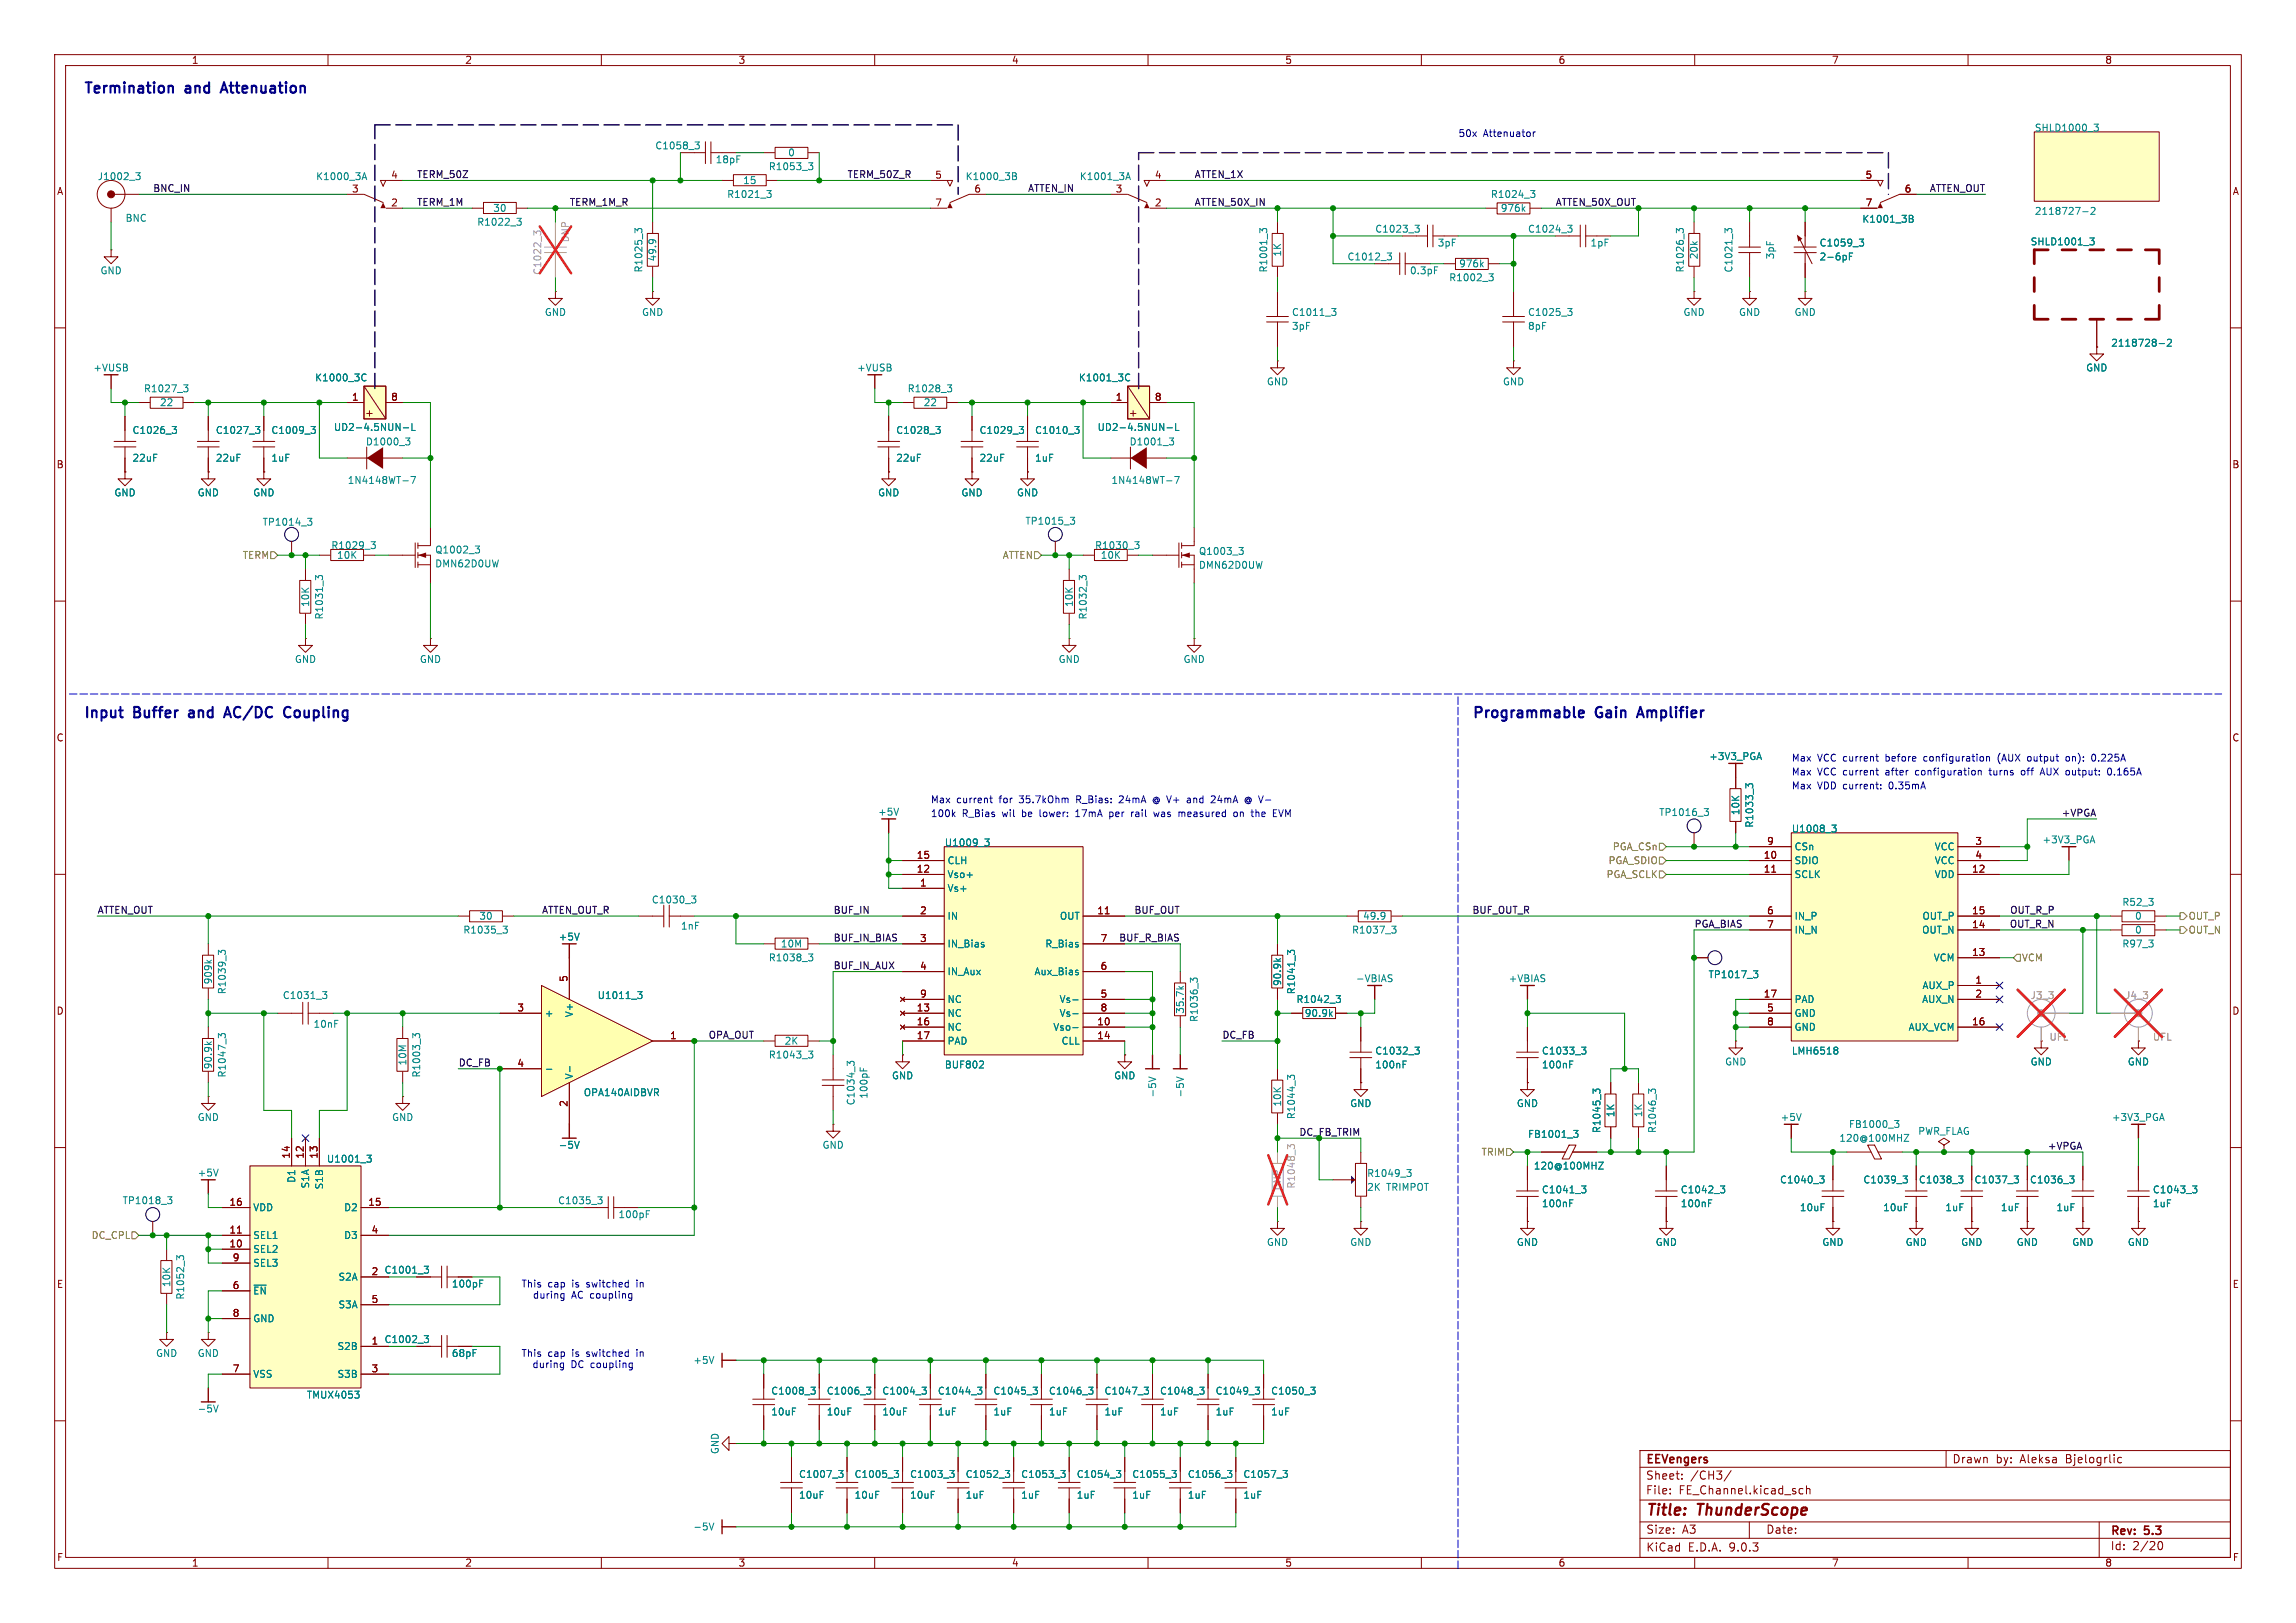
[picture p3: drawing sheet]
<svg xmlns="http://www.w3.org/2000/svg" width="420mm" height="297mm" viewBox="0 0 420 297" stroke-linecap="round" stroke-linejoin="round" font-family="sans-serif">
<defs><g id="words">
<g font-size="2.8" fill="#840000">
<text x="301" y="277.9">Title:</text>
<text x="310.6" y="277.9">ThunderScope</text>
</g>
<g font-size="2.7" fill="#0000c2">
<text x="15.2" y="18">Termination</text>
<text x="34.1" y="18">and</text>
<text x="41.4" y="18">Attenuation</text>
<text x="15.2" y="132.3">Input</text>
<text x="24.6" y="132.3">Buffer</text>
<text x="35.5" y="132.3">and</text>
<text x="42.8" y="132.3">AC/DC</text>
<text x="54.4" y="132.3">Coupling</text>
<text x="269.2" y="132.3">Programmable</text>
<text x="292" y="132.3">Gain</text>
<text x="300.5" y="132.3">Amplifier</text>
</g>
<g font-size="2.1" fill="#840000">
<text x="301" y="268.2">EEVengers</text>
<text x="357.1" y="268">Drawn</text>
<text x="365.1" y="268">by:</text>
<text x="369.6" y="268">Aleksa</text>
<text x="378" y="268">Bjelogrlic</text>
<text x="301" y="273.7">File:</text>
<text x="301" y="271">Sheet:</text>
<text x="307.1" y="273.7">FE_Channel.kicad_sch</text>
<text x="309.2" y="271">/CH3/</text>
<text x="301" y="280.9">Size:</text>
<text x="307.7" y="280.9">A3</text>
<text x="323" y="280.9">Date:</text>
<text x="386" y="281.3">Rev:</text>
<text x="392.4" y="281.3">5.3</text>
<text x="301" y="284.1">KiCad</text>
<text x="308.8" y="284.1">E.D.A.</text>
<text x="316.4" y="284.1">9.0.3</text>
<text x="386" y="283.9">Id:</text>
<text x="390.1" y="283.9">2/20</text>
</g>
<g font-size="1.8" fill="#840000">
<text x="35" y="11.9">1</text>
<text x="85" y="11.9">2</text>
<text x="135" y="11.9">3</text>
<text x="185" y="11.9">4</text>
<text x="235" y="11.9">5</text>
<text x="285" y="11.9">6</text>
<text x="335" y="11.9">7</text>
<text x="385" y="11.9">8</text>
<text x="10.3" y="35.9">A</text>
<text x="64.3" y="35.3">3</text>
<text x="71.5" y="32.8">4</text>
<text x="171" y="32.8">5</text>
<text x="178.1" y="35.3">6</text>
<text x="204" y="35.3">3</text>
<text x="211.2" y="32.8">4</text>
<text x="341.2" y="32.8">5</text>
<text x="348.3" y="35.3">6</text>
<text x="408.3" y="35.9">A</text>
<text x="71.5" y="37.8">2</text>
<text x="171" y="37.8">7</text>
<text x="211.2" y="37.8">2</text>
<text x="341.2" y="37.8">7</text>
<text x="64.3" y="73.4">1</text>
<text x="71.5" y="73.4">8</text>
<text x="204" y="73.4">1</text>
<text x="211.2" y="73.4">8</text>
<text x="10.3" y="85.9">B</text>
<text x="408.2" y="85.9">B</text>
<text x="10.3" y="135.9">C</text>
<text x="408.2" y="135.9">C</text>
<text x="323.1" y="154.7">9</text>
<text x="361.2" y="154.7">3</text>
<text x="167.6" y="157.2">15</text>
<text x="167.6" y="159.8">12</text>
<text x="322.5" y="157.2">10</text>
<text x="322.5" y="159.8">11</text>
<text x="360.6" y="159.8">12</text>
<text x="361.2" y="157.2">4</text>
<text x="168.2" y="162.3">1</text>
<text x="168.2" y="167.4">2</text>
<text x="200.6" y="167.4">11</text>
<text x="323.1" y="167.4">6</text>
<text x="360.6" y="167.4">15</text>
<text x="168.2" y="172.5">3</text>
<text x="201.2" y="172.5">7</text>
<text x="323.1" y="169.9">7</text>
<text x="360.6" y="169.9">14</text>
<text x="103.9" y="179.8" transform="rotate(-90 103.9 179.8)">5</text>
<text x="168.2" y="177.5">4</text>
<text x="201.2" y="177.5">6</text>
<text x="360.6" y="175">13</text>
<text x="10.3" y="185.9">D</text>
<text x="94.5" y="185.2">3</text>
<text x="167.6" y="185.2">13</text>
<text x="168.2" y="182.6">9</text>
<text x="201.2" y="182.6">5</text>
<text x="201.2" y="185.2">8</text>
<text x="322.5" y="182.6">17</text>
<text x="323.1" y="185.2">5</text>
<text x="361.2" y="180.1">1</text>
<text x="361.2" y="182.6">2</text>
<text x="408.2" y="185.9">D</text>
<text x="122.5" y="190.2">1</text>
<text x="167.6" y="187.7">16</text>
<text x="167.6" y="190.2">17</text>
<text x="200.6" y="187.7">10</text>
<text x="200.6" y="190.2">14</text>
<text x="323.1" y="187.7">8</text>
<text x="360.6" y="187.7">16</text>
<text x="94.5" y="195.3">4</text>
<text x="103.9" y="202.6" transform="rotate(-90 103.9 202.6)">2</text>
<text x="53.1" y="212.1" transform="rotate(-90 53.1 212.1)">14</text>
<text x="55.6" y="212.1" transform="rotate(-90 55.6 212.1)">12</text>
<text x="58.2" y="212.1" transform="rotate(-90 58.2 212.1)">13</text>
<text x="41.9" y="220.7">16</text>
<text x="67.3" y="220.7">15</text>
<text x="41.9" y="225.8">11</text>
<text x="67.9" y="225.8">4</text>
<text x="41.9" y="228.3">10</text>
<text x="42.5" y="230.9">9</text>
<text x="67.9" y="233.4">2</text>
<text x="10.3" y="235.9">E</text>
<text x="42.5" y="236">6</text>
<text x="67.9" y="238.5">5</text>
<text x="408.3" y="235.9">E</text>
<text x="42.5" y="241">8</text>
<text x="42.5" y="251.2">7</text>
<text x="67.9" y="246.1">1</text>
<text x="67.9" y="251.2">3</text>
<text x="10.3" y="285.9">F</text>
<text x="35" y="286.9">1</text>
<text x="85" y="286.9">2</text>
<text x="135" y="286.9">3</text>
<text x="185" y="286.9">4</text>
<text x="235" y="286.9">5</text>
<text x="285" y="286.9">6</text>
<text x="335" y="286.9">7</text>
<text x="385" y="286.9">8</text>
<text x="408.3" y="285.9">F</text>
</g>
<g font-size="1.8" fill="#008484">
<text x="119.8" y="27.5">C1058_3</text>
<text x="144.1" y="28.8">0</text>
<text x="372.1" y="24.3">SHLD1000_3</text>
<text x="17.8" y="33.2">J1002_3</text>
<text x="57.7" y="33.2">K1000_3A</text>
<text x="130.8" y="30.1">18pF</text>
<text x="135.8" y="33.9">15</text>
<text x="140.5" y="31.3">R1053_3</text>
<text x="176.5" y="33.2">K1000_3B</text>
<text x="197.4" y="33.2">K1001_3A</text>
<text x="22.9" y="40.8">BNC</text>
<text x="87.2" y="41.5">R1022_3</text>
<text x="90.1" y="39">30</text>
<text x="132.9" y="36.4">R1021_3</text>
<text x="272.6" y="36.4">R1024_3</text>
<text x="274.4" y="39">976k</text>
<text x="340.6" y="41">K1001_3B</text>
<text x="372.1" y="39.5">2118727-2</text>
<text x="120.2" y="47.9" transform="rotate(-90 120.2 47.9)">49.9</text>
<text x="234.5" y="47.1" transform="rotate(-90 234.5 47.1)">1K</text>
<text x="246.4" y="47.9">C1012_3</text>
<text x="251.5" y="42.8">C1023_3</text>
<text x="262.9" y="45.3">3pF</text>
<text x="279.4" y="42.8">C1024_3</text>
<text x="290.8" y="45.3">1pF</text>
<text x="310.7" y="47.5" transform="rotate(-90 310.7 47.5)">20k</text>
<text x="324.7" y="47.5" transform="rotate(-90 324.7 47.5)">3pF</text>
<text x="332.7" y="45.3">C1059_3</text>
<text x="332.7" y="47.9">2-6pF</text>
<text x="371.4" y="45.1">SHLD1001_3</text>
<text x="18.3" y="50.4">GND</text>
<text x="117.7" y="50" transform="rotate(-90 117.7 50)">R1025_3</text>
<text x="232" y="50" transform="rotate(-90 232 50)">R1001_3</text>
<text x="257.8" y="50.4">0.3pF</text>
<text x="265" y="51.7">R1002_3</text>
<text x="266.8" y="49.1">976k</text>
<text x="308.2" y="50" transform="rotate(-90 308.2 50)">R1026_3</text>
<text x="317.1" y="50" transform="rotate(-90 317.1 50)">C1021_3</text>
<text x="99.6" y="58">GND</text>
<text x="117.3" y="58">GND</text>
<text x="236.2" y="58">C1011_3</text>
<text x="279.4" y="58">C1025_3</text>
<text x="307.8" y="58">GND</text>
<text x="318" y="58">GND</text>
<text x="328.2" y="58">GND</text>
<text x="236.2" y="60.6">3pF</text>
<text x="279.4" y="60.6">8pF</text>
<text x="386.1" y="63.6">2118728-2</text>
<text x="17" y="68.2">+VUSB</text>
<text x="26.2" y="72">R1027_3</text>
<text x="57.5" y="70">K1000_3C</text>
<text x="156.7" y="68.2">+VUSB</text>
<text x="165.9" y="72">R1028_3</text>
<text x="197.2" y="70">K1001_3C</text>
<text x="231.6" y="70.7">GND</text>
<text x="274.8" y="70.7">GND</text>
<text x="381.5" y="68.2">GND</text>
<text x="29.2" y="74.5">22</text>
<text x="168.9" y="74.5">22</text>
<text x="24.1" y="79.6">C1026_3</text>
<text x="39.4" y="79.6">C1027_3</text>
<text x="49.5" y="79.6">C1009_3</text>
<text x="61" y="79.1">UD2-4.5NUN-L</text>
<text x="66.8" y="81.7">D1000_3</text>
<text x="163.8" y="79.6">C1028_3</text>
<text x="179.1" y="79.6">C1029_3</text>
<text x="189.2" y="79.6">C1010_3</text>
<text x="200.7" y="79.1">UD2-4.5NUN-L</text>
<text x="206.5" y="81.7">D1001_3</text>
<text x="24.1" y="84.7">22uF</text>
<text x="39.4" y="84.7">22uF</text>
<text x="49.5" y="84.7">1uF</text>
<text x="63.5" y="88.8">1N4148WT-7</text>
<text x="163.8" y="84.7">22uF</text>
<text x="179.1" y="84.7">22uF</text>
<text x="189.2" y="84.7">1uF</text>
<text x="203.2" y="88.8">1N4148WT-7</text>
<text x="20.8" y="91">GND</text>
<text x="36.1" y="91">GND</text>
<text x="46.2" y="91">GND</text>
<text x="160.5" y="91">GND</text>
<text x="175.8" y="91">GND</text>
<text x="185.9" y="91">GND</text>
<text x="47.9" y="96.4">TP1014_3</text>
<text x="60.5" y="100.7">R1029_3</text>
<text x="79.5" y="101.5">Q1002_3</text>
<text x="187.5" y="96.2">TP1015_3</text>
<text x="200.2" y="100.7">R1030_3</text>
<text x="219.2" y="101.7">Q1003_3</text>
<text x="61.6" y="102.5">10K</text>
<text x="79.5" y="104">DMN62D0UW</text>
<text x="201.3" y="102.5">10K</text>
<text x="219.2" y="104.3">DMN62D0UW</text>
<text x="56.7" y="111.2" transform="rotate(-90 56.7 111.2)">10K</text>
<text x="59.3" y="113.5" transform="rotate(-90 59.3 113.5)">R1031_3</text>
<text x="196.4" y="111.2" transform="rotate(-90 196.4 111.2)">10K</text>
<text x="199" y="113.5" transform="rotate(-90 199 113.5)">R1032_3</text>
<text x="53.8" y="121.5">GND</text>
<text x="76.7" y="121.5">GND</text>
<text x="193.5" y="121.5">GND</text>
<text x="216.4" y="121.5">GND</text>
<text x="312.6" y="139.3">+3V3_PGA</text>
<text x="160.5" y="149.5">+5V</text>
<text x="303.4" y="149.5">TP1016_3</text>
<text x="318.4" y="149.3" transform="rotate(-90 318.4 149.3)">10K</text>
<text x="172.7" y="155.1">U1009_3</text>
<text x="320.9" y="151.6" transform="rotate(-90 320.9 151.6)">R1033_3</text>
<text x="327.7" y="152.5">U1008_3</text>
<text x="328.2" y="155.8">CSn</text>
<text x="353.8" y="155.8">VCC</text>
<text x="373.5" y="154.5">+3V3_PGA</text>
<text x="173.2" y="158.3">CLH</text>
<text x="173.2" y="160.9">Vso+</text>
<text x="328.2" y="158.3">SDIO</text>
<text x="328.2" y="160.9">SCLK</text>
<text x="353.8" y="158.3">VCC</text>
<text x="353.8" y="160.9">VDD</text>
<text x="119.1" y="165.5">C1030_3</text>
<text x="173.2" y="163.4">Vs+</text>
<text x="388.1" y="166">R52_3</text>
<text x="84.7" y="171">R1035_3</text>
<text x="87.6" y="168.5">30</text>
<text x="102.1" y="172.3">+5V</text>
<text x="124.5" y="170.3">1nF</text>
<text x="142.7" y="173.6">10M</text>
<text x="173.2" y="168.5">IN</text>
<text x="173.2" y="173.6">IN_Bias</text>
<text x="191.1" y="173.6">R_Bias</text>
<text x="193.8" y="168.5">OUT</text>
<text x="247.2" y="171">R1037_3</text>
<text x="249.2" y="168.5">49.9</text>
<text x="328.2" y="168.5">IN_P</text>
<text x="328.2" y="171">IN_N</text>
<text x="351.5" y="171">OUT_N</text>
<text x="351.6" y="168.5">OUT_P</text>
<text x="388.1" y="173.6">R97_3</text>
<text x="390.5" y="168.5">0</text>
<text x="390.5" y="171">0</text>
<text x="140.5" y="176.1">R1038_3</text>
<text x="173.2" y="178.7">IN_Aux</text>
<text x="189.1" y="178.7">Aux_Bias</text>
<text x="247.9" y="179.9">-VBIAS</text>
<text x="275.9" y="179.9">+VBIAS</text>
<text x="312.4" y="179.2">TP1017_3</text>
<text x="353.6" y="176.1">VCM</text>
<text x="39" y="180.2" transform="rotate(-90 39 180.2)">909k</text>
<text x="41.5" y="182" transform="rotate(-90 41.5 182)">R1039_3</text>
<text x="51.6" y="183">C1031_3</text>
<text x="109.2" y="183">U1011_3</text>
<text x="173.2" y="183.7">NC</text>
<text x="193.7" y="183.7">Vs-</text>
<text x="216.8" y="185.6" transform="rotate(-90 216.8 185.6)">35.7k</text>
<text x="234.5" y="180.5" transform="rotate(-90 234.5 180.5)">90.9k</text>
<text x="237.1" y="183.7">R1042_3</text>
<text x="237.1" y="182" transform="rotate(-90 237.1 182)">R1041_3</text>
<text x="328.2" y="183.7">PAD</text>
<text x="351.5" y="183.7">AUX_N</text>
<text x="351.6" y="181.2">AUX_P</text>
<text x="57.3" y="188.3">10nF</text>
<text x="99.6" y="186.3">+</text>
<text x="105" y="186.3" transform="rotate(-90 105 186.3)">V+</text>
<text x="143.4" y="191.4">2K</text>
<text x="173.2" y="186.3">NC</text>
<text x="173.2" y="188.8">NC</text>
<text x="173.2" y="191.4">PAD</text>
<text x="192.6" y="188.8">Vso-</text>
<text x="193.7" y="186.3">Vs-</text>
<text x="194.1" y="191.4">CLL</text>
<text x="219.3" y="187.1" transform="rotate(-90 219.3 187.1)">R1036_3</text>
<text x="238.6" y="186.3">90.9k</text>
<text x="328.2" y="186.3">GND</text>
<text x="328.2" y="188.8">GND</text>
<text x="349" y="188.8">AUX_VCM</text>
<text x="39" y="195.8" transform="rotate(-90 39 195.8)">90.9k</text>
<text x="41.5" y="197.3" transform="rotate(-90 41.5 197.3)">R1047_3</text>
<text x="74.5" y="195.1" transform="rotate(-90 74.5 195.1)">10M</text>
<text x="77.1" y="197.3" transform="rotate(-90 77.1 197.3)">R1003_3</text>
<text x="105" y="197.6" transform="rotate(-90 105 197.6)">V-</text>
<text x="140.5" y="193.9">R1043_3</text>
<text x="163.1" y="197.7">GND</text>
<text x="172.7" y="195.7">BUF802</text>
<text x="203.7" y="197.7">GND</text>
<text x="251.5" y="193.2">C1032_3</text>
<text x="251.5" y="195.7">100nF</text>
<text x="281.9" y="193.2">C1033_3</text>
<text x="281.9" y="195.7">100nF</text>
<text x="315.5" y="195.2">GND</text>
<text x="327.7" y="193.2">LMH6518</text>
<text x="371.3" y="195.2">GND</text>
<text x="389.1" y="195.2">GND</text>
<text x="106.7" y="200.8">OPA140AIDBVR</text>
<text x="156.5" y="202.4" transform="rotate(-90 156.5 202.4)">C1034_3</text>
<text x="158.9" y="201.2" transform="rotate(-90 158.9 201.2)">100pF</text>
<text x="211.7" y="200.9" transform="rotate(-90 211.7 200.9)">-5V</text>
<text x="216.8" y="200.9" transform="rotate(-90 216.8 200.9)">-5V</text>
<text x="234.5" y="202.6" transform="rotate(-90 234.5 202.6)">10K</text>
<text x="246.9" y="202.8">GND</text>
<text x="277.4" y="202.8">GND</text>
<text x="36.1" y="205.3">GND</text>
<text x="71.6" y="205.3">GND</text>
<text x="237.1" y="204.9" transform="rotate(-90 237.1 204.9)">R1044_3</text>
<text x="279.4" y="208.4">FB1001_3</text>
<text x="293" y="207.4" transform="rotate(-90 293 207.4)">R1045_3</text>
<text x="295.5" y="204.5" transform="rotate(-90 295.5 204.5)">1K</text>
<text x="300.6" y="204.5" transform="rotate(-90 300.6 204.5)">1K</text>
<text x="303.1" y="207.4" transform="rotate(-90 303.1 207.4)">R1046_3</text>
<text x="325.6" y="205.3">+5V</text>
<text x="336.4" y="209.1">120@100MHZ</text>
<text x="338.1" y="206.6">FB1000_3</text>
<text x="350.8" y="207.9">PWR_FLAG</text>
<text x="386.2" y="205.3">+3V3_PGA</text>
<text x="36.1" y="215.5">+5V</text>
<text x="59.7" y="213">U1001_3</text>
<text x="102.1" y="210.4">-5V</text>
<text x="150.4" y="210.4">GND</text>
<text x="250" y="215.6">R1049_3</text>
<text x="280.5" y="214.2">120@100MHZ</text>
<text x="22.3" y="220.6">TP1018_3</text>
<text x="46.2" y="221.8">VDD</text>
<text x="54.2" y="216.6" transform="rotate(-90 54.2 216.6)">D1</text>
<text x="56.7" y="217.6" transform="rotate(-90 56.7 217.6)">S1A</text>
<text x="59.3" y="217.8" transform="rotate(-90 59.3 217.8)">S1B</text>
<text x="62.8" y="221.8">D2</text>
<text x="102" y="220.6">C1035_3</text>
<text x="250" y="218.1">2K</text>
<text x="253.6" y="218.1">TRIMPOT</text>
<text x="281.9" y="218.6">C1041_3</text>
<text x="281.9" y="221.1">100nF</text>
<text x="307.3" y="218.6">C1042_3</text>
<text x="307.3" y="221.1">100nF</text>
<text x="325.5" y="216.8">C1040_3</text>
<text x="329.1" y="221.8">10uF</text>
<text x="340.8" y="216.8">C1039_3</text>
<text x="344.4" y="221.8">10uF</text>
<text x="350.9" y="216.8">C1038_3</text>
<text x="355.8" y="221.8">1uF</text>
<text x="361.1" y="216.8">C1037_3</text>
<text x="365.9" y="221.8">1uF</text>
<text x="371.2" y="216.8">C1036_3</text>
<text x="376.1" y="221.8">1uF</text>
<text x="393.7" y="218.6">C1043_3</text>
<text x="393.7" y="221.1">1uF</text>
<text x="46.2" y="226.9">SEL1</text>
<text x="62.8" y="226.9">D3</text>
<text x="113" y="223.1">100pF</text>
<text x="46.2" y="229.5">SEL2</text>
<text x="46.2" y="232">SEL3</text>
<text x="70.2" y="233.3">C1001_3</text>
<text x="231.6" y="228.2">GND</text>
<text x="246.9" y="228.2">GND</text>
<text x="277.4" y="228.2">GND</text>
<text x="302.8" y="228.2">GND</text>
<text x="333.2" y="228.2">GND</text>
<text x="348.5" y="228.2">GND</text>
<text x="358.6" y="228.2">GND</text>
<text x="368.8" y="228.2">GND</text>
<text x="379" y="228.2">GND</text>
<text x="389.1" y="228.2">GND</text>
<text x="31.3" y="235.6" transform="rotate(-90 31.3 235.6)">10K</text>
<text x="33.9" y="237.9" transform="rotate(-90 33.9 237.9)">R1052_3</text>
<text x="46.2" y="237.1">~{EN}</text>
<text x="61.8" y="234.5">S2A</text>
<text x="61.8" y="239.6">S3A</text>
<text x="82.6" y="235.8">100pF</text>
<text x="46.2" y="242.2">GND</text>
<text x="70.2" y="246">C1002_3</text>
<text x="28.4" y="248.5">GND</text>
<text x="36.1" y="248.5">GND</text>
<text x="61.6" y="247.2">S2B</text>
<text x="82.6" y="248.5">68pF</text>
<text x="126.7" y="249.8">+5V</text>
<text x="46.2" y="252.3">VSS</text>
<text x="56" y="256.1">TMUX4053</text>
<text x="61.6" y="252.3">S3B</text>
<text x="141" y="255.4">C1008_3</text>
<text x="151.1" y="255.4">C1006_3</text>
<text x="161.3" y="255.4">C1004_3</text>
<text x="171.5" y="255.4">C1044_3</text>
<text x="181.6" y="255.4">C1045_3</text>
<text x="191.8" y="255.4">C1046_3</text>
<text x="201.9" y="255.4">C1047_3</text>
<text x="212.1" y="255.4">C1048_3</text>
<text x="222.3" y="255.4">C1049_3</text>
<text x="232.4" y="255.4">C1050_3</text>
<text x="36.1" y="258.7">-5V</text>
<text x="141" y="259.2">10uF</text>
<text x="151.1" y="259.2">10uF</text>
<text x="161.3" y="259.2">10uF</text>
<text x="171.5" y="259.2">1uF</text>
<text x="181.6" y="259.2">1uF</text>
<text x="191.8" y="259.2">1uF</text>
<text x="201.9" y="259.2">1uF</text>
<text x="212.1" y="259.2">1uF</text>
<text x="222.3" y="259.2">1uF</text>
<text x="232.4" y="259.2">1uF</text>
<text x="131.7" y="266.2" transform="rotate(-90 131.7 266.2)">GND</text>
<text x="146.1" y="270.6">C1007_3</text>
<text x="146.1" y="274.5">10uF</text>
<text x="156.2" y="270.6">C1005_3</text>
<text x="156.2" y="274.5">10uF</text>
<text x="166.4" y="270.6">C1003_3</text>
<text x="166.4" y="274.5">10uF</text>
<text x="176.5" y="270.6">C1052_3</text>
<text x="176.5" y="274.5">1uF</text>
<text x="186.7" y="270.6">C1053_3</text>
<text x="186.7" y="274.5">1uF</text>
<text x="196.9" y="270.6">C1054_3</text>
<text x="196.9" y="274.5">1uF</text>
<text x="207" y="270.6">C1055_3</text>
<text x="207" y="274.5">1uF</text>
<text x="217.2" y="270.6">C1056_3</text>
<text x="217.2" y="274.5">1uF</text>
<text x="227.3" y="270.6">C1057_3</text>
<text x="227.3" y="274.5">1uF</text>
<text x="126.7" y="280.3">-5V</text>
</g>
<g font-size="1.8" fill="#0000c2">
<text x="266.7" y="25.2">50x</text>
<text x="271.3" y="25.2">Attenuator</text>
<text x="327.7" y="142">Max</text>
<text x="327.7" y="139.5">Max</text>
<text x="332.5" y="142">VCC current</text>
<text x="332.5" y="139.5">VCC current</text>
<text x="345.3" y="142">after</text>
<text x="345.3" y="139.5">before</text>
<text x="350.9" y="142">configuration</text>
<text x="352.4" y="139.5">configuration</text>
<text x="364.7" y="142">turns</text>
<text x="366.2" y="139.5">(AUX</text>
<text x="370.7" y="142">off</text>
<text x="371.9" y="139.5">output</text>
<text x="374.5" y="142">AUX output:</text>
<text x="379.1" y="139.5">on):</text>
<text x="384" y="139.5">0.225A</text>
<text x="387.2" y="142">0.165A</text>
<text x="170.2" y="149.6">100k</text>
<text x="170.2" y="147.1">Max</text>
<text x="175" y="147.1">current</text>
<text x="176" y="149.6">R_Bias</text>
<text x="183" y="147.1">for</text>
<text x="183.5" y="149.6">wil</text>
<text x="186.8" y="147.1">35.7kOhm</text>
<text x="187.3" y="149.6">be</text>
<text x="190.7" y="149.6">lower:</text>
<text x="197.4" y="147.1">R_Bias:</text>
<text x="197.5" y="149.6">17mA</text>
<text x="203.9" y="149.6">per</text>
<text x="205.5" y="147.1">24mA</text>
<text x="208.1" y="149.6">rail</text>
<text x="211.9" y="147.1">@ V+</text>
<text x="212.5" y="149.6">was</text>
<text x="217.2" y="149.6">measured</text>
<text x="218.6" y="147.1">and</text>
<text x="223.2" y="147.1">24mA</text>
<text x="227.6" y="149.6">on</text>
<text x="229.6" y="147.1">@ V-</text>
<text x="231" y="149.6">the</text>
<text x="235.2" y="149.6">EVM</text>
<text x="327.7" y="144.5">Max</text>
<text x="332.5" y="144.5">VDD current:</text>
<text x="345.9" y="144.5">0.35mA</text>
<text x="95.3" y="235.8">This</text>
<text x="97.4" y="237.9">during</text>
<text x="100.2" y="235.8">cap</text>
<text x="104.5" y="237.9">AC coupling</text>
<text x="104.8" y="235.8">is</text>
<text x="107.6" y="235.8">switched</text>
<text x="116.9" y="235.8">in</text>
<text x="95.3" y="248.5">This</text>
<text x="97.3" y="250.6">during</text>
<text x="100.2" y="248.5">cap</text>
<text x="104.5" y="250.6">DC coupling</text>
<text x="104.8" y="248.5">is</text>
<text x="107.6" y="248.5">switched</text>
<text x="116.9" y="248.5">in</text>
</g>
<g font-size="1.8">
<text x="27.9" y="35.2">BNC_IN</text>
<text x="76.2" y="32.7">TERM_50Z</text>
<text x="154.9" y="32.7">TERM_50Z_R</text>
<text x="188" y="35.2">ATTEN_IN</text>
<text x="218.4" y="32.7">ATTEN_1X</text>
<text x="352.9" y="35.2">ATTEN_OUT</text>
<text x="76.2" y="37.8">TERM_1M</text>
<text x="104.1" y="37.8">TERM_1M_R</text>
<text x="218.4" y="37.8">ATTEN_50X_IN</text>
<text x="284.5" y="37.8">ATTEN_50X_OUT</text>
<text x="377" y="149.5">+VPGA</text>
<text x="17.8" y="167.3">ATTEN_OUT</text>
<text x="99.1" y="167.3">ATTEN_OUT_R</text>
<text x="152.4" y="167.3">BUF_IN</text>
<text x="207.4" y="167.3">BUF_OUT</text>
<text x="269.2" y="167.3">BUF_OUT_R</text>
<text x="367.6" y="167.3">OUT_R_P</text>
<text x="152.4" y="172.4">BUF_IN_BIAS</text>
<text x="204.6" y="172.4">BUF_R_BIAS</text>
<text x="309.9" y="169.8">PGA_BIAS</text>
<text x="367.6" y="169.8">OUT_R_N</text>
<text x="152.4" y="177.5">BUF_IN_AUX</text>
<text x="129.5" y="190.2">OPA_OUT</text>
<text x="223.5" y="190.2">DC_FB</text>
<text x="83.8" y="195.2">DC_FB</text>
<text x="374.5" y="210.5">+VPGA</text>
</g>
<g font-size="1.8" fill="#a1a1a1">
<text x="104.3" y="44.4" transform="rotate(-90 104.3 44.4)">DNP</text>
<text x="99.2" y="50.4" transform="rotate(-90 99.2 50.4)">C1022_3</text>
<text x="371.4" y="183">J3_3</text>
<text x="388.6" y="183">J4_3</text>
<text x="374.8" y="190.6">UFL</text>
<text x="393.7" y="190.6">UFL</text>
<text x="234.5" y="217.9" transform="rotate(-90 234.5 217.9)">DNP</text>
<text x="237.1" y="217.6" transform="rotate(-90 237.1 217.6)">R1048_3</text>
</g>
<g font-size="1.8" fill="#848400">
<text x="44.3" y="102.5">TERM</text>
<text x="183.3" y="102.5">ATTEN</text>
<text x="294.9" y="155.8">PGA_CSn</text>
<text x="293.8" y="160.9">PGA_SCLK</text>
<text x="294.1" y="158.3">PGA_SDIO</text>
<text x="400.2" y="171">OUT_N</text>
<text x="400.2" y="168.5">OUT_P</text>
<text x="369.8" y="176.1">VCM</text>
<text x="270.9" y="211.7">TRIM</text>
<text x="16.7" y="226.9">DC_CPL</text>
</g>
<text font-size="1.8" fill="#008400" x="237.6" y="207.9">DC_FB_TRIM</text>
</g></defs>
<path d="M0 0h420v297h-420z" fill="#fff" stroke="#fff" stroke-width=".18"/>
<g fill="none" stroke="#840000" stroke-width=".18">
<path d="M10 10h400v277h-400zM12 12h396v273h-396zM60 10v2M110 10v2M160 10v2M210 10v2M260 10v2M310 10v2M360 10v2M66.6 35.6l3.5 1.5M10 60h2M22.9 76.2v4.6"/>
<path d="M165.1 73.7h2M167.2 72.7h6v2h-6zM173.3 73.7h2M408 60h2M20.9 80.8h4M20.9 81.8h4M22.9 81.8v4.6M10 110h2M408 110h2M10 160h2M408 160h2M10 210h2"/>
<path d="M73.7 200.7v1.2h1.2l-1.2 1.3-1.3-1.3h1.3M73.7 200.7h.1M408 210h2M10 260h2M300 265.4h108v19.6h-108zM300 278.5h108M300 274.5h108M300 268.5h108M305.5 273.2v.2M305.5 272.5v.1M307.7 270.5v.2M307.7 269.8v.1"/>
<path d="M316.7 269.1l-1.3 1.9M320 278.5v3M329.1 273.1l.3 .3 .4-.1M329.8 272.5l-.4-.1-.3 .3M330.4 272.5l.3-.1 .3 .1 .1 .9M330.4 271.9v1.5M356 265.4v3.1M384 278.5v6.5M388.1 266.8l-.4-.1-.3 .3v.4l.1 .2h.6M408 260h2M60 285v2M110 285v2"/>
<path d="M160 285v2M210 285v2M260 285v2M300 281.5h108M310 285v2M360 285v2M394.7 282.7l.2-.5 .2-.1a.8 .8 0 0 1 .5 .7 .8 .8 0 0 1-.5 .8l-.2-.2-.2-.4"/>
</g>
<path d="M31.5 78h.8l-.4 .5 .3 .2 .1 .4-.3 .2h-.3M173.3 70.4h.8l-.4 .5 .3 .1 .1 .5-.3 .2h-.3" fill="none" stroke="#008484" stroke-width=".18"/>
<path d="M20.3 68.6v2.5" fill="none" stroke="#840000" stroke-width=".25"/>
<path d="M70.1 37.1l.5 1h-1z" fill="#840000"/>
<g fill="none" stroke="#840000" stroke-width=".18">
<path d="M20.3 35.6h5.1M20.3 38.1v2.5M63.5 35.6h3M69.6 33h1l-.5 1.1zM70.7 33h3M70.7 38.1h3M20.3 45.7v1.3h1.3l-1.3 1.3-1.3-1.3h1.3M20.3 45.7h.1M162.6 76.2v4.6M177.8 76.2v4.6M160.6 80.8h4M160.6 81.8h4"/>
<path d="M162.6 81.8v4.6M175.8 80.8h4M175.8 81.8h4M177.8 81.8v4.6"/>
<circle cx="20.3" cy="35.6" r="2.54"/>
</g>
<path d="M24.8 31.6h.8l-.4 .5 .4 .1v.4l-.2 .3h-.4M66.2 32.9l.5-1.3 .4 1.3M66.4 32.5h.6M171.2 78h.8l-.4 .5 .3 .2 .1 .4-.3 .2h-.3M186.4 78h.8l-.4 .5 .4 .2v.4l-.2 .2h-.4" fill="none" stroke="#008484" stroke-width=".18"/>
<circle cx="20.3" cy="35.6" r=".63" fill="#840000" stroke="#840000" stroke-width=".18"/>
<path d="M206.3 70.7h4v6h-4z" fill="#ffffc2"/>
<g fill="none" stroke="#840000" stroke-width=".18">
<path d="M206.3 35.6l3.5 1.5M188 76.2v4.6M203.2 73.7h3M206.3 70.7h4v6h-4zM206.3 70.7l4 6M206.8 75.7h1M207.3 75.2v1M210.4 73.7h3M186 80.8h4M186 81.8h4M188 81.8v4.6M139.7 190.5h2"/>
<path d="M141.8 189.4h6v2.1h-6zM147.9 190.5h2"/>
</g>
<path d="M206.3 70.7h4v6h-4z" fill="none" stroke="#800000" stroke-width=".18"/>
<path d="M196.6 78h.8l-.4 .5 .3 .2 .1 .4-.3 .2h-.3M206.1 68.5l.3-.1 .3 .2M206.7 69.6l-.3 .1-.3-.1M213.5 78.3h.9M215.1 77.5v1.3h.6M147.9 192.3h.8l-.4 .5 .3 .2 .1 .4-.3 .2h-.3" fill="none" stroke="#008484" stroke-width=".18"/>
<path d="M209.8 37.1l.5 1h-1z" fill="#840000"/>
<path d="M203.2 35.6h3M209.3 33h1l-.5 1.1zM210.4 33h3M210.4 38.1h3M206.8 81.8v4" fill="none" stroke="#840000" stroke-width=".18"/>
<path d="M205.9 32.9l.5-1.3 .4 1.3M206.1 32.5h.6" fill="none" stroke="#008484" stroke-width=".18"/>
<path d="M206.8 83.8l3-2v4z" fill="#840000"/>
<g fill="none" stroke="#840000" stroke-width=".18">
<path d="M86.4 38.1h2M88.4 37h6v2.1h-6zM94.5 38.1h2M101.6 53.3v1.3h1.3l-1.3 1.3-1.3-1.3h1.3M101.6 53.3h.1M231.7 57.9h4M231.7 58.9h4M232.7 42.7h2v6h-2zM233.7 40.6v2M233.7 48.8v2M233.7 53.3v4.6M233.7 58.9v4.6"/>
<path d="M254 48.3h2M256 46.3v4M257 48.3h4.6M257 46.3v4M233.7 66v1.3h1.2l-1.2 1.3-1.3-1.3h1.3M233.7 66h.1M38.1 86.4v1.2h1.3l-1.3 1.3-1.3-1.3h1.3M38.1 86.4h.1M203.2 83.8h3.8M209.5 83.8h3.9M37 174.8h2.1v6h-2.1zM38.1 172.7v2"/>
<path d="M83.8 167.6h2M85.9 166.7h6v2h-6zM92 167.6h2M38.1 180.9v2M246.9 192.5h4M246.9 193.5h4M248.9 188v4.5M248.9 193.5v4.6M111.3 219v4M112.3 219v4M243.8 215.9h4.1M247.9 212.9h2.1v6h-2.1z"/>
<path d="M248.9 210.8v2M248.9 219v2M109.2 221h2.1M112.3 221h4.5"/>
</g>
<g fill="none" stroke="#008484" stroke-width=".18">
<path d="M94.6 39.9h.7l-.4 .5 .4 .2v.4l-.2 .2h-.4M231.7 42.4v-.3l-.2-.3-.4 .1-.2 .3-.5-.4v.8M243.6 56.5h.8l-.4 .4 .3 .2 .1 .4-.3 .2h-.3M253.7 46.3h.8l-.4 .5 .4 .1v.4l-.2 .3h-.4M262.4 48.8h.6M213.4 88h1M213.9 80.2h.8l-.4 .4 .3 .2 .1 .4-.3 .2h-.3M214.9 87.2h.8l-.5 1.3M37.8 175.7l.5 .5M38.7 175.7l-.5 .4M41.2 174.5v-.4l-.2-.2-.4 .1-.2 .3-.5-.4v.8M92 169.5h.8l-.4 .5 .3 .1 .1 .4-.2 .3h-.4"/>
<path d="M254.2 179l.3 .1 .1 .3-.2 .2h-.3M254.2 178.4h.4M256.7 194.8h.4M256.7 194.2h.6M258.8 191.6h.8l-.4 .5 .4 .1v.5l-.2 .2h-.4M105.1 208.9l.4 1.2 .5-1.2M109.4 219h.7l-.4 .5 .4 .1v.4l-.2 .3h-.4M257.3 214h.8l-.4 .5 .4 .1v.5l-.2 .2h-.4M118.2 222.2h.4M118.2 221.6h.6"/>
</g>
<path d="M98.9 42.9v-.4l-.2-.2h-.5l-.1 .4-.5-.4v.7M99.6 45.2h4M99.6 46.2h4M101.6 40.6v4.6M101.6 46.2v4.6" fill="none" stroke="#a1a1a1" stroke-width=".18"/>
<path d="M98.7 41.4l5.8 8.6M104.5 41.4l-5.8 8.6" fill="none" stroke="#ff2626" stroke-width=".46"/>
<path d="M251.5 180.3v2.6M102.9 208.3h2.5M104.1 205.7v2.6" fill="none" stroke="#840000" stroke-width=".25"/>
<path d="M247.1 215.1l.8 .8-.8 .8z" fill="#000"/>
<path d="M372.1 24.1h22.9v12.7h-22.9z" fill="#ffffc2"/>
<path d="M372.1 24.1h22.9v12.7h-22.9z" fill="none" stroke="#800000" stroke-width=".18"/>
<path d="M381 38.7h1M382.5 38.1l.5-.1 .2 .3-.8 .9h.8M383 22.7h.8l-.4 .5 .4 .1v.4l-.2 .3h-.4M195.8 94.7h.8l-.4 .4 .3 .2 .1 .4-.3 .2h-.3M77.6 244.4h.8l-.4 .5 .3 .1 .1 .4-.3 .3h-.3" fill="none" stroke="#008484" stroke-width=".18"/>
<g fill="none" stroke="#840000" stroke-width=".18">
<path d="M320 53.3v1.3h1.3l-1.3 1.3-1.2-1.3h1.2M320 53.3h.1M330.2 53.3v1.3h1.3l-1.3 1.3-1.3-1.3h1.3M330.2 53.3h.1M162.6 86.4v1.2h1.2l-1.2 1.3-1.3-1.3h1.3M162.6 86.4h.1M177.8 86.4v1.2h1.3l-1.3 1.3-1.3-1.3h1.3M177.8 86.4h.1M188 86.4v1.2h1.2l-1.2 1.3-1.3-1.3h1.3M188 86.4h.1M193 99.1v2.5M215.6 99.3v4.6"/>
<path d="M216.1 99.3v1.1M213.4 101.6h2.2M76.2 246.4h4.6M80.8 244.4v4M81.8 244.4v4M81.8 246.4h4.6"/>
</g>
<circle cx="193" cy="97.8" r="1.27" fill="none" stroke="#000" stroke-width=".18"/>
<path d="M216.1 101.6l1.5-.5v1z" fill="#840000"/>
<g fill="none" stroke="#840000" stroke-width=".18">
<path d="M318 45.2h4M318 46.2h4M320 40.6v4.6M320 46.2v4.6M218.4 96.5v3.3l-2.3 .1M194.5 106.2h2.1v6h-2.1zM195.6 116.8v1.3h1.2l-1.2 1.3-1.3-1.3h1.3M195.6 116.8h.1M195.6 104.1v2M195.6 112.3v2M198.1 101.6h2M200.2 100.5h6v2.1h-6z"/>
<path d="M206.3 101.6h2M210.8 101.6h2.6M216.1 101.1v1M216.1 102.8v1.1M216.1 101.6h2.3v5.1M216.1 103.4h2.3M218.4 116.8v1.3h1.3l-1.3 1.3-1.2-1.3h1.2M218.4 116.8h.1M246.4 167.6h2M248.5 166.7h6v2h-6zM254.5 167.6h2M248.9 198.1v1.3h1.3l-1.3 1.3-1.3-1.3h1.3"/>
<path d="M248.9 198.1h.1M76.2 233.7h4.6M80.8 231.7v4M81.8 231.7v4M81.8 233.7h4.6"/>
</g>
<path d="M316.8 42.4v-.3l-.2-.3-.5 .1-.1 .3-.5-.4v.8M207.6 99.1h.8l-.5 .5 .4 .1 .1 .5-.3 .2h-.4M198.7 105.9v-.3l-.2-.3-.5 .1-.1 .3-.5-.4v.8M226.6 100.2h.8l-.4 .5 .4 .1v.4l-.2 .3h-.4M253.2 167l.1 .7-.1 .4M253.3 167.5l-.1 .2M254.6 169.5h.8l-.5 .5 .4 .1 .1 .4-.3 .3h-.3M77.6 231.7h.8l-.4 .5 .3 .1 .1 .4-.3 .3h-.3M87.7 234.9h.5M87.7 234.3h.6" fill="none" stroke="#008484" stroke-width=".18"/>
<path d="M160 68.6v2.5" fill="none" stroke="#840000" stroke-width=".25"/>
<path d="M173.8 37.1l.5 1h-1z" fill="#840000"/>
<path d="M170.2 33h3M170.2 38.1h3M173.3 33h1l-.5 1.1zM177.3 35.6l-3.5 1.5M177.3 35.6h3" fill="none" stroke="#840000" stroke-width=".18"/>
<path d="M185.2 31.6l.6 .1 .1 .3-.2 .2M185.2 32.2h.5M185.7 32.2l.3 .3-.1 .3-.7 .1" fill="none" stroke="#008484" stroke-width=".18"/>
<path d="M45.7 213.4h20.3v40.6h-20.3z" fill="#ffffc2"/>
<g fill="none" stroke="#840000" stroke-width=".18">
<path d="M127 27.9h2M129 25.9v4M130 25.9v4M130 27.9h4.6M132.1 33h2M134.2 32h6v2h-6zM139.7 27.9h2M140.2 33h2M141.8 27h6v2h-6zM147.9 27.9h2M38.1 76.2v4.6M48.3 76.2v4.6"/>
<path d="M36.1 80.8h4M36.1 81.8h4M38.1 81.8v4.6M46.3 80.8h4M46.3 81.8h4M48.3 86.4v1.2h1.2l-1.2 1.3-1.3-1.3h1.3M48.3 86.4h.1M48.3 81.8v4.6M67.1 81.8v4M54.8 106.2h2.1v6h-2.1zM55.9 116.8v1.3h1.2l-1.2 1.3-1.3-1.3h1.3M55.9 116.8h.1"/>
<path d="M55.9 104.1v2M55.9 112.3v2M232.6 174.8h2.1v6h-2.1zM233.7 172.7v2M233.7 180.9v2M45.7 213.4h20.3v40.6h-20.3zM53.3 208.3v5.1M55.9 208.3v5.1M58.4 208.3v5.1M27.9 223.5v2.6M40.6 221h5.1M40.6 226.1h5.1"/>
<path d="M40.6 228.6h5.1M40.6 231.1h5.1M40.6 236.2h5.1M43.4 225.6h.7M66 221h5.1M66 226.1h5.1M66 233.7h5.1M66 238.8h5.1M248.9 223.5v1.3h1.3l-1.3 1.3-1.3-1.3h1.3M248.9 223.5h.1M30.5 243.8v1.3h1.2l-1.2 1.3-1.3-1.3h1.3M30.5 243.8h.1"/>
<path d="M40.6 241.3h5.1M40.6 251.5h5.1M66 251.5h5.1M66 246.4h5.1M203.7 271.3h4M203.7 272.3h4M205.7 266.7v4.6M205.7 272.3v4.6"/>
</g>
<g fill="none" stroke="#008484" stroke-width=".18">
<path d="M127.1 26h.8l-.4 .5 .4 .1v.4l-.2 .2h-.4M140.3 34.9h.8l-.5 .5 .4 .1 .1 .4-.3 .2h-.3M147.9 29.8h.8l-.4 .5 .3 .1 .1 .4-.3 .3h-.3M46.7 78h.8l-.4 .5 .4 .2v.4l-.2 .2h-.4M56.9 78h.8l-.4 .5 .3 .2 .1 .4-.3 .2h-.3M59 105.9v-.3l-.2-.3-.5 .1-.1 .3-.5-.4v.8M233.4 175.4l.5 .5M234.3 175.4l-.5 .4M236.8 174.5v-.4l-.2-.2-.5 .1-.1 .3-.5-.4v.8M30.7 219h.7l-.4 .5 .4 .1v.4l-.2 .3h-.4M67.1 211.4h.8l-.4 .5 .3 .1 .1 .4-.2 .3h-.4M46.5 235.2h2.2"/>
<path d="M64.9 254.6h.8l-.4 .5M65.4 255.1l.3 .2v.3l-.3 .2M214.4 269.1h.8l-.5 .5 .4 .1 .1 .4-.3 .3h-.3"/>
</g>
<circle cx="27.9" cy="222.2" r="1.27" fill="none" stroke="#000" stroke-width=".18"/>
<path d="M67.1 83.8l3-2v4z" fill="#840000"/>
<path d="M63.5 83.8h3.8M69.8 83.8h3.9" fill="none" stroke="#840000" stroke-width=".18"/>
<path d="M73.7 88h1M74.2 80.2h.8l-.4 .4 .3 .2 .1 .4-.3 .2h-.3M75.2 87.2h.8l-.5 1.3" fill="none" stroke="#008484" stroke-width=".18"/>
<path d="M66.6 70.7h4v6h-4z" fill="#ffffc2"/>
<g fill="none" stroke="#840000" stroke-width=".18">
<path d="M259.1 43.2h2M261.1 41.2v4M262.1 43.2h4.6M262.1 41.2v4M25.4 73.7h2M27.5 72.7h6v2h-6zM33.6 73.7h2M63.5 73.7h3M66.6 70.7h4v6h-4zM66.6 70.7l4 6M67.1 75.7h1M67.6 75.2v1"/>
<path d="M70.7 73.7h3M22.9 86.4v1.2h1.2l-1.2 1.3-1.3-1.3h1.3M22.9 86.4h.1M139.7 172.7h2M141.8 171.7h6v2h-6zM147.9 172.7h2M232.6 197.7h2.1v6h-2.1zM233.7 195.6v2M236.2 185.4h2M238.3 184.4h6v2h-6zM244.4 185.4h2M233.7 203.7v2"/>
<path d="M29.4 230.7h2.1v6h-2.1zM30.5 228.6v2M30.5 236.8v2M38.1 243.8v1.3h1.3l-1.3 1.3-1.3-1.3h1.3M38.1 243.8h.1M178.3 256h4M178.3 257h4M180.3 251.5v4.5M180.3 257v4.6"/>
</g>
<path d="M66.6 70.7h4v6h-4z" fill="none" stroke="#800000" stroke-width=".18"/>
<g fill="none" stroke="#008484" stroke-width=".18">
<path d="M258.8 41.2h.8l-.4 .5 .4 .1v.4l-.2 .3h-.4M33.6 70.4h.8l-.4 .5 .3 .1 .1 .5-.3 .2h-.3M66.4 68.5l.3-.1 .3 .2M67 69.6l-.3 .1-.3-.1M73.8 78.3h.9M75.4 77.5v1.3h.6M147.9 174.6h.8l-.4 .5 .3 .1 .1 .4-.3 .2h-.3M236.8 197.4v-.4l-.2-.2h-.5l-.1 .4-.5-.4v.7M243.3 185.5l.4 .5M243.7 185.2l-.5 .4M244.4 182.2h.8l-.4 .5 .3 .1 .1 .4-.2 .3h-.4M39.9 213.9l-.4 1.3"/>
<path d="M33.6 230.4v-.4l-.2-.2h-.5l-.1 .4-.5-.4v.8M39.1 257.1l.4 1.3 .4-1.3M189 253.9h.8l-.5 .4 .4 .2 .1 .4-.3 .2h-.3"/>
</g>
<path d="M38.1 215.9v2.5M36.8 256.5h2.6M38.1 254v2.5" fill="none" stroke="#840000" stroke-width=".25"/>
<path d="M232.7 212.9h2v6h-2zM233.7 210.8v2M233.7 219v2M236.8 210.1v-.4l-.2-.2h-.5l-.1 .4-.5-.4v.7" fill="none" stroke="#a1a1a1" stroke-width=".18"/>
<path d="M232 211.4l3.5 9M235.5 211.4l-3.5 9" fill="none" stroke="#ff2626" stroke-width=".46"/>
<path d="M99.1 180.3l20.3 10.2-20.3 10.2z" fill="#ffffb0"/>
<path d="M99.1 180.3l20.3 10.2-20.3 10.2z" fill="none" stroke="#800000" stroke-width=".18"/>
<g fill="none" stroke="#840000" stroke-width=".18">
<path d="M271.8 38.1h2M273.9 37.1h6v2.1h-6zM279.9 38.1h2M118.4 42.7h2v6h-2zM119.4 53.3v1.3h1.2l-1.2 1.3-1.3-1.3h1.3M119.4 53.3h.1M119.4 40.6v2M119.4 48.8v2M264.2 48.3h2M266.2 47.3h6v2h-6zM272.3 48.3h2M308.9 42.7h2v6h-2z"/>
<path d="M309.9 40.6v2M309.9 48.8v2M53.3 99.1v2.5M58.4 101.6h2M60.5 100.5h6v2.1h-6zM66.6 101.6h2M104.1 175.3v7.6M116.8 167.6h4.6M121.4 165.6v4M122.4 167.6h4.6M122.4 165.6v4M214.8 179.9h2.1v6h-2.1z"/>
<path d="M215.9 177.8v2M91.4 185.4h7.7M91.4 195.6h7.7M104.1 198.1v7.6M119.4 190.5h7.6M215.9 186v2M168.2 256h4M168.2 257h4M170.2 251.5v4.5M170.2 257v4.6M188.5 256h4M188.5 257h4"/>
<path d="M190.5 251.5v4.5M190.5 257v4.6M198.7 256h4M198.7 257h4M200.7 251.5v4.5M200.7 257v4.6M173.3 271.3h4M173.3 272.3h4M175.3 266.7v4.6M175.3 272.3v4.6M183.4 271.3h4M183.4 272.3h4"/>
<path d="M185.4 266.7v4.6M185.4 272.3v4.6M193.6 271.3h4M193.6 272.3h4M195.6 266.7v4.6M195.6 272.3v4.6"/>
</g>
<g fill="none" stroke="#008484" stroke-width=".18">
<path d="M278.6 38.2l.3 .5M278.9 37.8l-.4 .5M280 34.9h.8l-.5 .5 .4 .1 .1 .4-.3 .2h-.3M117.4 42.4v-.3l-.2-.3-.4 .1-.2 .3-.5-.4v.8M118.7 44l.7-.2 .4 .2M119.2 43.8l.2 .2M271 48.4l.3 .4M271.3 48l-.5 .5M272.4 50.1h.7l-.4 .5 .4 .1v.4l-.2 .3h-.4M307.9 42.4v-.3l-.2-.3-.4 .1-.2 .3-.5-.4v.8M56.3 94.8h.7l-.4 .5 .4 .2v.4l-.2 .2h-.4M67.9 99.1h.8l-.5 .5 .4 .1 .1 .5-.3 .2h-.4"/>
<path d="M126.5 164h.8l-.4 .5 .3 .1 .1 .4-.3 .2h-.3M219 179.6v-.4l-.2-.2h-.4l-.2 .4-.5-.4v.8M100 195.7h.9M104.2 195.2v.9M116.6 181.5h.8l-.4 .4 .4 .2v.4l-.2 .2h-.4M210.1 197.1l1.3 .4-1.3 .4M215.2 197.1l1.3 .4-1.3 .4M215.6 180.5l.5 .5M216.5 180.5l-.5 .4M178.8 253.9h.8l-.4 .4 .3 .2 .1 .4-.2 .2h-.4M199.1 253.9h.8l-.4 .4 .4 .2v.4l-.2 .2h-.4M209.3 253.9h.8l-.4 .4 .3 .2 .1 .4-.3 .2h-.3"/>
<path d="M183.9 269.1h.8l-.4 .5 .3 .1 .1 .4-.3 .3h-.3M194.1 269.1h.7l-.4 .5 .4 .1v.4l-.2 .3h-.4M204.2 269.1h.8l-.4 .5 .3 .1 .1 .4-.2 .3h-.4"/>
</g>
<circle cx="53.3" cy="97.8" r="1.27" fill="none" stroke="#000" stroke-width=".18"/>
<path d="M209.5 195.6h2.6M210.8 193v2.6M214.6 195.6h2.6M215.9 193v2.6" fill="none" stroke="#840000" stroke-width=".25"/>
<path d="M172.7 154.9h25.4v38.1h-25.4z" fill="#ffffc2"/>
<path d="M172.7 154.9h25.4v38.1h-25.4z" fill="none" stroke="#800000" stroke-width=".18"/>
<g fill="none" stroke="#840000" stroke-width=".18">
<path d="M309.9 53.3v1.3h1.2l-1.2 1.3-1.3-1.3h1.3M309.9 53.3h.1M75.9 99.3v4.6M76.4 99.3v1.1M73.7 101.6h2.2M78.7 116.8v1.3h1.3l-1.3 1.3-1.2-1.3h1.2M78.7 116.8h.1M165.1 157.5h7.6M165.1 160h7.6M165.1 162.6h7.6M165.1 167.6h7.6M165.1 172.7h7.6"/>
<path d="M165.1 177.8h7.6M198.1 167.6h7.6M198.1 172.7h7.6M198.1 177.8h7.6M202.2 167.2h.7M150.4 197.6h4M150.4 198.6h4M152.4 193v4.6M152.4 198.6v4.6M164.7 182.5l.8 .8M164.7 185l.8 .8M164.7 187.6l.8 .7"/>
<path d="M165.1 193v1.3h1.3l-1.3 1.3-1.3-1.3h1.3M165.1 193h.1M165.1 182.9h7.6M165.1 185.4h7.6M165.1 188h7.6M165.1 190.5h7.6M165.5 182.5l-.8 .8M165.5 185l-.8 .8M165.5 187.6l-.8 .7M198.1 182.9h7.6M198.1 185.4h7.6M198.1 188h7.6"/>
<path d="M198.1 190.5h7.6M205.7 193v1.3h1.3l-1.3 1.3-1.2-1.3h1.2M205.7 193h.1M233.7 223.5v1.3h1.2l-1.2 1.3-1.3-1.3h1.3M233.7 223.5h.1M158 256h4M158 257h4M160 251.5v4.5M160 257v4.6M208.8 256h4M208.8 257h4M210.8 251.5v4.5"/>
<path d="M210.8 257v4.6M219 256h4M219 257h4M221 251.5v4.5M221 257v4.6M229.1 256h4M229.1 257h4M231.1 251.5v4.5M231.1 257v4.6M163.1 271.3h4M163.1 272.3h4M165.1 266.7v4.6"/>
<path d="M165.1 272.3v4.6M213.9 271.3h4M213.9 272.3h4M215.9 266.7v4.6M215.9 272.3v4.6M224.1 271.3h4M224.1 272.3h4M226.1 266.7v4.6M226.1 272.3v4.6"/>
</g>
<g fill="none" stroke="#008484" stroke-width=".18">
<path d="M164.4 147.9l-.4 1.3M180.1 153.5h.8l-.4 .5 .4 .1v.5l-.2 .2h-.4M106 170.8l-.5 1.2M176.9 160.1h1M179.9 172.9l.1 .2-.1 .2M179.9 172.5h.1M197.1 178l.2 .1-.2 .3M197.1 177.5l.1 .1M156.2 194.8v-.3l-.2-.3-.4 .1-.1 .3-.5-.4v.8M157.9 195.5v.5M179.7 194.2l.2 .2-.1 .3-.7 .7h.8M196.2 183h1"/>
<path d="M196.2 185.5h1M196.2 188.1h1M168.7 253.9h.7l-.4 .4 .4 .2v.4l-.2 .2h-.4M219.5 253.9h.7l-.4 .4 .4 .2v.4l-.2 .2h-.4M229.6 253.9h.8l-.4 .4 .3 .2 .1 .4-.2 .2h-.4M239.8 253.9h.8l-.5 .4 .4 .2 .1 .4-.3 .2h-.3M173.7 269.1h.8l-.4 .5 .4 .1v.4l-.2 .3h-.4M224.5 269.1h.8l-.4 .5 .4 .1v.4l-.2 .3h-.4M234.7 269.1h.8l-.4 .5 .3 .1 .1 .4-.3 .3h-.3"/>
</g>
<path d="M162.6 149.9v2.5M104.1 172.7v2.6" fill="none" stroke="#840000" stroke-width=".25"/>
<path d="M76.4 101.6l1.5-.5v1z" fill="#840000"/>
<path d="M287 43.2h2.1M289.1 41.2v4M290.1 43.2h4.5M290.1 41.2v4M328.2 45.2h4M78.7 96.5v3.3l-2.3 .1M71.1 101.6h2.6M76.4 101.1v1M76.4 102.8v1.1M76.4 101.6h2.3v5.1M76.4 103.4h2.3" fill="none" stroke="#840000" stroke-width=".18"/>
<path d="M286.8 41.2h.8l-.5 .5 .4 .1 .1 .4-.3 .3h-.4M86.9 99.9h.8l-.4 .5 .4 .1v.5l-.2 .2h-.4" fill="none" stroke="#008484" stroke-width=".18"/>
<path d="M328.7 42.9l1 .8-.8 .5z" fill="#840000"/>
<g fill="none" stroke="#840000" stroke-width=".18">
<path d="M328.2 46.2h4M329.2 43.7l2.3 4.6M330.2 40.6v4.6M330.2 46.2v4.6M309.9 175.3h2.5M386.1 167.6h2M386.1 170.2h2M388.2 166.7h6v2h-6zM388.2 169.2h6v2h-6zM394.2 167.6h2M394.2 170.2h2M277.4 192.5h4"/>
<path d="M277.4 193.5h4M279.4 198.1v1.3h1.3l-1.3 1.3-1.3-1.3h1.3M279.4 198.1h.1M279.4 188v4.5M279.4 193.5v4.6M294.6 198.1v2M299.7 198.1v2M317.5 190.5v1.3h1.3l-1.3 1.2-1.3-1.2h1.3M317.5 190.5h.1M373.4 190.5v1.3h-1.3l1.3 1.2 1.2-1.2h-1.2M373.4 190.5h.1M391.2 190.5v1.3h1.2l-1.2 1.2-1.3-1.2h1.3"/>
<path d="M391.2 190.5h.1M277.4 217.9h4M277.4 218.9h4M279.4 213.4v4.5M279.4 218.9v4.6M281.9 210.8h4.5M287 209.6h1.3l-1.3 2.5h-1.3zM287.7 210.8h4.4M293.6 200.2h2v6h-2zM294.6 206.3v2M298.7 200.2h2v6h-2zM299.7 206.3v2"/>
<path d="M302.8 217.9h4M302.8 218.9h4M304.8 213.4v4.5M304.8 218.9v4.6M333.3 217.9h4M333.3 218.9h4M335.3 213.4v4.5M335.3 218.9v4.6M337.8 210.8h4.5M341.6 209.6h1.3l1.3 2.5h-1.3zM343.5 210.8h4.5M348.5 217.9h4"/>
<path d="M348.5 218.9h4M350.5 213.4v4.5M350.5 218.9v4.6M355.6 209.6l-1-.7 1-.6 1 .6-1 .7v1.2M355.6 210.8h.1M358.7 217.9h4M358.7 218.9h4M360.7 213.4v4.5M360.7 218.9v4.6M368.8 217.9h4M368.8 218.9h4M370.8 213.4v4.5"/>
<path d="M370.8 218.9v4.6M379 217.9h4M379 218.9h4M381 213.4v4.5M381 218.9v4.6M389.2 217.9h4M389.2 218.9h4M391.2 213.4v4.5M391.2 218.9v4.6M279.4 223.5v1.3h1.3l-1.3 1.3-1.3-1.3h1.3M279.4 223.5h.1M304.8 223.5v1.3h1.3l-1.3 1.3-1.3-1.3h1.3"/>
<path d="M304.8 223.5h.1M335.3 223.5v1.3h-1.3l1.3 1.3 1.2-1.3h-1.2M335.3 223.5h.1M350.5 223.5v1.3h-1.3l1.3 1.3 1.3-1.3h-1.3M350.5 223.5h.1M360.7 223.5v1.3h-1.3l1.3 1.3 1.2-1.3h-1.2M360.7 223.5h.1M370.8 223.5v1.3h-1.2l1.2 1.3 1.3-1.3h-1.3M370.8 223.5h.1M381 223.5v1.3h-1.3l1.3 1.3 1.3-1.3h-1.3M381 223.5h.1M391.2 223.5v1.3h1.2l-1.2 1.3-1.3-1.3h1.3"/>
<path d="M391.2 223.5h.1"/>
</g>
<g fill="none" stroke="#008484" stroke-width=".18">
<path d="M338.3 46.9h.4M338.9 46.3h-.6v1.3M340.1 43.8h.8l-.4 .4 .3 .2 .1 .4-.2 .2h-.4M320.8 177.7h.7l-.4 .4 .4 .2v.4l-.2 .2h-.4M287.1 194.8h.5M287.1 194.2h.6M289.3 191.6h.8l-.4 .5 .3 .1 .1 .5-.2 .2h-.4M292.7 199.9v-.4l-.3-.2-.4 .1-.1 .3-.5-.4v.8M302.8 199.9v-.4l-.2-.2-.4 .1-.1 .3-.5-.4v.8M287.1 219.6h.6M287.9 206.9h.7l-.4 .4 .4 .2v.4l-.2 .2h-.4M289.3 217h.8l-.4 .5 .3 .1 .1 .5-.2 .2h-.4"/>
<path d="M292.4 212.7h.9l-.9 1.2h.9M312.5 219.6h.6M314.7 217h.8l-.4 .5 .3 .1 .1 .5-.2 .2h-.4M329.5 203.8l-.4 1.2M332.9 215.2h.8l-.5 .5 .4 .1 .1 .4-.3 .3h-.3M346.6 205h.7l-.4 .5 .4 .2v.4l-.2 .2h-.4M348.1 215.2h.8l-.4 .5 .3 .1 .1 .4-.2 .3h-.4M348.3 207.6h.9l-.9 1.3h.9M358.3 215.2h.8l-.5 .5 .4 .1 .1 .4-.3 .3h-.3M368.4 215.2h.8l-.4 .5 .4 .1v.4l-.2 .3h-.4M378.6 215.2h.8l-.4 .5 .3 .1 .1 .4-.3 .3h-.3M395.2 204.7h.6"/>
<path d="M395.5 203.8l.4 1.2M401.1 217h.8l-.5 .5 .4 .1 .1 .5-.3 .2h-.4M287.1 220.2h.5M312.5 220.2h.5"/>
</g>
<path d="M279.4 180.3v2.6M327.7 205.7v2.6M391.2 205.7v2.6" fill="none" stroke="#840000" stroke-width=".25"/>
<g fill="#a1a1a1" stroke="#a1a1a1" stroke-width=".18">
<circle cx="391.2" cy="185.4" r=".63"/>
<circle cx="373.4" cy="185.4" r=".63"/>
</g>
<g fill="none" stroke="#a1a1a1" stroke-width=".18">
<path d="M373.4 185.4h5.1M373.4 188v2.5M386.1 185.4h5.1M391.2 188v2.5"/>
<circle cx="373.4" cy="185.4" r="2.54"/>
<circle cx="391.2" cy="185.4" r="2.54"/>
</g>
<path d="M369.1 181.1l8.6 8.6M377.7 181.1l-8.6 8.6M386.9 181.1l8.6 8.6M395.5 181.1l-8.6 8.6" fill="none" stroke="#ff2626" stroke-width=".46"/>
<circle cx="313.7" cy="175.3" r="1.27" fill="none" stroke="#000" stroke-width=".18"/>
<path d="M327.7 152.4h30.4v38.1h-30.4z" fill="#ffffc2"/>
<path d="M327.7 152.4h30.4v38.1h-30.4z" fill="none" stroke="#800000" stroke-width=".18"/>
<g fill="none" stroke="#840000" stroke-width=".18">
<path d="M274.9 57.9h4M274.9 58.9h4M276.9 53.3v4.6M276.9 58.9v4.6M383.5 58.4v5.1M276.9 66v1.3h1.2l-1.2 1.3-1.3-1.3h1.3M276.9 66h.1M383.5 63.5v1.3h1.3l-1.3 1.2-1.2-1.2h1.2M383.5 63.5h.1M320 154.9h7.7M320 157.5h7.7M324.1 159.6h.7"/>
<path d="M358.1 154.9h7.7M358.1 157.5h7.7M320 160h7.7M320 167.6h7.7M320 170.2h7.7M358.1 160h7.7M358.1 167.6h7.7M358.1 170.2h7.7M358.1 175.3h7.7M50.8 185.4h4.6M55.4 183.4v4M56.4 185.4h4.6"/>
<path d="M56.4 183.4v4M320 182.9h7.7M320 185.4h7.7M320 188h7.7M358.1 182.9h7.7M358.1 188h7.7M358.1 180.3h7.7M152.4 205.7v1.3h1.3l-1.3 1.3-1.3-1.3h1.3M152.4 205.7h.1"/>
</g>
<path d="M286.8 56.5h.8l-.5 .4 .4 .2 .1 .4-.3 .2h-.4M382.3 43.5h.8l-.5 .5 .4 .1 .1 .5-.3 .2h-.3M395 62.9h.9M396.5 62.2l.5-.1 .2 .3-.8 1h.8M335.1 151h.8l-.4 .5 .3 .1 .1 .4-.3 .3h-.3M59 181.5h.8l-.4 .4 .3 .2 .1 .4-.3 .2h-.3M335.7 191.6h.2l.3 .3-.3 .3M335.7 192.2h.2M335.9 192.2l.3 .2v.3l-.1 .1-.4 .1" fill="none" stroke="#008484" stroke-width=".18"/>
<path d="M372.1 55.9v2.5h2.5M372.1 45.7v2.6M372.1 50.8v2.5M377.2 58.4h2.5M382.3 58.4h2.5M382.3 45.7h2.5M387.3 58.4h2.6M387.3 45.7h2.6M392.4 45.7h2.6v2.6M395 55.9v2.5h-2.6M395 50.8v2.5" fill="none" stroke="#840000" stroke-width=".51"/>
<path d="M343.9 37.1l.5 1h-1z" fill="#840000"/>
<g fill="none" stroke="#840000" stroke-width=".18">
<path d="M340.4 33h3M340.4 38.1h3M343.4 33h1l-.5 1.1zM347.5 35.6l-3.5 1.5M347.5 35.6h3M330.2 40.6v2.6M330.2 48.3v2.5M383.5 58.4v5.1M22.9 76.2v2.5M38.1 76.2v2.5M48.3 76.2v2.5M63.5 73.7h3"/>
<path d="M70.7 73.7h3M162.6 76.2v2.5M177.8 76.2v2.5M188 76.2v2.5M203.2 73.7h3M210.4 73.7h3M383.5 63.5h.1M22.9 86.4h.1M22.9 83.8v2.6M38.1 86.4h.1M38.1 83.8v2.6M48.3 86.4h.1"/>
<path d="M48.3 83.8v2.6M162.6 86.4h.1M162.6 83.8v2.6M177.8 86.4h.1M177.8 83.8v2.6M188 86.4h.1M188 83.8v2.6M165.1 157.5h7.6M309.9 152.4v2.5M316.4 144.3h2.1v6h-2.1zM317.5 142.2v2M317.5 150.4v2"/>
<path d="M320 157.5h7.7M320 154.9h7.7M324.1 159.6h.7M358.1 157.5h7.7M358.1 154.9h7.7M104.1 175.3v7.6M165.1 160h7.6M165.1 162.6h7.6M165.1 167.6h7.6M165.1 172.7h7.6M165.1 177.8h7.6M198.1 167.6h7.6"/>
<path d="M198.1 172.7h7.6M198.1 177.8h7.6M202.2 167.2h.7M233.7 172.7v2M309.9 175.3h2.5M320 160h7.7M320 167.6h7.7M320 170.2h7.7M358.1 160h7.7M358.1 167.6h7.7M358.1 175.3h7.7M358.1 170.2h7.7"/>
<path d="M37 190h2.1v6h-2.1zM38.1 188v2M38.1 196.1v2M72.6 190h2v6h-2zM73.7 188v2M73.7 196.1v2M91.4 185.4h7.7M91.4 195.6h7.7M104.1 198.1v7.6M119.4 190.5h7.6M164.7 182.5l.8 .8M164.7 185l.8 .8"/>
<path d="M164.7 187.6l.8 .7M165.1 193h.1M165.1 185.4h7.6M165.1 182.9h7.6M165.1 188h7.6M165.1 190.5h7.6M165.5 182.5l-.8 .8M165.5 185l-.8 .8M165.5 187.6l-.8 .7M198.1 185.4h7.6M198.1 182.9h7.6M198.1 188h7.6"/>
<path d="M198.1 190.5h7.6M205.7 193h.1M233.7 180.9v2M236.2 185.4h2M244.4 185.4h2M248.9 198.1h.1M248.9 188v2.5M248.9 195.6v2.5M279.4 198.1h.1M279.4 188v2.5M279.4 195.6v2.5M294.6 198.1v2"/>
<path d="M320 185.4h7.7M320 182.9h7.7M320 188h7.7M358.1 182.9h7.7M358.1 188h7.7M358.1 180.3h7.7M373.4 190.5h.1M391.2 190.5h.1M38.1 200.7v1.2h1.3l-1.3 1.3-1.3-1.3h1.3M38.1 200.7h.1M53.3 208.3v5.1M55.9 208.3v5.1"/>
<path d="M58.4 208.3v5.1M279.4 213.4v2.5M281.9 210.8h4.5M287.7 210.8h4.4M294.6 206.3v2M304.8 213.4v2.5M335.3 213.4v2.5M350.5 213.4v2.5M360.7 213.4v2.5M370.8 213.4v2.5M381 213.4v2.5M391.2 213.4v2.5"/>
<path d="M40.6 221h5.1M40.6 226.1h5.1M40.6 228.6h5.1M40.6 231.1h5.1M40.6 236.2h5.1M43.4 225.6h.7M66 233.7h5.1M66 221h5.1M66 226.1h5.1M66 238.8h5.1M76.2 233.7h2.5M83.8 233.7h2.6"/>
<path d="M279.4 223.5h.1M279.4 221v2.5M304.8 223.5h.1M304.8 221v2.5M335.3 223.5h.1M335.3 221v2.5M350.5 223.5h.1M350.5 221v2.5M360.7 223.5h.1M360.7 221v2.5M370.8 223.5h.1M370.8 221v2.5"/>
<path d="M381 223.5h.1M381 221v2.5M391.2 223.5h.1M391.2 221v2.5M40.6 241.3h5.1M40.6 251.5h5.1M66 246.4h5.1M66 251.5h5.1M76.2 246.4h2.5M83.8 246.4h2.6M137.7 256h4M137.7 257h4"/>
<path d="M139.7 251.5v4.5M139.7 257v4.6M147.9 256h4M147.9 257h4M149.9 251.5v4.5M149.9 257v4.6M160 251.5v2.5M160 259.1v2.5M170.2 251.5v2.5M170.2 259.1v2.5M180.3 251.5v2.5M180.3 259.1v2.5"/>
<path d="M190.5 251.5v2.5M190.5 259.1v2.5M200.7 251.5v2.5M200.7 259.1v2.5M210.8 251.5v2.5M210.8 259.1v2.5M221 251.5v2.5M221 259.1v2.5M231.1 251.5v2.5M231.1 259.1v2.5M133.3 264.2v-1.3l-1.2 1.3 1.2 1.2v-1.2h1.3M134.6 264.2h.1"/>
<path d="M142.8 271.3h4M142.8 272.3h4M144.8 266.7v4.6M144.8 272.3v4.6M152.9 271.3h4M152.9 272.3h4M154.9 266.7v4.6M154.9 272.3v4.6M165.1 266.7v2.5M165.1 274.3v2.6M175.3 266.7v2.5M175.3 274.3v2.6"/>
<path d="M185.4 266.7v2.5M185.4 274.3v2.6M195.6 266.7v2.5M195.6 274.3v2.6M205.7 266.7v2.5M205.7 274.3v2.6M215.9 266.7v2.5M215.9 274.3v2.6M226.1 266.7v2.5M226.1 274.3v2.6"/>
</g>
<g fill="none" stroke="#008484" stroke-width=".18">
<path d="M349.2 39.4l.7 .1v.3l-.2 .2M338.3 46.9h.4M338.9 46.3h-.6v1.3M340.1 43.8h.8l-.4 .4 .3 .2 .1 .4-.2 .2h-.4M349.2 40h.5M349.7 40l.3 .3-.1 .3-.7 .1M382.3 43.5h.8l-.5 .5 .4 .1 .1 .5-.3 .2h-.3M31.5 78h.8l-.4 .5 .3 .2 .1 .4-.3 .2h-.3M46.7 78h.8l-.4 .5 .4 .2v.4l-.2 .2h-.4M56.9 78h.8l-.4 .5 .3 .2 .1 .4-.3 .2h-.3M66.4 68.5l.3-.1 .3 .2M67 69.6l-.3 .1-.3-.1"/>
<path d="M73.8 78.3h.9M75.4 77.5v1.3h.6M171.2 78h.8l-.4 .5 .3 .2 .1 .4-.3 .2h-.3M186.4 78h.8l-.4 .5 .4 .2v.4l-.2 .2h-.4M196.6 78h.8l-.4 .5 .3 .2 .1 .4-.3 .2h-.3M206.1 68.5l.3-.1 .3 .2M206.7 69.6l-.3 .1-.3-.1M213.5 78.3h.9M215.1 77.5v1.3h.6M395 62.9h.9M396.5 62.2l.5-.1 .2 .3-.8 1h.8M321.5 138.6h.6"/>
<path d="M321.8 137.7l.4 1.3M180.1 153.5h.8l-.4 .5 .4 .1v.5l-.2 .2h-.4M311.7 148h.8l-.4 .5 .4 .1v.4l-.2 .2h-.4M320.6 144v-.3l-.2-.3-.4 .1-.2 .3-.5-.4v.8M335.1 151h.8l-.4 .5 .3 .1 .1 .4-.3 .3h-.3M382.5 153.9h.6M382.8 153l.4 1.2M106 170.8l-.5 1.2M176.9 160.1h1M179.9 172.9l.1 .2-.1 .2M179.9 172.5h.1M197.1 178l.2 .1-.2 .3"/>
<path d="M197.1 177.5l.1 .1M233.4 175.4l.5 .5M234.3 175.4l-.5 .4M236.8 174.5v-.4l-.2-.2-.5 .1-.1 .3-.5-.4v.8M320.8 177.7h.7l-.4 .4 .4 .2v.4l-.2 .2h-.4M37.8 190.7l.5 .4M38.7 190.7l-.5 .3M41.2 189.7v-.3l-.2-.3-.4 .1-.2 .4-.5-.5v.8M76.8 189.7v-.3l-.3-.3-.4 .1-.1 .4-.5-.5v.8M100 195.7h.9M104.2 195.2v.9M116.6 181.5h.8l-.4 .4 .4 .2v.4l-.2 .2h-.4"/>
<path d="M179.7 194.2l.2 .2-.1 .3-.7 .7h.8M196.2 183h1M196.2 185.5h1M196.2 188.1h1M243.3 185.5l.4 .5M243.7 185.2l-.5 .4M244.4 182.2h.8l-.4 .5 .3 .1 .1 .4-.2 .3h-.4M256.7 194.8h.4M256.7 194.2h.6M258.8 191.6h.8l-.4 .5 .4 .1v.5l-.2 .2h-.4M287.1 194.8h.5M287.1 194.2h.6"/>
<path d="M289.3 191.6h.8l-.4 .5 .3 .1 .1 .5-.2 .2h-.4M292.7 199.9v-.4l-.3-.2-.4 .1-.1 .3-.5-.4v.8M335.7 191.6h.2l.3 .3-.3 .3M335.7 192.2h.2M335.9 192.2l.3 .2v.3l-.1 .1-.4 .1M67.1 211.4h.8l-.4 .5 .3 .1 .1 .4-.2 .3h-.4M105.1 208.9l.4 1.2 .5-1.2M287.1 219.6h.6M287.9 206.9h.7l-.4 .4 .4 .2v.4l-.2 .2h-.4M289.3 217h.8l-.4 .5 .3 .1 .1 .5-.2 .2h-.4M292.4 212.7h.9l-.9 1.2h.9M312.5 219.6h.6"/>
<path d="M314.7 217h.8l-.4 .5 .3 .1 .1 .5-.2 .2h-.4M332.9 215.2h.8l-.5 .5 .4 .1 .1 .4-.3 .3h-.3M348.1 215.2h.8l-.4 .5 .3 .1 .1 .4-.2 .3h-.4M358.3 215.2h.8l-.5 .5 .4 .1 .1 .4-.3 .3h-.3M368.4 215.2h.8l-.4 .5 .4 .1v.4l-.2 .3h-.4M378.6 215.2h.8l-.4 .5 .3 .1 .1 .4-.3 .3h-.3M401.1 217h.8l-.5 .5 .4 .1 .1 .5-.3 .2h-.4M46.5 235.2h2.2M77.6 231.7h.8l-.4 .5 .3 .1 .1 .4-.3 .3h-.3M87.7 234.9h.5M87.7 234.3h.6M287.1 220.2h.5"/>
<path d="M312.5 220.2h.5M64.9 254.6h.8l-.4 .5M65.4 255.1l.3 .2v.3l-.3 .2M77.6 244.4h.8l-.4 .5 .3 .1 .1 .4-.3 .3h-.3M130.6 248.2l-.4 1.3M148.3 253.9h.8l-.4 .4 .4 .2v.4l-.2 .2h-.4M158.5 253.9h.8l-.4 .4 .3 .2 .1 .4-.3 .2h-.3M168.7 253.9h.7l-.4 .4 .4 .2v.4l-.2 .2h-.4M178.8 253.9h.8l-.4 .4 .3 .2 .1 .4-.2 .2h-.4M189 253.9h.8l-.5 .4 .4 .2 .1 .4-.3 .2h-.3M199.1 253.9h.8l-.4 .4 .4 .2v.4l-.2 .2h-.4M209.3 253.9h.8l-.4 .4 .3 .2 .1 .4-.3 .2h-.3"/>
<path d="M219.5 253.9h.7l-.4 .4 .4 .2v.4l-.2 .2h-.4M229.6 253.9h.8l-.4 .4 .3 .2 .1 .4-.2 .2h-.4M239.8 253.9h.8l-.5 .4 .4 .2 .1 .4-.3 .2h-.3M129.7 278.7l.5 1.3 .4-1.3M153.4 269.1h.8l-.4 .5 .3 .1 .1 .4-.2 .3h-.4M163.6 269.1h.8l-.5 .5 .4 .1 .1 .4-.3 .3h-.3M173.7 269.1h.8l-.4 .5 .4 .1v.4l-.2 .3h-.4M183.9 269.1h.8l-.4 .5 .3 .1 .1 .4-.3 .3h-.3M194.1 269.1h.7l-.4 .5 .4 .1v.4l-.2 .3h-.4M204.2 269.1h.8l-.4 .5 .3 .1 .1 .4-.2 .3h-.4M214.4 269.1h.8l-.5 .5 .4 .1 .1 .4-.3 .3h-.3M224.5 269.1h.8l-.4 .5 .4 .1v.4l-.2 .3h-.4"/>
<path d="M234.7 269.1h.8l-.4 .5 .3 .1 .1 .4-.3 .3h-.3"/>
</g>
<path d="M317.5 139.7v2.5M378.5 154.9v2.6M132.1 247.6v2.6M132.1 248.9h2.5M132.1 278.1v2.6M132.1 279.4h2.5" fill="none" stroke="#840000" stroke-width=".25"/>
<circle cx="309.9" cy="151.1" r="1.27" fill="none" stroke="#000" stroke-width=".18"/>
<path d="M49.5 101h.7l.6 .6-.6 .6h-.7zM189.2 101h.7l.6 .6-.6 .6h-.7zM303.5 156.8h.7l.6 .7-.6 .6h-.7zM303.5 154.3h.7l.6 .6-.6 .7h-.7zM303.5 159.4h.7l.6 .6-.6 .7h-.7zM368.9 174.6h.7v1.3h-.7l-.6-.6zM398.8 169.5h.6l.6 .7-.6 .6h-.6zM398.8 167h.6l.6 .6-.6 .7h-.6zM275.6 210.2h.6l.7 .6-.7 .7h-.6zM24.1 225.4h.7l.6 .7-.6 .6h-.7z" fill="none" stroke="#848400" stroke-width=".18"/>
<path d="M68.6 22.9h106.7M175.3 22.9v12.7M208.3 27.9h137.1M345.4 27.9v7.7M68.6 71.1v-48.2M208.3 71.1v-43.2" fill="none" stroke="#000" stroke-width=".25" stroke-dasharray="2.8 1"/>
<path d="M12.7 127h393.7M266.7 287v-160" fill="none" stroke="#0000c2" stroke-width=".18" stroke-dasharray="1.4 .5"/>
<g fill="none" stroke="#008400" stroke-width=".18">
<path d="M25.4 35.6h38.1M73.7 38.1h12.7M73.7 33h58.4M96.5 38.1h73.7M101.6 38.1v2.5M119.4 33v7.6M124.5 27.9v5.1M134.6 27.9h5.1M142.2 33h28M149.9 27.9v5.1M180.3 35.6h22.9M213.4 38.1h58.4"/>
<path d="M213.4 33h127M233.7 38.1v2.5M243.8 38.1v10.2h7.7M281.9 38.1h58.5M299.7 38.1v5.1h-5.1M309.9 38.1v2.5M320 38.1v2.5M330.2 38.1v2.5M350.5 35.6h12.7M20.3 40.6v5.1M101.6 50.8v2.5M119.4 50.8v2.5"/>
<path d="M233.7 50.8v2.5M243.8 43.2h12.7M261.6 48.3h2.6M266.7 43.2h17.8M274.3 48.3h2.6M276.9 43.2v10.1M309.9 50.8v2.5M320 50.8v2.5M330.2 50.8v2.5M20.3 71.1v2.6h5.1M22.9 73.7v2.5M35.6 73.7h27.9"/>
<path d="M38.1 73.7v2.5M48.3 73.7v2.5M58.4 73.7v10.1h5.1M73.7 73.7h5v22.8M160 71.1v2.6h5.1M162.6 73.7v2.5M175.3 73.7h27.9M177.8 73.7v2.5M188 73.7v2.5M198.1 73.7v10.1h5.1M213.4 73.7h5v22.8M233.7 63.5v2.5"/>
<path d="M276.9 63.5v2.5M73.7 83.8h5M213.4 83.8h5M50.8 101.6h7.6M55.9 101.6v2.5M55.9 114.3v2.5M68.6 101.6h2.5M78.7 106.7v10.1M190.5 101.6h7.6M195.6 101.6v2.5M195.6 114.3v2.5M208.3 101.6h2.5"/>
<path d="M218.4 106.7v10.1M162.6 152.4v10.2h2.5M162.6 157.5h2.5M304.8 157.5h15.2M304.8 154.9h15.2M317.5 152.4v2.5M365.8 154.9h5M378.5 157.5v2.5h-12.7M383.5 149.9h-12.7v7.6h-5M17.8 167.6h66M38.1 167.6v5.1M94 167.6h22.8"/>
<path d="M127 167.6h38.1M134.6 167.6v5.1h5.1M149.9 172.7h15.2M162.6 160h2.5M165.1 177.8h-12.7v15.2M205.7 177.8h5.1v15.2M205.7 172.7h10.2v5.1M205.7 167.6h40.7M233.7 167.6v5.1M256.5 167.6h63.5M304.8 160h15.2M320 170.2h-10.1v40.6h-17.8"/>
<path d="M365.8 167.6h20.3M365.8 175.3h2.5M365.8 170.2h20.3M381 170.2v15.2h-2.5M383.5 167.6v17.8h2.6M396.2 167.6h2.6M396.2 170.2h2.6M38.1 185.4h12.7M38.1 182.9v5.1M38.1 198.1v2.6M48.3 185.4v17.8h5v5.1M61 185.4h30.4"/>
<path d="M63.5 185.4v17.8h-5.1v5.1M73.7 185.4v2.6M73.7 198.1v2.6M83.8 195.6h7.6v25.4M139.7 190.5h-12.7v35.6h-55.9M149.9 190.5h2.5M165.1 190.5v2.5M205.7 188h5.1M205.7 190.5v2.5M205.7 185.4h5.1M205.7 182.9h5.1M215.9 188v5"/>
<path d="M223.5 190.5h10.2M233.7 182.9v12.7M233.7 185.4h2.5M248.9 185.4v2.6M251.5 182.9v2.5h-5.1M279.4 185.4h17.8v10.2M279.4 182.9v5.1M294.6 198.1v-2.5h5.1v2.5M317.5 188h2.5M317.5 185.4h2.5M320 182.9h-2.5v7.6M38.1 218.4v2.6h2.5"/>
<path d="M152.4 203.2v2.5M233.7 205.7v5.1M233.7 208.3h15.2v2.5M241.3 208.3v7.6h2.5M276.9 210.8h5M279.4 210.8v2.6M294.6 208.3v2.5M299.7 208.3v2.5M304.8 210.8v2.6M327.7 208.3v2.5h10.1M335.3 210.8v2.6M348 210.8h33v2.6"/>
<path d="M350.5 210.8v2.6M360.7 210.8v2.6M370.8 210.8v2.6M391.2 208.3v5.1M25.4 226.1h15.2M30.5 226.1v2.5M30.5 238.8v5M38.1 226.1v5h2.5M38.1 228.6h2.5M40.6 236.2h-2.5v7.6M71.1 221h35.6M71.1 233.7h5.1"/>
<path d="M86.4 233.7h5v5.1h-20.3M116.8 221h10.2M233.7 221v2.5M248.9 221v2.5M38.1 241.3h2.5M40.6 251.5h-2.5v2.5M71.1 246.4h5.1M86.4 246.4h5v5.1h-20.3M134.6 248.9h96.5v2.6M139.7 248.9v2.6M149.9 248.9v2.6M160 248.9v2.6"/>
<path d="M170.2 248.9v2.6M180.3 248.9v2.6M190.5 248.9v2.6M200.7 248.9v2.6M210.8 248.9v2.6M221 248.9v2.6M139.7 261.6v2.6M144.8 264.2v2.5M144.8 276.9v2.5M149.9 261.6v2.6M154.9 264.2v2.5M154.9 276.9v2.5"/>
<path d="M160 261.6v2.6M165.1 264.2v2.5M165.1 276.9v2.5M170.2 261.6v2.6M175.3 264.2v2.5M175.3 276.9v2.5M180.3 261.6v2.6M185.4 264.2v2.5M185.4 276.9v2.5M190.5 261.6v2.6M195.6 264.2v2.5M195.6 276.9v2.5"/>
<path d="M200.7 261.6v2.6M205.7 264.2v2.5M205.7 276.9v2.5M210.8 261.6v2.6M215.9 264.2v2.5M215.9 276.9v2.5M221 261.6v2.6M226.1 276.9v2.5h-91.5M226.1 264.2v2.5M231.1 261.6v2.6h-96.5"/>
</g>
<path d="M365.2 179.7l1.2 1.2M366.4 179.7l-1.2 1.2M365.2 187.4l1.2 1.2M365.2 182.3l1.2 1.2M366.4 187.4l-1.2 1.2M366.4 182.3l-1.2 1.2M55.3 207.7l1.2 1.2M56.5 207.7l-1.2 1.2" fill="none" stroke="#000084" stroke-width=".18"/>
<g fill="none" stroke="#0000c2" stroke-width=".18">
<path d="M280.5 24.1v.9M280.8 24.1l-.3 .3M343.1 138.4h.5M343.4 139.2l.2 .1M363.4 138.6l.2-.2 .3 .1v.8M363.4 138.4v.9M365.8 137.9a1.49 1.49 0 0 0 0 1.8M371 138.5h.4M371 139.2h.4M378.6 138.7l-.3-.3-.3 .1-.1 .2 .1 .5 .3 .1 .3-.3M382.6 138.5l.3-.5a.68 .68 0 0 1 .5 .7 .68 .68 0 0 1-.5 .6l-.3-.5M174.3 149l.4 .4"/>
<path d="M174.7 148.6l-.5 .5M181 146.1h.5M181.2 145.6v1.1l.3 .2M196.8 149.4h.7M197 146.3h.4M197.1 148.2l-.3 .3M197.4 145.6h-.4v1.3M203 149.4h.5M203 148.6v1.3M203 148.7h.5M205.2 145.6l-.4 .2M205.4 146.2l-.7 .7h.8"/>
<path d="M207.4 148.6l-.3 .1M211 148.6l.3 .8 .2-.6 .3 .6 .2-.8M211.6 146.2a.31 .31 0 0 0-.4 .3 .31 .31 0 0 0 .4 .3M211.8 145.9a.6 .6 0 0 0-.9 .6 .6 .6 0 0 0 .9 .5M216.2 148.8l.2-.2 .3 .1v.7M217.3 146.1h.4l.1 .8M217.8 146.8l-.5 .1M217.8 146.4h-.5M222.1 145.6l.2 .3-.1 .3-.7 .7h.8M225.7 148.7l.2-.1 .4 .1v.5l-.1 .2h-.3l-.2-.1zM226.9 148.6v.8M227.1 148.6l-.2 .1"/>
<path d="M228.3 145.9a.53 .53 0 0 1 .5 .8h-.2M228.4 146.2l.2 .1M228.6 146.7l-.2 .1M228.6 146.2v.5M228.8 146.9l-.5 .2M229.9 148.6l.4 .2v.6M233.9 148.2l.4 1.2 .5-1.2M343.1 141h.5M343.4 141.8h.2M344 144.2v.2M344 143.6v.1M361.9 141.1l.2-.1h.3v.8"/>
<path d="M361.9 141v.8M363.8 141h.5M364 140.6v1l.2 .2M370.3 141h-.3l-.3 .2 .2 .6h.4M373.2 141.8l.4-1.2 .4 1.2M373.3 141.5h.6M385.6 140.7l.2-.1a.68 .68 0 0 1 .5 .6 .68 .68 0 0 1-.5 .6l-.3-.5zM103.2 236.7v1.1l-.1 .1-.4 .1M103.2 237.5l-.4 .1M115.1 237.5h.5M115.1 236.8h.5M115.6 236.7v1.1l-.2 .1-.3 .1"/>
<path d="M103.1 249.4v1.1l-.1 .1-.3 .1M103.1 250.2l-.4 .1M115.2 250.2h.5M115.2 249.5h.5M115.7 249.4v1.1l-.2 .1-.3 .1"/>
</g>
<g fill="none" stroke="#0000c2" stroke-width=".38">
<path d="M15.7 15.1h1.1M16.2 15.1v1.9M22.7 15.1v.1M27.1 15.1v1.6M28.2 15.1v.1M31.1 15.7h.3l.2 .3v1M38.3 15.1v1.9M40.3 17l.7-1.9 .6 1.9M40.5 16.4h.9M42.3 15.1v1.6M43.3 15.1v1.6M51.2 15.1v1.6"/>
<path d="M52.3 15.1v.1M15.9 129.4v1.9M22 129.4v1.6M25.5 129.5l-.3-.1h-.6v1.9M28.6 129.4l-.3 .1-.1 .1M29.7 129.4l-.3 .1-.1 .1M34.6 130.6v.6M38.9 129.4v1.9M41 131.3l.6-1.9 .7 1.9M41.2 130.7h.9M44 129.5a.66 .66 0 0 0-1 .1M46.2 129.3l-1.7 2.4"/>
<path d="M47.7 129.6l-.5-.2h-.4v1.9M49.8 129.5a.66 .66 0 0 0-1 .1M52 130.8a.66 .66 0 0 0 1.1 .3M53.1 129.5a.66 .66 0 0 0-1.1 .3M59.1 129.4v1.6M60.1 129.4v.1M270.9 129.5l-.2-.1h-.8v1.9M286.2 129.4v1.9M287.9 129.4v1.6M288.8 130.6l.9-.2-.1-.3-.5-.1-.3 .3 .1 .9h.7M293 129.5a.69 .69 0 0 0-.9 .1M295.6 129.4v.1"/>
<path d="M299.4 131.3l.7-1.9 .6 1.9M299.6 130.7h.9M305.6 129.4v1.6M306.6 129.4v.1M308 129.4l-.4 .1-.1 .1M308.6 129.4v.1"/>
</g>
<path d="M373.4 185.4h5.1M373.4 188v2.5M386.1 185.4h5.1M391.2 188v2.5" fill="none" stroke="#a1a1a1" stroke-width=".18"/>
<path d="M369.1 181.1l8.6 8.6M377.7 181.1l-8.6 8.6M386.9 181.1l8.6 8.6M395.5 181.1l-8.6 8.6" fill="none" stroke="#ff2626" stroke-width=".46"/>
<g fill="#008400" stroke="#008400" stroke-width=".18">
<circle cx="119.4" cy="33" r=".46"/>
<circle cx="48.3" cy="73.7" r=".46"/>
<circle cx="22.9" cy="73.7" r=".46"/>
<circle cx="38.1" cy="73.7" r=".46"/>
<circle cx="101.6" cy="38.1" r=".46"/>
<circle cx="134.6" cy="167.6" r=".46"/>
<circle cx="162.6" cy="160" r=".46"/>
<circle cx="162.6" cy="157.5" r=".46"/>
<circle cx="233.7" cy="185.4" r=".46"/>
<circle cx="233.7" cy="167.6" r=".46"/>
<circle cx="210.8" cy="185.4" r=".46"/>
<circle cx="210.8" cy="188" r=".46"/>
<circle cx="210.8" cy="182.9" r=".46"/>
<circle cx="233.7" cy="190.5" r=".46"/>
<circle cx="233.7" cy="208.3" r=".46"/>
<circle cx="152.4" cy="190.5" r=".46"/>
<circle cx="58.4" cy="73.7" r=".46"/>
<circle cx="78.7" cy="83.8" r=".46"/>
<circle cx="53.3" cy="101.6" r=".46"/>
<circle cx="55.9" cy="101.6" r=".46"/>
<circle cx="243.8" cy="43.2" r=".46"/>
<circle cx="243.8" cy="38.1" r=".46"/>
<circle cx="198.1" cy="73.7" r=".46"/>
<circle cx="218.4" cy="83.8" r=".46"/>
<circle cx="195.6" cy="101.6" r=".46"/>
<circle cx="193" cy="101.6" r=".46"/>
<circle cx="233.7" cy="38.1" r=".46"/>
<circle cx="162.6" cy="73.7" r=".46"/>
<circle cx="188" cy="73.7" r=".46"/>
<circle cx="177.8" cy="73.7" r=".46"/>
<circle cx="149.9" cy="33" r=".46"/>
<circle cx="124.5" cy="33" r=".46"/>
<circle cx="185.4" cy="279.4" r=".46"/>
<circle cx="175.3" cy="279.4" r=".46"/>
<circle cx="195.6" cy="279.4" r=".46"/>
<circle cx="185.4" cy="264.2" r=".46"/>
<circle cx="190.5" cy="264.2" r=".46"/>
<circle cx="180.3" cy="264.2" r=".46"/>
<circle cx="200.7" cy="248.9" r=".46"/>
<circle cx="195.6" cy="264.2" r=".46"/>
<circle cx="210.8" cy="248.9" r=".46"/>
<circle cx="221" cy="248.9" r=".46"/>
<circle cx="165.1" cy="279.4" r=".46"/>
<circle cx="165.1" cy="264.2" r=".46"/>
<circle cx="190.5" cy="248.9" r=".46"/>
<circle cx="180.3" cy="248.9" r=".46"/>
<circle cx="170.2" cy="248.9" r=".46"/>
<circle cx="175.3" cy="264.2" r=".46"/>
<circle cx="170.2" cy="264.2" r=".46"/>
<circle cx="210.8" cy="264.2" r=".46"/>
<circle cx="215.9" cy="264.2" r=".46"/>
<circle cx="200.7" cy="264.2" r=".46"/>
<circle cx="215.9" cy="279.4" r=".46"/>
<circle cx="205.7" cy="279.4" r=".46"/>
<circle cx="205.7" cy="264.2" r=".46"/>
<circle cx="226.1" cy="264.2" r=".46"/>
<circle cx="221" cy="264.2" r=".46"/>
<circle cx="276.9" cy="43.2" r=".46"/>
<circle cx="276.9" cy="48.3" r=".46"/>
<circle cx="299.7" cy="38.1" r=".46"/>
<circle cx="309.9" cy="38.1" r=".46"/>
<circle cx="320" cy="38.1" r=".46"/>
<circle cx="279.4" cy="185.4" r=".46"/>
<circle cx="248.9" cy="185.4" r=".46"/>
<circle cx="279.4" cy="210.8" r=".46"/>
<circle cx="299.7" cy="210.8" r=".46"/>
<circle cx="294.6" cy="210.8" r=".46"/>
<circle cx="297.2" cy="195.6" r=".46"/>
<circle cx="350.5" cy="210.8" r=".46"/>
<circle cx="355.6" cy="210.8" r=".46"/>
<circle cx="360.7" cy="210.8" r=".46"/>
<circle cx="335.3" cy="210.8" r=".46"/>
<circle cx="370.8" cy="210.8" r=".46"/>
<circle cx="370.8" cy="154.9" r=".46"/>
<circle cx="381" cy="170.2" r=".46"/>
<circle cx="383.5" cy="167.6" r=".46"/>
<circle cx="317.5" cy="188" r=".46"/>
<circle cx="309.9" cy="175.3" r=".46"/>
<circle cx="317.5" cy="185.4" r=".46"/>
<circle cx="304.8" cy="210.8" r=".46"/>
<circle cx="330.2" cy="38.1" r=".46"/>
<circle cx="309.9" cy="154.9" r=".46"/>
<circle cx="317.5" cy="154.9" r=".46"/>
<circle cx="144.8" cy="279.4" r=".46"/>
<circle cx="154.9" cy="279.4" r=".46"/>
<circle cx="139.7" cy="248.9" r=".46"/>
<circle cx="139.7" cy="264.2" r=".46"/>
<circle cx="149.9" cy="264.2" r=".46"/>
<circle cx="144.8" cy="264.2" r=".46"/>
<circle cx="149.9" cy="248.9" r=".46"/>
<circle cx="160" cy="248.9" r=".46"/>
<circle cx="154.9" cy="264.2" r=".46"/>
<circle cx="160" cy="264.2" r=".46"/>
<circle cx="38.1" cy="185.4" r=".46"/>
<circle cx="48.3" cy="185.4" r=".46"/>
<circle cx="38.1" cy="167.6" r=".46"/>
<circle cx="127" cy="221" r=".46"/>
<circle cx="63.5" cy="185.4" r=".46"/>
<circle cx="73.7" cy="185.4" r=".46"/>
<circle cx="91.4" cy="221" r=".46"/>
<circle cx="38.1" cy="228.6" r=".46"/>
<circle cx="30.5" cy="226.1" r=".46"/>
<circle cx="27.9" cy="226.1" r=".46"/>
<circle cx="38.1" cy="241.3" r=".46"/>
<circle cx="38.1" cy="226.1" r=".46"/>
<circle cx="127" cy="190.5" r=".46"/>
<circle cx="91.4" cy="195.6" r=".46"/>
</g>
<use href="#words"/>
</svg>
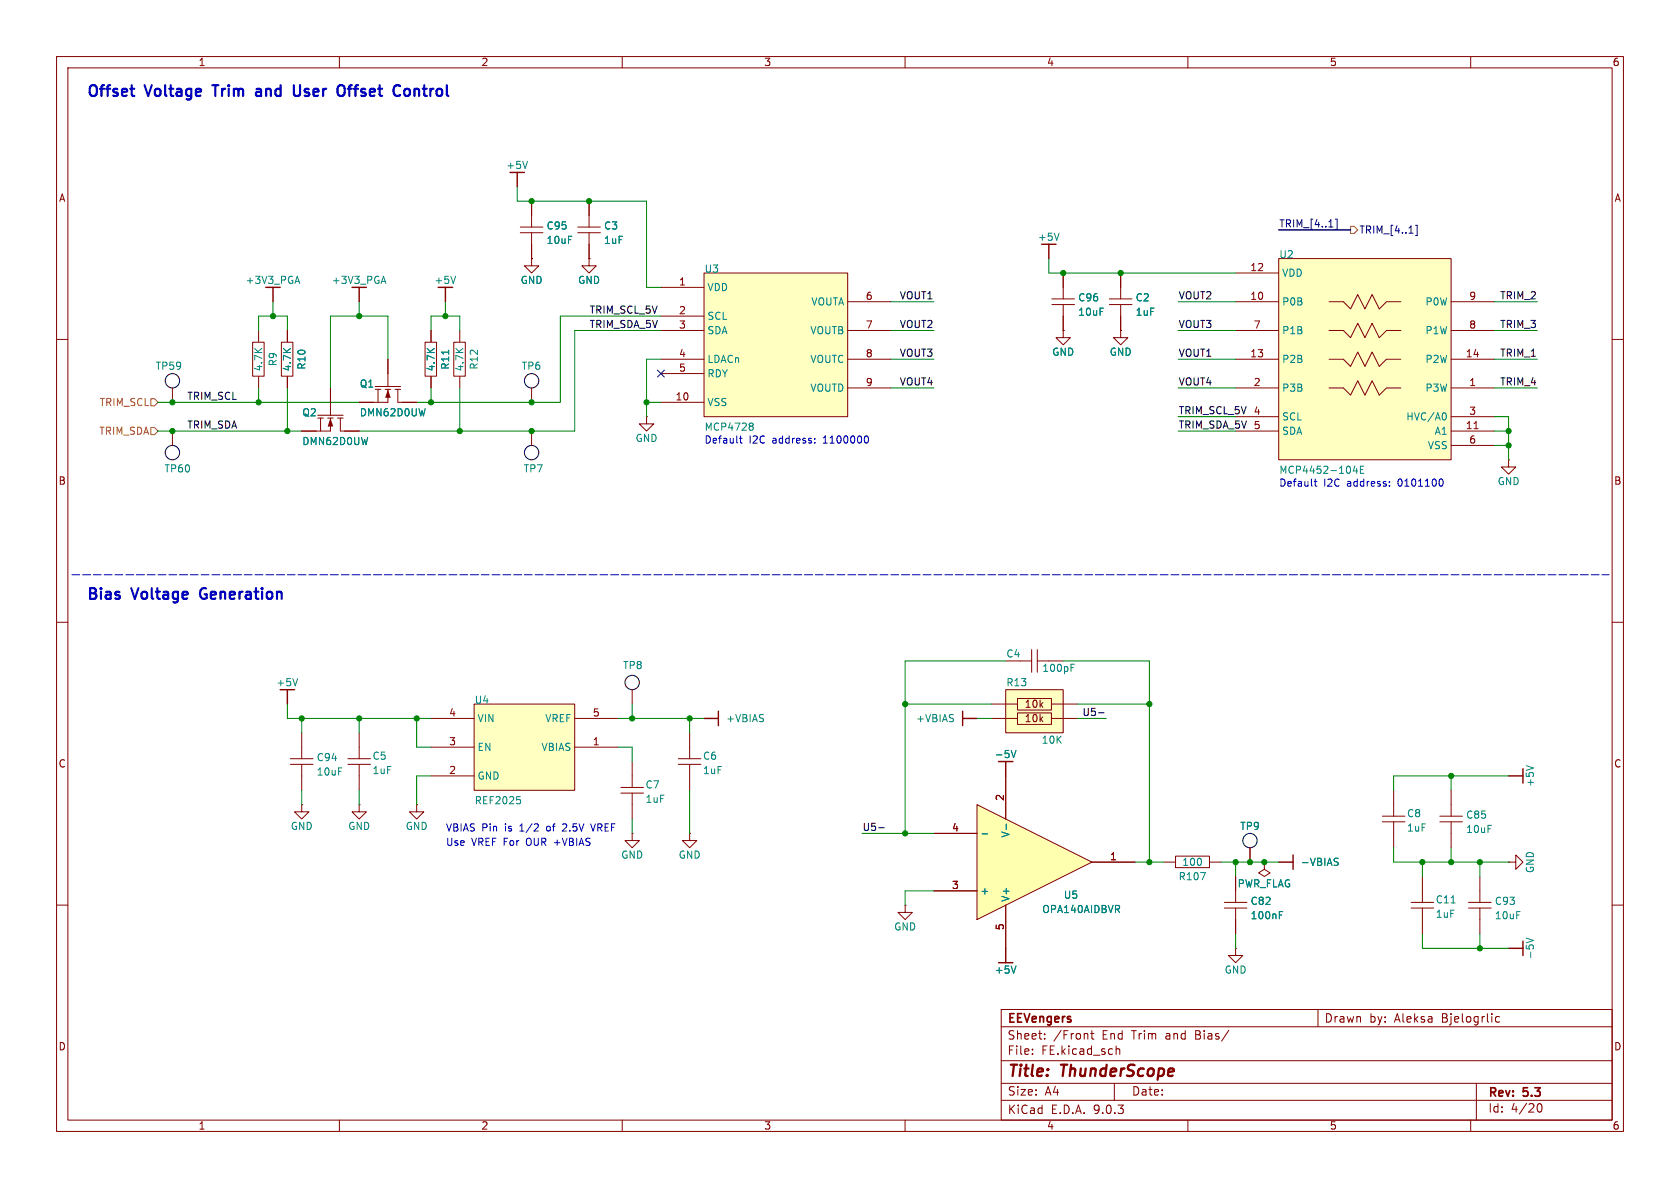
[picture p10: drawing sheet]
<svg xmlns="http://www.w3.org/2000/svg" width="297mm" height="210mm" viewBox="0 0 297 210" stroke-linecap="round" stroke-linejoin="round" font-family="sans-serif">
<defs><g id="words">
<g font-size="2.8" fill="#840000">
<text x="178" y="190.9">Title:</text>
<text x="187.7" y="190.9">ThunderScope</text>
</g>
<g font-size="2.7" fill="#0000c2">
<text x="15.2" y="18">Offset</text>
<text x="25.9" y="18">Voltage</text>
<text x="38.6" y="18">Trim</text>
<text x="46.9" y="18">and</text>
<text x="54.3" y="18">User</text>
<text x="62.9" y="18">Offset</text>
<text x="73.5" y="18">Control</text>
<text x="15.2" y="106.9">Bias</text>
<text x="23.5" y="106.9">Voltage</text>
<text x="36.3" y="106.9">Generation</text>
</g>
<g font-size="2.1" fill="#840000">
<text x="178" y="184">Sheet:</text>
<text x="178" y="181.2">EEVengers</text>
<text x="186.2" y="184">/Front</text>
<text x="194.9" y="184">End</text>
<text x="200.3" y="184">Trim</text>
<text x="206.3" y="184">and</text>
<text x="211.7" y="184">Bias/</text>
<text x="234.1" y="181">Drawn</text>
<text x="242.1" y="181">by:</text>
<text x="246.6" y="181">Aleksa</text>
<text x="255" y="181">Bjelogrlic</text>
<text x="178" y="186.7">File:</text>
<text x="184.1" y="186.7">FE.kicad_sch</text>
<text x="178.1" y="197.1">KiCad</text>
<text x="178.1" y="193.9">Size:</text>
<text x="184.7" y="193.9">A4</text>
<text x="185.8" y="197.1">E.D.A.</text>
<text x="193.4" y="197.1">9.0.3</text>
<text x="200" y="193.9">Date:</text>
<text x="263" y="194.3">Rev:</text>
<text x="263" y="196.9">Id:</text>
<text x="267.1" y="196.9">4/20</text>
<text x="269.4" y="194.3">5.3</text>
</g>
<g font-size="1.8" fill="#840000">
<text x="35" y="11.9">1</text>
<text x="85" y="11.9">2</text>
<text x="135" y="11.9">3</text>
<text x="185" y="11.9">4</text>
<text x="235" y="11.9">5</text>
<text x="285" y="11.9">6</text>
<text x="10.3" y="35.9">A</text>
<text x="285.3" y="35.9">A</text>
<text x="119.9" y="50.5">1</text>
<text x="153" y="53.1">6</text>
<text x="220.9" y="48">12</text>
<text x="220.9" y="53.1">10</text>
<text x="259.6" y="53.1">9</text>
<text x="119.9" y="55.6">2</text>
<text x="119.9" y="58.2">3</text>
<text x="153" y="58.2">7</text>
<text x="221.5" y="58.2">7</text>
<text x="259.6" y="58.2">8</text>
<text x="119.9" y="63.2">4</text>
<text x="119.9" y="65.8">5</text>
<text x="153" y="63.2">8</text>
<text x="220.9" y="63.2">13</text>
<text x="259" y="63.2">14</text>
<text x="119.3" y="70.9">10</text>
<text x="153" y="68.3">9</text>
<text x="221.5" y="68.3">2</text>
<text x="259.6" y="68.3">1</text>
<text x="221.5" y="73.4">4</text>
<text x="259" y="75.9">11</text>
<text x="259.6" y="73.4">3</text>
<text x="259.6" y="78.5">6</text>
<text x="10.3" y="85.9">B</text>
<text x="285.3" y="85.9">B</text>
<text x="181.1" y="125.3">10k</text>
<text x="79.3" y="126.7">4</text>
<text x="79.3" y="131.8">3</text>
<text x="104.7" y="126.7">5</text>
<text x="104.7" y="131.8">1</text>
<text x="181.1" y="127.9">10k</text>
<text x="10.3" y="135.9">C</text>
<text x="79.3" y="136.9">2</text>
<text x="285.3" y="135.9">C</text>
<text x="177.5" y="141.7" transform="rotate(-90 177.5 141.7)">2</text>
<text x="168.2" y="147.1">4</text>
<text x="196.1" y="152.1">1</text>
<text x="168.2" y="157.2">3</text>
<text x="177.5" y="164.5" transform="rotate(-90 177.5 164.5)">5</text>
<text x="10.3" y="185.9">D</text>
<text x="285.3" y="185.9">D</text>
<text x="35" y="199.9">1</text>
<text x="85" y="199.9">2</text>
<text x="135" y="199.9">3</text>
<text x="185" y="199.9">4</text>
<text x="235" y="199.9">5</text>
<text x="285" y="199.9">6</text>
</g>
<g font-size="1.8" fill="#008484">
<text x="89.4" y="30.1">+5V</text>
<text x="96.5" y="40.8">C95</text>
<text x="106.7" y="40.8">C3</text>
<text x="96.5" y="43.3">10uF</text>
<text x="106.7" y="43.3">1uF</text>
<text x="183.4" y="42.8">+5V</text>
<text x="226.1" y="45.9">U2</text>
<text x="43.3" y="50.4">+3V3_PGA</text>
<text x="58.6" y="50.4">+3V3_PGA</text>
<text x="76.7" y="50.4">+5V</text>
<text x="91.9" y="50.4">GND</text>
<text x="102.1" y="50.4">GND</text>
<text x="124.5" y="48.4">U3</text>
<text x="125" y="51.7">VDD</text>
<text x="190.5" y="53.5">C96</text>
<text x="200.7" y="53.5">C2</text>
<text x="226.6" y="49.1">VDD</text>
<text x="125" y="56.7">SCL</text>
<text x="125" y="59.3">SDA</text>
<text x="143.2" y="59.3">VOUTB</text>
<text x="143.3" y="54.2">VOUTA</text>
<text x="190.5" y="56">10uF</text>
<text x="200.7" y="56">1uF</text>
<text x="226.6" y="54.2">P0B</text>
<text x="226.6" y="59.3">P1B</text>
<text x="251.9" y="54.2">P0W</text>
<text x="251.9" y="59.3">P1W</text>
<text x="27.4" y="65.6">TP59</text>
<text x="46.6" y="65.7" transform="rotate(-90 46.6 65.7)">4.7K</text>
<text x="49.1" y="64.8" transform="rotate(-90 49.1 64.8)">R9</text>
<text x="51.7" y="65.7" transform="rotate(-90 51.7 65.7)">4.7K</text>
<text x="54.2" y="65.4" transform="rotate(-90 54.2 65.4)">R10</text>
<text x="77.1" y="65.7" transform="rotate(-90 77.1 65.7)">4.7K</text>
<text x="79.6" y="65.4" transform="rotate(-90 79.6 65.4)">R11</text>
<text x="82.1" y="65.7" transform="rotate(-90 82.1 65.7)">4.7K</text>
<text x="84.7" y="65.4" transform="rotate(-90 84.7 65.4)">R12</text>
<text x="92.1" y="65.6">TP6</text>
<text x="125" y="64.4">LDACn</text>
<text x="143.2" y="64.4">VOUTC</text>
<text x="185.9" y="63.1">GND</text>
<text x="196.1" y="63.1">GND</text>
<text x="226.6" y="64.4">P2B</text>
<text x="251.9" y="64.4">P2W</text>
<text x="63.5" y="68.7">Q1</text>
<text x="125" y="66.9">RDY</text>
<text x="125" y="72">VSS</text>
<text x="143.2" y="69.4">VOUTD</text>
<text x="226.6" y="69.4">P3B</text>
<text x="251.9" y="69.4">P3W</text>
<text x="53.3" y="73.8">Q2</text>
<text x="63.5" y="73.8">DMN62D0UW</text>
<text x="124.5" y="76.3">MCP4728</text>
<text x="226.6" y="74.5">SCL</text>
<text x="226.6" y="77.1">SDA</text>
<text x="248.5" y="74.5">HVC/A0</text>
<text x="253.5" y="77.1">A1</text>
<text x="29" y="83.7">TP60</text>
<text x="53.3" y="78.9">DMN62D0UW</text>
<text x="92.5" y="83.7">TP7</text>
<text x="112.3" y="78.3">GND</text>
<text x="226.1" y="84">MCP4452-104E</text>
<text x="252.3" y="79.6">VSS</text>
<text x="264.7" y="86">GND</text>
<text x="110.1" y="118.5">TP8</text>
<text x="177.8" y="116.4">C4</text>
<text x="184.2" y="119">100pF</text>
<text x="48.8" y="121.5">+5V</text>
<text x="83.8" y="124.6">U4</text>
<text x="177.8" y="121.5">R13</text>
<text x="84.3" y="127.9">VIN</text>
<text x="96.3" y="127.9">VREF</text>
<text x="128.3" y="127.9">+VBIAS</text>
<text x="161.9" y="127.9">+VBIAS</text>
<text x="184.1" y="131.7">10K</text>
<text x="55.9" y="134.8">C94</text>
<text x="55.9" y="137.3">10uF</text>
<text x="65.8" y="134.5">C5</text>
<text x="65.8" y="137">1uF</text>
<text x="84.3" y="132.9">EN</text>
<text x="95.6" y="132.9">VBIAS</text>
<text x="124.2" y="134.5">C6</text>
<text x="124.2" y="137">1uF</text>
<text x="175.8" y="134.2">-5V</text>
<text x="83.8" y="142.4">REF2025</text>
<text x="84.3" y="138">GND</text>
<text x="114" y="139.6">C7</text>
<text x="114" y="142.1">1uF</text>
<text x="271.4" y="139.2" transform="rotate(-90 271.4 139.2)">+5V</text>
<text x="51.3" y="146.9">GND</text>
<text x="61.5" y="146.9">GND</text>
<text x="71.6" y="146.9">GND</text>
<text x="178.7" y="148.2" transform="rotate(-90 178.7 148.2)">V-</text>
<text x="219.2" y="146.9">TP9</text>
<text x="248.6" y="144.7">C8</text>
<text x="248.6" y="147.2">1uF</text>
<text x="259.1" y="144.9">C85</text>
<text x="259.1" y="147.5">10uF</text>
<text x="109.7" y="152">GND</text>
<text x="119.9" y="152">GND</text>
<text x="208.3" y="155.8">R107</text>
<text x="208.9" y="153.3">100</text>
<text x="229.9" y="153.3">-VBIAS</text>
<text x="271.4" y="154.4" transform="rotate(-90 271.4 154.4)">GND</text>
<text x="173.2" y="158.3">+</text>
<text x="178.7" y="159.5" transform="rotate(-90 178.7 159.5)">V+</text>
<text x="184.2" y="161.6">OPA140AIDBVR</text>
<text x="188" y="159.1">U5</text>
<text x="218.7" y="157.1">PWR_FLAG</text>
<text x="221" y="160.2">C82</text>
<text x="253.7" y="159.9">C11</text>
<text x="264.2" y="160.2">C93</text>
<text x="158" y="164.7">GND</text>
<text x="221" y="162.7">100nF</text>
<text x="253.7" y="162.4">1uF</text>
<text x="264.2" y="162.7">10uF</text>
<text x="175.8" y="172.3">+5V</text>
<text x="216.4" y="172.3">GND</text>
<text x="271.4" y="169.7" transform="rotate(-90 271.4 169.7)">-5V</text>
</g>
<g font-size="1.8" fill="#000084">
<text x="226.1" y="40.3">TRIM_[4..1]</text>
<text x="240.2" y="41.5">TRIM_[4..1]</text>
</g>
<g font-size="1.8">
<text x="159" y="53">VOUT1</text>
<text x="208.3" y="53">VOUT2</text>
<text x="265.1" y="53">TRIM_2</text>
<text x="104.1" y="55.5">TRIM_SCL_5V</text>
<text x="104.1" y="58.1">TRIM_SDA_5V</text>
<text x="159" y="58.1">VOUT2</text>
<text x="208.3" y="58.1">VOUT3</text>
<text x="265.1" y="58.1">TRIM_3</text>
<text x="159" y="63.2">VOUT3</text>
<text x="208.3" y="63.2">VOUT1</text>
<text x="265.1" y="63.2">TRIM_1</text>
<text x="33" y="70.8">TRIM_SCL</text>
<text x="159" y="68.2">VOUT4</text>
<text x="208.3" y="68.2">VOUT4</text>
<text x="265.1" y="68.2">TRIM_4</text>
<text x="33" y="75.9">TRIM_SDA</text>
<text x="208.3" y="73.3">TRIM_SCL_5V</text>
<text x="208.3" y="75.9">TRIM_SDA_5V 5</text>
<text x="191.3" y="126.7">U5-</text>
<text x="152.4" y="147">U5-</text>
</g>
<g font-size="1.8" fill="#848400">
<text x="17.5" y="72">TRIM_SCL</text>
<text x="17.4" y="77.1">TRIM_SDA</text>
</g>
<g font-size="1.8" fill="#0000c2">
<text x="124.5" y="78.5">Default</text>
<text x="132.4" y="78.5">I2C</text>
<text x="136.7" y="78.5">address:</text>
<text x="145.8" y="78.5">1100000</text>
<text x="226.1" y="86.1">Default</text>
<text x="234" y="86.1">I2C</text>
<text x="238.3" y="86.1">address:</text>
<text x="247.4" y="86.1">0101100</text>
<text x="78.7" y="147.1">VBIAS</text>
<text x="78.7" y="149.6">Use</text>
<text x="83.4" y="149.6">VREF For</text>
<text x="85.2" y="147.1">Pin</text>
<text x="89.4" y="147.1">is</text>
<text x="92.2" y="147.1">1/2</text>
<text x="93.4" y="149.6">OUR +VBIAS</text>
<text x="97.2" y="147.1">of</text>
<text x="100.2" y="147.1">2.5V</text>
<text x="105.5" y="147.1">VREF</text>
</g>
</g></defs>
<path d="M0 0h297v210h-297z" fill="#fff" stroke="#fff" stroke-width=".18"/>
<g fill="none" stroke="#840000" stroke-width=".18">
<path d="M10 10h277v190h-277zM12 12h273v186h-273zM60 10v2M110 10v2M160 10v2M210 10v2M260 10v2M104.1 35.6v4.5M102.1 40.1h4M102.1 41.1h4M104.1 41.1v4.6M10 60h2"/>
<path d="M66.3 68.3h4.5M68.6 66v2.3M69.8 68.8h1M285 60h2M10 110h2M285 110h2M10 160h2M177 178.5h108v19.5h-108zM233 178.5v3M265.1 179.8l-.4-.1-.3 .3v.4l.1 .2h.6M285 160h2M60 198v2"/>
<path d="M110 198v2M160 198v2M177 194.5h108M177 191.5h108M177 187.5h108M177 181.5h108M182.5 186.3v.1M182.5 185.5v.1M184.7 183.6v.1M184.7 182.8v.1M192.8 182.7h.6M193 182.2v1.3l.4 .2"/>
<path d="M197 191.5v3M197.3 184.9v1.5M197.3 185.5l.2-.1 .4 .1 .1 .9M210 198v2M217.2 182.1l-1.2 2M260 198v2M261 191.5v6.5M271.7 195.7l.2-.5 .2-.1a.81 .81 0 0 1 .6 .6 .81 .81 0 0 1-.3 .8h-.4l-.3-.5"/>
</g>
<path d="M68.6 68.8l.5 1.5h-1z" fill="#840000"/>
<path d="M66.3 68.8h1M66.8 68.8v2.3M68.1 68.8h1M68.6 68.8v2.3h-5.1M68.6 63.5v2.5M70.3 68.8v2.3M70.4 71.1h3.3" fill="none" stroke="#840000" stroke-width=".18"/>
<path d="M172.7 142.2l20.3 10.2-20.3 10.2z" fill="#ffffb0"/>
<path d="M172.7 142.2l20.3 10.2-20.3 10.2z" fill="none" stroke="#800000" stroke-width=".18"/>
<g fill="none" stroke="#840000" stroke-width=".18">
<path d="M30.5 76.2v2.5M56.2 73.4h4.5M58.4 71.1v2.3M59.7 73.9h1M61.5 134.1h4M61.5 135.1h4M63.5 129.5v4.6M63.5 135.1v4.6M109.8 139.2h4M111.8 134.6v4.6M177.8 137.2v7.6M109.8 140.2h4"/>
<path d="M111.8 140.2v4.6M165.1 157.5h7.6M165.1 147.3h7.6M193 152.4h7.7M160 160v1.3h1.3l-1.3 1.3-1.3-1.3h1.3M160 160h.1M177.8 160v7.6"/>
</g>
<path d="M178.8 132.7l.4 1.2 .4-1.2M173.6 147.4h1M177.9 145.7v1M179.6 170.8l-.4 1.2" fill="none" stroke="#008484" stroke-width=".18"/>
<path d="M170.2 125.7v2.6M170.2 127h2.5M177.8 134.6v2.6M176.5 170.2h2.6M177.8 167.6v2.6" fill="none" stroke="#840000" stroke-width=".25"/>
<circle cx="30.5" cy="80" r="1.27" fill="none" stroke="#000" stroke-width=".18"/>
<path d="M58.4 73.9l.5 1.5h-1z" fill="#840000"/>
<g fill="none" stroke="#840000" stroke-width=".18">
<path d="M56.2 73.9h1M56.7 73.9v2.3M57.9 73.9h1M58.4 73.9v2.3h-5.1M58.4 68.6v2.5M60.2 73.9v2.3M60.2 76.2h3.3M259.6 159.5h4M261.6 154.9v4.6M266.7 152.4h1.3v-1.3l1.2 1.3-1.2 1.3v-1.3M266.7 152.4h.1M218.4 167.6v1.3h1.3l-1.3 1.3-1.2-1.3h1.2"/>
<path d="M218.4 167.6h.1M259.6 160.5h4M261.6 160.5v4.6"/>
</g>
<path d="M266.7 167.6h2.5M269.2 166.4v2.5" fill="none" stroke="#840000" stroke-width=".25"/>
<path d="M269.8 165.8l1.3 .4-1.3 .5" fill="none" stroke="#008484" stroke-width=".18"/>
<path d="M177.8 121.9h10.2v7.6h-10.2z" fill="#ffffc2"/>
<g fill="none" stroke="#840000" stroke-width=".18">
<path d="M30.5 68.6v2.5M175.3 124.5h4.5M175.3 127h4.5M179.9 123.5h6v2h-6zM179.9 126h6v2.1h-6zM186 124.5h4.5M186 127h4.5M53.3 142.2v1.3h1.3l-1.3 1.3-1.2-1.3h1.2M53.3 142.2h.1M111.8 147.3v1.3h1.2l-1.2 1.3-1.3-1.3h1.3M111.8 147.3h.1M221 149.9v2.5"/>
<path d="M249.5 159.5h4M251.5 154.9v4.6M249.5 160.5h4M251.5 160.5v4.6"/>
</g>
<path d="M177.8 121.9h10.2v7.6h-10.2z" fill="none" stroke="#800000" stroke-width=".18"/>
<g fill="none" stroke="#000" stroke-width=".18">
<circle cx="30.5" cy="67.3" r="1.27"/>
<circle cx="221" cy="148.6" r="1.27"/>
</g>
<path d="M269.8 135.3l1.3 .5M256.5 159.6h.8" fill="none" stroke="#008484" stroke-width=".18"/>
<path d="M266.7 137.2h2.5M269.2 135.9v2.5" fill="none" stroke="#840000" stroke-width=".25"/>
<path d="M83.8 124.5h17.8v15.2h-17.8z" fill="#ffffc2"/>
<path d="M83.8 124.5h17.8v15.2h-17.8z" fill="none" stroke="#800000" stroke-width=".18"/>
<g fill="none" stroke="#840000" stroke-width=".18">
<path d="M76.2 58.4v2M81.3 58.4v2M75.1 60.5h2.1v6h-2.1zM76.2 66.6v2M80.2 60.5h2.1v6h-2.1zM81.3 66.6v2M94 68.6v2.5M180.3 116.8h2.1M182.4 114.8v4M183.4 114.8v4M183.4 116.8h4.6M76.2 127h7.6"/>
<path d="M76.2 132.1h7.6M76.2 137.2h7.6M101.6 127h7.6M101.6 132.1h7.6M63.5 142.2v1.3h1.3l-1.3 1.3-1.3-1.3h1.3M63.5 142.2h.1M73.7 142.2v1.3h1.2l-1.2 1.3-1.3-1.3h1.3M73.7 142.2h.1M121.9 147.3v1.3h1.3l-1.3 1.3-1.3-1.3h1.3M121.9 147.3h.1M205.7 152.4h2M207.8 151.3h6v2.1h-6z"/>
<path d="M213.9 152.4h2M216.4 159.5h4M218.4 154.9v4.6M216.4 160.5h4M218.4 160.5v4.6"/>
</g>
<path d="M79.3 61.9v.7M189.3 118h.5M189.3 117.4h.6M91.4 140.8h.6M91.8 141.3l.2 .3v.3l-.2 .2M212.2 154.2h.9l-.6 1.3M226.2 161.7h.4M226.2 161.1h.6" fill="none" stroke="#008484" stroke-width=".18"/>
<circle cx="94" cy="67.3" r="1.27" fill="none" stroke="#000" stroke-width=".18"/>
<path d="M124.5 48.3h25.4v25.4h-25.4z" fill="#ffffc2"/>
<path d="M124.5 48.3h25.4v25.4h-25.4z" fill="none" stroke="#800000" stroke-width=".18"/>
<g fill="none" stroke="#840000" stroke-width=".18">
<path d="M94 35.6v4.5M92 40.1h4M92 41.1h4M94 45.7v1.3h1.2l-1.2 1.3-1.3-1.3h1.3M94 45.7h.1M94 41.1v4.6M104.1 45.7v1.3h1.3l-1.3 1.3-1.2-1.3h1.2M104.1 45.7h.1M116.8 50.8h7.7M116.8 55.9h7.7M116.8 58.4h7.7M149.9 58.4h7.6"/>
<path d="M149.9 53.3h7.6M186 52.8h4M186 53.8h4M188 58.4v1.3h1.2l-1.2 1.3-1.3-1.3h1.3M188 58.4h.1M188 48.3v4.5M188 53.8v4.6M94 76.2v2.5M114.3 73.7v1.2h1.3l-1.3 1.3-1.3-1.3h1.3M114.3 73.7h.1M116.8 63.5h7.7M116.8 66h7.7"/>
<path d="M116.8 71.1h7.7M149.9 63.5h7.6M149.9 68.6h7.6M266.7 81.3v1.3h1.3l-1.3 1.2-1.3-1.2h1.3M266.7 81.3h.1M51.3 134.1h4M51.3 135.1h4M53.3 129.5v4.6M53.3 135.1v4.6M111.8 121.9v2.6M119.9 134.1h4M119.9 135.1h4"/>
<path d="M121.9 129.5v4.6M121.9 135.1v4.6M246.4 139.7v4.6M256.5 139.7v4.6M223.5 152.4v1.3l1 .6-1 .6-1-.6 1-.6M223.5 152.4h.1M244.4 144.3h4M244.4 145.3h4M246.4 145.3v4.6M254.5 144.3h4M254.5 145.3h4M256.5 145.3v4.6"/>
</g>
<path d="M93.3 28.5l-.5 1.3M80.6 48.8l-.5 1.3M187.2 41.2l-.4 1.3M132.7 74.8h.2l.3 .2-.3 .3M132.7 75.3h.2M132.9 75.3l.3 .3v.2l-.2 .2-.3 .1M52.6 120l-.4 1.2M236.1 152.3l.4 .1 .1 .3-.3 .3h-.3M236.1 151.7l.5 .1" fill="none" stroke="#008484" stroke-width=".18"/>
<path d="M91.4 30.5v2.5M78.7 50.8v2.5M185.4 43.2v2.5M50.8 121.9v2.6M124.5 127h2.5M127 125.7v2.6M226.1 152.4h2.5M228.6 151.1v2.6" fill="none" stroke="#840000" stroke-width=".25"/>
<g fill="none" stroke="#000" stroke-width=".18">
<circle cx="94" cy="80" r="1.27"/>
<circle cx="111.8" cy="120.6" r="1.27"/>
</g>
<path d="M226.1 45.7h30.4v35.6h-30.4z" fill="#ffffc2"/>
<g fill="none" stroke="#840000" stroke-width=".18">
<path d="M94 35.6v2.5M104.1 35.6v2.5M45.7 58.4v2M50.8 58.4v2M76.2 58.4v2M94 45.7h.1M94 43.2v2.5M104.1 45.7h.1M104.1 43.2v2.5M188 58.4h.1M188 48.3v2.5M188 55.9v2.5"/>
<path d="M196.1 52.8h4M196.1 53.8h4M198.1 58.4v1.3h1.3l-1.3 1.3-1.3-1.3h1.3M198.1 58.4h.1M198.1 48.3v4.5M198.1 53.8v4.6M218.4 53.3h7.7M218.4 58.4h7.7M218.4 48.3h7.7M234.9 53.3h2.6l1.3 1.3 1.2-2.5 1.3 2.5 1.3-2.5 1.2 2.5 1.3-1.3h2.5M234.9 58.4h2.6l1.3 1.3 1.2-2.5 1.3 2.5 1.3-2.5 1.2 2.5 1.3-1.3h2.5M256.5 53.3h7.7"/>
<path d="M256.5 58.4h7.7M44.7 60.5h2v6h-2zM45.7 66.6v2M49.7 60.5h2.1v6h-2.1zM50.8 66.6v2M53.3 76.2h2.6M58.4 68.6v2.5M61 76.2h2.5M63.5 71.1h2.5M68.6 63.5v2.5M71.1 71.1h2.6M76.2 66.6v2"/>
<path d="M218.4 63.5h7.7M218.4 68.6h7.7M218.4 73.7h7.7M218.4 76.2h7.7M234.9 63.5h2.6l1.3 1.3 1.2-2.6 1.3 2.6 1.3-2.6 1.2 2.6 1.3-1.3h2.5M234.9 68.6h2.6l1.3 1.3 1.2-2.6 1.3 2.6 1.3-2.6 1.2 2.6 1.3-1.3h2.5M256.5 63.5h7.7M256.5 68.6h7.7M256.5 73.7h7.7M256.5 76.2h7.7M256.5 78.7h7.7M260.6 75.8h.7"/>
<path d="M177.8 137.2v7.6M165.1 157.5h7.6M165.1 147.3h7.6M193 152.4h7.7M218.4 154.9v2.6M221 149.9v2.5M223.5 152.4h.1M177.8 160v7.6M218.4 162.6v2.5"/>
</g>
<path d="M226.1 45.7h30.4v35.6h-30.4z" fill="none" stroke="#800000" stroke-width=".18"/>
<g fill="none" stroke="#008484" stroke-width=".18">
<path d="M52.3 49.7h.6M52.6 48.8l.4 1.3M67.5 49.7h.6M67.8 48.8l.4 1.3M79.3 61.9v.7M255.4 73a.79 .79 0 0 1 0 1.2M239.5 82.3l-.3 1h.8M239.8 82.8v.9M240.5 83h.4M241.1 82.4h-.6v1.3h.6M178.8 132.7l.4 1.2 .4-1.2M173.6 147.4h1"/>
<path d="M177.9 145.7v1M236.1 152.3l.4 .1 .1 .3-.3 .3h-.3M236.1 151.7l.5 .1M179.6 170.8l-.4 1.2M226.2 161.7h.4M226.2 161.1h.6"/>
</g>
<path d="M48.3 50.8v2.5M63.5 50.8v2.5" fill="none" stroke="#840000" stroke-width=".25"/>
<path d="M238.8 40h.6l.6 .6-.6 .7h-.6zM26.7 75.6h.6l.6 .6-.6 .6h-.6zM26.7 70.5h.6l.6 .6-.6 .7h-.6z" fill="none" stroke="#848400" stroke-width=".18"/>
<path d="M236.1 38.7h.3v1.9h-.3M250.2 39.8h.3v1.8h-.3M116.2 65.4l1.2 1.2M117.4 65.4l-1.2 1.2" fill="none" stroke="#000084" stroke-width=".18"/>
<path d="M194.2 126h1M155.3 146.3h1" fill="none" stroke="#000" stroke-width=".18"/>
<path d="M12.7 101.6h271.8" fill="none" stroke="#0000c2" stroke-width=".18" stroke-dasharray="1.4 .5"/>
<path d="M226.1 40.6h12.7" fill="none" stroke="#000084" stroke-width=".25"/>
<g fill="none" stroke="#008400" stroke-width=".18">
<path d="M91.4 33v2.6h22.9v15.2h2.5M45.7 58.4v-2.5h5.1v2.5M48.3 53.3v2.6M63.5 53.3v2.6M76.2 58.4v-2.5h5.1v2.5M78.7 53.3v2.6M116.8 55.9h-17.7v15.2h-25.4M116.8 58.4h-15.2v17.8h-38.1M157.5 58.4h7.6M157.5 53.3h7.6M185.4 45.7v2.6h33M208.3 58.4h10.1"/>
<path d="M208.3 53.3h10.1M264.2 58.4h7.6M264.2 53.3h7.6M27.9 71.1h35.6M27.9 76.2h25.4M45.7 68.6v2.5M50.8 68.6v7.6M68.6 63.5v-7.6h-10.2v12.7M76.2 68.6v2.5M81.3 68.6v7.6M114.3 71.1h2.5M116.8 63.5h-2.5v10.2"/>
<path d="M157.5 63.5h7.6M157.5 68.6h7.6M208.3 63.5h10.1M208.3 68.6h10.1M208.3 76.2h10.1M208.3 73.7h10.1M264.2 63.5h7.6M264.2 68.6h7.6M264.2 76.2h2.5M264.2 73.7h2.5v7.6M264.2 78.7h2.5M177.8 116.8h-17.8v30.5"/>
<path d="M188 116.8h15.2v35.6M50.8 124.5v2.5h25.4M53.3 127v2.5M53.3 139.7v2.5M63.5 127v2.5M63.5 139.7v2.5M73.7 127v5.1h2.5M76.2 137.2h-2.5v5M109.2 127h15.3M109.2 132.1h2.6v2.5M111.8 124.5v2.5M121.9 127v2.5"/>
<path d="M121.9 139.7v7.6M160 124.5h15.3M172.7 127h2.6M190.5 127h5.1M190.5 124.5h12.7M256.5 137.2v2.5M266.7 137.2h-20.3v2.5M111.8 144.8v2.5M152.4 147.3h12.7M165.1 157.5h-5.1v2.5M200.7 152.4h5M215.9 152.4h10.2"/>
<path d="M218.4 152.4v2.5M246.4 149.9v2.5h20.3M251.5 152.4v2.5M256.5 149.9v2.5M261.6 152.4v2.5M218.4 165.1v2.5M251.5 165.1v2.5h15.2M261.6 165.1v2.5"/>
</g>
<g fill="none" stroke="#0000c2" stroke-width=".18">
<path d="M130.7 77.5h.5M130.9 77.1v1l.3 .2M144 78.2v.1M144 77.5v.2M153.2 77.1a.79 .79 0 0 1 0 1.2M232.3 85.1h.5M232.5 84.7v1.1l.3 .1M245.6 85.8v.1M245.6 85.2v.1M254.8 84.7a.79 .79 0 0 1 0 1.2M100 145.6l-.5 .2M100.1 146.2l-.7 .7h.8"/>
<path d="M104.4 145.6l.4 1.3 .5-1.3"/>
</g>
<g fill="none" stroke="#0000c2" stroke-width=".38">
<path d="M15.9 15.3a.65 .65 0 0 1 1.1 0M18.4 15.1l-.4 .1-.1 .1M19.5 15.1l-.4 .1-.1 .1M23.3 15.1v1.6M25.6 15.1l.6 1.9 .6-1.9M29.2 15.1v1.6M30.2 15.1v1.6M37.5 15.1h1.1M38.1 15.1v1.9M40.4 15.1l-.1 .1h.1M40.4 15.1l.1 .1h-.1M40.4 15.1v.1"/>
<path d="M45.3 15.8l.6-.1 .3 .3M46.2 16.1l-.7 .1a.37 .37 0 0 0-.3 .4 .37 .37 0 0 0 .3 .4l.7-.1M49.6 15.1v1.9M52 15.1v1.5M53 15.1v1.5l-.1 .3-.6 .1M59.8 15.3a.65 .65 0 0 1 1 0M61.5 15.7h.7M62.2 15.1l-.4 .1v.1v1.7M63.3 15.1l-.4 .1-.1 .1M67.1 15.1v1.6M70.7 15.2a.66 .66 0 0 0-1 .1M71.6 15.8a.52 .52 0 0 1 .9 .3v.5a.52 .52 0 0 1-.5 .4 .52 .52 0 0 1-.5-.4v-.5z"/>
<path d="M75 15.1v1.6M79 15.1v1.6M16.9 104.1l-.3-.1h-.7v1.9M17.8 104v.1M17.8 104l.1 .1h-.1M23.2 104l.6 1.9 .7-1.9M26.8 104v1.6M27.8 104v1.6M36.4 104.1a.79 .79 0 0 0-.8 .1 .79 .79 0 0 0-.2 .8l.1 .6M45.2 104v1.6M46.3 104l-.1 .1h.1M46.3 104l.1 .1h-.1"/>
<path d="M46.3 104v.1"/>
</g>
<g fill="#008400" stroke="#008400" stroke-width=".18">
<circle cx="203.2" cy="152.4" r=".46"/>
<circle cx="203.2" cy="124.5" r=".46"/>
<circle cx="218.4" cy="152.4" r=".46"/>
<circle cx="94" cy="71.1" r=".46"/>
<circle cx="94" cy="35.6" r=".46"/>
<circle cx="104.1" cy="35.6" r=".46"/>
<circle cx="114.3" cy="71.1" r=".46"/>
<circle cx="188" cy="48.3" r=".46"/>
<circle cx="198.1" cy="48.3" r=".46"/>
<circle cx="160" cy="124.5" r=".46"/>
<circle cx="160" cy="147.3" r=".46"/>
<circle cx="121.9" cy="127" r=".46"/>
<circle cx="111.8" cy="127" r=".46"/>
<circle cx="53.3" cy="127" r=".46"/>
<circle cx="30.5" cy="76.2" r=".46"/>
<circle cx="30.5" cy="71.1" r=".46"/>
<circle cx="81.3" cy="76.2" r=".46"/>
<circle cx="94" cy="76.2" r=".46"/>
<circle cx="73.7" cy="127" r=".46"/>
<circle cx="63.5" cy="127" r=".46"/>
<circle cx="256.5" cy="137.2" r=".46"/>
<circle cx="266.7" cy="78.7" r=".46"/>
<circle cx="266.7" cy="76.2" r=".46"/>
<circle cx="78.7" cy="55.9" r=".46"/>
<circle cx="50.8" cy="76.2" r=".46"/>
<circle cx="45.7" cy="71.1" r=".46"/>
<circle cx="76.2" cy="71.1" r=".46"/>
<circle cx="48.3" cy="55.9" r=".46"/>
<circle cx="63.5" cy="55.9" r=".46"/>
<circle cx="261.6" cy="167.6" r=".46"/>
<circle cx="221" cy="152.4" r=".46"/>
<circle cx="251.5" cy="152.4" r=".46"/>
<circle cx="261.6" cy="152.4" r=".46"/>
<circle cx="256.5" cy="152.4" r=".46"/>
<circle cx="223.5" cy="152.4" r=".46"/>
</g>
<use href="#words"/>
</svg>
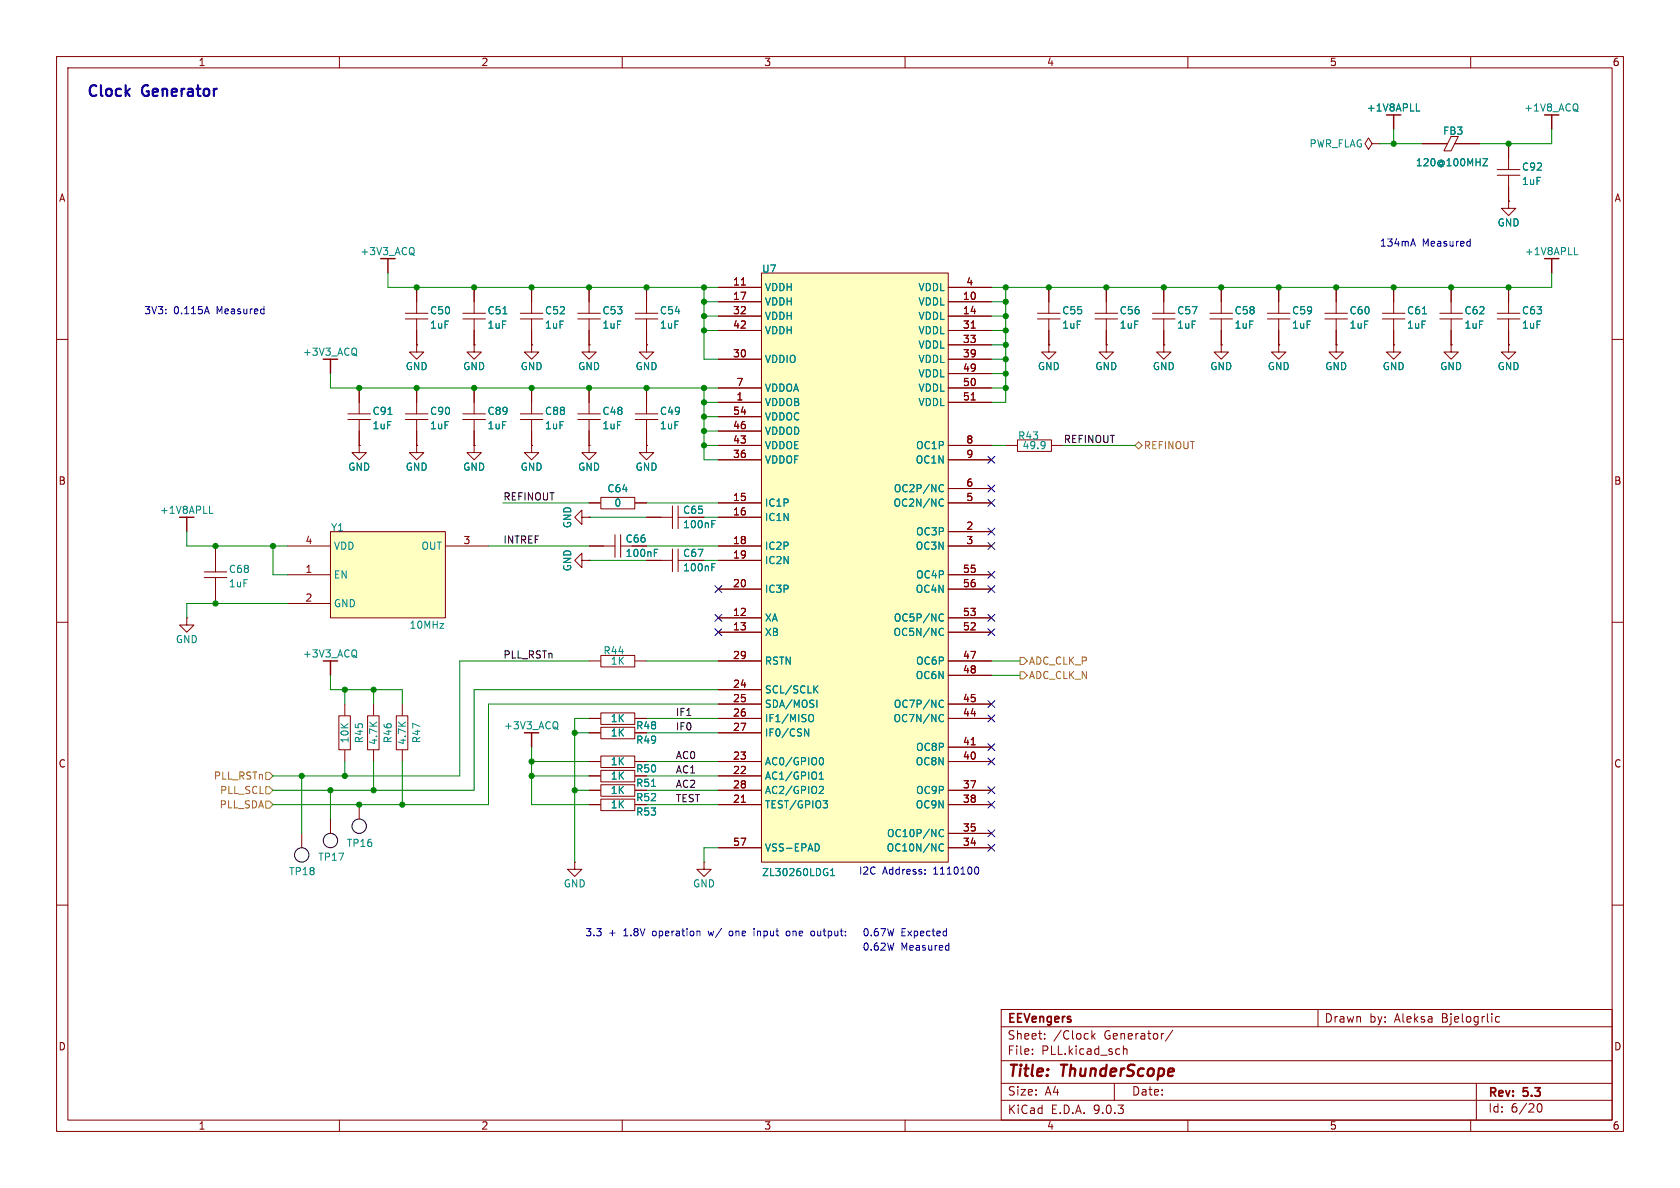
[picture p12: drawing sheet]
<svg xmlns="http://www.w3.org/2000/svg" width="297mm" height="210mm" viewBox="0 0 297 210" stroke-linecap="round" stroke-linejoin="round" font-family="sans-serif">
<defs><g id="words">
<g font-size="2.8" fill="#840000">
<text x="178" y="190.9">Title:</text>
<text x="187.7" y="190.9">ThunderScope</text>
</g>
<g font-size="2.7" fill="#0000c2">
<text x="15.2" y="18">Clock</text>
<text x="25.3" y="18">Generator</text>
</g>
<g font-size="2.1" fill="#840000">
<text x="178" y="184">Sheet:</text>
<text x="178" y="181.2">EEVengers</text>
<text x="186.2" y="184">/Clock</text>
<text x="195.2" y="184">Generator/</text>
<text x="234.1" y="181">Drawn</text>
<text x="242.1" y="181">by:</text>
<text x="246.6" y="181">Aleksa</text>
<text x="255" y="181">Bjelogrlic</text>
<text x="178" y="186.7">File:</text>
<text x="184.1" y="186.7">PLL.kicad_sch</text>
<text x="178.1" y="197.1">KiCad</text>
<text x="178.1" y="193.9">Size:</text>
<text x="184.7" y="193.9">A4</text>
<text x="185.8" y="197.1">E.D.A.</text>
<text x="193.4" y="197.1">9.0.3</text>
<text x="200" y="193.9">Date:</text>
<text x="263" y="194.3">Rev:</text>
<text x="263" y="196.9">Id:</text>
<text x="267.1" y="196.9">6/20</text>
<text x="269.4" y="194.3">5.3</text>
</g>
<g font-size="1.8" fill="#840000">
<text x="35" y="11.9">1</text>
<text x="85" y="11.9">2</text>
<text x="135" y="11.9">3</text>
<text x="185" y="11.9">4</text>
<text x="235" y="11.9">5</text>
<text x="285" y="11.9">6</text>
<text x="10.3" y="35.9">A</text>
<text x="285.3" y="35.9">A</text>
<text x="129.5" y="50.5">11</text>
<text x="129.5" y="53.1">17</text>
<text x="170.1" y="53.1">10</text>
<text x="170.7" y="50.5">4</text>
<text x="129.5" y="55.6">32</text>
<text x="129.5" y="58.2">42</text>
<text x="170.1" y="55.6">14</text>
<text x="170.1" y="58.2">31</text>
<text x="129.5" y="63.2">30</text>
<text x="170.1" y="60.7">33</text>
<text x="170.1" y="63.2">39</text>
<text x="170.1" y="65.8">49</text>
<text x="130.1" y="68.3">7</text>
<text x="130.1" y="70.9">1</text>
<text x="170.1" y="68.3">50</text>
<text x="170.1" y="70.9">51</text>
<text x="129.5" y="73.4">54</text>
<text x="129.5" y="75.9">46</text>
<text x="129.5" y="78.5">43</text>
<text x="129.5" y="81">36</text>
<text x="170.7" y="78.5">8</text>
<text x="170.7" y="81">9</text>
<text x="10.3" y="85.9">B</text>
<text x="129.5" y="88.6">15</text>
<text x="170.7" y="86.1">6</text>
<text x="170.7" y="88.6">5</text>
<text x="285.3" y="85.9">B</text>
<text x="129.5" y="91.2">16</text>
<text x="170.7" y="93.7">2</text>
<text x="53.9" y="96.3">4</text>
<text x="53.9" y="101.3">1</text>
<text x="81.8" y="96.3">3</text>
<text x="120.7" y="98.7">C67</text>
<text x="129.5" y="96.3">18</text>
<text x="129.5" y="98.8">19</text>
<text x="170.1" y="101.3">55</text>
<text x="170.7" y="96.3">3</text>
<text x="53.9" y="106.4">2</text>
<text x="129.5" y="103.9">20</text>
<text x="170.1" y="103.9">56</text>
<text x="129.5" y="109">12</text>
<text x="129.5" y="111.5">13</text>
<text x="170.1" y="109">53</text>
<text x="170.1" y="111.5">52</text>
<text x="129.5" y="116.6">29</text>
<text x="170.1" y="116.6">47</text>
<text x="170.1" y="119.1">48</text>
<text x="129.5" y="121.7">24</text>
<text x="129.5" y="124.2">25</text>
<text x="170.1" y="124.2">45</text>
<text x="112.4" y="129.1">R48</text>
<text x="129.5" y="126.7">26</text>
<text x="129.5" y="129.3">27</text>
<text x="170.1" y="126.7">44</text>
<text x="170.1" y="131.8">41</text>
<text x="10.3" y="135.9">C</text>
<text x="129.5" y="134.4">23</text>
<text x="129.5" y="136.9">22</text>
<text x="170.1" y="134.4">40</text>
<text x="285.3" y="135.9">C</text>
<text x="112.4" y="141.8">R52</text>
<text x="129.5" y="139.4">28</text>
<text x="129.5" y="142">21</text>
<text x="170.1" y="139.4">37</text>
<text x="170.1" y="142">38</text>
<text x="129.5" y="149.6">57</text>
<text x="170.1" y="147.1">35</text>
<text x="170.1" y="149.6">34</text>
<text x="10.3" y="185.9">D</text>
<text x="285.3" y="185.9">D</text>
<text x="35" y="199.9">1</text>
<text x="85" y="199.9">2</text>
<text x="135" y="199.9">3</text>
<text x="185" y="199.9">4</text>
<text x="235" y="199.9">5</text>
<text x="285" y="199.9">6</text>
</g>
<g font-size="1.8" fill="#008484">
<text x="241.5" y="19.9">+1V8APLL</text>
<text x="269.3" y="19.9">+1V8_ACQ</text>
<text x="231.4" y="26.3">PWR_FLAG</text>
<text x="250.2" y="29.6">120@100MHZ</text>
<text x="255" y="24">FB3</text>
<text x="269" y="32.9">1uF</text>
<text x="269" y="30.4">C92</text>
<text x="264.7" y="40.2">GND</text>
<text x="63.6" y="45.3">+3V3_ACQ</text>
<text x="269.5" y="45.3">+1V8APLL</text>
<text x="134.6" y="48.4">U7</text>
<text x="135.1" y="51.7">VDDH</text>
<text x="162.3" y="51.7">VDDL</text>
<text x="75.9" y="58.3">1uF</text>
<text x="75.9" y="55.8">C50</text>
<text x="86.1" y="58.3">1uF</text>
<text x="86.1" y="55.8">C51</text>
<text x="96.2" y="58.3">1uF</text>
<text x="96.2" y="55.8">C52</text>
<text x="106.4" y="58.3">1uF</text>
<text x="106.4" y="55.8">C53</text>
<text x="116.6" y="58.3">1uF</text>
<text x="116.6" y="55.8">C54</text>
<text x="135.1" y="54.2">VDDH</text>
<text x="135.1" y="56.7">VDDH</text>
<text x="135.1" y="59.3">VDDH</text>
<text x="162.3" y="54.2">VDDL</text>
<text x="162.3" y="56.7">VDDL</text>
<text x="162.3" y="59.3">VDDL</text>
<text x="187.7" y="58.3">1uF</text>
<text x="187.7" y="55.8">C55</text>
<text x="197.8" y="58.3">1uF</text>
<text x="197.8" y="55.8">C56</text>
<text x="208" y="58.3">1uF</text>
<text x="208" y="55.8">C57</text>
<text x="218.2" y="58.3">1uF</text>
<text x="218.2" y="55.8">C58</text>
<text x="228.3" y="58.3">1uF</text>
<text x="228.3" y="55.8">C59</text>
<text x="238.5" y="58.3">1uF</text>
<text x="238.5" y="55.8">C60</text>
<text x="248.6" y="58.3">1uF</text>
<text x="248.6" y="55.8">C61</text>
<text x="258.8" y="58.3">1uF</text>
<text x="258.8" y="55.8">C62</text>
<text x="269" y="58.3">1uF</text>
<text x="269" y="55.8">C63</text>
<text x="53.4" y="63.1">+3V3_ACQ</text>
<text x="71.6" y="65.6">GND</text>
<text x="81.8" y="65.6">GND</text>
<text x="91.9" y="65.6">GND</text>
<text x="102.1" y="65.6">GND</text>
<text x="112.3" y="65.6">GND</text>
<text x="135.1" y="64.4">VDDIO</text>
<text x="162.3" y="61.8">VDDL</text>
<text x="162.3" y="64.4">VDDL</text>
<text x="183.4" y="65.6">GND</text>
<text x="193.5" y="65.6">GND</text>
<text x="203.7" y="65.6">GND</text>
<text x="213.9" y="65.6">GND</text>
<text x="224" y="65.6">GND</text>
<text x="234.2" y="65.6">GND</text>
<text x="244.3" y="65.6">GND</text>
<text x="254.5" y="65.6">GND</text>
<text x="264.7" y="65.6">GND</text>
<text x="135.1" y="69.4">VDDOA</text>
<text x="135.1" y="72">VDDOB</text>
<text x="162.3" y="66.9">VDDL</text>
<text x="162.3" y="69.4">VDDL</text>
<text x="162.3" y="72">VDDL</text>
<text x="65.8" y="76.1">1uF</text>
<text x="65.8" y="73.5">C91</text>
<text x="75.9" y="76.1">1uF</text>
<text x="75.9" y="73.5">C90</text>
<text x="86.1" y="76.1">1uF</text>
<text x="86.1" y="73.5">C89</text>
<text x="96.2" y="76.1">1uF</text>
<text x="96.2" y="73.5">C88</text>
<text x="106.4" y="76.1">1uF</text>
<text x="106.4" y="73.5">C48</text>
<text x="116.6" y="76.1">1uF</text>
<text x="116.6" y="73.5">C49</text>
<text x="135.1" y="74.5">VDDOC</text>
<text x="135.1" y="77.1">VDDOD</text>
<text x="179.9" y="77.9">R43</text>
<text x="61.5" y="83.4">GND</text>
<text x="71.6" y="83.4">GND</text>
<text x="81.8" y="83.4">GND</text>
<text x="91.9" y="83.4">GND</text>
<text x="102.1" y="83.4">GND</text>
<text x="112.3" y="83.4">GND</text>
<text x="135.1" y="79.6">VDDOE</text>
<text x="135.1" y="82.1">VDDOF</text>
<text x="161.8" y="82.1">OC1N</text>
<text x="161.8" y="79.6">OC1P</text>
<text x="180.7" y="79.6">49.9</text>
<text x="107.3" y="87.2">C64</text>
<text x="108.5" y="89.8">0</text>
<text x="135.1" y="89.8">IC1P</text>
<text x="157.9" y="89.8">OC2N/NC</text>
<text x="157.9" y="87.2">OC2P/NC</text>
<text x="28.2" y="91">+1V8APLL</text>
<text x="58.4" y="94.1">Y1</text>
<text x="101.2" y="93.5" transform="rotate(-90 101.2 93.5)">GND</text>
<text x="120.7" y="93.6">100nF</text>
<text x="120.7" y="91">C65</text>
<text x="135.1" y="92.3">IC1N</text>
<text x="161.8" y="94.8">OC3P</text>
<text x="40.4" y="101.5">C68</text>
<text x="58.9" y="97.4">VDD</text>
<text x="74.4" y="97.4">OUT</text>
<text x="101.2" y="101.1" transform="rotate(-90 101.2 101.1)">GND</text>
<text x="110.5" y="98.7">100nF</text>
<text x="110.5" y="96.1">C66</text>
<text x="120.7" y="101.2">100nF</text>
<text x="135.1" y="97.4">IC2P</text>
<text x="135.1" y="99.9">IC2N</text>
<text x="161.8" y="97.4">OC3N</text>
<text x="40.4" y="104">1uF</text>
<text x="58.9" y="102.5">EN</text>
<text x="58.9" y="107.5">GND</text>
<text x="135.1" y="105">IC3P</text>
<text x="161.8" y="105">OC4N</text>
<text x="161.8" y="102.5">OC4P</text>
<text x="31" y="113.9">GND</text>
<text x="72.3" y="111.4">10MHz</text>
<text x="135.1" y="110.1">XA</text>
<text x="135.1" y="112.6">XB</text>
<text x="157.9" y="112.6">OC5N/NC</text>
<text x="157.9" y="110.1">OC5P/NC</text>
<text x="53.4" y="116.4">+3V3_ACQ</text>
<text x="106.6" y="115.9">R44</text>
<text x="107.9" y="117.7">1K</text>
<text x="135.1" y="117.7">RSTN</text>
<text x="161.8" y="117.7">OC6P</text>
<text x="135.1" y="122.8">SCL/SCLK</text>
<text x="135.1" y="125.3">SDA/MOSI</text>
<text x="157.9" y="125.3">OC7P/NC</text>
<text x="161.8" y="120.2">OC6N</text>
<text x="61.8" y="131.5" transform="rotate(-90 61.8 131.5)">10K</text>
<text x="64.4" y="131.5" transform="rotate(-90 64.4 131.5)">R45</text>
<text x="66.9" y="131.8" transform="rotate(-90 66.9 131.8)">4.7K</text>
<text x="69.4" y="131.5" transform="rotate(-90 69.4 131.5)">R46</text>
<text x="72" y="131.8" transform="rotate(-90 72 131.8)">4.7K</text>
<text x="74.5" y="131.5" transform="rotate(-90 74.5 131.5)">R47</text>
<text x="89" y="129.1">+3V3_ACQ</text>
<text x="107.9" y="127.9">1K</text>
<text x="107.9" y="130.4">1K</text>
<text x="112.4" y="131.7">R49</text>
<text x="135.1" y="127.9">IF1/MISO</text>
<text x="135.1" y="130.4">IF0/CSN</text>
<text x="157.9" y="127.9">OC7N/NC</text>
<text x="107.9" y="135.5">1K</text>
<text x="112.4" y="136.8">R50</text>
<text x="135.1" y="135.5">AC0/GPIO0</text>
<text x="161.8" y="135.5">OC8N</text>
<text x="161.8" y="132.9">OC8P</text>
<text x="107.9" y="143.1">1K</text>
<text x="107.9" y="140.6">1K</text>
<text x="107.9" y="138">1K</text>
<text x="112.4" y="139.3">R51</text>
<text x="135.1" y="138">AC1/GPIO1</text>
<text x="135.1" y="140.6">AC2/GPIO2</text>
<text x="135.1" y="143.1">TEST/GPIO3</text>
<text x="161.8" y="143.1">OC9N</text>
<text x="161.8" y="140.6">OC9P</text>
<text x="61.2" y="149.9">TP16</text>
<text x="112.4" y="144.4">R53</text>
<text x="156.7" y="148.2">OC10P/NC</text>
<text x="51" y="154.9">TP18</text>
<text x="56.2" y="152.4">TP17</text>
<text x="134.6" y="155.1">ZL30260LDG1</text>
<text x="135.1" y="150.7">VSS-EPAD</text>
<text x="156.6" y="150.7">OC10N/NC</text>
<text x="99.6" y="157.1">GND</text>
<text x="122.4" y="157.1">GND</text>
</g>
<g font-size="1.8" fill="#0000c2">
<text x="243.8" y="43.8">134mA</text>
<text x="251.4" y="43.8">Measured</text>
<text x="25.4" y="55.6">3V3:</text>
<text x="30.7" y="55.6">0.115A</text>
<text x="38.4" y="55.6">Measured</text>
<text x="151.8" y="154.7">I2C</text>
<text x="156" y="154.7">Address:</text>
<text x="165.1" y="154.7">1110100</text>
<text x="103.4" y="165.7">3.3</text>
<text x="107.6" y="165.7">+</text>
<text x="110.4" y="165.7">1.8V</text>
<text x="115.7" y="165.7">operation</text>
<text x="125.8" y="165.7">w/</text>
<text x="129.6" y="165.7">one</text>
<text x="134.2" y="165.7">input</text>
<text x="140.2" y="165.7">one</text>
<text x="144.8" y="165.7">output:</text>
<text x="152.4" y="165.7">0.67W</text>
<text x="159.3" y="165.7">Expected</text>
<text x="152.4" y="168.3">0.62W</text>
<text x="159.3" y="168.3">Measured</text>
</g>
<g font-size="1.8">
<text x="188" y="78.4">REFINOUT</text>
<text x="88.9" y="88.6">REFINOUT</text>
<text x="88.9" y="96.2">INTREF</text>
<text x="88.9" y="116.5">PLL_RSTn</text>
<text x="119.4" y="126.7">IF1</text>
<text x="119.4" y="129.2">IF0</text>
<text x="119.4" y="134.3">AC0</text>
<text x="119.4" y="136.8">AC1</text>
<text x="119.4" y="139.4">AC2</text>
<text x="119.4" y="141.9">TEST</text>
</g>
<g font-size="1.8" fill="#848400">
<text x="202.1" y="79.6">REFINOUT</text>
<text x="181.8" y="117.7">ADC_CLK_P</text>
<text x="181.8" y="120.2">ADC_CLK_N</text>
<text x="37.7" y="138">PLL_RSTn</text>
<text x="38.7" y="143.1">PLL_SDA</text>
<text x="38.8" y="140.6">PLL_SCL</text>
</g>
</g></defs>
<path d="M0 0h297v210h-297z" fill="#fff" stroke="#fff" stroke-width=".18"/>
<g fill="none" stroke="#840000" stroke-width=".18">
<path d="M10 10h277v190h-277zM12 12h273v186h-273zM60 10v2M110 10v2M160 10v2M210 10v2M260 10v2M112.3 55.4h4M112.3 56.4h4M114.3 50.8v4.6M114.3 56.4v4.6M183.4 55.4h4"/>
<path d="M183.4 56.4h4M185.4 50.8v4.6M185.4 56.4v4.6M10 60h2M285 60h2M10 110h2M285 110h2M70.1 126.5h2v6h-2zM71.1 124.5v2M71.1 132.6v2M10 160h2M177 178.5h108v19.5h-108z"/>
<path d="M233 178.5v3M265.1 179.8l-.4-.1-.3 .3v.4l.1 .2h.6M285 160h2M60 198v2M110 198v2M160 198v2M177 194.5h108M177 191.5h108M177 187.5h108M177 181.5h108M182.5 186.3v.1M182.5 185.5v.1"/>
<path d="M184.7 183.6v.1M184.7 182.8v.1M193 182.2v1.5M193.2 183.1l.4 .6M193.6 182.7l-.6 .6M197 191.5v3M198.6 184.9v1.5M198.6 185.5l.2-.1 .4 .1v.9M207.3 182.1l-1.3 2M210 198v2M260 198v2M261 191.5v6.5"/>
<path d="M271.7 195.7l.2-.5 .2-.1a.81 .81 0 0 1 .6 .6 .81 .81 0 0 1-.3 .8h-.4l-.3-.5"/>
</g>
<path d="M58.4 116.8v2.6" fill="none" stroke="#840000" stroke-width=".25"/>
<path d="M63 116.2l.1 .1M63 115.1v.9" fill="none" stroke="#008484" stroke-width=".18"/>
<path d="M58.4 94h20.3v15.2h-20.3z" fill="#ffffc2"/>
<path d="M58.4 94h20.3v15.2h-20.3z" fill="none" stroke="#800000" stroke-width=".18"/>
<g fill="none" stroke="#840000" stroke-width=".18">
<path d="M81.8 55.4h4M81.8 56.4h4M83.8 50.8v4.6M83.8 56.4v4.6M92 55.4h4M92 56.4h4M94 50.8v4.6M94 56.4v4.6M81.8 73.2h4M81.8 74.2h4M83.8 61v1.2h1.3l-1.3 1.3-1.3-1.3h1.3M83.8 61h.1"/>
<path d="M83.8 78.7v1.3h1.3l-1.3 1.3-1.3-1.3h1.3M83.8 78.7h.1M83.8 68.6v4.6M83.8 74.2v4.5M92 73.2h4M92 74.2h4M94 61v1.2h1.2l-1.2 1.3-1.3-1.3h1.3M94 61h.1M94 68.6v4.6M94 74.2v4.5M177.8 78.7h2M179.9 77.8h6v2h-6z"/>
<path d="M185.4 61v1.2h1.3l-1.3 1.3-1.3-1.3h1.3M185.4 61h.1M186 78.7h2M50.8 96.5h7.6M78.7 96.5h7.7M50.8 101.6h7.6M50.8 106.7h7.6M104.1 134.6h2M106.2 133.6h6v2.1h-6zM112.3 134.6h2"/>
</g>
<path d="M73.1 45.1l.2 .1M73.1 43.9v.9M88.9 55.5h.7M63 62.9h.1M63 61.7v.9M184.6 78.1l.1 .1a1.07 1.07 0 0 1-.1 1M184.8 78.6l-.2 .2" fill="none" stroke="#008484" stroke-width=".18"/>
<path d="M68.6 45.7v2.6M58.4 63.5v2.5" fill="none" stroke="#840000" stroke-width=".25"/>
<path d="M134.6 48.3h33v104.1h-33z" fill="#ffffc2"/>
<path d="M134.6 48.3h33v104.1h-33z" fill="none" stroke="#800000" stroke-width=".18"/>
<g fill="none" stroke="#840000" stroke-width=".18">
<path d="M242.6 25.4l-.7-1-.6 1 .6 1 .7-1h1.2M243.8 25.4h.1M251.5 25.4h4.4M256.5 24.1h1.3l-1.3 2.6h-1.2zM257.2 25.4h4.4M264.7 30h4M264.7 31h4M266.7 35.6v1.2h1.3l-1.3 1.3-1.3-1.3h1.3M266.7 35.6h.1M266.7 25.4v4.6M266.7 31v4.6M71.7 55.4h4"/>
<path d="M71.7 56.4h4M73.7 50.8v4.6M73.7 56.4v4.6M83.8 50.8v2.5M83.8 58.4v2.6M94 50.8v2.5M94 58.4v2.6M102.1 55.4h4M102.1 56.4h4M104.1 50.8v4.6M104.1 56.4v4.6M114.3 50.8v2.5"/>
<path d="M114.3 58.4v2.6M127 50.8h7.6M127 53.3h7.6M127 55.9h7.6M127 58.4h7.6M131.1 50.4h.7M167.6 50.8h7.7M167.6 53.3h7.7M167.6 55.9h7.7M167.6 58.4h7.7M171.7 58h.7M185.4 50.8v2.5"/>
<path d="M185.4 58.4v2.6M193.6 55.4h4M193.6 56.4h4M195.6 50.8v4.6M195.6 56.4v4.6M203.7 55.4h4M203.7 56.4h4M205.7 50.8v4.6M205.7 56.4v4.6M213.9 55.4h4M213.9 56.4h4M215.9 50.8v4.6"/>
<path d="M215.9 56.4v4.6M224.1 55.4h4M224.1 56.4h4M226.1 50.8v4.6M226.1 56.4v4.6M234.2 55.4h4M234.2 56.4h4M236.2 50.8v4.6M236.2 56.4v4.6M244.4 55.4h4M244.4 56.4h4M246.4 50.8v4.6"/>
<path d="M246.4 56.4v4.6M254.5 55.4h4M254.5 56.4h4M256.5 50.8v4.6M256.5 56.4v4.6M264.7 55.4h4M264.7 56.4h4M266.7 50.8v4.6M266.7 56.4v4.6M61.5 73.2h4M61.5 74.2h4M63.5 78.7v1.3h1.3l-1.3 1.3-1.3-1.3h1.3"/>
<path d="M63.5 78.7h.1M63.5 68.6v4.6M63.5 74.2v4.5M71.7 73.2h4M71.7 74.2h4M73.7 78.7v1.3h1.2l-1.2 1.3-1.3-1.3h1.3M73.7 78.7h.1M73.7 61v1.2h1.2l-1.2 1.3-1.3-1.3h1.3M73.7 61h.1M73.7 68.6v4.6M73.7 74.2v4.5M83.8 78.7h.1"/>
<path d="M83.8 61h.1M83.8 68.6v2.5M83.8 76.2v2.5M94 78.7v1.3h1.2l-1.2 1.3-1.3-1.3h1.3M94 78.7h.1M94 61h.1M94 68.6v2.5M94 76.2v2.5M102.1 73.2h4M102.1 74.2h4M104.1 78.7v1.3h1.3l-1.3 1.3-1.2-1.3h1.2M104.1 78.7h.1"/>
<path d="M104.1 61v1.2h1.3l-1.3 1.3-1.2-1.3h1.2M104.1 61h.1M104.1 68.6v4.6M104.1 74.2v4.5M112.3 73.2h4M112.3 74.2h4M114.3 78.7v1.3h1.3l-1.3 1.3-1.3-1.3h1.3M114.3 78.7h.1M114.3 61v1.2h1.3l-1.3 1.3-1.3-1.3h1.3M114.3 61h.1M114.3 68.6v4.6M114.3 74.2v4.5"/>
<path d="M127 63.5h7.6M127 68.6h7.6M127 71.1h7.6M127 73.7h7.6M127 76.2h7.6M127 78.7h7.6M167.6 63.5h7.7M167.6 68.6h7.7M167.6 71.1h7.7M167.6 78.7h7.7M167.6 61h7.7M167.6 66h7.7"/>
<path d="M171.7 70.7h.7M185.4 61h.1M195.6 61v1.2h1.2l-1.2 1.3-1.3-1.3h1.3M195.6 61h.1M205.7 61v1.2h1.3l-1.3 1.3-1.2-1.3h1.2M205.7 61h.1M215.9 61v1.2h1.3l-1.3 1.3-1.3-1.3h1.3M215.9 61h.1M226.1 61v1.2h1.2l-1.2 1.3-1.3-1.3h1.3M226.1 61h.1M236.2 61v1.2h1.3l-1.3 1.3-1.3-1.3h1.3M236.2 61h.1"/>
<path d="M246.4 61v1.2h1.2l-1.2 1.3-1.3-1.3h1.3M246.4 61h.1M256.5 61v1.2h1.3l-1.3 1.3-1.2-1.3h1.2M256.5 61h.1M266.7 61v1.2h1.3l-1.3 1.3-1.3-1.3h1.3M266.7 61h.1M38.1 96.5v4.6M102.9 99.1v-1.3l-1.3 1.3 1.3 1.2v-1.2h1.2M102.9 91.4v-1.2l-1.3 1.2 1.3 1.3v-1.3h1.2M104.1 99.1h.1M104.1 91.4h.1M104.1 88.9h2"/>
<path d="M104.1 96.5h4.6M106.2 87.9h6v2.1h-6zM108.7 94.5v4M109.7 96.5h4.6M109.7 94.5v4M112.3 88.9h2M114.3 91.4h4.6M114.3 99.1h4.6M118.9 89.4v4M118.9 97.1v4M119.9 91.4h4.6M119.9 99.1h2"/>
<path d="M119.9 89.4v4M119.9 97.1v4M127 81.3h7.6M127 88.9h7.6M127 91.4h7.6M127 96.5h7.6M127 99.1h7.6M167.6 81.3h7.7M167.6 88.9h7.7M167.6 96.5h7.7M167.6 86.4h7.7M167.6 94h7.7"/>
<path d="M33 109.2v1.3h1.3l-1.3 1.3-1.3-1.3h1.3M33 109.2h.1M36.1 101.1h4M36.1 102.1h4M38.1 102.1v4.6M104.1 116.8h2M106.2 115.9h6v2h-6zM112.3 116.8h2M127 104.1h7.6M127 109.2h7.6M127 111.8h7.6M127 116.8h7.6"/>
<path d="M167.6 104.1h7.7M167.6 109.2h7.7M167.6 111.8h7.7M167.6 116.8h7.7M167.6 101.6h7.7M167.6 119.4h7.7M59.9 126.5h2v6h-2zM61 124.5v2M61 132.6v2M65 126.5h2v6h-2zM66 124.5v2M66 132.6v2"/>
<path d="M104.1 127h2M104.1 129.5h2M104.1 134.6h2M104.1 137.2h2M104.1 139.7h2M106.2 138.7h6v2.1h-6zM106.2 136.2h6v2h-6zM106.2 126h6v2.1h-6zM106.2 128.6h6v2h-6zM112.3 127h2M112.3 134.6h2M127 121.9h7.6"/>
<path d="M127 124.5h7.6M127 127h7.6M127 129.5h7.6M127 134.6h7.6M127 137.2h7.6M127 139.7h7.6M167.6 124.5h7.7M167.6 127h7.7M167.6 134.6h7.7M167.6 139.7h7.7M167.6 132.1h7.7M171.7 131.7h.7"/>
<path d="M53.3 147.3v2.6M58.4 144.8v2.5M63.5 142.2v2.6M101.6 152.4v1.3h1.3l-1.3 1.2-1.3-1.2h1.3M101.6 152.4h.1M104.1 142.2h2M106.2 141.3h6v2h-6zM124.5 152.4v1.3h1.2l-1.2 1.2-1.3-1.2h1.3M124.5 152.4h.1M127 142.2h7.6M127 149.9h7.6M131.1 141.8h.7"/>
<path d="M167.6 142.2h7.7M167.6 149.9h7.7M167.6 147.3h7.7"/>
</g>
<g fill="none" stroke="#008484" stroke-width=".18">
<path d="M250.4 19.6h.6M278.9 19.7l.1 .1M278.9 18.5v.9M262.2 28h.8l-.8 1.3h.8M88.9 55.5h.7M251.5 55.5h.7M278.3 45h.6M68.6 73.3h.7M37 90.7h.6M115.7 97.7h.4M115.7 97.1h.6M125.8 99.6h.6"/>
<path d="M125.8 92.6h.5M125.8 92h.6M166.2 85.7h.3l.3 .1M166.2 88.3l.3-.1 .3 .1M166.8 86.8l-.3 .1h-.3M166.8 89.4l-.3 .1-.3-.1M125.8 100.2h.5M166.2 108.6l.3-.1 .3 .2M166.2 111.1h.3l.3 .1M166.8 112.2l-.3 .1h-.3M166.8 109.7l-.3 .1-.3-.1M98.5 128.9l.2 .1"/>
<path d="M98.5 127.8v.9M115.2 139h.7M142.2 128.8l.8 1.3v-1.3M143.2 126.4l.1-.1a.43 .43 0 0 1 .5 .4v.5a.42 .42 0 0 1-.2 .3 .42 .42 0 0 1-.4 0M144.1 121.8l.5 .7M144.4 123.8v1.2M144.6 121.2l-.7 .8M144.8 137.7h.8M144.8 136.8l.4-.3v1.2M144.9 139.1l.4-.1 .3 .4-.8 .9h.8M145 134.1l.1-.2a.68 .68 0 0 1 .5 .7 .68 .68 0 0 1-.5 .6l-.1-.1M166.2 126.4l.3-.1 .3 .1"/>
<path d="M166.2 123.8h.3l.3 .1M166.8 127.5l-.3 .1-.3-.1M166.8 124.9l-.3 .1h-.3M144.6 149.2l.2 .5-.2 .7M145.5 141.5h.8l-.4 .5M146.1 142l.2 .3v.3l-.2 .2M146.8 154.8h.8M146.8 153.9l.4-.4v1.3M166.1 147.6l.3 .3 .4-.1M166.1 150.3l.3 .1 .4-.1M166.8 146.8l-.4-.2-.3 .3M166.8 149.3l-.4-.1-.3 .2"/>
</g>
<path d="M246.4 20.3v2.6M274.3 20.3v2.6M274.3 45.7v2.6M33 91.4v2.6M94 129.5v2.6" fill="none" stroke="#840000" stroke-width=".25"/>
<g fill="none" stroke="#000" stroke-width=".18">
<circle cx="53.3" cy="151.1" r="1.27"/>
<circle cx="58.4" cy="148.6" r="1.27"/>
<circle cx="63.5" cy="146" r="1.27"/>
</g>
<path d="M200.7 78.7l.6-.6 .6 .6-.6 .7zM180.3 118.7h.7l.6 .7-.6 .6h-.7zM180.3 116.2h.7l.6 .6-.6 .7h-.7zM47 139.1h.6l.7 .6-.7 .6h-.6zM47 136.5h.6l.7 .7-.7 .6h-.6zM47 141.6h.6l.7 .6-.7 .7h-.6z" fill="none" stroke="#848400" stroke-width=".18"/>
<g fill="none" stroke="#008400" stroke-width=".18">
<path d="M243.8 25.4h7.7M246.4 22.9v2.5M274.3 22.9v2.5h-12.7M68.6 48.3v2.5h58.4M124.5 50.8v12.7h2.5M124.5 58.4h2.5M124.5 55.9h2.5M124.5 53.3h2.5M175.3 58.4h2.5M175.3 55.9h2.5M175.3 53.3h2.5M177.8 50.8v20.3h-2.5"/>
<path d="M274.3 48.3v2.5h-99M58.4 66v2.6h68.6M124.5 68.6v12.7h2.5M124.5 71.1h2.5M124.5 78.7h2.5M124.5 76.2h2.5M124.5 73.7h2.5M175.3 63.5h2.5M175.3 68.6h2.5M175.3 78.7h2.5M175.3 66h2.5M175.3 61h2.5"/>
<path d="M188 78.7h12.7M33 94v2.5h17.8M48.3 96.5v5.1h2.5M86.4 96.5h17.7M88.9 88.9h15.2M104.1 91.4h10.2M104.1 99.1h10.2M114.3 88.9h12.7M114.3 96.5h12.7M124.5 91.4h2.5M124.5 99.1h2.5M50.8 106.7h-17.8v2.5"/>
<path d="M58.4 119.4v2.5h12.7v2.6M104.1 116.8h-22.8v20.4h-33M114.3 116.8h12.7M175.3 116.8h5M175.3 119.4h5M53.3 137.2v10.1M58.4 139.7v5.1M61 121.9v2.6M61 134.6v2.6M66 121.9v2.6M66 134.6v5.1M71.1 134.6v7.6"/>
<path d="M94 132.1v10.1h10.1M94 134.6h10.1M94 137.2h10.1M101.6 139.7h2.5M101.6 129.5h2.5M104.1 127h-2.5v25.4M114.3 139.7h12.7M114.3 129.5h12.7M114.3 134.6h12.7M114.3 137.2h12.7M114.3 127h12.7M127 124.5h-40.6v17.7h-38.1"/>
<path d="M127 121.9h-43.2v17.8h-35.5M114.3 142.2h12.7M127 149.9h-2.5v2.5"/>
</g>
<g fill="none" stroke="#000084" stroke-width=".18">
<path d="M174.7 88.3l1.2 1.2M174.7 85.8l1.2 1.2M174.7 80.7l1.2 1.2M174.7 93.4l1.2 1.2M174.7 95.9l1.2 1.2M175.9 88.3l-1.2 1.2M175.9 85.8l-1.2 1.2M175.9 80.7l-1.2 1.2M175.9 93.4l-1.2 1.2M175.9 95.9l-1.2 1.2M126.4 111.2l1.2 1.2M126.4 108.6l1.2 1.2"/>
<path d="M126.4 103.5l1.2 1.2M127.6 111.2l-1.2 1.2M127.6 108.6l-1.2 1.2M127.6 103.5l-1.2 1.2M174.7 108.6l1.2 1.2M174.7 103.5l1.2 1.2M174.7 101l1.2 1.2M174.7 111.2l1.2 1.2M175.9 108.6l-1.2 1.2M175.9 103.5l-1.2 1.2M175.9 101l-1.2 1.2M175.9 111.2l-1.2 1.2"/>
<path d="M174.7 126.4l1.2 1.2M174.7 139.1l1.2 1.2M174.7 134l1.2 1.2M174.7 131.5l1.2 1.2M174.7 123.9l1.2 1.2M175.9 126.4l-1.2 1.2M175.9 139.1l-1.2 1.2M175.9 134l-1.2 1.2M175.9 131.5l-1.2 1.2M175.9 123.9l-1.2 1.2M174.7 141.6l1.2 1.2M174.7 149.3l1.2 1.2"/>
<path d="M174.7 146.7l1.2 1.2M175.9 141.6l-1.2 1.2M175.9 149.3l-1.2 1.2M175.9 146.7l-1.2 1.2"/>
</g>
<g fill="none" stroke="#0000c2" stroke-width=".18">
<path d="M36.6 54.2l.4 1.3M249.5 43.1h.6M249.8 42.2l.4 1.3M259.8 42.7h.1M259.9 42.2v1.3M259.9 43.4l-.1 .1M163.5 154.4v.1M163.5 153.7v.2M172.5 153.3h.1a.68 .68 0 0 1 .4 .6 .68 .68 0 0 1-.4 .6h-.1M123.4 164.6l.4 .2v.6M129.1 164.6l-.2 .2v.4l.2 .2M133.3 164.2v.1"/>
<path d="M133.3 164.6v.8M139.7 164.8l-.3-.2h-.3l-.1 .2 .1 .6h.3l.3-.2M143.6 164.6h.3l.1 .2-.1 .5-.3 .1M167 164.6h.3M167.3 165.4h-.3M167.3 164.2v1.2M167.6 167.1l.1 .1M167.7 166.7v1.3M167.7 167.9l-.1 .1"/>
</g>
<path d="M17 15.2a.66 .66 0 0 0-1 .1M17.8 15.1v1.6M22.2 15.1v1.9M26.2 15.2a.69 .69 0 0 0-.9 .1M35 15.1v1.6" fill="none" stroke="#0000c2" stroke-width=".38"/>
<g fill="#008400" stroke="#008400" stroke-width=".18">
<circle cx="124.5" cy="58.4" r=".46"/>
<circle cx="124.5" cy="50.8" r=".46"/>
<circle cx="177.8" cy="66" r=".46"/>
<circle cx="177.8" cy="68.6" r=".46"/>
<circle cx="124.5" cy="78.7" r=".46"/>
<circle cx="124.5" cy="73.7" r=".46"/>
<circle cx="124.5" cy="71.1" r=".46"/>
<circle cx="124.5" cy="76.2" r=".46"/>
<circle cx="236.2" cy="50.8" r=".46"/>
<circle cx="266.7" cy="25.4" r=".46"/>
<circle cx="256.5" cy="50.8" r=".46"/>
<circle cx="246.4" cy="25.4" r=".46"/>
<circle cx="215.9" cy="50.8" r=".46"/>
<circle cx="226.1" cy="50.8" r=".46"/>
<circle cx="266.7" cy="50.8" r=".46"/>
<circle cx="246.4" cy="50.8" r=".46"/>
<circle cx="177.8" cy="50.8" r=".46"/>
<circle cx="185.4" cy="50.8" r=".46"/>
<circle cx="195.6" cy="50.8" r=".46"/>
<circle cx="177.8" cy="58.4" r=".46"/>
<circle cx="177.8" cy="61" r=".46"/>
<circle cx="177.8" cy="55.9" r=".46"/>
<circle cx="177.8" cy="53.3" r=".46"/>
<circle cx="177.8" cy="63.5" r=".46"/>
<circle cx="205.7" cy="50.8" r=".46"/>
<circle cx="94" cy="134.6" r=".46"/>
<circle cx="101.6" cy="129.5" r=".46"/>
<circle cx="94" cy="137.2" r=".46"/>
<circle cx="101.6" cy="139.7" r=".46"/>
<circle cx="83.8" cy="68.6" r=".46"/>
<circle cx="73.7" cy="50.8" r=".46"/>
<circle cx="104.1" cy="68.6" r=".46"/>
<circle cx="94" cy="68.6" r=".46"/>
<circle cx="63.5" cy="68.6" r=".46"/>
<circle cx="73.7" cy="68.6" r=".46"/>
<circle cx="83.8" cy="50.8" r=".46"/>
<circle cx="94" cy="50.8" r=".46"/>
<circle cx="61" cy="121.9" r=".46"/>
<circle cx="48.3" cy="96.5" r=".46"/>
<circle cx="71.1" cy="142.2" r=".46"/>
<circle cx="38.1" cy="96.5" r=".46"/>
<circle cx="66" cy="121.9" r=".46"/>
<circle cx="38.1" cy="106.7" r=".46"/>
<circle cx="66" cy="139.7" r=".46"/>
<circle cx="53.3" cy="137.2" r=".46"/>
<circle cx="58.4" cy="139.7" r=".46"/>
<circle cx="61" cy="137.2" r=".46"/>
<circle cx="63.5" cy="142.2" r=".46"/>
<circle cx="114.3" cy="50.8" r=".46"/>
<circle cx="104.1" cy="50.8" r=".46"/>
<circle cx="124.5" cy="68.6" r=".46"/>
<circle cx="114.3" cy="68.6" r=".46"/>
<circle cx="124.5" cy="55.9" r=".46"/>
<circle cx="124.5" cy="53.3" r=".46"/>
</g>
<use href="#words"/>
</svg>
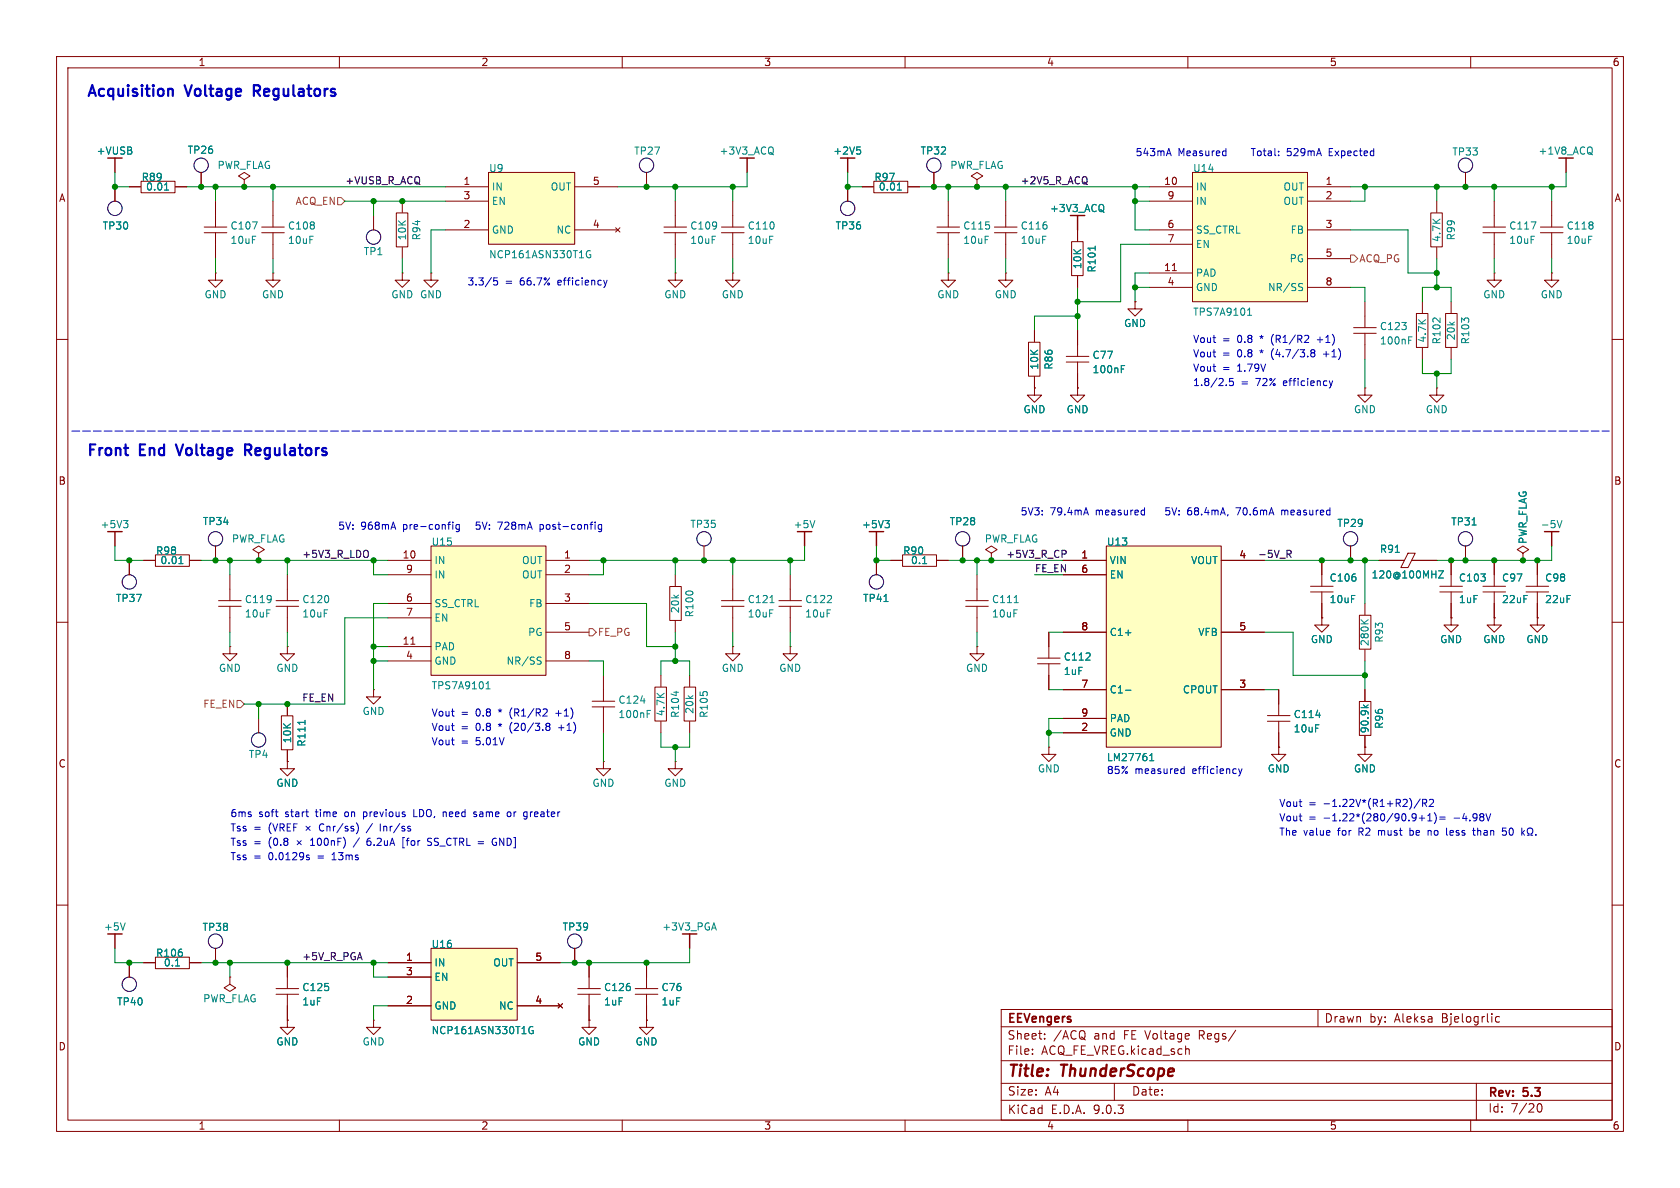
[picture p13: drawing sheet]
<svg xmlns="http://www.w3.org/2000/svg" width="297mm" height="210mm" viewBox="0 0 297 210" stroke-linecap="round" stroke-linejoin="round" font-family="sans-serif">
<defs><g id="words">
<g font-size="2.8" fill="#840000">
<text x="178" y="190.9">Title:</text>
<text x="187.7" y="190.9">ThunderScope</text>
</g>
<g font-size="2.7" fill="#0000c2">
<text x="15.2" y="18">Acquisition</text>
<text x="33" y="18">Voltage</text>
<text x="45.7" y="18">Regulators</text>
<text x="15.2" y="81.5">Front</text>
<text x="24.8" y="81.5">End</text>
<text x="32.2" y="81.5">Voltage</text>
<text x="44.9" y="81.5">Regulators</text>
</g>
<g font-size="2.1" fill="#840000">
<text x="178" y="184">Sheet:</text>
<text x="178" y="181.2">EEVengers</text>
<text x="186.2" y="184">/ACQ</text>
<text x="193.5" y="184">and</text>
<text x="198.8" y="184">FE Voltage</text>
<text x="212.4" y="184">Regs/</text>
<text x="234.1" y="181">Drawn</text>
<text x="242.1" y="181">by:</text>
<text x="246.6" y="181">Aleksa</text>
<text x="255" y="181">Bjelogrlic</text>
<text x="178" y="186.7">File:</text>
<text x="184.1" y="186.7">ACQ_FE_VREG.kicad_sch</text>
<text x="178.1" y="197.1">KiCad</text>
<text x="178.1" y="193.9">Size:</text>
<text x="184.7" y="193.9">A4</text>
<text x="185.8" y="197.1">E.D.A.</text>
<text x="193.4" y="197.1">9.0.3</text>
<text x="200" y="193.9">Date:</text>
<text x="263" y="194.3">Rev:</text>
<text x="263" y="196.9">Id:</text>
<text x="267.1" y="196.9">7/20</text>
<text x="269.4" y="194.3">5.3</text>
</g>
<g font-size="1.8" fill="#840000">
<text x="35" y="11.9">1</text>
<text x="85" y="11.9">2</text>
<text x="135" y="11.9">3</text>
<text x="185" y="11.9">4</text>
<text x="235" y="11.9">5</text>
<text x="285" y="11.9">6</text>
<text x="10.3" y="35.9">A</text>
<text x="81.8" y="32.8">1</text>
<text x="81.8" y="35.3">3</text>
<text x="104.7" y="32.8">5</text>
<text x="205.7" y="32.8">10</text>
<text x="206.3" y="35.3">9</text>
<text x="234.2" y="32.8">1</text>
<text x="234.2" y="35.3">2</text>
<text x="285.3" y="35.9">A</text>
<text x="81.8" y="40.4">2</text>
<text x="104.7" y="40.4">4</text>
<text x="206.3" y="40.4">6</text>
<text x="234.2" y="40.4">3</text>
<text x="206.3" y="42.9">7</text>
<text x="234.2" y="45.5">5</text>
<text x="205.7" y="48">11</text>
<text x="206.3" y="50.5">4</text>
<text x="234.2" y="50.5">8</text>
<text x="10.3" y="85.9">B</text>
<text x="285.3" y="85.9">B</text>
<text x="71.1" y="98.8">10</text>
<text x="71.7" y="101.3">9</text>
<text x="99.6" y="98.8">1</text>
<text x="99.6" y="101.3">2</text>
<text x="191.1" y="98.8">1</text>
<text x="191.1" y="101.3">6</text>
<text x="219" y="98.8">4</text>
<text x="71.7" y="106.4">6</text>
<text x="99.6" y="106.4">3</text>
<text x="71.7" y="109">7</text>
<text x="99.6" y="111.5">5</text>
<text x="191.1" y="111.5">8</text>
<text x="219" y="111.5">5</text>
<text x="71.1" y="114">11</text>
<text x="71.7" y="116.6">4</text>
<text x="99.6" y="116.6">8</text>
<text x="191.1" y="121.7">7</text>
<text x="219" y="121.7">3</text>
<text x="191.1" y="126.7">9</text>
<text x="191.1" y="129.3">2</text>
<text x="10.3" y="135.9">C</text>
<text x="285.3" y="135.9">C</text>
<text x="71.7" y="169.9">1</text>
<text x="71.7" y="172.5">3</text>
<text x="94.5" y="169.9">5</text>
<text x="71.7" y="177.5">2</text>
<text x="94.5" y="177.5">4</text>
<text x="10.3" y="185.9">D</text>
<text x="285.3" y="185.9">D</text>
<text x="35" y="199.9">1</text>
<text x="85" y="199.9">2</text>
<text x="135" y="199.9">3</text>
<text x="185" y="199.9">4</text>
<text x="235" y="199.9">5</text>
<text x="285" y="199.9">6</text>
</g>
<g font-size="1.8" fill="#008484">
<text x="17" y="27.5">+VUSB</text>
<text x="33.1" y="27.4">TP26</text>
<text x="112" y="27.6">TP27</text>
<text x="127.1" y="27.5">+3V3_ACQ</text>
<text x="147.2" y="27.5">+2V5</text>
<text x="162.6" y="27.5">TP32</text>
<text x="256.7" y="27.7">TP33</text>
<text x="271.9" y="27.5">+1V8_ACQ</text>
<text x="24.9" y="32.2">R89</text>
<text x="25.7" y="33.9">0.01</text>
<text x="38.4" y="30.1">PWR_FLAG</text>
<text x="86.4" y="30.6">U9</text>
<text x="86.9" y="33.9">IN</text>
<text x="97.3" y="33.9">OUT</text>
<text x="154.5" y="32.2">R97</text>
<text x="155.3" y="33.9">0.01</text>
<text x="167.9" y="30.1">PWR_FLAG</text>
<text x="210.8" y="30.6">U14</text>
<text x="211.3" y="33.9">IN</text>
<text x="226.8" y="33.9">OUT</text>
<text x="18.1" y="40.8">TP30</text>
<text x="40.6" y="40.8">C107</text>
<text x="50.8" y="40.8">C108</text>
<text x="86.9" y="36.4">EN</text>
<text x="86.9" y="41.5">GND</text>
<text x="98.3" y="41.5">NC</text>
<text x="121.9" y="40.8">C109</text>
<text x="132.1" y="40.8">C110</text>
<text x="147.6" y="40.8">TP36</text>
<text x="170.2" y="40.8">C115</text>
<text x="180.3" y="40.8">C116</text>
<text x="185.5" y="37.7">+3V3_ACQ</text>
<text x="211.3" y="36.4">IN</text>
<text x="211.3" y="41.5">SS_CTRL</text>
<text x="226.8" y="36.4">OUT</text>
<text x="228.1" y="41.5">FB</text>
<text x="266.7" y="40.8">C117</text>
<text x="276.9" y="40.8">C118</text>
<text x="40.6" y="43.3">10uF</text>
<text x="50.8" y="43.3">10uF</text>
<text x="64.2" y="45.3">TP1</text>
<text x="72" y="42.6" transform="rotate(-90 72 42.6)">10K</text>
<text x="74.5" y="42.6" transform="rotate(-90 74.5 42.6)">R94</text>
<text x="86.4" y="45.9">NCP161ASN330T1G</text>
<text x="121.9" y="43.3">10uF</text>
<text x="132.1" y="43.3">10uF</text>
<text x="170.2" y="43.3">10uF</text>
<text x="180.3" y="43.3">10uF</text>
<text x="191.4" y="47.7" transform="rotate(-90 191.4 47.7)">10K</text>
<text x="211.3" y="44">EN</text>
<text x="227.9" y="46.6">PG</text>
<text x="254.9" y="42.9" transform="rotate(-90 254.9 42.9)">4.7K</text>
<text x="257.4" y="42.6" transform="rotate(-90 257.4 42.6)">R99</text>
<text x="266.7" y="43.3">10uF</text>
<text x="276.9" y="43.3">10uF</text>
<text x="36.1" y="52.9">GND</text>
<text x="46.2" y="52.9">GND</text>
<text x="69.1" y="52.9">GND GND</text>
<text x="117.3" y="52.9">GND</text>
<text x="127.5" y="52.9">GND</text>
<text x="165.6" y="52.9">GND</text>
<text x="175.8" y="52.9">GND</text>
<text x="193.9" y="48.3" transform="rotate(-90 193.9 48.3)">R101</text>
<text x="211.3" y="49.1">PAD</text>
<text x="211.3" y="51.7">GND</text>
<text x="224.1" y="51.7">NR/SS</text>
<text x="262.1" y="52.9">GND</text>
<text x="272.3" y="52.9">GND</text>
<text x="198.6" y="58">GND</text>
<text x="210.8" y="56">TPS7A9101</text>
<text x="243.8" y="58.6">C123</text>
<text x="183.7" y="65.4" transform="rotate(-90 183.7 65.4)">10K</text>
<text x="186.3" y="65.4" transform="rotate(-90 186.3 65.4)">R86</text>
<text x="193" y="63.6">C77</text>
<text x="243.8" y="61.1">100nF</text>
<text x="252.3" y="60.7" transform="rotate(-90 252.3 60.7)">4.7K</text>
<text x="254.9" y="61" transform="rotate(-90 254.9 61)">R102</text>
<text x="257.4" y="60.2" transform="rotate(-90 257.4 60.2)">20k</text>
<text x="259.9" y="61" transform="rotate(-90 259.9 61)">R103</text>
<text x="193" y="66.2">100nF</text>
<text x="180.8" y="73.3">GND</text>
<text x="188.5" y="73.3">GND</text>
<text x="239.3" y="73.3">GND</text>
<text x="252" y="73.3">GND</text>
<text x="17.7" y="93.6">+5V3</text>
<text x="35.8" y="93">TP34</text>
<text x="121.9" y="93.5">TP35</text>
<text x="140.2" y="93.6">+5V</text>
<text x="152.3" y="93.6">+5V3</text>
<text x="167.8" y="93.1">TP28</text>
<text x="236.3" y="93.4">TP29</text>
<text x="256.5" y="93.1">TP31</text>
<text x="272.3" y="93.6">-5V</text>
<text x="27.5" y="98.2">R98</text>
<text x="28.3" y="99.9">0.01</text>
<text x="40.9" y="96.1">PWR_FLAG</text>
<text x="76.2" y="96.7">U15</text>
<text x="76.7" y="99.9">IN</text>
<text x="92.2" y="99.9">OUT</text>
<text x="159.6" y="98.2">R90</text>
<text x="160.9" y="99.9">0.1</text>
<text x="174" y="96.1">PWR_FLAG</text>
<text x="195.6" y="96.7">U13</text>
<text x="196.1" y="99.9">VIN</text>
<text x="210.5" y="99.9">VOUT</text>
<text x="243.8" y="97.9">R91</text>
<text x="270.1" y="96.3" transform="rotate(-90 270.1 96.3)">PWR_FLAG</text>
<text x="20.4" y="106.6">TP37</text>
<text x="43.2" y="106.8">C119</text>
<text x="53.3" y="106.8">C120</text>
<text x="76.7" y="102.5">IN</text>
<text x="76.7" y="107.5">SS_CTRL</text>
<text x="92.2" y="102.5">OUT</text>
<text x="93.5" y="107.5">FB</text>
<text x="132.1" y="106.8">C121</text>
<text x="142.2" y="106.8">C122</text>
<text x="152.5" y="106.6">TP41</text>
<text x="175.3" y="106.8">C111</text>
<text x="196.1" y="102.5">EN</text>
<text x="235" y="103">C106</text>
<text x="235" y="106.8">10uF</text>
<text x="242.4" y="102.5">120@100MHZ</text>
<text x="257.8" y="103">C103</text>
<text x="257.8" y="106.8">1uF</text>
<text x="265.4" y="103">C97</text>
<text x="265.4" y="106.8">22uF</text>
<text x="273.1" y="103">C98</text>
<text x="273.1" y="106.8">22uF</text>
<text x="43.2" y="109.4">10uF</text>
<text x="53.3" y="109.4">10uF</text>
<text x="76.7" y="110.1">EN</text>
<text x="93.3" y="112.6">PG</text>
<text x="120.2" y="108.5" transform="rotate(-90 120.2 108.5)">20k</text>
<text x="122.8" y="109.2" transform="rotate(-90 122.8 109.2)">R100</text>
<text x="132.1" y="109.4">10uF</text>
<text x="142.2" y="109.4">10uF</text>
<text x="175.3" y="109.4">10uF</text>
<text x="196.1" y="112.6">C1+</text>
<text x="211.7" y="112.6">VFB</text>
<text x="231.6" y="113.9">GND</text>
<text x="244.7" y="113.7" transform="rotate(-90 244.7 113.7)">R93</text>
<text x="254.5" y="113.9">GND</text>
<text x="262.1" y="113.9">GND</text>
<text x="269.7" y="113.9">GND</text>
<text x="38.6" y="119">GND</text>
<text x="48.8" y="119">GND</text>
<text x="76.7" y="115.2">PAD</text>
<text x="76.7" y="117.7">GND</text>
<text x="89.5" y="117.7">NR/SS</text>
<text x="127.5" y="119">GND</text>
<text x="137.7" y="119">GND</text>
<text x="170.7" y="119">GND</text>
<text x="188" y="117">C112</text>
<text x="188" y="119.5">1uF</text>
<text x="242.2" y="114.3" transform="rotate(-90 242.2 114.3)">280K</text>
<text x="76.2" y="122.1">TPS7A9101</text>
<text x="109.2" y="124.6">C124</text>
<text x="196.1" y="122.8">C1-</text>
<text x="209" y="122.8">CPOUT</text>
<text x="51.7" y="131.5" transform="rotate(-90 51.7 131.5)">10K</text>
<text x="64" y="126.6">GND</text>
<text x="109.2" y="127.1">100nF</text>
<text x="117.7" y="126.7" transform="rotate(-90 117.7 126.7)">4.7K</text>
<text x="120.2" y="127" transform="rotate(-90 120.2 127)">R104</text>
<text x="122.8" y="126.3" transform="rotate(-90 122.8 126.3)">20k</text>
<text x="125.3" y="127" transform="rotate(-90 125.3 127)">R105</text>
<text x="196.1" y="127.9">PAD</text>
<text x="196.1" y="130.4">GND</text>
<text x="228.6" y="127.1">C114</text>
<text x="228.6" y="129.7">10uF</text>
<text x="242.2" y="129.7" transform="rotate(-90 242.2 129.7)">90.9k</text>
<text x="244.7" y="128.9" transform="rotate(-90 244.7 128.9)">R96</text>
<text x="43.9" y="134.2">TP4</text>
<text x="54.2" y="132.1" transform="rotate(-90 54.2 132.1)">R111</text>
<text x="183.4" y="136.8">GND</text>
<text x="195.6" y="134.8">LM27761</text>
<text x="224" y="136.8">GND</text>
<text x="239.3" y="136.8">GND</text>
<text x="48.8" y="139.3">GND</text>
<text x="104.6" y="139.3">GND</text>
<text x="117.3" y="139.3">GND</text>
<text x="18.3" y="164.7">+5V</text>
<text x="35.7" y="164.8">TP38</text>
<text x="76.2" y="167.8">U16</text>
<text x="99.4" y="164.7">TP39</text>
<text x="117" y="164.7">+3V3_PGA</text>
<text x="27.5" y="169.3">R106</text>
<text x="28.9" y="171">0.1</text>
<text x="76.7" y="171">IN</text>
<text x="76.7" y="173.6">EN</text>
<text x="87.1" y="171">OUT</text>
<text x="20.6" y="177.9">TP40</text>
<text x="35.8" y="177.4">PWR_FLAG</text>
<text x="53.3" y="175.4">C125</text>
<text x="53.3" y="177.9">1uF</text>
<text x="76.7" y="178.7">GND</text>
<text x="88.1" y="178.7">NC</text>
<text x="106.7" y="175.4">C126</text>
<text x="106.7" y="177.9">1uF</text>
<text x="116.8" y="177.9">1uF</text>
<text x="116.8" y="175.4">C76</text>
<text x="48.8" y="185">GND</text>
<text x="64" y="185">GND</text>
<text x="76.2" y="183">NCP161ASN330T1G</text>
<text x="102.1" y="185">GND</text>
<text x="112.3" y="185">GND</text>
</g>
<g font-size="1.8" fill="#0000c2">
<text x="200.7" y="27.7">543mA</text>
<text x="208.3" y="27.7">Measured</text>
<text x="221" y="27.7">Total:</text>
<text x="227.4" y="27.7">529mA</text>
<text x="235" y="27.7">Expected</text>
<text x="82.5" y="50.6">3.3/5</text>
<text x="89.3" y="50.6">=</text>
<text x="92.1" y="50.6">66.7%</text>
<text x="98.9" y="50.6">efficiency</text>
<text x="210.8" y="65.8">Vout</text>
<text x="210.8" y="63.3">Vout</text>
<text x="210.8" y="60.7">Vout</text>
<text x="216.1" y="65.8">=</text>
<text x="216.1" y="63.3">=</text>
<text x="216.1" y="60.7">=</text>
<text x="218.9" y="65.8">1.79V</text>
<text x="218.9" y="63.3">0.8</text>
<text x="218.9" y="60.7">0.8</text>
<text x="223.1" y="63.3">*</text>
<text x="223.1" y="60.7">*</text>
<text x="225.3" y="63.3">(4.7/3.8</text>
<text x="225.3" y="60.7">(R1/R2</text>
<text x="233.6" y="60.7">+1)</text>
<text x="234.7" y="63.3">+1)</text>
<text x="210.8" y="68.3">1.8/2.5</text>
<text x="219.4" y="68.3">=</text>
<text x="222.2" y="68.3">72%</text>
<text x="227.2" y="68.3">efficiency</text>
<text x="59.7" y="93.7">5V:</text>
<text x="63.8" y="93.7">968mA</text>
<text x="71.4" y="93.7">pre-config</text>
<text x="83.8" y="93.7">5V:</text>
<text x="87.9" y="93.7">728mA</text>
<text x="95.5" y="93.7">post-config</text>
<text x="180.3" y="91.2">5V3:</text>
<text x="185.6" y="91.2">79.4mA</text>
<text x="193.8" y="91.2">measured</text>
<text x="205.7" y="91.2">5V:</text>
<text x="209.8" y="91.2">68.4mA,</text>
<text x="218.6" y="91.2">70.6mA</text>
<text x="226.8" y="91.2">measured</text>
<text x="76.2" y="131.8">Vout</text>
<text x="76.2" y="126.8">Vout</text>
<text x="76.2" y="129.3">Vout</text>
<text x="81.5" y="131.8">=</text>
<text x="81.5" y="126.8">=</text>
<text x="81.5" y="129.3">=</text>
<text x="84.2" y="131.8">5.01V</text>
<text x="84.2" y="126.8">0.8</text>
<text x="84.2" y="129.3">0.8</text>
<text x="88.4" y="126.8">*</text>
<text x="88.4" y="129.3">*</text>
<text x="90.6" y="126.8">(R1/R2</text>
<text x="90.6" y="129.3">(20/3.8</text>
<text x="98.9" y="126.8">+1)</text>
<text x="99.4" y="129.3">+1)</text>
<text x="195.6" y="136.9">85%</text>
<text x="200.6" y="136.9">measured</text>
<text x="211" y="136.9">efficiency</text>
<text x="226.1" y="142.9">Vout</text>
<text x="231.3" y="142.9">=</text>
<text x="234.1" y="142.9">-1.22V*(R1+R2)/R2</text>
<text x="40.6" y="147.1">Tss</text>
<text x="40.6" y="149.6">Tss</text>
<text x="40.6" y="144.5">6ms</text>
<text x="44.8" y="147.1">=</text>
<text x="44.8" y="149.6">=</text>
<text x="45.7" y="144.5">soft</text>
<text x="47.6" y="147.1">(VREF</text>
<text x="47.6" y="149.6">(0.8</text>
<text x="50.5" y="144.5">start</text>
<text x="56.1" y="144.5">time</text>
<text x="61.4" y="144.5">on</text>
<text x="64.9" y="144.5">previous</text>
<text x="65.7" y="149.6">6.2uA</text>
<text x="68" y="147.1">Inr/ss</text>
<text x="72.2" y="149.6">[for</text>
<text x="74" y="144.5">LDO,</text>
<text x="76.9" y="149.6">SS_CTRL =</text>
<text x="79.4" y="144.5">need</text>
<text x="85" y="144.5">same</text>
<text x="88.7" y="149.6">GND]</text>
<text x="91.2" y="144.5">or</text>
<text x="94.3" y="144.5">greater</text>
<text x="226.1" y="145.4">Vout</text>
<text x="226.1" y="147.9">The</text>
<text x="230.4" y="147.9">value</text>
<text x="231.4" y="145.4">=</text>
<text x="234.1" y="145.4">-1.22*(280/90.9+1)=</text>
<text x="236.6" y="147.9">for</text>
<text x="240.5" y="147.9">R2</text>
<text x="244.1" y="147.9">must</text>
<text x="249.9" y="147.9">be</text>
<text x="253.3" y="147.9">no</text>
<text x="256.8" y="147.9">less</text>
<text x="257.3" y="145.4">-4.98V</text>
<text x="261.7" y="147.9">than</text>
<text x="267.1" y="147.9">50</text>
<text x="40.6" y="152.2">Tss</text>
<text x="44.8" y="152.2">=</text>
<text x="47.6" y="152.2">0.0129s</text>
<text x="56.4" y="152.2">=</text>
<text x="59.2" y="152.2">13ms</text>
</g>
<g font-size="1.8">
<text x="61" y="32.7">+VUSB_R_ACQ</text>
<text x="180.3" y="32.7">+2V5_R_ACQ</text>
<text x="53.3" y="98.7">+5V3_R_LDO</text>
<text x="177.8" y="98.7">+5V3_R_CP</text>
<text x="182.9" y="101.3">FE_EN</text>
<text x="222.3" y="98.7">-5V_R</text>
<text x="53.3" y="124.1">FE_EN</text>
<text x="53.3" y="169.8">+5V_R_PGA</text>
</g>
<g font-size="1.8" fill="#848400">
<text x="52.2" y="36.4">ACQ_EN</text>
<text x="240.2" y="46.6">ACQ_PG</text>
<text x="105.6" y="112.6">FE_PG</text>
<text x="35.8" y="125.3">FE_EN</text>
</g>
</g></defs>
<path d="M0 0h297v210h-297z" fill="#fff" stroke="#fff" stroke-width=".18"/>
<g fill="none" stroke="#840000" stroke-width=".18">
<path d="M10 10h277v190h-277zM12 12h273v186h-273zM60 10v2M110 10v2M160 10v2M210 10v2M260 10v2M152.4 33h2M154.5 32h6v2.1h-6zM160.6 33h2M165.1 30.5v2.5M10 60h2"/>
<path d="M285 60h2M124.5 96.5v2.6M154.9 99.1v2.5M264.2 99.1v4.5M271.8 99.1v4.5M10 110h2M118.4 103.7h2v6h-2zM119.4 101.6v2M119.4 109.8v2M139.7 114.3v1.3h1.3l-1.3 1.2-1.3-1.2h1.3M139.7 114.3h.1M183.4 116.3h4"/>
<path d="M183.4 117.3h4M185.4 111.8v4.5M185.4 117.3v4.6M262.2 103.6h4M262.2 104.6h4M264.2 104.6v4.6M269.8 103.6h4M269.8 104.6h4M271.8 109.2v1.3h1.2l-1.2 1.3-1.3-1.3h1.3M271.8 109.2h.1M271.8 104.6v4.6M285 110h2"/>
<path d="M45.7 127v2.5M49.7 126.5h2.1v6h-2.1zM50.8 134.6v1.3h1.3l-1.3 1.3-1.3-1.3h1.3M50.8 134.6h.1M50.8 124.5v2M50.8 132.6v2M10 160h2M48.8 174.8h4M48.8 175.8h4M50.8 170.2v4.6M50.8 175.8v4.5M102.1 174.8h4"/>
<path d="M102.1 175.8h4M104.1 170.2v4.6M104.1 175.8v4.5M112.3 174.8h4M112.3 175.8h4M114.3 170.2v4.6M114.3 175.8v4.5M177 178.5h108v19.5h-108zM233 178.5v3M265.1 179.8l-.4-.1-.3 .3v.4l.1 .2h.6M285 160h2M50.8 180.3v1.3h1.3l-1.3 1.3-1.3-1.3h1.3"/>
<path d="M50.8 180.3h.1M60 198v2M66 180.3v1.3h1.3l-1.3 1.3-1.2-1.3h1.2M66 180.3h.1M104.1 180.3v1.3h1.3l-1.3 1.3-1.2-1.3h1.2M104.1 180.3h.1M110 198v2M160 198v2M177 194.5h108M177 191.5h108M177 187.5h108M177 181.5h108"/>
<path d="M182.5 186.3v.1M182.5 185.5v.1M184.7 183.6v.1M184.7 182.8v.1M197 191.5v3M209.8 185.4l.4 .1v.1v.8M210 198v2M260 198v2M261 191.5v6.5M271.7 195.7l.2-.5 .2-.1a.81 .81 0 0 1 .6 .6 .81 .81 0 0 1-.3 .8h-.4l-.3-.5"/>
</g>
<g fill="none" stroke="#000" stroke-width=".18">
<circle cx="165.1" cy="29.2" r="1.27"/>
<circle cx="124.5" cy="95.2" r="1.27"/>
<circle cx="154.9" cy="102.9" r="1.27"/>
<circle cx="45.7" cy="130.8" r="1.27"/>
</g>
<path d="M142.2 94v2.5" fill="none" stroke="#840000" stroke-width=".25"/>
<path d="M158.6 33.6h.8M158.9 32.5l.1-.2v1.3M144.1 92l-.5 1.3M156.3 106.3h.7M53.9 127.3v.8" fill="none" stroke="#008484" stroke-width=".18"/>
<path d="M195.6 96.5h20.3v35.6h-20.3z" fill="#ffffc2"/>
<path d="M195.6 96.5h20.3v35.6h-20.3z" fill="none" stroke="#800000" stroke-width=".18"/>
<path d="M188 99.1h7.6M215.9 99.1h7.6M188 101.6h7.6M188 111.8h7.6M215.9 111.8h7.6M188 121.9h7.6M188 127h7.6M188 129.5h7.6M215.9 121.9h7.6" fill="none" stroke="#840000" stroke-width=".18"/>
<path d="M199 111.9h.9M199 122h.9M203.3 134.5h.7M203.3 133.6l.3-.4v1.3" fill="none" stroke="#008484" stroke-width=".18"/>
<path d="M76.2 167.6h15.2v12.7h-15.2z" fill="#ffffc2"/>
<path d="M76.2 167.6h15.2v12.7h-15.2z" fill="none" stroke="#800000" stroke-width=".18"/>
<g fill="none" stroke="#840000" stroke-width=".18">
<path d="M38.1 35.6v4.5M48.3 35.6v4.5M172.7 31.8l1-.7-1-.6-1 .6 1 .7v1.2M172.7 33h.1M36.1 40.1h4M36.1 41.1h4M38.1 48.3v1.2h1.3l-1.3 1.3-1.3-1.3h1.3M38.1 48.3h.1M38.1 41.1v4.6M46.3 40.1h4M46.3 41.1h4M48.3 48.3v1.2h1.2l-1.2 1.3-1.3-1.3h1.3"/>
<path d="M48.3 48.3h.1M48.3 41.1v4.6M45.7 97.8l1-.6-1-.7-1 .7 1 .6v1.3M45.7 99.1h.1M38.6 106.2h4M38.6 107.2h4M40.6 114.3v1.3h1.3l-1.3 1.2-1.2-1.2h1.2M40.6 114.3h.1M40.6 101.6v4.6M40.6 107.2v4.6M106.7 119.4v4.6M104.7 124h4"/>
<path d="M104.7 125h4M106.7 125v4.5M224.1 126.5h4M224.1 127.5h4M226.1 132.1v1.3h1.2l-1.2 1.2-1.3-1.2h1.3M226.1 132.1h.1M226.1 121.9v4.6M226.1 127.5v4.6M22.9 170.2v2.5M25.4 170.2h2M27.5 169.2h6v2h-6zM33.6 170.2h2"/>
<path d="M38.1 167.6v2.6M40.6 172.7v1.3l1.1 .6-1.1 .7-1-.7 1-.6M40.6 172.7h.1M68.6 170.2h7.6M68.6 172.7h7.6M68.6 177.8h7.6M91.4 170.2h7.7M91.4 177.8h7.7M98.7 177.4l.7 .8M99.4 177.4l-.7 .8"/>
</g>
<path d="M44.6 39.2h.9l-.6 1.3M113.3 123.9h.7M114.4 126.2h.4M114.4 125.6h.6M232.6 126.4h.8M22.1 163.1l-.4 1.3M31 170.8h.7M94.2 181.5a.59 .59 0 0 0-.7 .6 .59 .59 0 0 0 .7 .6l.1-.5h-.3" fill="none" stroke="#008484" stroke-width=".18"/>
<path d="M20.3 165.1v2.5" fill="none" stroke="#840000" stroke-width=".25"/>
<g fill="none" stroke="#000" stroke-width=".18">
<circle cx="22.9" cy="174" r="1.27"/>
<circle cx="38.1" cy="166.4" r="1.27"/>
</g>
<path d="M76.2 96.5h20.3v22.9h-20.3z" fill="#ffffc2"/>
<path d="M76.2 96.5h20.3v22.9h-20.3z" fill="none" stroke="#800000" stroke-width=".18"/>
<g fill="none" stroke="#840000" stroke-width=".18">
<path d="M20.3 33v2.6M22.9 33h2M24.9 32h6v2.1h-6zM31 33h2M35.6 30.5v2.5M43.2 31.8l1-.7-1-.6-1 .6 1 .7v1.2M43.2 33h.1M66 38.1v2.5M70.1 37.6h2v6h-2zM71.1 35.6v2M114.3 30.5v2.5M119.4 35.6v4.5"/>
<path d="M129.5 35.6v4.5M177.8 35.6v4.5M71.1 48.3v1.2h1.3l-1.3 1.3-1.3-1.3h1.3M71.1 48.3h.1M71.1 43.7v2M76.2 48.3v1.2h1.3l-1.3 1.3-1.3-1.3h1.3M76.2 48.3h.1M117.4 40.1h4M117.4 41.1h4M119.4 48.3v1.2h1.2l-1.2 1.3-1.3-1.3h1.3M119.4 48.3h.1M119.4 41.1v4.6"/>
<path d="M127.5 40.1h4M127.5 41.1h4M129.5 48.3v1.2h1.3l-1.3 1.3-1.2-1.3h1.2M129.5 48.3h.1M129.5 41.1v4.6M175.8 40.1h4M175.8 41.1h4M177.8 41.1v4.6M22.9 99.1v2.5M25.4 99.1h2M27.5 98.1h6v2h-6zM33.6 99.1h2"/>
<path d="M38.1 96.5v2.6M68.6 99.1h7.6M96.5 99.1h7.6M170.2 96.5v2.6M233.7 99.1v4.5M243.8 99.1h4.5M248.9 97.8h1.3l-1.3 2.5h-1.3zM249.6 99.1h4.4M256.5 99.1v4.5M68.6 101.6h7.6M68.6 106.7h7.6M68.6 109.2h7.6"/>
<path d="M68.6 114.3h7.6M68.6 116.8h7.6M72.6 113.9h.8M96.5 101.6h7.6M96.5 106.7h7.6M96.5 116.8h7.6M96.5 111.8h7.6M137.7 106.2h4M137.7 107.2h4M139.7 101.6v4.6M139.7 107.2v4.6M231.7 103.6h4"/>
<path d="M231.7 104.6h4M233.7 109.2v1.3h1.2l-1.2 1.3-1.3-1.3h1.3M233.7 109.2h.1M233.7 104.6v4.6M240.3 108.8h2.1v6h-2.1zM241.3 106.7v2M241.3 114.8v2M254.5 103.6h4M254.5 104.6h4M256.5 109.2v1.3h1.3l-1.3 1.3-1.2-1.3h1.2M256.5 109.2h.1M256.5 104.6v4.6"/>
<path d="M264.2 109.2v1.3h1.2l-1.2 1.3-1.3-1.3h1.3M264.2 109.2h.1M66 121.9v1.3h1.3l-1.3 1.3-1.2-1.3h1.2M66 121.9h.1M185.4 132.1v1.3h1.3l-1.3 1.2-1.3-1.2h1.3M185.4 132.1h.1M101.6 167.6v2.6"/>
</g>
<g fill="none" stroke="#008484" stroke-width=".18">
<path d="M29.1 33.6h.7M29.3 32.5l.2-.2v1.3M136.6 27.3l.2 .1M136.6 26.2v.9M21.8 92h.8l-.4 .5M22.4 92.5l.2 .2v.3l-.2 .3M31.6 99.6h.8M31.9 98.6l.1-.2v1.2M246.7 97.6h.7M95.2 116.8l.3 .1 .2 .3-.3 .2h-.3M95.2 116.1l.5 .1M240.6 109.6l.7 .7"/>
<path d="M241.9 109.6l-.7 .5M254.3 100.9h.9l-.9 1.3h.9M85.9 121.8h.8M85.9 120.9l.4-.4v1.3M125.9 164h.6M126.2 163.1l.4 1.3"/>
</g>
<g fill="none" stroke="#000" stroke-width=".18">
<circle cx="20.3" cy="36.8" r="1.27"/>
<circle cx="35.6" cy="29.2" r="1.27"/>
<circle cx="114.3" cy="29.2" r="1.27"/>
<circle cx="66" cy="41.9" r="1.27"/>
<circle cx="38.1" cy="95.2" r="1.27"/>
<circle cx="170.2" cy="95.2" r="1.27"/>
<circle cx="22.9" cy="102.9" r="1.27"/>
<circle cx="101.6" cy="166.4" r="1.27"/>
</g>
<path d="M20.3 27.9v2.6M132.1 27.9v2.6M20.3 94v2.5M121.9 165.1v2.5" fill="none" stroke="#840000" stroke-width=".25"/>
<path d="M86.4 30.5h15.2v12.7h-15.2z" fill="#ffffc2"/>
<path d="M86.4 30.5h15.2v12.7h-15.2z" fill="none" stroke="#800000" stroke-width=".18"/>
<g fill="none" stroke="#840000" stroke-width=".18">
<path d="M78.7 33h7.7M78.7 35.6h7.7M101.6 33h7.6M149.9 33v2.6M167.6 35.6v4.5M78.7 40.6h7.7M101.6 40.6h7.6M108.8 40.3l.8 .7M109.6 40.3l-.8 .7M165.6 40.1h4M165.6 41.1h4M167.6 48.3v1.2h1.3l-1.3 1.3-1.2-1.3h1.2"/>
<path d="M167.6 48.3h.1M167.6 41.1v4.6M177.8 48.3v1.2h1.3l-1.3 1.3-1.3-1.3h1.3M177.8 48.3h.1M189.4 42.7h2.1v6h-2.1zM190.5 40.6v2M190.5 48.8v2M200.7 53.3v1.3h1.2l-1.2 1.3-1.3-1.3h1.3M200.7 53.3h.1M241.3 68.6v1.3h1.3l-1.3 1.2-1.3-1.2h1.3M241.3 68.6h.1M48.8 106.2h4"/>
<path d="M48.8 107.2h4M50.8 114.3v1.3h1.3l-1.3 1.2-1.3-1.2h1.3M50.8 114.3h.1M50.8 101.6v4.6M50.8 107.2v4.6M116.8 119.4v2M121.9 119.4v2M127.5 106.2h4M127.5 107.2h4M129.5 114.3v1.3h1.3l-1.3 1.2-1.2-1.2h1.2M129.5 114.3h.1M129.5 101.6v4.6"/>
<path d="M129.5 107.2v4.6M106.7 134.6v1.3h1.2l-1.2 1.3-1.3-1.3h1.3M106.7 134.6h.1M115.8 121.5h2v6h-2zM116.8 127.5v2M119.4 134.6v1.3h1.2l-1.2 1.3-1.3-1.3h1.3M119.4 134.6h.1M120.9 121.5h2.1v6h-2.1zM121.9 127.5v2M240.3 124h2.1v6h-2.1zM241.3 132.1v1.3h1.3l-1.3 1.2-1.3-1.2h1.3M241.3 132.1h.1"/>
<path d="M241.3 121.9v2M241.3 130.1v2M114.3 180.3v1.3h1.3l-1.3 1.3-1.3-1.3h1.3M114.3 180.3h.1"/>
</g>
<path d="M151.5 26h.6M151.9 26.5l.3 .2v.3l-.3 .2M195.1 37.5h.1M195.1 36.3v.9M104.4 44.4a.59 .59 0 0 0-.8 .5 .59 .59 0 0 0 .8 .6v-.5h-.2M193.6 43.5v.7M136.1 106.5h.7M119.5 122.2v.8M241 124.6l.5 .5M241.9 124.6l-.5 .4" fill="none" stroke="#008484" stroke-width=".18"/>
<path d="M149.9 27.9v2.6M190.5 38.1v2.5" fill="none" stroke="#840000" stroke-width=".25"/>
<circle cx="149.9" cy="36.8" r="1.27" fill="none" stroke="#000" stroke-width=".18"/>
<path d="M210.8 30.5h20.3v22.8h-20.3z" fill="#ffffc2"/>
<path d="M210.8 30.5h20.3v22.8h-20.3z" fill="none" stroke="#800000" stroke-width=".18"/>
<g fill="none" stroke="#840000" stroke-width=".18">
<path d="M20.3 33v2.6M22.9 33h2M31 33h2M35.6 30.5v2.5M149.9 33v2.6M152.4 33h2M160.6 33h2M165.1 30.5v2.5M203.2 33h7.6M203.2 35.6h7.6M231.1 33h7.7M231.1 35.6h7.7"/>
<path d="M252.9 37.6h2.1v6h-2.1zM254 35.6v2M259.1 30.5v2.5M264.2 35.6v4.5M274.3 35.6v4.5M182.9 58.4v2M190.5 40.6v2M190.5 48.8v2M190.5 58.4v4.6M200.7 53.3h.1M203.2 40.6h7.6M203.2 43.2h7.6"/>
<path d="M203.2 48.3h7.6M203.2 50.8h7.6M207.3 47.8h.7M231.1 40.6h7.7M231.1 50.8h7.7M231.1 45.7h7.7M239.3 57.9h4M239.3 58.9h4M241.3 53.3v4.6M241.3 58.9v4.6M250.4 55.4h2v6h-2zM251.5 53.3v2"/>
<path d="M254 43.7v2M255.6 55.4h2v6h-2zM256.5 53.3v2M262.2 40.1h4M262.2 41.1h4M264.2 48.3v1.2h1.2l-1.2 1.3-1.3-1.3h1.3M264.2 48.3h.1M264.2 41.1v4.6M272.3 40.1h4M272.3 41.1h4M274.3 48.3v1.2h1.3l-1.3 1.3-1.3-1.3h1.3M274.3 48.3h.1"/>
<path d="M274.3 41.1v4.6M181.8 60.5h2.1v6h-2.1zM182.9 68.6v1.3h1.2l-1.2 1.2-1.3-1.2h1.3M182.9 68.6h.1M182.9 66.6v2M188.5 63h4M188.5 64h4M190.5 68.6v1.3h1.3l-1.3 1.2-1.3-1.2h1.3M190.5 68.6h.1M190.5 64v4.6M251.5 61.5v2M254 68.6v1.3h1.3l-1.3 1.2-1.3-1.2h1.3"/>
<path d="M254 68.6h.1M256.5 61.5v2M22.9 99.1v2.5M25.4 99.1h2M33.6 99.1h2M38.1 96.5v2.6M154.9 99.1v2.5M157.5 99.1h2M159.6 98.1h6v2h-6zM165.6 99.1h2M170.2 96.5v2.6M175.3 97.8l1-.6-1-.7-1.1 .7 1.1 .6v1.3"/>
<path d="M175.3 99.1h.1M188 99.1h7.6M215.9 99.1h7.6M233.7 99.1v2.5M238.8 96.5v2.6M243.8 99.1h4.5M249.6 99.1h4.4M256.5 99.1v2.5M259.1 96.5v2.6M264.2 99.1v2.5M269.2 97.8l1.1-.6-1.1-.7-1 .7 1 .6v1.3M269.2 99.1h.1"/>
<path d="M271.8 99.1v2.5M170.7 106.2h4M170.7 107.2h4M172.7 114.3v1.3h1.3l-1.3 1.2-1.3-1.2h1.3M172.7 114.3h.1M172.7 101.6v4.6M172.7 107.2v4.6M185.4 111.8v2.5M185.4 119.4v2.5M188 101.6h7.6M188 111.8h7.6M215.9 111.8h7.6"/>
<path d="M233.7 109.2h.1M233.7 106.7v2.5M256.5 109.2h.1M256.5 106.7v2.5M264.2 109.2h.1M264.2 106.7v2.5M271.8 109.2h.1M271.8 106.7v2.5M50.8 134.6h.1M50.8 124.5v2M50.8 132.6v2M188 121.9h7.6"/>
<path d="M188 127h7.6M188 129.5h7.6M215.9 121.9h7.6M226.1 132.1h.1M226.1 121.9v2.6M226.1 129.5v2.6M241.3 132.1h.1M241.3 121.9v2M241.3 130.1v2M22.9 170.2v2.5M25.4 170.2h2M33.6 170.2h2"/>
<path d="M38.1 167.6v2.6M50.8 170.2v2.5M50.8 177.8v2.5M68.6 170.2h7.6M68.6 172.7h7.6M68.6 177.8h7.6M91.4 170.2h7.7M91.4 177.8h7.7M98.7 177.4l.7 .8M99.4 177.4l-.7 .8M101.6 167.6v2.6M104.1 170.2v2.5"/>
<path d="M104.1 177.8v2.5M114.3 170.2v2.5M114.3 177.8v2.5M50.8 180.3h.1M104.1 180.3h.1M114.3 180.3h.1"/>
</g>
<g fill="none" stroke="#008484" stroke-width=".18">
<path d="M29.1 33.6h.7M29.3 32.5l.2-.2v1.3M151.5 26h.6M151.9 26.5l.3 .2v.3l-.3 .2M158.6 33.6h.8M158.9 32.5l.1-.2v1.3M195.1 37.5h.1M195.1 36.3v.9M270.7 39.2h.8l-.5 1.3M281.4 27.3l.1 .1M281.4 26.2v.9M193.6 43.5v.7"/>
<path d="M220.5 55.7h.8M220.5 54.8l.4-.3v1.2M229.8 50.7l.4 .1 .1 .3-.3 .3h-.3M229.8 50.1l.5 .1M249 59.5h.6M198.2 65.2h.5M198.2 64.6h.6M249 60.1h.5M31.6 99.6h.8M31.9 98.6l.1-.2v1.2M156.5 92h.7l-.4 .5M157 92.5l.2 .2v.3l-.2 .3"/>
<path d="M163.1 99.6h.7M246.7 97.6h.7M260.2 92.8h.8M275.3 92l.4 1.3 .4-1.3M156.3 106.3h.7M179.3 106.5h.7M199 111.9h.9M254.3 100.9h.9l-.9 1.3h.9M53.9 127.3v.8M199 122h.9M203.3 134.5h.7M203.3 133.6l.3-.4v1.3"/>
<path d="M232.6 126.4h.8M241 124.6l.5 .5M241.9 124.6l-.5 .4M31 170.8h.7M94.2 181.5a.59 .59 0 0 0-.7 .6 .59 .59 0 0 0 .7 .6l.1-.5h-.3"/>
</g>
<g fill="none" stroke="#000" stroke-width=".18">
<path d="M192.1 32.6h.1M192.1 31.4v.9M64.9 97.3a.9 .9 0 0 1 0 1.2M187.8 97.3h.4l.3 .2-.1 .4h-.6M227.5 97.3h.5l.3 .2-.2 .4h-.6M227.8 97.9l.5 .6"/>
<circle cx="259.1" cy="29.2" r="1.27"/>
<circle cx="238.8" cy="95.2" r="1.27"/>
<circle cx="259.1" cy="95.2" r="1.27"/>
</g>
<path d="M276.9 27.9v2.6M154.9 94v2.5M274.3 94v2.5" fill="none" stroke="#840000" stroke-width=".25"/>
<path d="M59.7 34.9h.6l.7 .7-.7 .6h-.6zM238.8 45.1h.6l.6 .6-.6 .7h-.6zM104.1 111.1h.7l.6 .7-.6 .6h-.7zM41.9 123.8h.6l.7 .7-.7 .6h-.6z" fill="none" stroke="#848400" stroke-width=".18"/>
<path d="M12.7 76.2h271.8" fill="none" stroke="#0000c2" stroke-width=".18" stroke-dasharray="1.4 .5"/>
<g fill="none" stroke="#008400" stroke-width=".18">
<path d="M20.3 30.5v2.5h2.6M33 33h45.7M38.1 33v2.6M48.3 33v2.6M61 35.6h17.7M66 35.6v2.5M119.4 33v2.6M129.5 33v2.6M132.1 30.5v2.5h-22.9M149.9 30.5v2.5h2.5M162.6 33h40.6M167.6 33v2.6"/>
<path d="M177.8 33v2.6M200.7 33v7.6h2.5M200.7 35.6h2.5M241.3 33v2.6h-2.5M254 33v2.6M264.2 33v2.6M274.3 33v2.6M276.9 30.5v2.5h-38.1M38.1 45.7v2.6M48.3 45.7v2.6M71.1 45.7v2.6M78.7 40.6h-2.5v7.7"/>
<path d="M119.4 45.7v2.6M129.5 45.7v2.6M167.6 45.7v2.6M177.8 45.7v2.6M190.5 50.8v7.6M190.5 55.9h-7.6v2.5M200.7 50.8h2.5M203.2 48.3h-2.5v5M203.2 43.2h-5.1v10.1h-7.6M238.8 50.8h2.5v2.5M238.8 40.6h10.1v7.7h5.1M251.5 53.3v-2.5h5v2.5"/>
<path d="M254 45.7v5.1M264.2 45.7v2.6M274.3 45.7v2.6M241.3 63.5v5.1M251.5 63.5v2.5h5v-2.5M254 66v2.6M20.3 96.5v2.6h5.1M35.6 99.1h33M40.6 99.1v2.5M50.8 99.1v2.5M66 99.1v2.5h2.6M106.7 99.1v2.5h-2.6"/>
<path d="M119.4 99.1v2.5M129.5 99.1v2.5M139.7 99.1v2.5M142.2 96.5v2.6h-38.1M154.9 96.5v2.6h2.6M167.6 99.1h20.4M172.7 99.1v2.5M223.5 99.1h20.3M241.3 99.1v7.6M274.3 96.5v2.6h-20.3M40.6 111.8v2.5M50.8 111.8v2.5"/>
<path d="M66 114.3h2.6M66 116.8h2.6M68.6 106.7h-2.6v15.2M68.6 109.2h-7.6v15.3h-17.8M104.1 106.7h10.2v7.6h5.1M104.1 116.8h2.6v2.6M116.8 119.4v-2.6h5.1v2.6M119.4 111.8v5M129.5 111.8v2.5M139.7 111.8v2.5M172.7 111.8v2.5M182.9 101.6h5.1"/>
<path d="M185.4 111.8h2.6M223.5 111.8h5.1v7.6h12.7M241.3 116.8v5.1M45.7 124.5v2.5M106.7 129.5v5.1M116.8 129.5v2.6h5.1v-2.6M119.4 132.1v2.5M185.4 121.9h2.6M185.4 129.5h2.6M188 127h-2.6v5.1M223.5 121.9h2.6M20.3 167.6v2.6h5.1"/>
<path d="M35.6 170.2h33M40.6 170.2v2.5M66 170.2v2.5h2.6M68.6 177.8h-2.6v2.5M121.9 167.6v2.6h-22.8"/>
</g>
<g fill="none" stroke="#0000c2" stroke-width=".38">
<path d="M15.7 17l.6-1.9 .6 1.9M22.7 15.1l-.1 .1h.1M22.7 15.1v.1M25.1 15.1l-.1 .1h.1M25.1 15.1l.1 .1h-.1M25.1 15.1v.1M26 15.1v1.6M27.1 15.1l-.1 .1h.1M27.1 15.1l.1 .1h-.1M27.1 15.1v.1M30.3 15.7l.2 .3v1M32.6 15.1l.7 1.9 .6-1.9"/>
<path d="M36.3 15.1v1.6M37.3 15.1v1.6M44.9 16.1h.7M45.9 15.2l-.3-.1h-.7v1.9M51.9 15.1v1.6M54.6 15.1v1.6M16.9 78.6h-1v1.9M22.2 78.6v1.6M25.7 78.6h-1v1.9M29 78.6v1.9M31.1 78.6l.6 1.9 .7-1.9M34.7 78.6v1.6"/>
<path d="M35.7 78.6v1.6M43.8 79.6l.6 .9M44.2 79.5l-.9 .1M44.3 78.7l-.2-.1h-.8v1.9M50.3 78.6v1.6M53 78.6v1.6"/>
</g>
<g fill="none" stroke="#0000c2" stroke-width=".18">
<path d="M206.3 27.2h.6M206.6 26.3l.5 1.2M216.6 26.7h.1M216.7 26.3v1.2M216.7 27.5h-.1M226 27.4v.1M226 26.7v.2M87.9 49.1h-.6v.6l.1-.1 .5 .1 .1 .1-.1 .5-.2 .1-.4-.1M106.7 49.5l.3 .9M107 50.4l-.1 .3M107.3 49.5l-.3 .9M216.8 68v.2"/>
<path d="M218 66.9h-.6l-.1 .6 .2-.1h.4l.2 .2-.1 .4-.2 .2-.5-.2M231.8 62.2l.2 .2M231.8 61.9l.2-.1 .3 .1 .2 .2-.3 .3M232 62.4h.2M232 62.4l-.2 .1M232.2 62.4l.3 .2-.1 .4-.2 .1-.4-.1M232.9 60.1h.9M234 62.6h.9M235 67.3l.3 .9M235.3 68.2l-.1 .3M235.6 67.3l-.3 .9M80.1 92.3v.1"/>
<path d="M80.1 92.7v.9M81.2 92.8l-.4-.1-.2 .3 .1 .5h.5M81.2 92.7v1l-.2 .3-.3-.1M104.3 92.7h.5M104.7 92.3h.1M105.2 92.3v.1M105.2 92.7v.9M106.4 92.8l-.4-.1-.2 .3 .1 .5h.5M106.4 92.7v1l-.3 .3-.3-.1M192 89.8l.4 1.2M202.2 90.2h.1M202.3 89.8v1.2"/>
<path d="M202.3 91h-.1M217.1 91l-.1 .2M96 126.6h.7M96.6 128l.1-.1h.4l.1 .3-.2 .2M96.6 128.3l.1 .1M96.7 125.4v.5M96.7 128.4h.3M96.7 128.4l-.1 .1M97 128.4l.2 .2v.4l-.2 .1-.4-.1M98.3 126.1h.9M98.7 128.6h1M209 135.9l.4 .1"/>
<path d="M209.4 135.5v1.2M209.4 136.7h-.4M219 135.9l.3 .8M219.3 136.7l-.3 .5M219.6 135.9l-.3 .8M52.5 148.6l.8 .7M53.3 148.6l-.8 .7M54.1 146.1l.7 .7M54.3 151.6h.3l.1 .2-.2 .2h-.2M54.3 151.1l.3 .1M54.8 146.1l-.7 .7M54.9 149.4h.7"/>
<path d="M54.9 148.5l.4-.3v1.2M56.2 148.3l.2-.1a.68 .68 0 0 1 .4 .6 .68 .68 0 0 1-.4 .6l-.2-.1-.1-.3zM57.3 145.8a.6 .6 0 0 0-.9 .4 .6 .6 0 0 0 .6 .7l.3-.1M57.4 148.3l.2-.1a.68 .68 0 0 1 .5 .6 .68 .68 0 0 1-.5 .6l-.2-.1-.1-.3zM57.8 146.1v.8M57.8 146.2l.2-.1h.3v.8M58.6 148.6v.8M58.6 148.7l.2-.1 .3 .1v.7M58.7 152h.7M58.8 151l-.1 .1M58.9 146.1v.8M59.3 146.1l-.4 .2"/>
<path d="M59.7 148.8h.5M60.3 148.2h-.6v1.2M60.6 145.6l-1.1 1.6M60.7 148a1.46 1.46 0 0 1 0 1.9M61.5 146.1h-.3l-.2 .1 .1 .2 .4 .1v.3h-.5M62.5 146.1h-.3l-.2 .1 .1 .2 .4 .1v.3h-.5M63 145.5a1.46 1.46 0 0 1 0 1.9M63.5 148.1l-1 1.6M64.3 143.5v1.3M64.3 144.3l.1 .1M64.4 143.5l-.1 .1M65.2 148.2h-.1a.86 .86 0 0 0 0 1.2h.3"/>
<path d="M65.4 148.7h-.4l-.1 .2M65.8 145.6l-1.1 1.6M67.2 145.6v1.3M71.5 148.1h-.3v1.8h.3M73.2 143.1v1.3h.6M76.3 148.2h-.5l-.2 .1v.4l.6 .2 .1 .3-.2 .2h-.5M78.5 143.5l.4 .2M83.8 143.9l.4 .1 .1 .2-.2 .2-.4-.1M83.8 143.6h.4M87.4 148.2h.3M87.5 148.9h.3v.4l-.4 .1M89.8 143.6l.3-.1 .2 .3-.1 .5h-.4"/>
<path d="M249.3 146.4v1.2M249.3 147.6h.1M249.4 146.8l-.1 .1M250.9 144.6h1M251.1 141.2l-1.1 1.7M251.4 144.1v1M251.5 142l.6-.1 .1-.2v-.3l-.7-.1v1.3M251.8 142l.4 .6M252.4 145.1h.7M252.4 144.2l.4-.4v1.3M252.5 146.8v.8M252.7 141.4l.5-.1 .2 .4-.8 .9h.8"/>
<path d="M252.8 146.8l-.3 .1M253.6 143.7a1.46 1.46 0 0 1 0 1.9M254.5 144.4h1M254.5 144.8h1M255.8 147.6h.1M260.3 146.8h.5M260.5 146.4v1.1l.3 .1M263.5 143.8l-.4 1.3M265.7 146.9h.4l.2 .2-.1 .5h-.5M265.7 146.4h.6M270 147.6h.3v-.2a.54 .54 0 0 1-.3-.7 .54 .54 0 0 1 .8-.3 .58 .58 0 0 1-.1 1v.2h.3M271.5 147.5v.1"/>
</g>
<g fill="#008400" stroke="#008400" stroke-width=".18">
<circle cx="40.6" cy="170.2" r=".46"/>
<circle cx="45.7" cy="124.5" r=".46"/>
<circle cx="50.8" cy="170.2" r=".46"/>
<circle cx="66" cy="170.2" r=".46"/>
<circle cx="22.9" cy="170.2" r=".46"/>
<circle cx="38.1" cy="170.2" r=".46"/>
<circle cx="48.3" cy="33" r=".46"/>
<circle cx="20.3" cy="33" r=".46"/>
<circle cx="35.6" cy="33" r=".46"/>
<circle cx="38.1" cy="33" r=".46"/>
<circle cx="66" cy="35.6" r=".46"/>
<circle cx="71.1" cy="35.6" r=".46"/>
<circle cx="43.2" cy="33" r=".46"/>
<circle cx="139.7" cy="99.1" r=".46"/>
<circle cx="119.4" cy="114.3" r=".46"/>
<circle cx="101.6" cy="170.2" r=".46"/>
<circle cx="119.4" cy="132.1" r=".46"/>
<circle cx="119.4" cy="116.8" r=".46"/>
<circle cx="114.3" cy="170.2" r=".46"/>
<circle cx="104.1" cy="170.2" r=".46"/>
<circle cx="66" cy="116.8" r=".46"/>
<circle cx="66" cy="114.3" r=".46"/>
<circle cx="50.8" cy="124.5" r=".46"/>
<circle cx="66" cy="99.1" r=".46"/>
<circle cx="269.2" cy="99.1" r=".46"/>
<circle cx="271.8" cy="99.1" r=".46"/>
<circle cx="259.1" cy="99.1" r=".46"/>
<circle cx="264.2" cy="99.1" r=".46"/>
<circle cx="256.5" cy="99.1" r=".46"/>
<circle cx="241.3" cy="119.4" r=".46"/>
<circle cx="185.4" cy="129.5" r=".46"/>
<circle cx="172.7" cy="33" r=".46"/>
<circle cx="165.1" cy="33" r=".46"/>
<circle cx="167.6" cy="33" r=".46"/>
<circle cx="177.8" cy="33" r=".46"/>
<circle cx="149.9" cy="33" r=".46"/>
<circle cx="200.7" cy="50.8" r=".46"/>
<circle cx="190.5" cy="53.3" r=".46"/>
<circle cx="233.7" cy="99.1" r=".46"/>
<circle cx="200.7" cy="33" r=".46"/>
<circle cx="200.7" cy="35.6" r=".46"/>
<circle cx="241.3" cy="99.1" r=".46"/>
<circle cx="238.8" cy="99.1" r=".46"/>
<circle cx="254" cy="50.8" r=".46"/>
<circle cx="264.2" cy="33" r=".46"/>
<circle cx="259.1" cy="33" r=".46"/>
<circle cx="241.3" cy="33" r=".46"/>
<circle cx="254" cy="33" r=".46"/>
<circle cx="254" cy="66" r=".46"/>
<circle cx="254" cy="48.3" r=".46"/>
<circle cx="274.3" cy="33" r=".46"/>
<circle cx="22.9" cy="99.1" r=".46"/>
<circle cx="40.6" cy="99.1" r=".46"/>
<circle cx="38.1" cy="99.1" r=".46"/>
<circle cx="119.4" cy="99.1" r=".46"/>
<circle cx="124.5" cy="99.1" r=".46"/>
<circle cx="129.5" cy="99.1" r=".46"/>
<circle cx="106.7" cy="99.1" r=".46"/>
<circle cx="129.5" cy="33" r=".46"/>
<circle cx="50.8" cy="99.1" r=".46"/>
<circle cx="45.7" cy="99.1" r=".46"/>
<circle cx="114.3" cy="33" r=".46"/>
<circle cx="119.4" cy="33" r=".46"/>
<circle cx="190.5" cy="55.9" r=".46"/>
<circle cx="154.9" cy="99.1" r=".46"/>
<circle cx="172.7" cy="99.1" r=".46"/>
<circle cx="170.2" cy="99.1" r=".46"/>
<circle cx="175.3" cy="99.1" r=".46"/>
</g>
<use href="#words"/>
</svg>
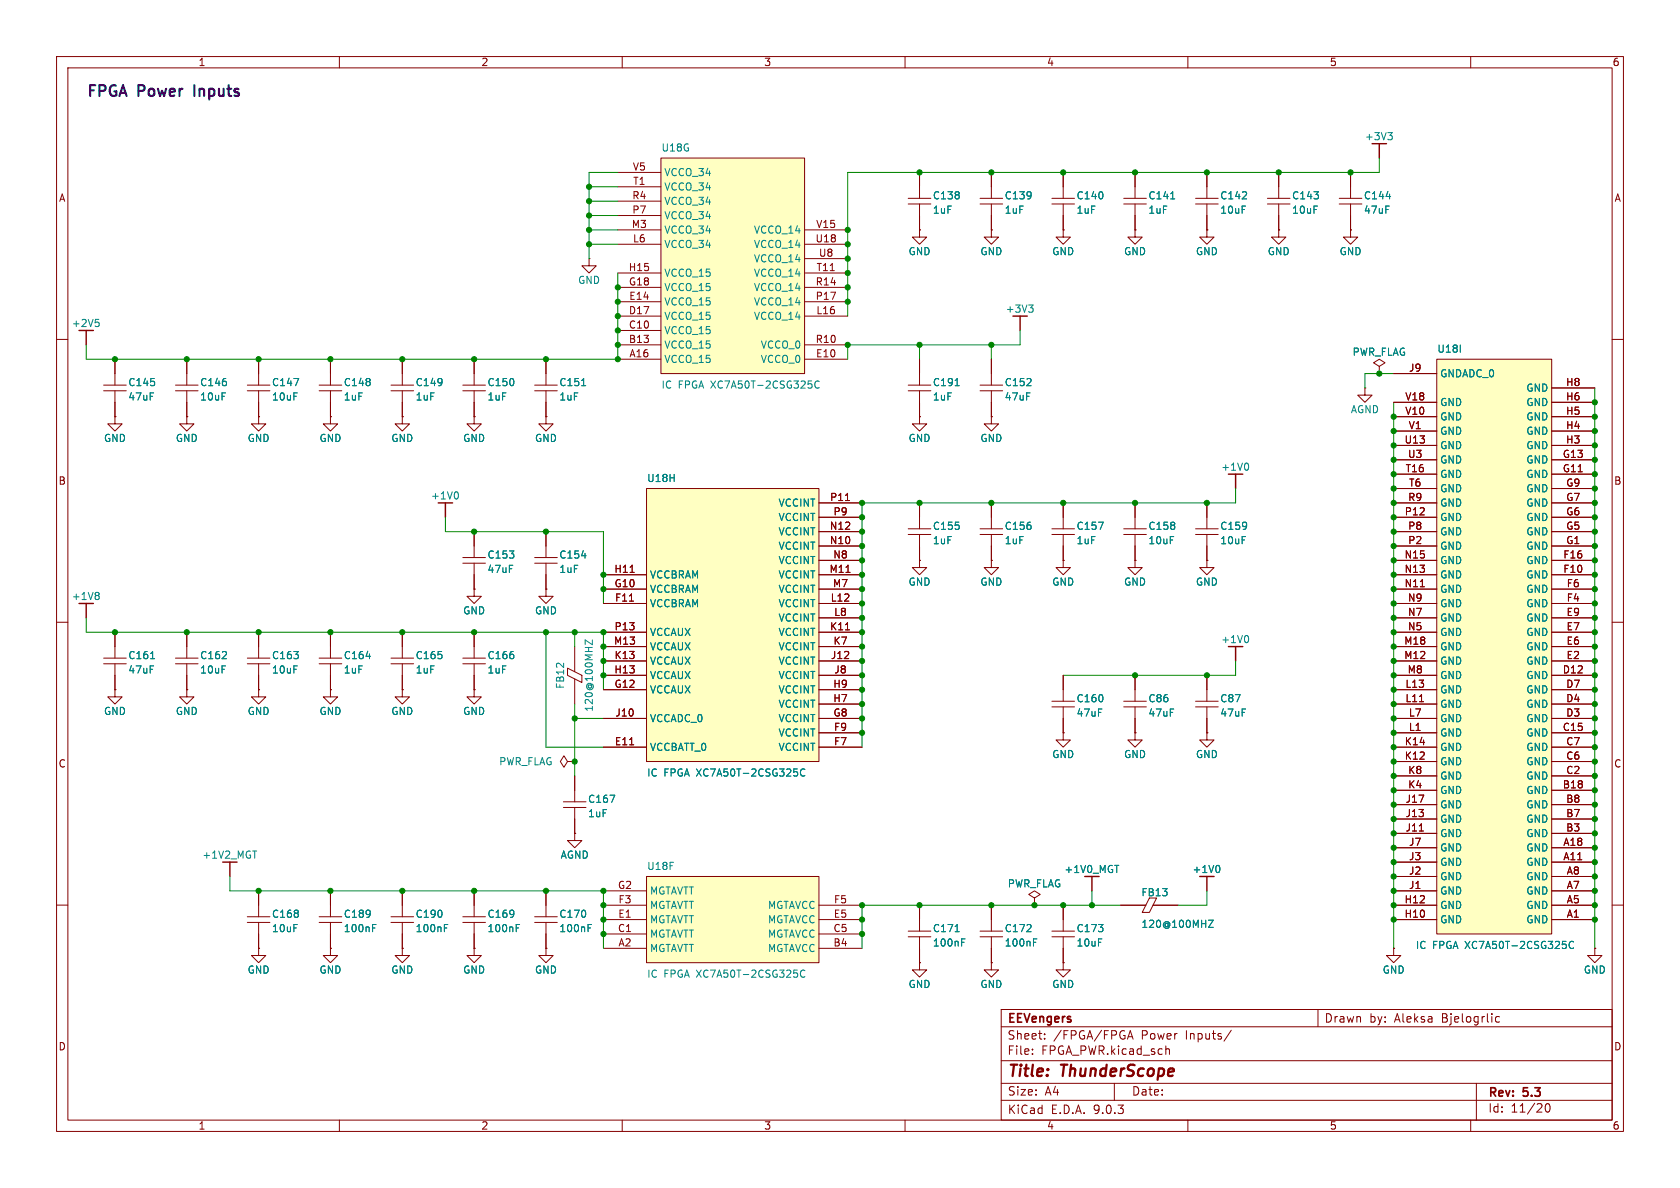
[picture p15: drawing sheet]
<svg xmlns="http://www.w3.org/2000/svg" width="297mm" height="210mm" viewBox="0 0 297 210" stroke-linecap="round" stroke-linejoin="round" font-family="sans-serif">
<defs><g id="words">
<g font-size="2.8" fill="#840000">
<text x="178" y="190.9">Title:</text>
<text x="187.7" y="190.9">ThunderScope</text>
</g>
<g font-size="2.7" fill="#0000c2">
<text x="15.2" y="18">FPGA</text>
<text x="24.5" y="18">Power</text>
<text x="35.2" y="18">Inputs</text>
</g>
<g font-size="2.1" fill="#840000">
<text x="178" y="184">Sheet:</text>
<text x="178" y="181.2">EEVengers</text>
<text x="186.2" y="184">/FPGA/FPGA</text>
<text x="201.8" y="184">Power</text>
<text x="209.8" y="184">Inputs/</text>
<text x="234.1" y="181">Drawn</text>
<text x="242.1" y="181">by:</text>
<text x="246.6" y="181">Aleksa</text>
<text x="255" y="181">Bjelogrlic</text>
<text x="178" y="186.7">File:</text>
<text x="184.1" y="186.7">FPGA_PWR.kicad_sch</text>
<text x="178.1" y="197.1">KiCad</text>
<text x="178.1" y="193.9">Size:</text>
<text x="184.7" y="193.9">A4</text>
<text x="185.8" y="197.1">E.D.A.</text>
<text x="193.4" y="197.1">9.0.3</text>
<text x="200" y="193.9">Date:</text>
<text x="263" y="194.3">Rev:</text>
<text x="263" y="196.9">Id:</text>
<text x="267.1" y="196.9">11/20</text>
<text x="269.4" y="194.3">5.3</text>
</g>
<g font-size="1.8" fill="#840000">
<text x="35" y="11.9">1</text>
<text x="85" y="11.9">2</text>
<text x="135" y="11.9">3</text>
<text x="185" y="11.9">4</text>
<text x="235" y="11.9">5</text>
<text x="285" y="11.9">6</text>
<text x="10.3" y="35.9">A</text>
<text x="111.7" y="35.3">R4</text>
<text x="111.8" y="30.2">V5</text>
<text x="111.8" y="32.8">T1</text>
<text x="285.3" y="35.9">A</text>
<text x="111.6" y="40.4">M3</text>
<text x="111.7" y="37.8">P7</text>
<text x="144.2" y="40.4">V15</text>
<text x="111.8" y="42.9">L6</text>
<text x="144.1" y="42.9">U18</text>
<text x="144.7" y="45.5">U8</text>
<text x="111.1" y="48">H15</text>
<text x="111.1" y="50.5">G18</text>
<text x="111.1" y="53.1">E14</text>
<text x="144.1" y="53.1">P17</text>
<text x="144.1" y="50.5">R14</text>
<text x="144.3" y="48">T11</text>
<text x="111.1" y="58.2">C10</text>
<text x="111.1" y="55.6">D17</text>
<text x="144.2" y="55.6">L16</text>
<text x="111.1" y="60.7">B13</text>
<text x="111.2" y="63.2">A16</text>
<text x="144.1" y="60.7">R10</text>
<text x="144.2" y="63.2">E10</text>
<text x="249" y="65.8">J9</text>
<text x="248.3" y="70.9">V18</text>
<text x="276.8" y="70.9">H6</text>
<text x="276.8" y="68.3">H8</text>
<text x="248.3" y="73.4">V10</text>
<text x="248.9" y="75.9">V1</text>
<text x="276.8" y="75.9">H4</text>
<text x="276.8" y="73.4">H5</text>
<text x="248.2" y="78.5">U13</text>
<text x="248.4" y="83.6">T16</text>
<text x="248.8" y="81">U3</text>
<text x="276.2" y="83.6">G11</text>
<text x="276.2" y="81">G13</text>
<text x="276.8" y="78.5">H3</text>
<text x="10.3" y="85.9">B</text>
<text x="146.6" y="88.6">P11</text>
<text x="248.8" y="88.6">R9</text>
<text x="249" y="86.1">T6</text>
<text x="276.8" y="88.6">G7</text>
<text x="276.8" y="86.1">G9</text>
<text x="285.3" y="85.9">B</text>
<text x="146.6" y="93.7">N12</text>
<text x="147.2" y="91.2">P9</text>
<text x="248.2" y="91.2">P12</text>
<text x="248.8" y="93.7">P8</text>
<text x="276.8" y="93.7">G5</text>
<text x="276.8" y="91.2">G6</text>
<text x="108.5" y="101.3">H11</text>
<text x="146.6" y="101.3">M11</text>
<text x="146.6" y="96.3">N10</text>
<text x="147.2" y="98.8">N8</text>
<text x="248.2" y="101.3">N13</text>
<text x="248.2" y="98.8">N15</text>
<text x="248.8" y="96.3">P2</text>
<text x="276.3" y="101.3">F10</text>
<text x="276.3" y="98.8">F16</text>
<text x="276.8" y="96.3">G1</text>
<text x="108.5" y="103.9">G10</text>
<text x="108.6" y="106.4">F11</text>
<text x="146.8" y="106.4">L12</text>
<text x="147.2" y="103.9">M7</text>
<text x="248.2" y="103.9">N11</text>
<text x="248.8" y="106.4">N9</text>
<text x="276.9" y="106.4">F4</text>
<text x="276.9" y="103.9">F6</text>
<text x="108.5" y="111.5">P13</text>
<text x="146.6" y="111.5">K11</text>
<text x="147.4" y="109">L8</text>
<text x="248.8" y="111.5">N5</text>
<text x="248.8" y="109">N7</text>
<text x="276.8" y="111.5">E7</text>
<text x="276.8" y="109">E9</text>
<text x="108.5" y="114">M13</text>
<text x="108.5" y="119.1">H13</text>
<text x="108.5" y="116.6">K13</text>
<text x="146.8" y="116.6">J12</text>
<text x="147.2" y="114">K7</text>
<text x="147.4" y="119.1">J8</text>
<text x="248.2" y="116.6">M12</text>
<text x="248.2" y="114">M18</text>
<text x="248.8" y="119.1">M8</text>
<text x="276.2" y="119.1">D12</text>
<text x="276.8" y="116.6">E2</text>
<text x="276.8" y="114">E6</text>
<text x="108.5" y="121.7">G12</text>
<text x="147.2" y="124.2">H7</text>
<text x="147.2" y="121.7">H9</text>
<text x="248.4" y="124.2">L11</text>
<text x="248.4" y="121.7">L13</text>
<text x="276.8" y="124.2">D4</text>
<text x="276.8" y="121.7">D7</text>
<text x="108.6" y="131.8">E11</text>
<text x="108.7" y="126.7">J10</text>
<text x="147.2" y="126.7">G8</text>
<text x="147.3" y="131.8">F7</text>
<text x="147.3" y="129.3">F9</text>
<text x="248.2" y="131.8">K14</text>
<text x="249" y="129.3">L1</text>
<text x="249" y="126.7">L7</text>
<text x="276.2" y="129.3">C15</text>
<text x="276.8" y="131.8">C7</text>
<text x="276.8" y="126.7">D3</text>
<text x="10.3" y="135.9">C</text>
<text x="248.2" y="134.4">K12</text>
<text x="248.8" y="136.9">K8</text>
<text x="276.8" y="136.9">C2</text>
<text x="276.8" y="134.4">C6</text>
<text x="285.3" y="135.9">C</text>
<text x="248.4" y="142">J17</text>
<text x="248.8" y="139.4">K4</text>
<text x="276.2" y="139.4">B18</text>
<text x="276.8" y="142">B8</text>
<text x="248.4" y="147.1">J11</text>
<text x="248.4" y="144.5">J13</text>
<text x="249" y="149.6">J7</text>
<text x="276.3" y="149.6">A18</text>
<text x="276.8" y="147.1">B3</text>
<text x="276.8" y="144.5">B7</text>
<text x="249" y="154.7">J2</text>
<text x="249" y="152.1">J3</text>
<text x="276.3" y="152.1">A11</text>
<text x="276.9" y="154.7">A8</text>
<text x="109.1" y="157.2">G2</text>
<text x="109.2" y="159.8">F3</text>
<text x="147.3" y="159.8">F5</text>
<text x="248.2" y="159.8">H12</text>
<text x="249" y="157.2">J1</text>
<text x="276.9" y="159.8">A5</text>
<text x="276.9" y="157.2">A7</text>
<text x="109.1" y="164.8">C1</text>
<text x="109.2" y="162.3">E1</text>
<text x="109.2" y="167.4">A2</text>
<text x="147.2" y="167.4">B4</text>
<text x="147.2" y="164.8">C5</text>
<text x="147.3" y="162.3">E5</text>
<text x="248.2" y="162.3">H10</text>
<text x="276.9" y="162.3">A1</text>
<text x="10.3" y="185.9">D</text>
<text x="285.3" y="185.9">D</text>
<text x="35" y="199.9">1</text>
<text x="85" y="199.9">2</text>
<text x="135" y="199.9">3</text>
<text x="185" y="199.9">4</text>
<text x="235" y="199.9">5</text>
<text x="285" y="199.9">6</text>
</g>
<g font-size="1.8" fill="#008484">
<text x="116.8" y="27">U18G</text>
<text x="241.2" y="25">+3V3</text>
<text x="117.3" y="33.9">VCCO_34</text>
<text x="117.3" y="31.3">VCCO_34</text>
<text x="164.8" y="35.4">C138</text>
<text x="177.5" y="35.4">C139</text>
<text x="190.2" y="35.4">C140</text>
<text x="202.9" y="35.4">C141</text>
<text x="215.6" y="35.4">C142</text>
<text x="228.3" y="35.4">C143</text>
<text x="241" y="35.4">C144</text>
<text x="117.3" y="41.5">VCCO_34</text>
<text x="117.3" y="39">VCCO_34</text>
<text x="117.3" y="36.4">VCCO_34</text>
<text x="133.2" y="41.5">VCCO_14</text>
<text x="164.8" y="38">1uF</text>
<text x="177.5" y="38">1uF</text>
<text x="190.2" y="38">1uF</text>
<text x="202.9" y="38">1uF</text>
<text x="215.6" y="38">10uF</text>
<text x="228.3" y="38">10uF</text>
<text x="241" y="38">47uF</text>
<text x="117.3" y="44">VCCO_34</text>
<text x="133.2" y="46.6">VCCO_14</text>
<text x="133.2" y="44">VCCO_14</text>
<text x="160.5" y="45.3">GND</text>
<text x="173.2" y="45.3">GND</text>
<text x="185.9" y="45.3">GND</text>
<text x="198.6" y="45.3">GND</text>
<text x="211.3" y="45.3">GND</text>
<text x="224" y="45.3">GND</text>
<text x="236.7" y="45.3">GND</text>
<text x="102.1" y="50.4">GND</text>
<text x="117.3" y="51.7">VCCO_15</text>
<text x="117.3" y="49.1">VCCO_15</text>
<text x="133.2" y="51.7">VCCO_14</text>
<text x="133.2" y="49.1">VCCO_14</text>
<text x="12.6" y="58">+2V5</text>
<text x="117.3" y="59.3">VCCO_15</text>
<text x="117.3" y="56.7">VCCO_15</text>
<text x="117.3" y="54.2">VCCO_15</text>
<text x="133.2" y="56.7">VCCO_14</text>
<text x="133.2" y="54.2">VCCO_14</text>
<text x="177.7" y="55.5">+3V3</text>
<text x="117.3" y="64.4">VCCO_15</text>
<text x="117.3" y="61.8">VCCO_15</text>
<text x="134.4" y="64.4">VCCO_0</text>
<text x="134.4" y="61.8">VCCO_0</text>
<text x="239" y="63.1">PWR_FLAG</text>
<text x="254" y="62.5">U18I</text>
<text x="22.6" y="68.5">C145</text>
<text x="22.6" y="71">47uF</text>
<text x="35.3" y="68.5">C146</text>
<text x="35.3" y="71">10uF</text>
<text x="48" y="68.5">C147</text>
<text x="48" y="71">10uF</text>
<text x="60.7" y="68.5">C148</text>
<text x="60.7" y="71">1uF</text>
<text x="73.4" y="68.5">C149</text>
<text x="73.4" y="71">1uF</text>
<text x="86.1" y="68.5">C150</text>
<text x="86.1" y="71">1uF</text>
<text x="98.8" y="68.5">C151</text>
<text x="98.8" y="71">1uF</text>
<text x="116.8" y="68.9">IC</text>
<text x="119.9" y="68.9">FPGA XC7A50T-2CSG325C</text>
<text x="164.8" y="68.5">C191</text>
<text x="164.8" y="71">1uF</text>
<text x="177.5" y="68.5">C152</text>
<text x="177.5" y="71">47uF</text>
<text x="254.5" y="72">GND</text>
<text x="254.5" y="66.9">GNDADC_0</text>
<text x="269.7" y="72">GND</text>
<text x="269.7" y="69.4">GND</text>
<text x="238.7" y="73.3">AGND</text>
<text x="254.5" y="77.1">GND</text>
<text x="254.5" y="74.5">GND</text>
<text x="269.7" y="77.1">GND</text>
<text x="269.7" y="74.5">GND</text>
<text x="18.3" y="78.3">GND</text>
<text x="31" y="78.3">GND</text>
<text x="43.7" y="78.3">GND</text>
<text x="56.4" y="78.3">GND</text>
<text x="69.1" y="78.3">GND</text>
<text x="81.8" y="78.3">GND</text>
<text x="94.5" y="78.3">GND</text>
<text x="160.5" y="78.3">GND</text>
<text x="173.2" y="78.3">GND</text>
<text x="215.8" y="83.4">+1V0</text>
<text x="254.5" y="82.1">GND</text>
<text x="254.5" y="79.6">GND</text>
<text x="269.7" y="82.1">GND</text>
<text x="269.7" y="79.6">GND</text>
<text x="76.1" y="88.5">+1V0</text>
<text x="114.3" y="85.4">U18H</text>
<text x="137.5" y="89.8">VCCINT</text>
<text x="254.5" y="89.8">GND</text>
<text x="254.5" y="87.2">GND</text>
<text x="254.5" y="84.7">GND</text>
<text x="269.7" y="89.8">GND</text>
<text x="269.7" y="87.2">GND</text>
<text x="269.7" y="84.7">GND</text>
<text x="137.5" y="94.8">VCCINT</text>
<text x="137.5" y="92.3">VCCINT</text>
<text x="164.8" y="93.9">C155</text>
<text x="177.5" y="93.9">C156</text>
<text x="190.2" y="93.9">C157</text>
<text x="202.9" y="93.9">C158</text>
<text x="215.6" y="93.9">C159</text>
<text x="254.5" y="94.8">GND</text>
<text x="254.5" y="92.3">GND</text>
<text x="269.7" y="94.8">GND</text>
<text x="269.7" y="92.3">GND</text>
<text x="86.1" y="98.9">C153</text>
<text x="86.1" y="101.5">47uF</text>
<text x="98.8" y="98.9">C154</text>
<text x="98.8" y="101.5">1uF</text>
<text x="137.5" y="99.9">VCCINT</text>
<text x="137.5" y="97.4">VCCINT</text>
<text x="164.8" y="96.4">1uF</text>
<text x="177.5" y="96.4">1uF</text>
<text x="190.2" y="96.4">1uF</text>
<text x="202.9" y="96.4">10uF</text>
<text x="215.6" y="96.4">10uF</text>
<text x="254.5" y="99.9">GND</text>
<text x="254.5" y="97.4">GND</text>
<text x="269.7" y="99.9">GND</text>
<text x="269.7" y="97.4">GND</text>
<text x="12.6" y="106.3">+1V8</text>
<text x="114.8" y="107.5">VCCBRAM</text>
<text x="114.8" y="105">VCCBRAM</text>
<text x="114.8" y="102.5">VCCBRAM</text>
<text x="137.5" y="107.5">VCCINT</text>
<text x="137.5" y="105">VCCINT</text>
<text x="137.5" y="102.5">VCCINT</text>
<text x="160.5" y="103.7">GND</text>
<text x="173.2" y="103.7">GND</text>
<text x="185.9" y="103.7">GND</text>
<text x="198.6" y="103.7">GND</text>
<text x="211.3" y="103.7">GND</text>
<text x="254.5" y="107.5">GND</text>
<text x="254.5" y="105">GND</text>
<text x="254.5" y="102.5">GND</text>
<text x="269.7" y="107.5">GND</text>
<text x="269.7" y="105">GND</text>
<text x="269.7" y="102.5">GND</text>
<text x="81.8" y="108.8">GND</text>
<text x="94.5" y="108.8">GND</text>
<text x="114.8" y="112.6">VCCAUX</text>
<text x="137.5" y="112.6">VCCINT</text>
<text x="137.5" y="110.1">VCCINT</text>
<text x="215.8" y="113.9">+1V0</text>
<text x="254.5" y="112.6">GND</text>
<text x="254.5" y="110.1">GND</text>
<text x="269.7" y="112.6">GND</text>
<text x="269.7" y="110.1">GND</text>
<text x="22.6" y="116.7">C161</text>
<text x="22.6" y="119.3">47uF</text>
<text x="35.3" y="116.7">C162</text>
<text x="35.3" y="119.3">10uF</text>
<text x="48" y="116.7">C163</text>
<text x="48" y="119.3">10uF</text>
<text x="60.7" y="116.7">C164</text>
<text x="60.7" y="119.3">1uF</text>
<text x="73.4" y="116.7">C165</text>
<text x="73.4" y="119.3">1uF</text>
<text x="86.1" y="116.7">C166</text>
<text x="86.1" y="119.3">1uF</text>
<text x="114.8" y="117.7">VCCAUX</text>
<text x="114.8" y="115.2">VCCAUX</text>
<text x="137.5" y="117.7">VCCINT</text>
<text x="137.5" y="115.2">VCCINT</text>
<text x="254.5" y="117.7">GND</text>
<text x="254.5" y="115.2">GND</text>
<text x="269.7" y="117.7">GND</text>
<text x="269.7" y="115.2">GND</text>
<text x="99.9" y="121.9" transform="rotate(-90 99.9 121.9)">FB12</text>
<text x="105" y="125.9" transform="rotate(-90 105 125.9)">120@100MHZ</text>
<text x="114.8" y="122.8">VCCAUX</text>
<text x="114.8" y="120.2">VCCAUX</text>
<text x="137.5" y="125.3">VCCINT</text>
<text x="137.5" y="122.8">VCCINT</text>
<text x="137.5" y="120.2">VCCINT</text>
<text x="190.2" y="124.3">C160</text>
<text x="202.9" y="124.3">C86</text>
<text x="215.6" y="124.3">C87</text>
<text x="254.5" y="125.3">GND</text>
<text x="254.5" y="122.8">GND</text>
<text x="254.5" y="120.2">GND</text>
<text x="269.7" y="125.3">GND</text>
<text x="269.7" y="122.8">GND</text>
<text x="269.7" y="120.2">GND</text>
<text x="18.3" y="126.6">GND</text>
<text x="31" y="126.6">GND</text>
<text x="43.7" y="126.6">GND</text>
<text x="56.4" y="126.6">GND</text>
<text x="69.1" y="126.6">GND</text>
<text x="81.8" y="126.6">GND</text>
<text x="114.8" y="127.9">VCCADC_0</text>
<text x="137.5" y="130.4">VCCINT</text>
<text x="137.5" y="127.9">VCCINT</text>
<text x="190.2" y="126.9">47uF</text>
<text x="202.9" y="126.9">47uF</text>
<text x="215.6" y="126.9">47uF</text>
<text x="254.5" y="130.4">GND</text>
<text x="254.5" y="127.9">GND</text>
<text x="269.7" y="130.4">GND</text>
<text x="269.7" y="127.9">GND</text>
<text x="88.1" y="135.5">PWR_FLAG</text>
<text x="114.3" y="137.5">IC</text>
<text x="114.8" y="132.9">VCCBATT_0</text>
<text x="117.4" y="137.5">FPGA XC7A50T-2CSG325C</text>
<text x="137.5" y="132.9">VCCINT</text>
<text x="185.9" y="134.2">GND</text>
<text x="198.6" y="134.2">GND</text>
<text x="211.3" y="134.2">GND</text>
<text x="254.5" y="135.5">GND</text>
<text x="254.5" y="132.9">GND</text>
<text x="269.7" y="135.5">GND</text>
<text x="269.7" y="132.9">GND</text>
<text x="103.9" y="142.1">C167</text>
<text x="254.5" y="143.1">GND</text>
<text x="254.5" y="140.6">GND</text>
<text x="254.5" y="138">GND</text>
<text x="269.7" y="143.1">GND</text>
<text x="269.7" y="140.6">GND</text>
<text x="269.7" y="138">GND</text>
<text x="103.9" y="144.7">1uF</text>
<text x="254.5" y="148.2">GND</text>
<text x="254.5" y="145.6">GND</text>
<text x="269.7" y="148.2">GND</text>
<text x="269.7" y="145.6">GND</text>
<text x="35.7" y="152">+1V2_MGT</text>
<text x="99" y="152">AGND</text>
<text x="114.3" y="154">U18F</text>
<text x="188.1" y="154.5">+1V0_MGT</text>
<text x="210.7" y="154.5">+1V0</text>
<text x="254.5" y="155.8">GND</text>
<text x="254.5" y="153.3">GND</text>
<text x="254.5" y="150.7">GND</text>
<text x="269.7" y="155.8">GND</text>
<text x="269.7" y="153.3">GND</text>
<text x="269.7" y="150.7">GND</text>
<text x="114.8" y="160.9">MGTAVTT</text>
<text x="114.8" y="158.3">MGTAVTT</text>
<text x="135.7" y="160.9">MGTAVCC</text>
<text x="178.1" y="157.1">PWR_FLAG</text>
<text x="201.7" y="158.6">FB13</text>
<text x="254.5" y="160.9">GND</text>
<text x="254.5" y="158.3">GND</text>
<text x="269.7" y="160.9">GND</text>
<text x="269.7" y="158.3">GND</text>
<text x="48" y="162.4">C168</text>
<text x="48" y="165">10uF</text>
<text x="60.7" y="162.4">C189</text>
<text x="60.7" y="165">100nF</text>
<text x="73.4" y="162.4">C190</text>
<text x="73.4" y="165">100nF</text>
<text x="86.1" y="162.4">C169</text>
<text x="86.1" y="165">100nF</text>
<text x="98.8" y="162.4">C170</text>
<text x="98.8" y="165">100nF</text>
<text x="114.8" y="166">MGTAVTT</text>
<text x="114.8" y="163.4">MGTAVTT</text>
<text x="135.7" y="166">MGTAVCC</text>
<text x="135.7" y="163.4">MGTAVCC</text>
<text x="164.8" y="165">C171</text>
<text x="164.8" y="167.5">100nF</text>
<text x="177.5" y="165">C172</text>
<text x="177.5" y="167.5">100nF</text>
<text x="190.2" y="165">C173</text>
<text x="190.2" y="167.5">10uF</text>
<text x="201.7" y="164.2">120@100MHZ</text>
<text x="250.2" y="168">IC</text>
<text x="253.2" y="168">FPGA XC7A50T-2CSG325C</text>
<text x="254.5" y="163.4">GND</text>
<text x="269.7" y="163.4">GND</text>
<text x="43.7" y="172.3">GND</text>
<text x="56.4" y="172.3">GND</text>
<text x="69.1" y="172.3">GND</text>
<text x="81.8" y="172.3">GND</text>
<text x="94.5" y="172.3">GND</text>
<text x="114.3" y="173">IC</text>
<text x="114.8" y="168.5">MGTAVTT</text>
<text x="117.4" y="173">FPGA XC7A50T-2CSG325C</text>
<text x="135.7" y="168.5">MGTAVCC</text>
<text x="244.3" y="172.3">GND</text>
<text x="279.9" y="172.3">GND</text>
<text x="160.5" y="174.9">GND</text>
<text x="173.2" y="174.9">GND</text>
<text x="185.9" y="174.9">GND</text>
</g>
</g></defs>
<path d="M0 0h297v210h-297z" fill="#fff" stroke="#fff" stroke-width=".18"/>
<g fill="none" stroke="#840000" stroke-width=".18">
<path d="M10 10h277v190h-277zM12 12h273v186h-273zM60 10v2M110 10v2M160 10v2M210 10v2M260 10v2M104.1 45.7v1.3h1.3l-1.3 1.3-1.2-1.3h1.2M104.1 45.7h.1M10 60h2M18.3 68.1h4M18.3 69.1h4"/>
<path d="M20.3 63.5v4.6M20.3 69.1v4.6M31 68.1h4M31 69.1h4M33 73.7v1.2h1.3l-1.3 1.3-1.3-1.3h1.3M33 73.7h.1M33 63.5v4.6M33 69.1v4.6M43.7 68.1h4M43.7 69.1h4M45.7 73.7v1.2h1.3l-1.3 1.3-1.3-1.3h1.3M45.7 73.7h.1"/>
<path d="M45.7 63.5v4.6M45.7 69.1v4.6M81.8 68.1h4M81.8 69.1h4M83.8 73.7v1.2h1.3l-1.3 1.3-1.3-1.3h1.3M83.8 73.7h.1M83.8 63.5v4.6M83.8 69.1v4.6M94.5 68.1h4M94.5 69.1h4M96.5 73.7v1.2h1.3l-1.3 1.3-1.3-1.3h1.3M96.5 73.7h.1"/>
<path d="M96.5 63.5v4.6M96.5 69.1v4.6M285 60h2M81.8 98.6h4M81.8 99.6h4M83.8 94v4.6M83.8 99.6v4.5M94.5 98.6h4M94.5 99.6h4M96.5 94v4.6M96.5 99.6v4.5M10 110h2"/>
<path d="M81.8 116.3h4M81.8 117.3h4M83.8 104.1v1.3h1.3l-1.3 1.3-1.3-1.3h1.3M83.8 104.1h.1M83.8 111.8v4.5M83.8 117.3v4.6M96.5 104.1v1.3h1.3l-1.3 1.3-1.3-1.3h1.3M96.5 104.1h.1M285 110h2M45.7 121.9v1.3h1.3l-1.3 1.3-1.3-1.3h1.3M45.7 121.9h.1M83.8 121.9v1.3h1.3l-1.3 1.3-1.3-1.3h1.3"/>
<path d="M83.8 121.9h.1M71.1 157.5v4.6M83.8 157.5v4.6M10 160h2M69.1 162.1h4M69.1 163.1h4M71.1 167.6v1.3h1.3l-1.3 1.3-1.3-1.3h1.3M71.1 167.6h.1M71.1 163.1v4.5M81.8 162.1h4M81.8 163.1h4M83.8 167.6v1.3h1.3l-1.3 1.3-1.3-1.3h1.3"/>
<path d="M83.8 167.6h.1M83.8 163.1v4.5M96.5 167.6v1.3h1.3l-1.3 1.3-1.3-1.3h1.3M96.5 167.6h.1M177 178.5h108v19.5h-108zM233 178.5v3M265.1 179.8l-.4-.1-.3 .3v.4l.1 .2h.6M285 160h2M60 198v2M110 198v2M160 198v2M177 194.5h108"/>
<path d="M177 191.5h108M177 187.5h108M177 181.5h108M182.5 186.3v.1M182.5 185.5v.1M184.7 183.6v.1M184.7 182.8v.1M197 191.5v3M199.3 183.7l.5-1.5 .5 1.5M199.5 183.3h.7M206.2 185.5h.5v.9M210 198v2"/>
<path d="M217.7 182.1l-1.3 2M260 198v2M261 191.5v6.5M273.3 195.2l.2-.1a.81 .81 0 0 1 .6 .6 .81 .81 0 0 1-.3 .8l-.1 .1a.81 .81 0 0 1-.4-1.4z"/>
</g>
<path d="M52 66.9h.8l-.5 1.3M102.8 68.2h.7M80.7 86.9a.79 .79 0 0 1 0 1.3M102.8 98.2h.8M44.7 150.4h.7M78.6 164h.4M78.6 163.4h.6M91.3 164h.4M91.3 163.4h.6" fill="none" stroke="#008484" stroke-width=".18"/>
<path d="M78.7 88.9v2.5M40.6 152.4v2.5" fill="none" stroke="#840000" stroke-width=".25"/>
<path d="M116.8 27.9h25.4v38.1h-25.4z" fill="#ffffc2"/>
<path d="M116.8 27.9h25.4v38.1h-25.4z" fill="none" stroke="#800000" stroke-width=".18"/>
<g fill="none" stroke="#840000" stroke-width=".18">
<path d="M109.2 38.1h7.6M109.2 35.6h7.6M109.2 33h7.6M109.2 30.5h7.6M109.2 58.4h7.6M109.2 55.9h7.6M109.2 53.3h7.6M109.2 50.8h7.6M109.2 48.3h7.6M109.2 43.2h7.6M109.2 40.6h7.6M142.2 55.9h7.7"/>
<path d="M142.2 53.3h7.7M142.2 50.8h7.7M142.2 48.3h7.7M142.2 43.2h7.7M142.2 40.6h7.7M142.2 45.7h7.7M56.4 68.1h4M56.4 69.1h4M58.4 63.5v4.6M58.4 69.1v4.6M69.1 68.1h4M69.1 69.1h4"/>
<path d="M71.1 63.5v4.6M71.1 69.1v4.6M109.2 63.5h7.6M109.2 61h7.6M142.2 63.5h7.7M142.2 61h7.7M18.3 116.3h4M18.3 117.3h4M20.3 111.8v4.5M20.3 117.3v4.6M56.4 116.3h4M56.4 117.3h4"/>
<path d="M58.4 111.8v4.5M58.4 117.3v4.6M33 121.9v1.3h1.3l-1.3 1.3-1.3-1.3h1.3M33 121.9h.1M58.4 121.9v1.3h1.3l-1.3 1.3-1.3-1.3h1.3M58.4 121.9h.1M71.1 121.9v1.3h1.3l-1.3 1.3-1.3-1.3h1.3M71.1 121.9h.1"/>
</g>
<path d="M16.9 56.5h.6M17.3 56.9l.2 .3v.3l-.2 .2M144.8 67.5a.6 .6 0 0 0-.8 .4 .6 .6 0 0 0 .6 .7l.2-.1M17.3 104.7l.2 .3-.2 .3 .2 .2v.2l-.2 .3M26.6 116.4h.7M64.7 116h.8M220.4 112.3a.79 .79 0 0 1 0 1.3M215.4 153a.79 .79 0 0 1 0 1.2" fill="none" stroke="#008484" stroke-width=".18"/>
<path d="M15.2 58.4v2.6M15.2 106.7v2.5M218.4 114.3v2.5M213.4 154.9v2.6" fill="none" stroke="#840000" stroke-width=".25"/>
<path d="M114.3 86.4h30.5v48.2h-30.5z" fill="#ffffc2"/>
<path d="M114.3 86.4h30.5v48.2h-30.5z" fill="none" stroke="#800000" stroke-width=".18"/>
<g fill="none" stroke="#840000" stroke-width=".18">
<path d="M58.4 73.7v1.2h1.3l-1.3 1.3-1.3-1.3h1.3M58.4 73.7h.1M71.1 73.7v1.2h1.3l-1.3 1.3-1.3-1.3h1.3M71.1 73.7h.1M144.8 99.1h7.6M144.8 96.5h7.6M144.8 94h7.6M144.8 91.4h7.6M144.8 88.9h7.6M149.5 88.5h.7M31 116.3h4M31 117.3h4"/>
<path d="M33 111.8v4.5M33 117.3v4.6M69.1 116.3h4M69.1 117.3h4M71.1 111.8v4.5M71.1 117.3v4.6M106.7 119.4h7.6M106.7 116.8h7.6M106.7 114.3h7.6M106.7 111.8h7.6M106.7 106.7h7.6M106.7 104.1h7.6"/>
<path d="M106.7 101.6h7.6M111.3 106.3h.7M111.4 101.2h.7M144.8 119.4h7.6M144.8 116.8h7.6M144.8 114.3h7.6M144.8 111.8h7.6M144.8 106.7h7.6M144.8 104.1h7.6M144.8 101.6h7.6M144.8 109.2h7.6M149.5 111.3h.7"/>
<path d="M149.6 101.2h.7M100.3 134.6l-.6-1-.6 1 .6 1 .6-1h1.3M101.6 134.6h.1M101.6 137.2v4.5M106.7 132.1h7.6M106.7 127h7.6M106.7 121.9h7.6M111.3 131.7h.7M144.8 132.1h7.6M144.8 127h7.6M144.8 121.9h7.6M144.8 129.5h7.6"/>
<path d="M144.8 124.5h7.6M45.7 157.5v4.6M58.4 157.5v4.6M99.6 141.7h4M99.6 142.7h4M101.6 142.7v4.6M43.7 162.1h4M43.7 163.1h4M45.7 167.6v1.3h1.3l-1.3 1.3-1.3-1.3h1.3M45.7 167.6h.1M45.7 163.1v4.5M56.4 162.1h4"/>
<path d="M56.4 163.1h4M58.4 167.6v1.3h1.3l-1.3 1.3-1.3-1.3h1.3M58.4 167.6h.1M58.4 163.1v4.5"/>
</g>
<path d="M142.3 136a.6 .6 0 0 0-.8 .5 .6 .6 0 0 0 .5 .7l.3-.1M107.8 140.6h.9l-.6 1.2M65.9 164h.4M65.9 163.4h.6" fill="none" stroke="#008484" stroke-width=".18"/>
<path d="M114.3 154.9h30.5v15.3h-30.5z" fill="#ffffc2"/>
<path d="M114.3 154.9h30.5v15.3h-30.5z" fill="none" stroke="#800000" stroke-width=".18"/>
<g fill="none" stroke="#840000" stroke-width=".18">
<path d="M198.7 35.1h4M198.7 36.1h4M200.7 30.5v4.6M200.7 36.1v4.5M211.4 35.1h4M211.4 36.1h4M213.4 30.5v4.6M213.4 36.1v4.5M224.1 35.1h4M224.1 36.1h4M226.1 30.5v4.6M226.1 36.1v4.5"/>
<path d="M236.8 35.1h4M236.8 36.1h4M238.8 30.5v4.6M238.8 36.1v4.5M200.7 40.6v1.3h1.2l-1.2 1.3-1.3-1.3h1.3M200.7 40.6h.1M213.4 40.6v1.3h1.2l-1.2 1.3-1.3-1.3h1.3M213.4 40.6h.1M226.1 40.6v1.3h1.2l-1.2 1.3-1.3-1.3h1.3M226.1 40.6h.1M238.8 40.6v1.3h1.2l-1.2 1.3-1.3-1.3h1.3M238.8 40.6h.1"/>
<path d="M20.3 73.7v1.2h1.3l-1.3 1.3-1.3-1.3h1.3M20.3 73.7h.1M241.3 68.6v1.3h1.3l-1.3 1.2-1.3-1.2h1.3M241.3 68.6h.1M243.8 64.8l1.1-.7-1.1-.6-1 .6 1 .7v1.2M243.8 66h.1M162.6 99.1v1.2h1.2l-1.2 1.3-1.3-1.3h1.3M162.6 99.1h.1M198.7 93.5h4M198.7 94.5h4M200.7 99.1v1.2h1.2l-1.2 1.3-1.3-1.3h1.3M200.7 99.1h.1"/>
<path d="M200.7 88.9v4.6M200.7 94.5v4.6M211.4 93.5h4M211.4 94.5h4M213.4 99.1v1.2h1.2l-1.2 1.3-1.3-1.3h1.3M213.4 99.1h.1M213.4 88.9v4.6M213.4 94.5v4.6M43.7 116.3h4M43.7 117.3h4M45.7 111.8v4.5M45.7 117.3v4.6"/>
<path d="M100.3 118.1l2.6 1.3v1.3l-2.6-1.3zM101.6 114.3v4.4M188 119.4v4.6M200.7 119.4v4.6M213.4 119.4v4.6M20.3 121.9v1.3h1.3l-1.3 1.3-1.3-1.3h1.3M20.3 121.9h.1M101.6 120v4.5M186 124h4M186 125h4M188 129.5v1.3h1.2l-1.2 1.3-1.3-1.3h1.3M188 129.5h.1"/>
<path d="M188 125v4.5M198.7 124h4M198.7 125h4M200.7 129.5v1.3h1.2l-1.2 1.3-1.3-1.3h1.3M200.7 129.5h.1M200.7 125v4.5M211.4 124h4M211.4 125h4M213.4 129.5v1.3h1.2l-1.2 1.3-1.3-1.3h1.3M213.4 129.5h.1M213.4 125v4.5M96.5 157.5v4.6"/>
<path d="M101.6 147.3v1.3h1.3l-1.3 1.3-1.3-1.3h1.3M101.6 147.3h.1M106.7 157.5h7.6M182.9 158.8l1-.7-1-.6-1 .6 1 .7v1.2M203.2 158.8h1.3l-1.3 2.5h-1.3zM94.5 162.1h4M94.5 163.1h4M96.5 163.1v4.5M106.7 167.6h7.6M106.7 165.1h7.6M106.7 162.6h7.6M106.7 160h7.6"/>
<path d="M144.8 167.6h7.6M144.8 165.1h7.6M144.8 162.6h7.6M144.8 160h7.6M160.6 164.6h4M160.6 165.6h4M162.6 170.2v1.3h1.2l-1.2 1.2-1.3-1.2h1.3M162.6 170.2h.1M162.6 160v4.6M162.6 165.6v4.6M173.3 164.6h4M173.3 165.6h4"/>
<path d="M175.3 170.2v1.3h1.2l-1.2 1.2-1.3-1.2h1.3M175.3 170.2h.1M175.3 160v4.6M175.3 165.6v4.6M182.9 160h.1M186 164.6h4M186 165.6h4M188 170.2v1.3h1.2l-1.2 1.2-1.3-1.2h1.3M188 170.2h.1M188 160v4.6M188 165.6v4.6M198.1 160h4.5"/>
<path d="M203.8 160h4.5M246.4 167.6v1.3h1.2l-1.2 1.3-1.3-1.3h1.3M246.4 167.6h.1M281.9 167.6v1.3h1.3l-1.3 1.3-1.2-1.3h1.2M281.9 167.6h.1"/>
</g>
<g fill="none" stroke="#008484" stroke-width=".18">
<path d="M207 35.2h.7M245.1 34.7h.7M245.4 23.4h.7l-.4 .5M245.9 23.9l.2 .3v.3l-.2 .2M220.4 81.9a.79 .79 0 0 1 0 1.2M104.7 113.1v.9l-1.3-.9v.9M197.1 153h.7M104 164h.4M104 163.4h.6M142.3 171.6a.6 .6 0 0 0-.8 .4 .6 .6 0 0 0 .5 .8l.3-.2M168.9 164.7h.7M170 166.6h.4"/>
<path d="M170 166h.6M182.7 166.6h.4M182.7 166h.6M213.6 162.7h.9l-.9 1.2h.9"/>
</g>
<path d="M243.8 25.4v2.5M218.4 83.8v2.6M193 154.9v2.6" fill="none" stroke="#840000" stroke-width=".25"/>
<path d="M254 63.5h20.3v101.6h-20.3z" fill="#ffffc2"/>
<path d="M254 63.5h20.3v101.6h-20.3z" fill="none" stroke="#800000" stroke-width=".18"/>
<g fill="none" stroke="#840000" stroke-width=".18">
<path d="M160.6 35.1h4M160.6 36.1h4M162.6 30.5v4.6M162.6 36.1v4.5M173.3 35.1h4M173.3 36.1h4M175.3 30.5v4.6M175.3 36.1v4.5M186 35.1h4M186 36.1h4M188 30.5v4.6M188 36.1v4.5"/>
<path d="M200.7 30.5v2.5M200.7 38.1v2.5M213.4 30.5v2.5M213.4 38.1v2.5M226.1 30.5v2.5M226.1 38.1v2.5M238.8 30.5v2.5M238.8 38.1v2.5M162.6 40.6v1.3h1.2l-1.2 1.3-1.3-1.3h1.3M162.6 40.6h.1M175.3 40.6v1.3h1.2l-1.2 1.3-1.3-1.3h1.3M175.3 40.6h.1"/>
<path d="M188 40.6v1.3h1.2l-1.2 1.3-1.3-1.3h1.3M188 40.6h.1M200.7 40.6h.1M213.4 40.6h.1M226.1 40.6h.1M238.8 40.6h.1M20.3 73.7h.1M20.3 63.5v2.5M20.3 71.1v2.6M33 73.7h.1M33 63.5v2.5M33 71.1v2.6"/>
<path d="M45.7 73.7h.1M45.7 63.5v2.5M45.7 71.1v2.6M58.4 73.7h.1M58.4 63.5v2.5M58.4 71.1v2.6M71.1 73.7h.1M71.1 63.5v2.5M71.1 71.1v2.6M83.8 73.7h.1M83.8 63.5v2.5M83.8 71.1v2.6"/>
<path d="M96.5 73.7h.1M96.5 63.5v2.5M96.5 71.1v2.6M160.6 68.1h4M160.6 69.1h4M162.6 73.7v1.2h1.2l-1.2 1.3-1.3-1.3h1.3M162.6 73.7h.1M162.6 63.5v4.6M162.6 69.1v4.6M173.3 68.1h4M173.3 69.1h4M175.3 73.7v1.2h1.2l-1.2 1.3-1.3-1.3h1.3"/>
<path d="M175.3 73.7h.1M175.3 63.5v4.6M175.3 69.1v4.6M243.8 66h.1M246.4 78.7h7.6M246.4 76.2h7.6M246.4 73.7h7.6M246.4 71.1h7.6M246.4 66h7.6M274.3 78.7h7.6M274.3 76.2h7.6M274.3 73.7h7.6"/>
<path d="M274.3 71.1h7.6M274.3 68.6h7.6M83.8 94v2.5M96.5 94v2.5M144.8 99.1h7.6M144.8 96.5h7.6M144.8 94h7.6M144.8 91.4h7.6M144.8 88.9h7.6M149.5 88.5h.7M160.6 93.5h4M160.6 94.5h4"/>
<path d="M162.6 99.1h.1M162.6 88.9v4.6M162.6 94.5v4.6M173.3 93.5h4M173.3 94.5h4M175.3 99.1v1.2h1.2l-1.2 1.3-1.3-1.3h1.3M175.3 99.1h.1M175.3 88.9v4.6M175.3 94.5v4.6M186 93.5h4M186 94.5h4M188 99.1v1.2h1.2l-1.2 1.3-1.3-1.3h1.3"/>
<path d="M188 99.1h.1M188 88.9v4.6M188 94.5v4.6M200.7 99.1h.1M200.7 88.9v2.5M200.7 96.5v2.6M213.4 99.1h.1M213.4 88.9v2.5M213.4 96.5v2.6M246.4 99.1h7.6M246.4 96.5h7.6M246.4 94h7.6"/>
<path d="M246.4 91.4h7.6M246.4 88.9h7.6M246.4 86.4h7.6M246.4 83.8h7.6M246.4 81.3h7.6M274.3 99.1h7.6M274.3 96.5h7.6M274.3 94h7.6M274.3 91.4h7.6M274.3 88.9h7.6M274.3 86.4h7.6M274.3 83.8h7.6"/>
<path d="M274.3 81.3h7.6M20.3 111.8v2.5M20.3 119.4v2.5M33 111.8v2.5M33 119.4v2.5M45.7 111.8v2.5M45.7 119.4v2.5M58.4 111.8v2.5M58.4 119.4v2.5M71.1 111.8v2.5M71.1 119.4v2.5M83.8 104.1h.1"/>
<path d="M83.8 101.6v2.5M83.8 111.8v2.5M83.8 119.4v2.5M96.5 104.1h.1M96.5 101.6v2.5M106.7 119.4h7.6M106.7 116.8h7.6M106.7 114.3h7.6M106.7 111.8h7.6M106.7 106.7h7.6M106.7 104.1h7.6M106.7 101.6h7.6"/>
<path d="M111.3 106.3h.7M111.4 101.2h.7M144.8 119.4h7.6M144.8 116.8h7.6M144.8 114.3h7.6M144.8 111.8h7.6M144.8 109.2h7.6M144.8 106.7h7.6M144.8 104.1h7.6M144.8 101.6h7.6M149.5 111.3h.7M149.6 101.2h.7"/>
<path d="M188 119.4v2.5M200.7 119.4v2.5M213.4 119.4v2.5M246.4 119.4h7.6M246.4 116.8h7.6M246.4 114.3h7.6M246.4 111.8h7.6M246.4 109.2h7.6M246.4 106.7h7.6M246.4 104.1h7.6M246.4 101.6h7.6M251.1 103.7h.7"/>
<path d="M274.3 119.4h7.6M274.3 116.8h7.6M274.3 114.3h7.6M274.3 111.8h7.6M274.3 109.2h7.6M274.3 106.7h7.6M274.3 104.1h7.6M274.3 101.6h7.6M20.3 121.9h.1M33 121.9h.1M45.7 121.9h.1M58.4 121.9h.1"/>
<path d="M71.1 121.9h.1M83.8 121.9h.1M101.6 137.2v2.5M106.7 132.1h7.6M106.7 127h7.6M106.7 121.9h7.6M111.3 131.7h.7M144.8 132.1h7.6M144.8 129.5h7.6M144.8 127h7.6M144.8 124.5h7.6M144.8 121.9h7.6"/>
<path d="M188 129.5h.1M188 127v2.5M200.7 129.5h.1M200.7 127v2.5M213.4 129.5h.1M213.4 127v2.5M246.4 139.7h7.6M246.4 137.2h7.6M246.4 134.6h7.6M246.4 132.1h7.6M246.4 129.5h7.6M246.4 127h7.6"/>
<path d="M246.4 124.5h7.6M246.4 121.9h7.6M250.9 124h.8M274.3 139.7h7.6M274.3 137.2h7.6M274.3 134.6h7.6M274.3 132.1h7.6M274.3 129.5h7.6M274.3 127h7.6M274.3 124.5h7.6M274.3 121.9h7.6M45.7 157.5v2.5"/>
<path d="M58.4 157.5v2.5M71.1 157.5v2.5M83.8 157.5v2.5M96.5 157.5v2.5M101.6 147.3h.1M101.6 144.8v2.5M246.4 157.5h7.6M246.4 154.9h7.6M246.4 152.4h7.6M246.4 149.9h7.6M246.4 147.3h7.6M246.4 144.8h7.6"/>
<path d="M246.4 142.2h7.6M250.9 146.9h.7M274.3 157.5h7.6M274.3 154.9h7.6M274.3 152.4h7.6M274.3 149.9h7.6M274.3 147.3h7.6M274.3 144.8h7.6M274.3 142.2h7.6M45.7 167.6h.1M45.7 165.1v2.5M58.4 167.6h.1"/>
<path d="M58.4 165.1v2.5M71.1 167.6h.1M71.1 165.1v2.5M83.8 167.6h.1M83.8 165.1v2.5M96.5 167.6h.1M96.5 165.1v2.5M162.6 170.2h.1M162.6 160v2.6M162.6 167.6v2.6M175.3 170.2h.1M175.3 160v2.6"/>
<path d="M175.3 167.6v2.6M182.9 160h.1M188 170.2h.1M188 160v2.6M188 167.6v2.6M198.1 160h4.5M203.8 160h4.5M246.4 167.6h.1M246.4 162.6h7.6M246.4 160h7.6M274.3 162.6h7.6M274.3 160h7.6"/>
<path d="M281.9 167.6h.1"/>
</g>
<g fill="none" stroke="#008484" stroke-width=".18">
<path d="M207 35.2h.7M245.1 34.7h.7M181.9 53.9h.7l-.4 .5M182.4 54.4l.2 .2v.3l-.2 .3M52 66.9h.8l-.5 1.3M102.8 68.2h.7M168.9 68.2h.7M102.8 98.2h.8M194.2 92.3h.8l-.5 1.3M26.6 116.4h.7M64.7 116h.8M142.3 136a.6 .6 0 0 0-.8 .5 .6 .6 0 0 0 .5 .7l.3-.1"/>
<path d="M107.8 140.6h.9l-.6 1.2M197.1 153h.7M215.4 153a.79 .79 0 0 1 0 1.2M65.9 164h.4M65.9 163.4h.6M78.6 164h.4M78.6 163.4h.6M91.3 164h.4M91.3 163.4h.6M104 164h.4M104 163.4h.6M168.9 164.7h.7"/>
<path d="M170 166.6h.4M170 166h.6M182.7 166.6h.4M182.7 166h.6M213.6 162.7h.9l-.9 1.2h.9M278.2 166.5a.6 .6 0 0 0-.9 .4 .6 .6 0 0 0 .6 .8l.3-.1"/>
</g>
<path d="M180.3 55.9v2.5" fill="none" stroke="#840000" stroke-width=".25"/>
<g fill="none" stroke="#008400" stroke-width=".18">
<path d="M104.1 33h5.1M104.1 35.6h5.1M104.1 38.1h5.1M109.2 30.5h-5.1v15.2M243.8 27.9v2.6h-93.9v25.4M104.1 43.2h5.1M104.1 40.6h5.1M109.2 48.3v15.2h-94v-2.5M180.3 58.4v2.6h-30.4v2.5M162.6 61v2.5M175.3 61v2.5M246.4 71.1v96.5"/>
<path d="M246.4 66h-5.1v2.6M281.9 68.6v99M78.7 91.4v2.6h28v12.7M218.4 86.4v2.5h-66v43.2M15.2 109.2v2.6h91.5v10.1M96.5 111.8v20.3h10.2M101.6 111.8v2.5M218.4 116.8v2.6h-30.4M101.6 124.5v12.7M101.6 127h5.1M40.6 154.9v2.6h66.1v10.1M193 157.5v2.5"/>
<path d="M213.4 157.5v2.5h-5.1M198.1 160h-45.7v7.6"/>
</g>
<path d="M16.9 15.1h-1v1.9M18.6 15.2l-.3-.1h-.7v1.9M20.5 15.2a.69 .69 0 0 0-.9 .1M21.1 17l.6-1.9 .7 1.9M25.5 15.2l-.3-.1h-.7v1.9M34.4 15.1v1.9M40.4 15.1v1.6" fill="none" stroke="#0000c2" stroke-width=".38"/>
<g fill="#008400" stroke="#008400" stroke-width=".18">
<circle cx="109.2" cy="63.5" r=".46"/>
<circle cx="106.7" cy="101.6" r=".46"/>
<circle cx="96.5" cy="63.5" r=".46"/>
<circle cx="96.5" cy="94" r=".46"/>
<circle cx="83.8" cy="94" r=".46"/>
<circle cx="96.5" cy="111.8" r=".46"/>
<circle cx="106.7" cy="111.8" r=".46"/>
<circle cx="101.6" cy="111.8" r=".46"/>
<circle cx="106.7" cy="104.1" r=".46"/>
<circle cx="71.1" cy="63.5" r=".46"/>
<circle cx="83.8" cy="63.5" r=".46"/>
<circle cx="162.6" cy="88.9" r=".46"/>
<circle cx="152.4" cy="94" r=".46"/>
<circle cx="152.4" cy="91.4" r=".46"/>
<circle cx="152.4" cy="88.9" r=".46"/>
<circle cx="152.4" cy="106.7" r=".46"/>
<circle cx="152.4" cy="111.8" r=".46"/>
<circle cx="152.4" cy="109.2" r=".46"/>
<circle cx="152.4" cy="114.3" r=".46"/>
<circle cx="152.4" cy="101.6" r=".46"/>
<circle cx="152.4" cy="99.1" r=".46"/>
<circle cx="152.4" cy="104.1" r=".46"/>
<circle cx="152.4" cy="96.5" r=".46"/>
<circle cx="152.4" cy="121.9" r=".46"/>
<circle cx="152.4" cy="119.4" r=".46"/>
<circle cx="152.4" cy="124.5" r=".46"/>
<circle cx="152.4" cy="116.8" r=".46"/>
<circle cx="101.6" cy="134.6" r=".46"/>
<circle cx="106.7" cy="160" r=".46"/>
<circle cx="106.7" cy="157.5" r=".46"/>
<circle cx="152.4" cy="127" r=".46"/>
<circle cx="152.4" cy="129.5" r=".46"/>
<circle cx="152.4" cy="160" r=".46"/>
<circle cx="106.7" cy="162.6" r=".46"/>
<circle cx="106.7" cy="165.1" r=".46"/>
<circle cx="162.6" cy="160" r=".46"/>
<circle cx="152.4" cy="165.1" r=".46"/>
<circle cx="152.4" cy="162.6" r=".46"/>
<circle cx="58.4" cy="63.5" r=".46"/>
<circle cx="104.1" cy="33" r=".46"/>
<circle cx="109.2" cy="53.3" r=".46"/>
<circle cx="109.2" cy="50.8" r=".46"/>
<circle cx="104.1" cy="35.6" r=".46"/>
<circle cx="104.1" cy="38.1" r=".46"/>
<circle cx="104.1" cy="40.6" r=".46"/>
<circle cx="104.1" cy="43.2" r=".46"/>
<circle cx="109.2" cy="61" r=".46"/>
<circle cx="109.2" cy="58.4" r=".46"/>
<circle cx="109.2" cy="55.9" r=".46"/>
<circle cx="45.7" cy="63.5" r=".46"/>
<circle cx="106.7" cy="119.4" r=".46"/>
<circle cx="106.7" cy="114.3" r=".46"/>
<circle cx="106.7" cy="116.8" r=".46"/>
<circle cx="101.6" cy="127" r=".46"/>
<circle cx="96.5" cy="157.5" r=".46"/>
<circle cx="58.4" cy="157.5" r=".46"/>
<circle cx="45.7" cy="157.5" r=".46"/>
<circle cx="71.1" cy="157.5" r=".46"/>
<circle cx="83.8" cy="157.5" r=".46"/>
<circle cx="20.3" cy="111.8" r=".46"/>
<circle cx="33" cy="111.8" r=".46"/>
<circle cx="45.7" cy="111.8" r=".46"/>
<circle cx="58.4" cy="111.8" r=".46"/>
<circle cx="71.1" cy="111.8" r=".46"/>
<circle cx="83.8" cy="111.8" r=".46"/>
<circle cx="33" cy="63.5" r=".46"/>
<circle cx="20.3" cy="63.5" r=".46"/>
<circle cx="149.9" cy="43.2" r=".46"/>
<circle cx="149.9" cy="45.7" r=".46"/>
<circle cx="149.9" cy="53.3" r=".46"/>
<circle cx="149.9" cy="61" r=".46"/>
<circle cx="162.6" cy="61" r=".46"/>
<circle cx="149.9" cy="40.6" r=".46"/>
<circle cx="149.9" cy="50.8" r=".46"/>
<circle cx="149.9" cy="48.3" r=".46"/>
<circle cx="281.9" cy="114.3" r=".46"/>
<circle cx="281.9" cy="109.2" r=".46"/>
<circle cx="281.9" cy="111.8" r=".46"/>
<circle cx="281.9" cy="94" r=".46"/>
<circle cx="281.9" cy="99.1" r=".46"/>
<circle cx="281.9" cy="96.5" r=".46"/>
<circle cx="281.9" cy="129.5" r=".46"/>
<circle cx="281.9" cy="127" r=".46"/>
<circle cx="281.9" cy="106.7" r=".46"/>
<circle cx="281.9" cy="101.6" r=".46"/>
<circle cx="281.9" cy="104.1" r=".46"/>
<circle cx="281.9" cy="124.5" r=".46"/>
<circle cx="281.9" cy="121.9" r=".46"/>
<circle cx="281.9" cy="119.4" r=".46"/>
<circle cx="281.9" cy="116.8" r=".46"/>
<circle cx="246.4" cy="124.5" r=".46"/>
<circle cx="246.4" cy="111.8" r=".46"/>
<circle cx="246.4" cy="114.3" r=".46"/>
<circle cx="200.7" cy="119.4" r=".46"/>
<circle cx="213.4" cy="119.4" r=".46"/>
<circle cx="246.4" cy="78.7" r=".46"/>
<circle cx="246.4" cy="94" r=".46"/>
<circle cx="246.4" cy="96.5" r=".46"/>
<circle cx="246.4" cy="99.1" r=".46"/>
<circle cx="246.4" cy="106.7" r=".46"/>
<circle cx="200.7" cy="88.9" r=".46"/>
<circle cx="213.4" cy="88.9" r=".46"/>
<circle cx="182.9" cy="160" r=".46"/>
<circle cx="246.4" cy="160" r=".46"/>
<circle cx="246.4" cy="162.6" r=".46"/>
<circle cx="188" cy="160" r=".46"/>
<circle cx="246.4" cy="157.5" r=".46"/>
<circle cx="246.4" cy="154.9" r=".46"/>
<circle cx="175.3" cy="160" r=".46"/>
<circle cx="193" cy="160" r=".46"/>
<circle cx="246.4" cy="86.4" r=".46"/>
<circle cx="246.4" cy="88.9" r=".46"/>
<circle cx="246.4" cy="81.3" r=".46"/>
<circle cx="246.4" cy="83.8" r=".46"/>
<circle cx="246.4" cy="91.4" r=".46"/>
<circle cx="200.7" cy="30.5" r=".46"/>
<circle cx="213.4" cy="30.5" r=".46"/>
<circle cx="238.8" cy="30.5" r=".46"/>
<circle cx="226.1" cy="30.5" r=".46"/>
<circle cx="281.9" cy="132.1" r=".46"/>
<circle cx="281.9" cy="137.2" r=".46"/>
<circle cx="281.9" cy="134.6" r=".46"/>
<circle cx="281.9" cy="152.4" r=".46"/>
<circle cx="281.9" cy="147.3" r=".46"/>
<circle cx="281.9" cy="144.8" r=".46"/>
<circle cx="281.9" cy="149.9" r=".46"/>
<circle cx="281.9" cy="160" r=".46"/>
<circle cx="281.9" cy="157.5" r=".46"/>
<circle cx="281.9" cy="154.9" r=".46"/>
<circle cx="281.9" cy="142.2" r=".46"/>
<circle cx="281.9" cy="139.7" r=".46"/>
<circle cx="246.4" cy="144.8" r=".46"/>
<circle cx="246.4" cy="137.2" r=".46"/>
<circle cx="246.4" cy="139.7" r=".46"/>
<circle cx="246.4" cy="142.2" r=".46"/>
<circle cx="246.4" cy="147.3" r=".46"/>
<circle cx="246.4" cy="149.9" r=".46"/>
<circle cx="246.4" cy="152.4" r=".46"/>
<circle cx="246.4" cy="127" r=".46"/>
<circle cx="246.4" cy="116.8" r=".46"/>
<circle cx="246.4" cy="119.4" r=".46"/>
<circle cx="246.4" cy="121.9" r=".46"/>
<circle cx="246.4" cy="132.1" r=".46"/>
<circle cx="246.4" cy="129.5" r=".46"/>
<circle cx="246.4" cy="134.6" r=".46"/>
<circle cx="246.4" cy="109.2" r=".46"/>
<circle cx="246.4" cy="104.1" r=".46"/>
<circle cx="246.4" cy="101.6" r=".46"/>
<circle cx="281.9" cy="86.4" r=".46"/>
<circle cx="281.9" cy="83.8" r=".46"/>
<circle cx="281.9" cy="81.3" r=".46"/>
<circle cx="281.9" cy="76.2" r=".46"/>
<circle cx="281.9" cy="78.7" r=".46"/>
<circle cx="243.8" cy="66" r=".46"/>
<circle cx="281.9" cy="91.4" r=".46"/>
<circle cx="281.9" cy="88.9" r=".46"/>
<circle cx="281.9" cy="73.7" r=".46"/>
<circle cx="281.9" cy="71.1" r=".46"/>
<circle cx="246.4" cy="73.7" r=".46"/>
<circle cx="246.4" cy="76.2" r=".46"/>
<circle cx="281.9" cy="162.6" r=".46"/>
<circle cx="175.3" cy="30.5" r=".46"/>
<circle cx="162.6" cy="30.5" r=".46"/>
<circle cx="188" cy="88.9" r=".46"/>
<circle cx="188" cy="30.5" r=".46"/>
<circle cx="175.3" cy="61" r=".46"/>
<circle cx="175.3" cy="88.9" r=".46"/>
</g>
<use href="#words"/>
</svg>
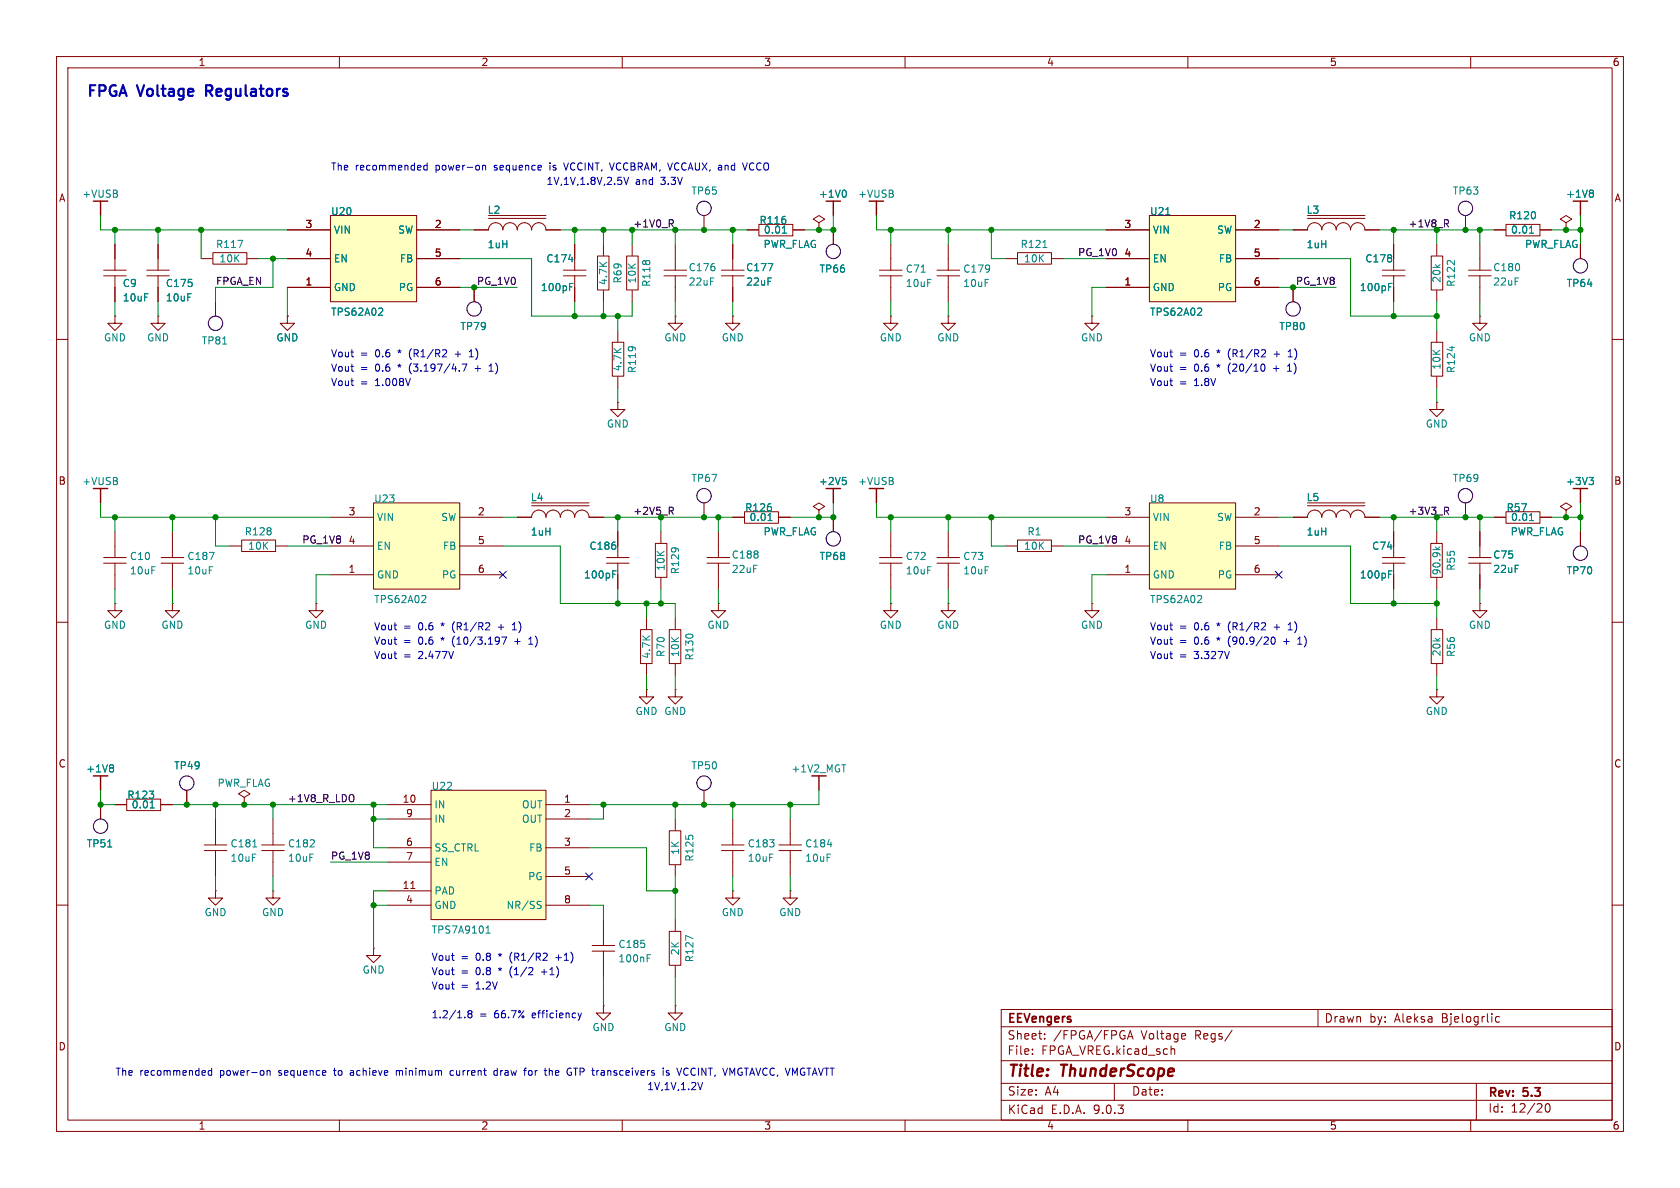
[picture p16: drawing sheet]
<svg xmlns="http://www.w3.org/2000/svg" width="297mm" height="210mm" viewBox="0 0 297 210" stroke-linecap="round" stroke-linejoin="round" font-family="sans-serif">
<defs><g id="words">
<g font-size="2.8" fill="#840000">
<text x="178" y="190.9">Title:</text>
<text x="187.7" y="190.9">ThunderScope</text>
</g>
<g font-size="2.7" fill="#0000c2">
<text x="15.2" y="18">FPGA</text>
<text x="24.5" y="18">Voltage</text>
<text x="37.3" y="18">Regulators</text>
</g>
<g font-size="2.1" fill="#840000">
<text x="178" y="184">Sheet:</text>
<text x="178" y="181.2">EEVengers</text>
<text x="186.2" y="184">/FPGA/FPGA</text>
<text x="201.8" y="184">Voltage</text>
<text x="211.4" y="184">Regs/</text>
<text x="234.1" y="181">Drawn</text>
<text x="242.1" y="181">by:</text>
<text x="246.6" y="181">Aleksa</text>
<text x="255" y="181">Bjelogrlic</text>
<text x="178" y="186.7">File:</text>
<text x="184.1" y="186.7">FPGA_VREG.kicad_sch</text>
<text x="178.1" y="197.1">KiCad</text>
<text x="178.1" y="193.9">Size:</text>
<text x="184.7" y="193.9">A4</text>
<text x="185.8" y="197.1">E.D.A.</text>
<text x="193.4" y="197.1">9.0.3</text>
<text x="200" y="193.9">Date:</text>
<text x="263" y="194.3">Rev:</text>
<text x="263" y="196.9">Id:</text>
<text x="267.1" y="196.9">12/20</text>
<text x="269.4" y="194.3">5.3</text>
</g>
<g font-size="1.8" fill="#840000">
<text x="35" y="11.9">1</text>
<text x="85" y="11.9">2</text>
<text x="135" y="11.9">3</text>
<text x="185" y="11.9">4</text>
<text x="235" y="11.9">5</text>
<text x="285" y="11.9">6</text>
<text x="10.3" y="35.9">A</text>
<text x="285.3" y="35.9">A</text>
<text x="53.9" y="40.4">3</text>
<text x="76.8" y="40.4">2</text>
<text x="198.7" y="40.4">3</text>
<text x="221.5" y="40.4">2</text>
<text x="53.9" y="45.5">4</text>
<text x="76.8" y="45.5">5</text>
<text x="198.7" y="45.5">4</text>
<text x="221.5" y="45.5">5</text>
<text x="53.9" y="50.5">1</text>
<text x="76.8" y="50.5">6</text>
<text x="198.7" y="50.5">1</text>
<text x="221.5" y="50.5">6</text>
<text x="10.3" y="85.9">B</text>
<text x="285.3" y="85.9">B</text>
<text x="61.5" y="91.2">3</text>
<text x="84.4" y="91.2">2</text>
<text x="198.7" y="91.2">3</text>
<text x="221.5" y="91.2">2</text>
<text x="61.5" y="96.3">4</text>
<text x="61.5" y="101.3">1</text>
<text x="84.4" y="96.3">5</text>
<text x="84.4" y="101.3">6</text>
<text x="198.7" y="96.3">4</text>
<text x="198.7" y="101.3">1</text>
<text x="221.5" y="96.3">5</text>
<text x="221.5" y="101.3">6</text>
<text x="10.3" y="135.9">C</text>
<text x="285.3" y="135.9">C</text>
<text x="71.1" y="142">10</text>
<text x="99.6" y="142">1</text>
<text x="71.7" y="144.5">9</text>
<text x="71.7" y="149.6">6</text>
<text x="99.6" y="144.5">2</text>
<text x="99.6" y="149.6">3</text>
<text x="71.7" y="152.1">7</text>
<text x="99.6" y="154.7">5</text>
<text x="71.1" y="157.2">11</text>
<text x="71.7" y="159.8">4</text>
<text x="99.6" y="159.8">8</text>
<text x="10.3" y="185.9">D</text>
<text x="285.3" y="185.9">D</text>
<text x="35" y="199.9">1</text>
<text x="85" y="199.9">2</text>
<text x="135" y="199.9">3</text>
<text x="185" y="199.9">4</text>
<text x="235" y="199.9">5</text>
<text x="285" y="199.9">6</text>
</g>
<g font-size="1.8" fill="#008484">
<text x="14.4" y="35.2">+VUSB</text>
<text x="122.1" y="34.6">TP65</text>
<text x="144.7" y="35.2">+1V0</text>
<text x="151.6" y="35.2">+VUSB</text>
<text x="256.8" y="34.6">TP63</text>
<text x="276.8" y="35.2">+1V8</text>
<text x="58.4" y="38.2">U20</text>
<text x="58.9" y="41.5">VIN</text>
<text x="70.3" y="41.5">SW</text>
<text x="86.1" y="38">L2</text>
<text x="134.2" y="39.8">R116</text>
<text x="134.9" y="41.5">0.01</text>
<text x="203.2" y="38.2">U21</text>
<text x="203.7" y="41.5">VIN</text>
<text x="215.1" y="41.5">SW</text>
<text x="230.9" y="38">L3</text>
<text x="266.7" y="39">R120</text>
<text x="267" y="41.5">0.01</text>
<text x="38.1" y="44">R117</text>
<text x="38.7" y="46.6">10K</text>
<text x="58.9" y="46.6">EN</text>
<text x="70.6" y="46.6">FB</text>
<text x="86.1" y="44.1">1uH</text>
<text x="96.5" y="46.6">C174</text>
<text x="134.9" y="44">PWR_FLAG</text>
<text x="180.3" y="44">R121</text>
<text x="180.9" y="46.6">10K</text>
<text x="203.7" y="46.6">EN</text>
<text x="215.4" y="46.6">FB</text>
<text x="230.9" y="44.1">1uH</text>
<text x="241.3" y="46.6">C178</text>
<text x="269.5" y="44">PWR_FLAG</text>
<text x="21.6" y="50.9">C9</text>
<text x="21.6" y="53.5">10uF</text>
<text x="29.2" y="50.9">C175</text>
<text x="29.2" y="53.5">10uF</text>
<text x="58.9" y="51.7">GND</text>
<text x="70.4" y="51.7">PG</text>
<text x="95.5" y="51.7">100pF</text>
<text x="107.5" y="50.5" transform="rotate(-90 107.5 50.5)">4.7K</text>
<text x="110.1" y="50.2" transform="rotate(-90 110.1 50.2)">R69</text>
<text x="112.6" y="50.2" transform="rotate(-90 112.6 50.2)">10K</text>
<text x="115.2" y="50.8" transform="rotate(-90 115.2 50.8)">R118</text>
<text x="121.6" y="48.1">C176</text>
<text x="121.6" y="50.7">22uF</text>
<text x="131.8" y="48.1">C177</text>
<text x="131.8" y="50.7">22uF</text>
<text x="144.8" y="48.4">TP66</text>
<text x="160" y="48.4">C71</text>
<text x="160" y="50.9">10uF</text>
<text x="170.2" y="48.4">C179</text>
<text x="170.2" y="50.9">10uF</text>
<text x="203.7" y="51.7">GND</text>
<text x="215.2" y="51.7">PG</text>
<text x="240.3" y="51.7">100pF</text>
<text x="254.9" y="50.1" transform="rotate(-90 254.9 50.1)">20k</text>
<text x="257.4" y="50.8" transform="rotate(-90 257.4 50.8)">R122</text>
<text x="263.9" y="48.1">C180</text>
<text x="263.9" y="50.7">22uF</text>
<text x="276.9" y="50.9">TP64</text>
<text x="58.4" y="56">TPS62A02</text>
<text x="81.3" y="58.6">TP79</text>
<text x="203.2" y="56">TPS62A02</text>
<text x="226.1" y="58.6">TP80</text>
<text x="18.3" y="60.6">GND</text>
<text x="25.9" y="60.6">GND</text>
<text x="35.6" y="61.1">TP81</text>
<text x="48.8" y="60.6">GND</text>
<text x="110.1" y="65.7" transform="rotate(-90 110.1 65.7)">4.7K</text>
<text x="117.3" y="60.6">GND</text>
<text x="127.5" y="60.6">GND</text>
<text x="155.4" y="60.6">GND</text>
<text x="165.6" y="60.6">GND</text>
<text x="191" y="60.6">GND</text>
<text x="254.9" y="65.4" transform="rotate(-90 254.9 65.4)">10K</text>
<text x="259.6" y="60.6">GND</text>
<text x="112.6" y="66.1" transform="rotate(-90 112.6 66.1)">R119</text>
<text x="257.4" y="66.1" transform="rotate(-90 257.4 66.1)">R124</text>
<text x="107.2" y="75.8">GND</text>
<text x="252" y="75.8">GND</text>
<text x="14.4" y="86">+VUSB</text>
<text x="66" y="89">U23</text>
<text x="93.7" y="88.8">L4</text>
<text x="122.1" y="85.4">TP67</text>
<text x="144.7" y="86">+2V5</text>
<text x="151.6" y="86">+VUSB</text>
<text x="203.2" y="89">U8</text>
<text x="230.9" y="88.8">L5</text>
<text x="256.8" y="85.4">TP69</text>
<text x="276.8" y="86">+3V3</text>
<text x="43.2" y="94.8">R128</text>
<text x="66.5" y="92.3">VIN</text>
<text x="77.9" y="92.3">SW</text>
<text x="93.7" y="94.9">1uH</text>
<text x="131.6" y="90.6">R126</text>
<text x="132.4" y="92.3">0.01</text>
<text x="134.9" y="94.8">PWR_FLAG</text>
<text x="181.5" y="94.8">R1</text>
<text x="203.7" y="92.3">VIN</text>
<text x="215.1" y="92.3">SW</text>
<text x="230.9" y="94.9">1uH</text>
<text x="266.2" y="90.6">R57</text>
<text x="267" y="94.8">PWR_FLAG</text>
<text x="267" y="92.3">0.01</text>
<text x="22.9" y="99.2">C10</text>
<text x="22.9" y="101.7">10uF</text>
<text x="33" y="99.2">C187</text>
<text x="33" y="101.7">10uF</text>
<text x="43.8" y="97.4">10K</text>
<text x="66.5" y="97.4">EN</text>
<text x="78.2" y="97.4">FB</text>
<text x="104.1" y="97.4">C186</text>
<text x="117.7" y="101" transform="rotate(-90 117.7 101)">10K</text>
<text x="120.2" y="101.6" transform="rotate(-90 120.2 101.6)">R129</text>
<text x="129.3" y="98.9">C188</text>
<text x="129.3" y="101.5">22uF</text>
<text x="144.8" y="99.2">TP68</text>
<text x="160" y="99.2">C72</text>
<text x="160" y="101.7">10uF</text>
<text x="170.2" y="99.2">C73</text>
<text x="170.2" y="101.7">10uF</text>
<text x="180.9" y="97.4">10K</text>
<text x="203.7" y="97.4">EN</text>
<text x="215.4" y="97.4">FB</text>
<text x="242.5" y="97.4">C74</text>
<text x="254.9" y="101.8" transform="rotate(-90 254.9 101.8)">90.9k</text>
<text x="257.4" y="101" transform="rotate(-90 257.4 101)">R55</text>
<text x="263.9" y="98.9">C75</text>
<text x="263.9" y="101.5">22uF</text>
<text x="276.9" y="101.7">TP70</text>
<text x="66" y="106.8">TPS62A02</text>
<text x="66.5" y="102.5">GND</text>
<text x="78" y="102.5">PG</text>
<text x="103.1" y="102.5">100pF</text>
<text x="203.2" y="106.8">TPS62A02</text>
<text x="203.7" y="102.5">GND</text>
<text x="215.2" y="102.5">PG</text>
<text x="240.3" y="102.5">100pF</text>
<text x="18.3" y="111.4">GND</text>
<text x="28.4" y="111.4">GND</text>
<text x="53.8" y="111.4">GND</text>
<text x="125" y="111.4">GND</text>
<text x="155.4" y="111.4">GND</text>
<text x="165.6" y="111.4">GND</text>
<text x="191" y="111.4">GND</text>
<text x="259.6" y="111.4">GND</text>
<text x="115.2" y="116.5" transform="rotate(-90 115.2 116.5)">4.7K</text>
<text x="117.7" y="116.2" transform="rotate(-90 117.7 116.2)">R70</text>
<text x="120.2" y="116.2" transform="rotate(-90 120.2 116.2)">10K</text>
<text x="122.8" y="116.9" transform="rotate(-90 122.8 116.9)">R130</text>
<text x="254.9" y="116.1" transform="rotate(-90 254.9 116.1)">20k</text>
<text x="257.4" y="116.2" transform="rotate(-90 257.4 116.2)">R56</text>
<text x="112.3" y="126.6">GND GND</text>
<text x="252" y="126.6">GND</text>
<text x="15.1" y="136.8">+1V8</text>
<text x="30.7" y="136.2">TP49</text>
<text x="122.1" y="136.2">TP50</text>
<text x="139.8" y="136.8">+1V2_MGT</text>
<text x="22.4" y="141.4">R123</text>
<text x="23.2" y="143.1">0.01</text>
<text x="38.4" y="139.3">PWR_FLAG</text>
<text x="76.2" y="139.8">U22</text>
<text x="76.7" y="143.1">IN</text>
<text x="92.2" y="143.1">OUT</text>
<text x="15.2" y="150">TP51</text>
<text x="40.6" y="150">C181</text>
<text x="50.8" y="150">C182</text>
<text x="76.7" y="145.6">IN</text>
<text x="92.2" y="145.6">OUT</text>
<text x="132.1" y="150">C183</text>
<text x="142.2" y="150">C184</text>
<text x="40.6" y="152.5">10uF</text>
<text x="50.8" y="152.5">10uF</text>
<text x="76.7" y="150.7">SS_CTRL</text>
<text x="76.7" y="153.3">EN</text>
<text x="93.3" y="155.8">PG</text>
<text x="93.5" y="150.7">FB</text>
<text x="120.2" y="151.2" transform="rotate(-90 120.2 151.2)">1K</text>
<text x="122.8" y="152.4" transform="rotate(-90 122.8 152.4)">R125</text>
<text x="132.1" y="152.5">10uF</text>
<text x="142.2" y="152.5">10uF</text>
<text x="76.7" y="158.3">PAD</text>
<text x="76.7" y="160.9">GND</text>
<text x="89.5" y="160.9">NR/SS</text>
<text x="36.1" y="162.2">GND</text>
<text x="46.2" y="162.2">GND</text>
<text x="76.2" y="165.2">TPS7A9101</text>
<text x="109.2" y="167.8">C185</text>
<text x="127.5" y="162.2">GND</text>
<text x="137.7" y="162.2">GND</text>
<text x="64" y="172.3">GND</text>
<text x="109.2" y="170.3">100nF</text>
<text x="120.2" y="169" transform="rotate(-90 120.2 169)">2K</text>
<text x="122.8" y="170.2" transform="rotate(-90 122.8 170.2)">R127</text>
<text x="104.6" y="182.5">GND</text>
<text x="117.3" y="182.5">GND</text>
</g>
<g font-size="1.8" fill="#0000c2">
<text x="58.4" y="30.2">The</text>
<text x="62.8" y="30.2">recommended</text>
<text x="77.1" y="30.2">power-on</text>
<text x="87.6" y="30.2">sequence</text>
<text x="96.5" y="32.8">1V,1V,1.8V,2.5V</text>
<text x="97.6" y="30.2">is</text>
<text x="100.4" y="30.2">VCCINT, VCCBRAM, VCCAUX, and</text>
<text x="112.3" y="32.8">and</text>
<text x="116.9" y="32.8">3.3V</text>
<text x="132.9" y="30.2">VCCO</text>
<text x="58.4" y="63.3">Vout</text>
<text x="58.4" y="65.8">Vout</text>
<text x="63.7" y="63.3">=</text>
<text x="63.7" y="65.8">=</text>
<text x="66.4" y="63.3">0.6</text>
<text x="66.4" y="65.8">0.6</text>
<text x="70.6" y="63.3">*</text>
<text x="70.6" y="65.8">*</text>
<text x="72.8" y="63.3">(R1/R2</text>
<text x="72.8" y="65.8">(3.197/4.7</text>
<text x="81.1" y="63.3">+</text>
<text x="83.8" y="63.3">1)</text>
<text x="84.6" y="65.8">+</text>
<text x="87.3" y="65.8">1)</text>
<text x="203.2" y="65.8">Vout</text>
<text x="203.2" y="63.3">Vout</text>
<text x="208.5" y="65.8">=</text>
<text x="208.5" y="63.3">=</text>
<text x="211.2" y="65.8">0.6</text>
<text x="211.2" y="63.3">0.6</text>
<text x="215.4" y="65.8">*</text>
<text x="215.4" y="63.3">*</text>
<text x="217.6" y="65.8">(20/10</text>
<text x="217.6" y="63.3">(R1/R2</text>
<text x="225.7" y="65.8">+</text>
<text x="225.9" y="63.3">+</text>
<text x="228.5" y="65.8">1)</text>
<text x="228.6" y="63.3">1)</text>
<text x="58.4" y="68.3">Vout</text>
<text x="63.7" y="68.3">=</text>
<text x="66.4" y="68.3">1.008V</text>
<text x="203.2" y="68.3">Vout</text>
<text x="208.5" y="68.3">=</text>
<text x="211.2" y="68.3">1.8V</text>
<text x="66" y="111.5">Vout</text>
<text x="71.3" y="111.5">=</text>
<text x="74.1" y="111.5">0.6</text>
<text x="78.3" y="111.5">*</text>
<text x="80.4" y="111.5">(R1/R2</text>
<text x="88.7" y="111.5">+</text>
<text x="91.4" y="111.5">1)</text>
<text x="203.2" y="111.5">Vout</text>
<text x="208.5" y="111.5">=</text>
<text x="211.2" y="111.5">0.6</text>
<text x="215.4" y="111.5">*</text>
<text x="217.6" y="111.5">(R1/R2</text>
<text x="225.9" y="111.5">+</text>
<text x="228.6" y="111.5">1)</text>
<text x="66" y="114.1">Vout</text>
<text x="66" y="116.6">Vout</text>
<text x="71.3" y="114.1">=</text>
<text x="71.3" y="116.6">=</text>
<text x="74.1" y="114.1">0.6</text>
<text x="74.1" y="116.6">2.477V</text>
<text x="78.3" y="114.1">*</text>
<text x="80.4" y="114.1">(10/3.197</text>
<text x="91.6" y="114.1">+</text>
<text x="94.4" y="114.1">1)</text>
<text x="203.2" y="116.6">Vout</text>
<text x="203.2" y="114.1">Vout</text>
<text x="208.5" y="116.6">=</text>
<text x="208.5" y="114.1">=</text>
<text x="211.2" y="116.6">3.327V</text>
<text x="211.2" y="114.1">0.6</text>
<text x="215.4" y="114.1">*</text>
<text x="217.6" y="114.1">(90.9/20</text>
<text x="227.6" y="114.1">+</text>
<text x="230.3" y="114.1">1)</text>
<text x="76.2" y="172.5">Vout</text>
<text x="76.2" y="169.9">Vout</text>
<text x="81.5" y="172.5">=</text>
<text x="81.5" y="169.9">=</text>
<text x="84.2" y="172.5">0.8</text>
<text x="84.2" y="169.9">0.8</text>
<text x="88.4" y="172.5">*</text>
<text x="88.4" y="169.9">*</text>
<text x="90.6" y="172.5">(1/2</text>
<text x="90.6" y="169.9">(R1/R2</text>
<text x="96.3" y="172.5">+1)</text>
<text x="98.9" y="169.9">+1)</text>
<text x="76.2" y="175">Vout</text>
<text x="81.5" y="175">=</text>
<text x="84.2" y="175">1.2V</text>
<text x="76.2" y="180.1">1.2/1.8</text>
<text x="84.8" y="180.1">=</text>
<text x="87.5" y="180.1">66.7%</text>
<text x="94.4" y="180.1">efficiency</text>
<text x="20.3" y="190.3">The</text>
<text x="24.7" y="190.3">recommended</text>
<text x="39" y="190.3">power-on</text>
<text x="49.5" y="190.3">sequence</text>
<text x="59.5" y="190.3">to</text>
<text x="62.6" y="190.3">achieve</text>
<text x="70.9" y="190.3">minimum</text>
<text x="80.6" y="190.3">current</text>
<text x="88.6" y="190.3">draw</text>
<text x="94.2" y="190.3">for</text>
<text x="98" y="190.3">the</text>
<text x="102.1" y="190.3">GTP transceivers</text>
<text x="119.5" y="190.3">is</text>
<text x="122.3" y="190.3">VCCINT, VMGTAVCC, VMGTAVTT</text>
<text x="114.3" y="192.8">1V,1V,1.2V</text>
</g>
<g font-size="1.8">
<text x="111.9" y="40.3">+1V0_R</text>
<text x="190.5" y="45.4">PG_1V0</text>
<text x="38.1" y="50.5">FPGA_EN</text>
<text x="84.2" y="50.5">PG_1V0</text>
<text x="229" y="50.5">PG_1V8</text>
<text x="53.3" y="96.2">PG_1V8</text>
<text x="190.5" y="96.2">PG_1V8</text>
<text x="50.8" y="141.9">+1V8_R_LDO</text>
<text x="58.4" y="152.1">PG_1V8</text>
</g>
<g font-size="1.8" fill="#008400">
<text x="248.9" y="40.3">+1V8_R</text>
<text x="111.9" y="91.1">+2V5_R</text>
<text x="248.9" y="91.1">+3V3_R</text>
</g>
</g></defs>
<path d="M0 0h297v210h-297z" fill="#fff" stroke="#fff" stroke-width=".18"/>
<g fill="none" stroke="#840000" stroke-width=".18">
<path d="M10 10h277v190h-277zM12 12h273v186h-273zM60 10v2M110 10v2M160 10v2M210 10v2M260 10v2M134.2 39.7h6v2h-6zM18.3 47.8h4M18.3 48.8h4M20.3 55.9v1.3h1.3l-1.3 1.2-1.3-1.2h1.3M20.3 55.9h.1"/>
<path d="M20.3 43.2v4.6M20.3 48.8v4.5M25.9 47.8h4M25.9 48.8h4M27.9 55.9v1.3h1.3l-1.3 1.2-1.2-1.2h1.2M27.9 55.9h.1M27.9 43.2v4.6M27.9 48.8v4.5M35.6 45.7h2M37.6 44.7h6v2h-6zM38.1 53.3v2.6M43.7 45.7h2"/>
<path d="M50.8 55.9v1.3h1.3l-1.3 1.2-1.3-1.2h1.3M50.8 55.9h.1M109.2 58.4v2M110.8 45.3h2v6h-2zM111.8 43.2v2M111.8 51.3v2M117.4 47.8h4M117.4 48.8h4M119.4 55.9v1.3h1.2l-1.2 1.2-1.3-1.2h1.3M119.4 55.9h.1M119.4 43.2v4.6M119.4 48.8v4.5"/>
<path d="M129.5 55.9v1.3h1.3l-1.3 1.2-1.2-1.2h1.2M129.5 55.9h.1M132.1 40.6h2M140.2 40.6h2M155.5 47.8h4M155.5 48.8h4M157.5 55.9v1.3h1.2l-1.2 1.2-1.3-1.2h1.3M157.5 55.9h.1M157.5 43.2v4.6M157.5 48.8v4.5M177.8 45.7h2M179.9 44.7h6v2h-6z"/>
<path d="M186 45.7h2M254 58.4v2M10 60h2M108.2 60.5h2.1v6h-2.1zM109.2 66.6v2M253 60.5h2.1v6h-2.1zM254 71.1v1.3h1.3l-1.3 1.3-1.3-1.3h1.3M254 71.1h.1M254 66.6v2M285 60h2M259.1 88.9v2.5M279.4 94v2.5"/>
<path d="M10 110h2M127 106.7v1.3h1.3l-1.3 1.2-1.3-1.2h1.3M127 106.7h.1M193 106.7v1.3h1.3l-1.3 1.2-1.2-1.2h1.2M193 106.7h.1M285 110h2M114.3 121.9v1.3h1.3l-1.3 1.3-1.3-1.3h1.3M114.3 121.9h.1M10 160h2M177 178.5h108v19.5h-108zM233 178.5v3M265.1 179.8l-.4-.1-.3 .3v.4l.1 .2h.6"/>
<path d="M285 160h2M60 198v2M110 198v2M160 198v2M177 194.5h108M177 191.5h108M177 187.5h108M177 181.5h108M182.5 186.3v.1M182.5 185.5v.1M184.7 183.6v.1M184.7 182.8v.1"/>
<path d="M197 191.5v3M199.3 183.7l.5-1.5 .5 1.5M199.5 183.3h.7M207.2 185.4h.3l.2 .2v.8M209.5 182.8l.1 .3-.7 .1M210 198v2M217.8 182.1l-1.3 2M260 198v2M261 191.5v6.5M273.3 195.2l.2-.1a.81 .81 0 0 1 .6 .6 .81 .81 0 0 1-.3 .8l-.1 .1a.81 .81 0 0 1-.4-1.4z"/>
</g>
<path d="M138.7 39.9v1.3M42.1 42.5h.8l-.5 1.3M138.3 41.2h.7M162.9 48.1h.7M184.4 43.8h.7M39.4 60.8h.7M256.7 61.2v.8M280.9 84.4h.8l-.4 .5M281.5 84.9l.2 .2v.3l-.2 .3" fill="none" stroke="#008484" stroke-width=".18"/>
<path d="M17.8 35.6v2.5M279.4 86.4v2.5" fill="none" stroke="#840000" stroke-width=".25"/>
<g fill="none" stroke="#000" stroke-width=".18">
<circle cx="38.1" cy="57.1" r="1.27"/>
<circle cx="259.1" cy="87.6" r="1.27"/>
<circle cx="279.4" cy="97.8" r="1.27"/>
</g>
<path d="M58.4 38.1h15.3v15.2h-15.3z" fill="#ffffc2"/>
<path d="M58.4 38.1h15.3v15.2h-15.3z" fill="none" stroke="#800000" stroke-width=".18"/>
<path d="M50.8 40.6h7.6M50.8 45.7h7.6M50.8 50.8h7.6M73.7 40.6h7.6M73.7 45.7h7.6M73.7 50.8h7.6M83.8 50.8v2.5M99.6 47.8h4M99.6 48.8h4M101.6 43.2v4.6M101.6 48.8v4.5" fill="none" stroke="#840000" stroke-width=".18"/>
<path d="M67.4 54.5l.3 .2-.1 .3-.7 .7h.8M100.5 45.9h.8M100.7 50.7h.4M100.7 50.1h.6" fill="none" stroke="#008484" stroke-width=".18"/>
<circle cx="83.8" cy="54.6" r="1.27" fill="none" stroke="#000" stroke-width=".18"/>
<path d="M203.2 88.9h15.2v15.2h-15.2z" fill="#ffffc2"/>
<path d="M203.2 88.9h15.2v15.2h-15.2z" fill="none" stroke="#800000" stroke-width=".18"/>
<g fill="none" stroke="#840000" stroke-width=".18">
<path d="M228.6 50.8v2.5M129.5 91.4h2M131.6 90.5h6v2h-6zM137.7 91.4h2M144.8 90.2l1-.7-1-.6-1 .6 1 .7v1.2M144.8 91.4h.1M147.3 91.4v2.6M155.5 98.6h4M155.5 99.6h4M157.5 94v4.6M157.5 99.6v4.5M165.6 98.6h4"/>
<path d="M165.6 99.6h4M167.6 94v4.6M167.6 99.6v4.5M195.6 91.4h7.6M195.6 96.5h7.6M218.4 91.4h7.7M218.4 96.5h7.7M195.6 101.6h7.6M218.4 101.6h7.7"/>
</g>
<path d="M135.8 92h.7M136.1 90.7v1.3M212.2 105.3l.2 .2v.3l-.7 .7h.7M148.8 135.2h.7" fill="none" stroke="#008484" stroke-width=".18"/>
<g fill="none" stroke="#000" stroke-width=".18">
<circle cx="228.6" cy="54.6" r="1.27"/>
<circle cx="147.3" cy="95.2" r="1.27"/>
</g>
<path d="M144.8 137.2v2.5" fill="none" stroke="#840000" stroke-width=".25"/>
<path d="M66 88.9h15.3v15.2h-15.3z" fill="#ffffc2"/>
<path d="M66 88.9h15.3v15.2h-15.3z" fill="none" stroke="#800000" stroke-width=".18"/>
<g fill="none" stroke="#840000" stroke-width=".18">
<path d="M86.4 38.1h10.1M86.4 38.6h10.1M124.5 38.1v2.5M83.8 40.6h2.6a1.27 1.27 0 0 1 1.2-1.2 1.27 1.27 0 0 1 1.3 1.2 1.27 1.27 0 0 1 1.3-1.2 1.27 1.27 0 0 1 1.2 1.2 1.27 1.27 0 0 1 1.3-1.2 1.27 1.27 0 0 1 1.3 1.2 1.27 1.27 0 0 1 1.2-1.2 1.27 1.27 0 0 1 1.3 1.2h2.6M165.6 47.8h4M165.6 48.8h4M167.6 55.9v1.3h1.3l-1.3 1.2-1.2-1.2h1.2M167.6 55.9h.1M167.6 43.2v4.6M167.6 48.8v4.5M193 55.9v1.3h1.3l-1.3 1.2-1.2-1.2h1.2M193 55.9h.1"/>
<path d="M261.6 55.9v1.3h1.3l-1.3 1.2-1.3-1.2h1.3M261.6 55.9h.1M109.2 71.1v1.3h1.3l-1.3 1.3-1.3-1.3h1.3M109.2 71.1h.1M18.3 98.6h4M18.3 99.6h4M20.3 94v4.6M20.3 99.6v4.5M28.5 98.6h4M28.5 99.6h4M30.5 94v4.6M30.5 99.6v4.5"/>
<path d="M40.6 96.5h2M42.7 95.5h6v2h-6zM48.8 96.5h2M58.4 91.4h7.6M58.4 96.5h7.6M81.3 91.4h7.6M81.3 96.5h7.6M91.4 91.4h2.6a1.27 1.27 0 0 1 1.2-1.2 1.27 1.27 0 0 1 1.3 1.2 1.27 1.27 0 0 1 1.3-1.2 1.27 1.27 0 0 1 1.3 1.2 1.27 1.27 0 0 1 1.2-1.2 1.27 1.27 0 0 1 1.3 1.2 1.27 1.27 0 0 1 1.3-1.2 1.27 1.27 0 0 1 1.2 1.2h2.6M94 88.9h10.1M94 89.4h10.1M107.2 98.6h4M107.2 99.6h4"/>
<path d="M109.2 94v4.6M109.2 99.6v4.5M115.9 96.1h2v6h-2zM116.8 94v2M124.5 88.9v2.5M125 98.6h4M125 99.6h4M127 94v4.6M127 99.6v4.5M228.6 91.4h2.5a1.27 1.27 0 0 1 1.3-1.2 1.27 1.27 0 0 1 1.3 1.2 1.27 1.27 0 0 1 1.2-1.2 1.27 1.27 0 0 1 1.3 1.2 1.27 1.27 0 0 1 1.3-1.2 1.27 1.27 0 0 1 1.3 1.2 1.27 1.27 0 0 1 1.2-1.2 1.27 1.27 0 0 1 1.3 1.2h2.5M231.1 88.9h10.2M231.1 89.4h10.2"/>
<path d="M244.4 98.6h4M244.4 99.6h4M246.4 94v4.6M246.4 99.6v4.5M276.9 90.2l1-.7-1-.6-1.1 .6 1.1 .7v1.2M276.9 91.4h.1M58.4 101.6h7.6M81.3 101.6h7.6M116.8 102.1v2M157.5 106.7v1.3h1.2l-1.2 1.2-1.3-1.2h1.3M157.5 106.7h.1M167.6 106.7v1.3h1.3l-1.3 1.2-1.2-1.2h1.2"/>
<path d="M167.6 106.7h.1M253 111.3h2.1v6h-2.1zM254 109.2v2M254 117.4v2M33 139.7v2.5M254 121.9v1.3h1.3l-1.3 1.3-1.3-1.3h1.3M254 121.9h.1M17.8 142.2v2.6"/>
</g>
<path d="M37 97.6h.8l-.5 1.3M149 84.4h.6M149.4 84.9l.2 .2v.3l-.2 .3M75 105.3l.3 .2-.1 .3-.7 .7h.8M108.3 101.5h.4M108.3 100.9h.6M245.5 101.5h.4M245.5 100.9h.6M19.8 135.2l.3 .2-.3 .3 .3 .3v.2l-.3 .3M19 149.7h.8" fill="none" stroke="#008484" stroke-width=".18"/>
<path d="M17.8 86.4v2.5M147.3 86.4v2.5M17.8 137.2v2.5" fill="none" stroke="#840000" stroke-width=".25"/>
<g fill="none" stroke="#000" stroke-width=".18">
<circle cx="124.5" cy="36.8" r="1.27"/>
<circle cx="124.5" cy="87.6" r="1.27"/>
<circle cx="33" cy="138.4" r="1.27"/>
<circle cx="17.8" cy="146" r="1.27"/>
</g>
<path d="M203.2 38.1h15.2v15.2h-15.2z" fill="#ffffc2"/>
<path d="M203.2 38.1h15.2v15.2h-15.2z" fill="none" stroke="#800000" stroke-width=".18"/>
<g fill="none" stroke="#840000" stroke-width=".18">
<path d="M144.8 39.4l1-.7-1-.6-1 .6 1 .7v1.2M231.1 38.1h10.2M231.1 38.6h10.2M259.1 38.1v2.5M266.2 39.7h6v2h-6zM276.9 39.4l1-.7-1-.6-1.1 .6 1.1 .7v1.2M105.6 45.3h2.1v6h-2.1zM106.7 43.2v2M106.7 51.3v2M127.5 47.8h4M127.5 48.8h4M129.5 43.2v4.6"/>
<path d="M129.5 48.8v4.5M144.8 40.6h.1M147.3 40.6v2.6M195.6 40.6h7.6M195.6 45.7h7.6M195.6 50.8h7.6M218.4 40.6h7.7M218.4 45.7h7.7M218.4 50.8h7.7M228.6 40.6h2.5a1.27 1.27 0 0 1 1.3-1.2 1.27 1.27 0 0 1 1.3 1.2 1.27 1.27 0 0 1 1.2-1.2 1.27 1.27 0 0 1 1.3 1.2 1.27 1.27 0 0 1 1.3-1.2 1.27 1.27 0 0 1 1.3 1.2 1.27 1.27 0 0 1 1.2-1.2 1.27 1.27 0 0 1 1.3 1.2h2.5M244.4 47.8h4M244.4 48.8h4"/>
<path d="M246.4 43.2v4.6M246.4 48.8v4.5M253 45.3h2.1v6h-2.1zM254 43.2v2M254 51.3v2M259.6 47.8h4M259.6 48.8h4M261.6 43.2v4.6M261.6 48.8v4.5M264.2 40.6h2M272.3 40.6h2M276.9 40.6h.1"/>
<path d="M279.4 43.2v2.5M177.8 96.5h2M179.9 95.5h6v2h-6zM186 96.5h2M252.9 96.1h2.1v6h-2.1zM254 94v2M259.6 98.6h4M259.6 99.6h4M261.6 94v4.6M261.6 99.6v4.5M264.2 91.4h2M266.2 90.5h6v2h-6z"/>
<path d="M272.3 91.4h2M254 102.1v2M261.6 106.7v1.3h1.3l-1.3 1.2-1.3-1.2h1.3M261.6 106.7h.1M36.1 149.4h4M36.1 150.4h4M38.1 157.5v1.3h1.3l-1.3 1.2-1.3-1.2h1.3M38.1 157.5h.1M38.1 144.8v4.6M38.1 150.4v4.5M46.3 149.4h4M46.3 150.4h4"/>
<path d="M48.3 157.5v1.3h1.2l-1.2 1.2-1.3-1.2h1.3M48.3 157.5h.1M48.3 144.8v4.6M48.3 150.4v4.5M129.5 157.5v1.3h1.3l-1.3 1.2-1.2-1.2h1.2M129.5 157.5h.1M139.7 157.5v1.3h1.3l-1.3 1.2-1.3-1.2h1.3M139.7 157.5h.1M66 167.6v1.3h1.3l-1.3 1.3-1.2-1.3h1.2M66 167.6h.1M104.7 167.1h4M104.7 168.1h4"/>
<path d="M106.7 177.8v1.3h1.2l-1.2 1.2-1.3-1.2h1.3M106.7 177.8h.1M106.7 162.6v4.5M106.7 168.1v4.6M118.3 164.6h2.1v6h-2.1zM119.4 177.8v1.3h1.2l-1.2 1.2-1.3-1.2h1.3M119.4 177.8h.1M119.4 162.6v2M119.4 170.7v2"/>
</g>
<g fill="none" stroke="#008484" stroke-width=".18">
<path d="M149.3 33.6a.79 .79 0 0 1 0 1.3M206.1 38h.7M281.5 33.6l.2 .2-.2 .3 .2 .3v.2l-.2 .3M135.8 46.6h.8l-.5 1.3M212.2 54.5l.2 .2v.3l-.7 .7h.7M245.5 50.7h.4M245.5 50.1h.6M270.4 41.2h.7M270.6 40.1l.2-.2v1.3M253.7 96.7l.5 .5M254.6 96.7l-.5 .3M270.4 92h.7"/>
<path d="M270.6 90.9l.2-.2v1.3M44.7 149.7h.7M114.4 169.4h.4M114.4 168.8h.6M122.5 165.9l-1.3-.5v.8"/>
</g>
<path d="M147.3 35.6v2.5M154.9 35.6v2.5M279.4 35.6v2.5M154.9 86.4v2.5" fill="none" stroke="#840000" stroke-width=".25"/>
<g fill="none" stroke="#000" stroke-width=".18">
<circle cx="259.1" cy="36.8" r="1.27"/>
<circle cx="147.3" cy="44.4" r="1.27"/>
<circle cx="279.4" cy="47" r="1.27"/>
</g>
<path d="M76.2 139.7h20.3v22.9h-20.3z" fill="#ffffc2"/>
<path d="M76.2 139.7h20.3v22.9h-20.3z" fill="none" stroke="#800000" stroke-width=".18"/>
<g fill="none" stroke="#840000" stroke-width=".18">
<path d="M20.3 43.2v2.5M20.3 50.8v2.5M27.9 43.2v2.5M27.9 50.8v2.5M50.8 55.9h.1M50.8 40.6h7.6M50.8 45.7h7.6M50.8 50.8h7.6M73.7 40.6h7.6M73.7 45.7h7.6M73.7 50.8h7.6M83.8 40.6h2.6"/>
<path d="M83.8 50.8v2.5M96.5 40.6h2.6M101.6 43.2v2.5M101.6 50.8v2.5M129.5 43.2v2.5M129.5 50.8v2.5M132.1 40.6h2M140.2 40.6h2M144.8 40.6h.1M147.3 40.6v2.6M195.6 40.6h7.6M195.6 45.7h7.6"/>
<path d="M195.6 50.8h7.6M218.4 40.6h7.7M218.4 45.7h7.7M218.4 50.8h7.7M228.6 40.6h2.5M228.6 50.8v2.5M241.3 40.6h2.5M246.4 43.2v2.5M246.4 50.8v2.5M264.2 40.6h2M272.3 40.6h2M276.9 40.6h.1"/>
<path d="M279.4 43.2v2.5M91.4 91.4h2.6M104.1 91.4h2.6M109.2 94v2.5M129.5 91.4h2M137.7 91.4h2M144.8 91.4h.1M147.3 91.4v2.6M228.6 91.4h2.5M241.3 91.4h2.5M246.4 94v2.5M261.6 94v2.5"/>
<path d="M264.2 91.4h2M272.3 91.4h2M276.9 91.4h.1M279.4 94v2.5M20.3 106.7v1.3h1.3l-1.3 1.2-1.3-1.2h1.3M20.3 106.7h.1M30.5 106.7v1.3h1.2l-1.2 1.2-1.3-1.2h1.3M30.5 106.7h.1M55.9 106.7v1.3h1.2l-1.2 1.2-1.3-1.2h1.3M55.9 106.7h.1M109.2 101.6v2.5M113.2 111.3h2.1v6h-2.1z"/>
<path d="M114.3 109.2v2M114.3 117.4v2M118.3 111.3h2.1v6h-2.1zM119.4 109.2v2M119.4 117.4v2M246.4 101.6v2.5M261.6 101.6v2.5M33 139.7v2.5M119.4 121.9v1.3h1.2l-1.2 1.3-1.3-1.3h1.3M119.4 121.9h.1M124.5 139.7v2.5M17.8 142.2v2.6"/>
<path d="M20.3 142.2h2M22.4 141.3h6v2h-6zM28.5 142.2h2M43.2 141l1-.7-1-.6-1 .6 1 .7v1.2M43.2 142.2h.1M68.6 142.2h7.6M68.6 144.8h7.6M68.6 149.9h7.6M68.6 152.4h7.6M68.6 157.5h7.6M72.6 157.1h.8M96.5 142.2h7.6"/>
<path d="M96.5 144.8h7.6M96.5 149.9h7.6M96.5 154.9h7.6M118.3 146.9h2.1v6h-2.1zM119.4 144.8v2M119.4 152.9v2M127.5 149.4h4M127.5 150.4h4M129.5 144.8v4.6M129.5 150.4v4.5M137.7 149.4h4M137.7 150.4h4"/>
<path d="M139.7 144.8v4.6M139.7 150.4v4.5M68.6 160h7.6M96.5 160h7.6"/>
</g>
<g fill="none" stroke="#008484" stroke-width=".18">
<path d="M138.7 39.9v1.3M149.3 33.6a.79 .79 0 0 1 0 1.3M206.1 38h.7M281.5 33.6l.2 .2-.2 .3 .2 .3v.2l-.2 .3M67.4 54.5l.3 .2-.1 .3-.7 .7h.8M100.5 45.9h.8M100.7 50.7h.4M100.7 50.1h.6M135.8 46.6h.8l-.5 1.3M138.3 41.2h.7M212.2 54.5l.2 .2v.3l-.7 .7h.7M245.5 50.7h.4"/>
<path d="M245.5 50.1h.6M270.4 41.2h.7M270.6 40.1l.2-.2v1.3M135.8 92h.7M136.1 90.7v1.3M149 84.4h.6M149.4 84.9l.2 .2v.3l-.2 .3M270.4 92h.7M270.6 90.9l.2-.2v1.3M280.9 84.4h.8l-.4 .5M281.5 84.9l.2 .2v.3l-.2 .3M108.3 101.5h.4"/>
<path d="M108.3 100.9h.6M245.5 101.5h.4M245.5 100.9h.6M19.8 135.2l.3 .2-.3 .3 .3 .3v.2l-.3 .3M19 149.7h.8M26.5 142.8h.8M26.9 141.5v1.3M95.2 159.9l.3 .2 .2 .3-.3 .2h-.3M95.2 159.3l.5 .1M146.3 149.3h.8M85.9 165h.8M85.9 164l.4-.3v1.3"/>
</g>
<g fill="none" stroke="#000" stroke-width=".18">
<path d="M118.6 39.5l.4 .6M118.8 38.9l.2 .2v.3l-.2 .1M255.7 39.5l.4 .6M255.9 38.9l.2 .2-.1 .3-.1 .1M118.6 90.3l.4 .6M118.8 89.7l.2 .2v.3l-.2 .1M255.7 90.3l.4 .6M255.9 89.7l.2 .2-.1 .3-.1 .1M62.4 140.5a.9 .9 0 0 1 0 1.2"/>
<circle cx="124.5" cy="138.4" r="1.27"/>
</g>
<g fill="none" stroke="#008400" stroke-width=".18">
<path d="M17.8 38.1v2.5h33M147.3 38.1v2.5h-5.1M154.9 38.1v2.5h40.7M279.4 38.1v5.1M20.3 40.6v2.6M20.3 53.3v2.6M27.9 40.6v2.6M27.9 53.3v2.6M35.6 40.6v5.1M45.7 45.7h5.1M48.3 45.7v5.1h-10.2v2.5M50.8 50.8v5.1"/>
<path d="M81.3 45.7h12.7v10.2h17.8v-2.6M81.3 40.6h2.5M81.3 50.8h10.1M99.1 40.6h33M101.6 40.6v2.6M101.6 53.3v2.6M106.7 40.6v2.6M106.7 53.3v2.6M109.2 55.9v2.5M111.8 40.6v2.6M119.4 40.6v2.6M119.4 53.3v2.6"/>
<path d="M129.5 40.6v2.6M129.5 53.3v2.6M157.5 40.6v2.6M157.5 53.3v2.6M167.6 40.6v2.6M167.6 53.3v2.6M175.3 40.6v5.1h2.5M188 45.7h7.6M195.6 50.8h-2.6v5.1M226.1 45.7h12.7v10.2h15.2M226.1 40.6h2.5M226.1 50.8h10.1"/>
<path d="M243.8 40.6h20.4M246.4 40.6v2.6M246.4 53.3v2.6M254 40.6v2.6M254 53.3v5.1M261.6 40.6v2.6M261.6 53.3v2.6M274.3 40.6h5.1M109.2 68.6v2.5M254 68.6v2.5M17.8 88.9v2.5h40.6M20.3 91.4v2.6"/>
<path d="M30.5 91.4v2.6M38.1 91.4v5.1h2.5M50.8 96.5h7.6M88.9 96.5h10.2v10.2h20.3v2.5M88.9 91.4h2.5M106.7 91.4h22.8M109.2 91.4v2.6M116.8 91.4v2.6M127 91.4v2.6M147.3 88.9v2.5h-7.6M154.9 88.9v2.5h40.7M157.5 91.4v2.6"/>
<path d="M167.6 91.4v2.6M175.3 91.4v5.1h2.5M188 96.5h7.6M226.1 96.5h12.7v10.2h15.2M226.1 91.4h2.5M243.8 91.4h20.4M246.4 91.4v2.6M254 91.4v2.6M261.6 91.4v2.6M274.3 91.4h5.1M279.4 88.9v5.1M20.3 104.1v2.6"/>
<path d="M30.5 104.1v2.6M58.4 101.6h-2.5v5.1M109.2 104.1v2.6M114.3 106.7v2.5M114.3 119.4v2.5M116.8 104.1v2.6M119.4 119.4v2.5M127 104.1v2.6M157.5 104.1v2.6M167.6 104.1v2.6M195.6 101.6h-2.6v5.1M246.4 104.1v2.6"/>
<path d="M254 104.1v5.1M254 119.4v2.5M261.6 104.1v2.6M17.8 139.7v2.5h2.5M144.8 139.7v2.5h-40.7M30.5 142.2h38.1M38.1 142.2v2.6M38.1 154.9v2.6M48.3 142.2v2.6M48.3 154.9v2.6M58.4 152.4h10.2M66 142.2v7.7h2.6"/>
<path d="M66 144.8h2.6M68.6 157.5h-2.6v10.1M104.1 149.9h10.2v7.6h5.1M106.7 142.2v2.6h-2.6M119.4 142.2v2.6M119.4 154.9v7.7M129.5 142.2v2.6M129.5 154.9v2.6M139.7 142.2v2.6M139.7 154.9v2.6M66 160h2.6M104.1 160h2.6v2.6"/>
<path d="M106.7 172.7v5.1M119.4 172.7v5.1"/>
</g>
<path d="M88.3 101l1.2 1.2M89.5 101l-1.2 1.2M225.5 101l1.2 1.2M226.7 101l-1.2 1.2M103.5 154.3l1.2 1.2M104.7 154.3l-1.2 1.2" fill="none" stroke="#000084" stroke-width=".18"/>
<g fill="none" stroke="#0000c2" stroke-width=".18">
<path d="M75.5 28.8v1.3M75.5 29.3l-.3-.1-.3 .3 .1 .5h.5M85.3 29.3l.2-.1 .3 .1 .1 .8M85.3 29.2v.9M99.6 28.8l.5 1.3M110.3 31.3l.4 1.3 .4-1.3M132.1 28.8l-.4 1.3M78.2 63.1h.8M78.9 61.9v.5M80.5 62.6h.9M81.7 64.4h.8l-.5 1.2M83 63.1h.7"/>
<path d="M83 62.2l.3-.4v1.3M84 65.1h.9M86.5 65.6h.7M86.5 64.7l.3-.3v1.2M223 63.1h.7M223.1 64.4h.1a.68 .68 0 0 1 .4 .6 .68 .68 0 0 1-.4 .6h-.1M223.7 61.9v.5M225.1 65.1h1M225.3 62.6h.9M227.6 65.6h.7M227.6 64.7l.4-.3v1.2M227.7 63.1h.8"/>
<path d="M227.7 62.2l.4-.4v1.3M85.8 111.3h.8M86.5 110.2v.4M88.1 110.9h1M88.7 112.6h.8l-.5 1.3M90.6 111.3h.7M90.6 110.4l.3-.3v1.2M91 113.4h1M93.5 113.9h.7M93.5 113l.3-.4v1.3M223 111.3h.7M223.7 110.2v.4"/>
<path d="M224.9 112.7l.1-.1a.68 .68 0 0 1 .5 .7 .68 .68 0 0 1-.5 .6 .84 .84 0 0 1-.1-1.2zM225.3 110.9h.9M226.9 113.4h1M227.7 110.4l.4-.3v1.2M227.7 111.3h.8M229.4 113.9h.8M229.4 113l.4-.4v1.3M82.2 179.8v.1M83 179.2l-.3 .2 .1 .4 .2 .1h.3l.1-.2v-.3l-.2-.2M83 179.2l-.3-.2 .3-.3h.2l.2 .2-.2 .3M83 179.2h.2M94.1 171.1l.1 .2-.1 .3-.7 .7h.8"/>
<path d="M95.7 171.8h1M96 169.8h.7M96.7 168.6v.4M98.3 169.3h.9M102.2 179.1l.3 .8M102.5 179.9l-.1 .3M102.8 179.1l-.3 .8M37.4 188.8v1.3M37.4 189.3l-.3-.1-.3 .3 .1 .5h.5M47.2 189.4l.2-.2 .3 .1 .1 .8M47.2 189.2v.9M62.1 189.2l-.1 .1"/>
<path d="M62.1 189.6l-.2 .2 .2 .3M70.1 189.2v.9M70.4 189.2l-.3 .2M80.2 189.3l-.4-.1-.2 .3 .1 .5h.5M87.9 189.3l-.4-.1-.2 .3 .1 .5h.5M87.9 188.8v1.3M92.6 189.2h.5M92.9 188.8h.2M93.7 189.2l-.3 .3v.3l.3 .3M97.1 188.8v1.3M97.5 189.2l-.4 .2M100.8 189.5h.2v.5"/>
<path d="M101.4 188.8h.7M117.2 188.8v.1M117.2 189.2v.9M118.3 189.3l-.3-.1-.2 .2v.2l.5 .1v.3h-.5M121.3 188.8l.4 .1M121.7 190l-.4 .1M124.2 191.4l-.4 1.2"/>
</g>
<path d="M16.9 15.1h-1v1.9M18.6 15.2l-.3-.1h-.7v1.9M20.5 15.2a.69 .69 0 0 0-.9 .1M21.1 17l.6-1.9 .7 1.9M24.2 15.1l.6 1.9 .7-1.9M27.8 15.1v1.6M28.8 15.1v1.6M36.4 16.1h.8M37.4 15.2l-.2-.1h-.8v1.9M43.4 15.1v1.6M46.2 15.1v1.6" fill="none" stroke="#0000c2" stroke-width=".38"/>
<g fill="#008400" stroke="#008400" stroke-width=".18">
<circle cx="35.6" cy="40.6" r=".46"/>
<circle cx="20.3" cy="40.6" r=".46"/>
<circle cx="27.9" cy="40.6" r=".46"/>
<circle cx="119.4" cy="40.6" r=".46"/>
<circle cx="124.5" cy="40.6" r=".46"/>
<circle cx="129.5" cy="40.6" r=".46"/>
<circle cx="101.6" cy="55.9" r=".46"/>
<circle cx="109.2" cy="91.4" r=".46"/>
<circle cx="124.5" cy="91.4" r=".46"/>
<circle cx="114.3" cy="106.7" r=".46"/>
<circle cx="109.2" cy="106.7" r=".46"/>
<circle cx="116.8" cy="106.7" r=".46"/>
<circle cx="101.6" cy="40.6" r=".46"/>
<circle cx="106.7" cy="55.9" r=".46"/>
<circle cx="109.2" cy="55.9" r=".46"/>
<circle cx="106.7" cy="40.6" r=".46"/>
<circle cx="111.8" cy="40.6" r=".46"/>
<circle cx="48.3" cy="45.7" r=".46"/>
<circle cx="83.8" cy="50.8" r=".46"/>
<circle cx="175.3" cy="91.4" r=".46"/>
<circle cx="167.6" cy="91.4" r=".46"/>
<circle cx="175.3" cy="40.6" r=".46"/>
<circle cx="261.6" cy="91.4" r=".46"/>
<circle cx="259.1" cy="91.4" r=".46"/>
<circle cx="246.4" cy="55.9" r=".46"/>
<circle cx="254" cy="55.9" r=".46"/>
<circle cx="279.4" cy="91.4" r=".46"/>
<circle cx="276.9" cy="91.4" r=".46"/>
<circle cx="228.6" cy="50.8" r=".46"/>
<circle cx="254" cy="106.7" r=".46"/>
<circle cx="246.4" cy="106.7" r=".46"/>
<circle cx="246.4" cy="91.4" r=".46"/>
<circle cx="167.6" cy="40.6" r=".46"/>
<circle cx="144.8" cy="91.4" r=".46"/>
<circle cx="127" cy="91.4" r=".46"/>
<circle cx="147.3" cy="40.6" r=".46"/>
<circle cx="157.5" cy="40.6" r=".46"/>
<circle cx="147.3" cy="91.4" r=".46"/>
<circle cx="157.5" cy="91.4" r=".46"/>
<circle cx="144.8" cy="40.6" r=".46"/>
<circle cx="276.9" cy="40.6" r=".46"/>
<circle cx="246.4" cy="40.6" r=".46"/>
<circle cx="259.1" cy="40.6" r=".46"/>
<circle cx="261.6" cy="40.6" r=".46"/>
<circle cx="279.4" cy="40.6" r=".46"/>
<circle cx="119.4" cy="157.5" r=".46"/>
<circle cx="129.5" cy="142.2" r=".46"/>
<circle cx="66" cy="160" r=".46"/>
<circle cx="20.3" cy="91.4" r=".46"/>
<circle cx="30.5" cy="91.4" r=".46"/>
<circle cx="38.1" cy="91.4" r=".46"/>
<circle cx="17.8" cy="142.2" r=".46"/>
<circle cx="43.2" cy="142.2" r=".46"/>
<circle cx="124.5" cy="142.2" r=".46"/>
<circle cx="119.4" cy="142.2" r=".46"/>
<circle cx="106.7" cy="142.2" r=".46"/>
<circle cx="139.7" cy="142.2" r=".46"/>
<circle cx="33" cy="142.2" r=".46"/>
<circle cx="38.1" cy="142.2" r=".46"/>
<circle cx="48.3" cy="142.2" r=".46"/>
<circle cx="66" cy="142.2" r=".46"/>
<circle cx="66" cy="144.8" r=".46"/>
</g>
<use href="#words"/>
</svg>
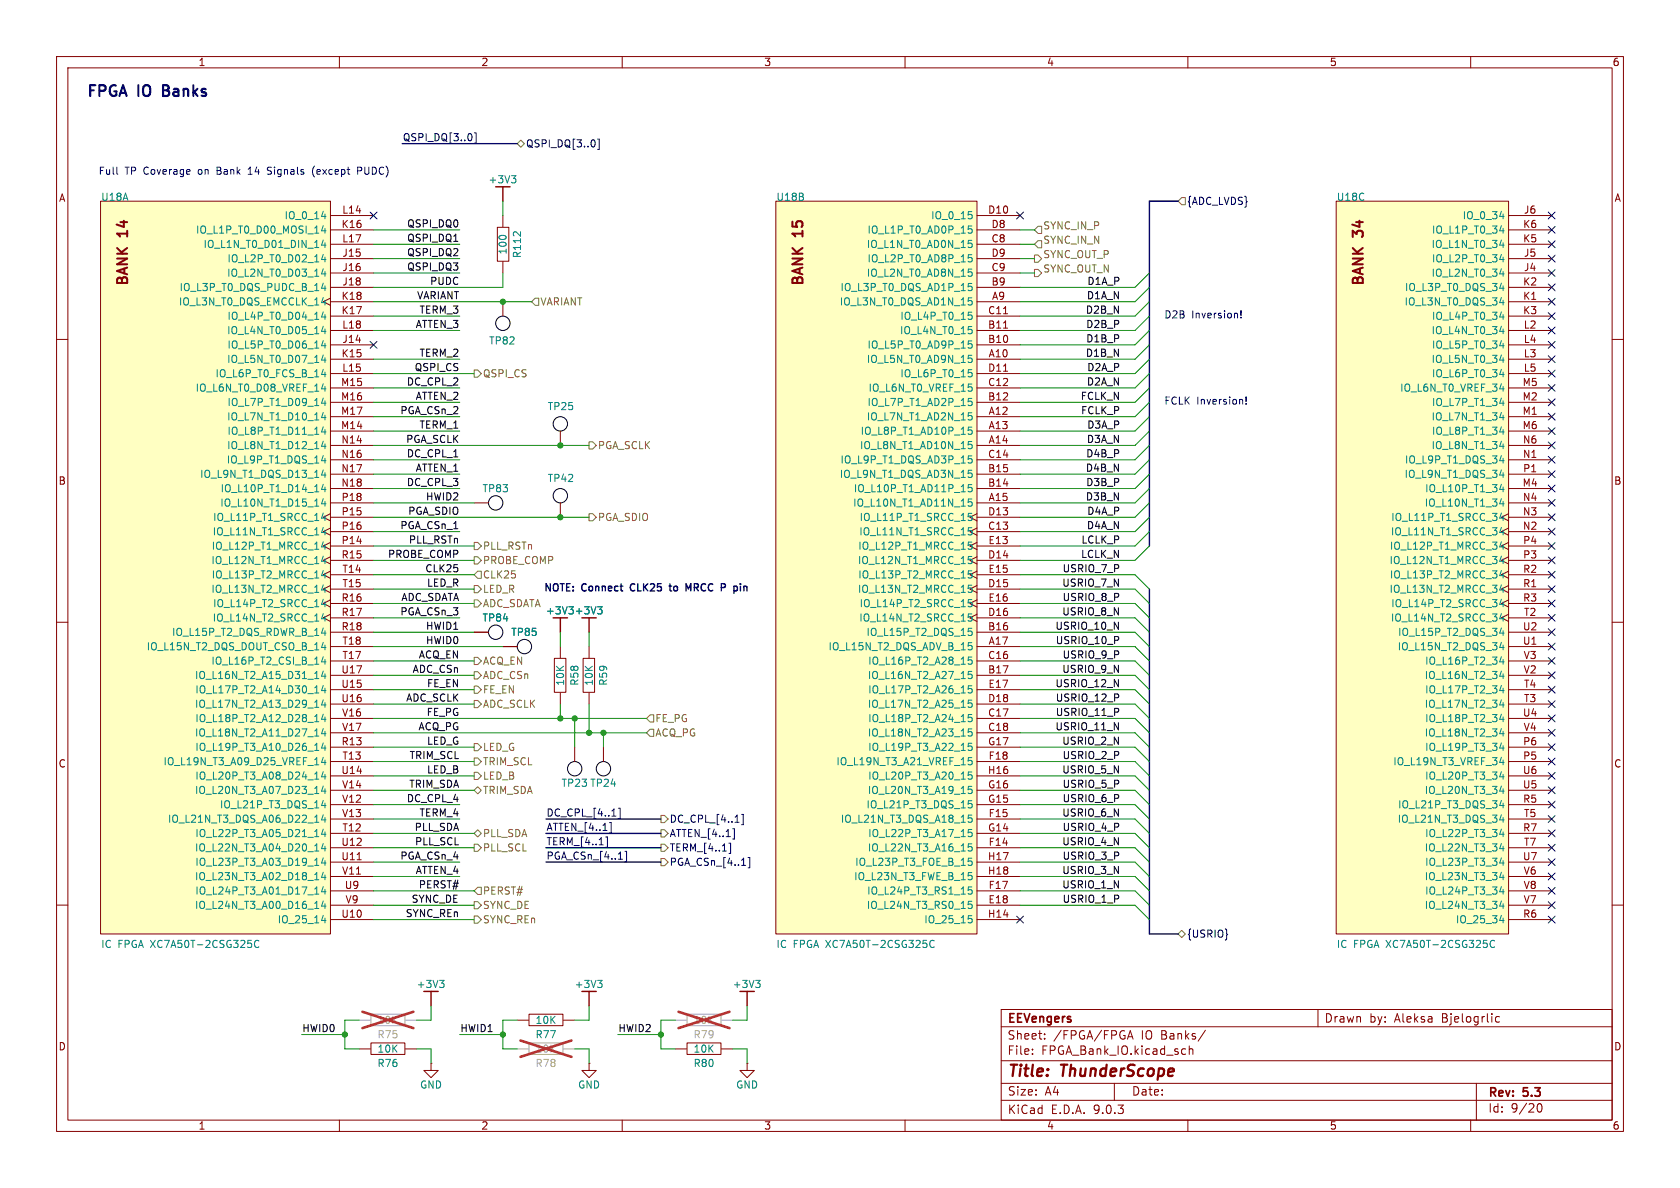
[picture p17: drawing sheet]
<svg xmlns="http://www.w3.org/2000/svg" width="297mm" height="210mm" viewBox="0 0 297 210" stroke-linecap="round" stroke-linejoin="round" font-family="sans-serif">
<defs><g id="words">
<g font-size="2.8" fill="#840000">
<text x="178" y="190.9">Title:</text>
<text x="187.7" y="190.9">ThunderScope</text>
</g>
<g font-size="2.7" fill="#0000c2">
<text x="15.2" y="18">FPGA</text>
<text x="24.5" y="18">IO</text>
<text x="29.6" y="18">Banks</text>
</g>
<g font-size="2.5" fill="#840000">
<text x="23.1" y="41.8" transform="rotate(-90 23.1 41.8)">14</text>
<text x="142.5" y="41.8" transform="rotate(-90 142.5 41.8)">15</text>
<text x="241.5" y="41.8" transform="rotate(-90 241.5 41.8)">34</text>
<text x="23.1" y="50.8" transform="rotate(-90 23.1 50.8)">BANK</text>
<text x="142.5" y="50.8" transform="rotate(-90 142.5 50.8)">BANK</text>
<text x="241.5" y="50.8" transform="rotate(-90 241.5 50.8)">BANK</text>
</g>
<g font-size="2.1" fill="#840000">
<text x="178" y="184">Sheet:</text>
<text x="178" y="181.2">EEVengers</text>
<text x="186.2" y="184">/FPGA/FPGA</text>
<text x="201.8" y="184">IO Banks/</text>
<text x="234.1" y="181">Drawn</text>
<text x="242.1" y="181">by:</text>
<text x="246.6" y="181">Aleksa</text>
<text x="255" y="181">Bjelogrlic</text>
<text x="178" y="186.7">File:</text>
<text x="184.1" y="186.7">FPGA_Bank_IO.kicad_sch</text>
<text x="178.1" y="197.1">KiCad</text>
<text x="178.1" y="193.9">Size:</text>
<text x="184.7" y="193.9">A4</text>
<text x="185.8" y="197.1">E.D.A.</text>
<text x="193.4" y="197.1">9.0.3</text>
<text x="200" y="193.9">Date:</text>
<text x="263" y="194.3">Rev:</text>
<text x="263" y="196.9">Id:</text>
<text x="267.1" y="196.9">9/20</text>
<text x="269.4" y="194.3">5.3</text>
</g>
<g font-size="1.8" fill="#840000">
<text x="35" y="11.9">1</text>
<text x="85" y="11.9">2</text>
<text x="135" y="11.9">3</text>
<text x="185" y="11.9">4</text>
<text x="235" y="11.9">5</text>
<text x="285" y="11.9">6</text>
<text x="10.3" y="35.9">A</text>
<text x="285.3" y="35.9">A</text>
<text x="60.3" y="40.4">K16</text>
<text x="60.4" y="37.8">L14</text>
<text x="174.6" y="37.8">D10</text>
<text x="175.2" y="40.4">D8</text>
<text x="269.2" y="40.4">K6</text>
<text x="269.3" y="37.8">J6</text>
<text x="60.4" y="42.9">L17</text>
<text x="60.4" y="45.5">J15</text>
<text x="175.2" y="42.9">C8</text>
<text x="175.2" y="45.5">D9</text>
<text x="269.2" y="42.9">K5</text>
<text x="269.3" y="45.5">J5</text>
<text x="60.3" y="53.1">K18</text>
<text x="60.4" y="48">J16</text>
<text x="60.4" y="50.5">J18</text>
<text x="175.2" y="48">C9</text>
<text x="175.2" y="50.5">B9</text>
<text x="175.3" y="53.1">A9</text>
<text x="269.2" y="50.5">K2</text>
<text x="269.2" y="53.1">K1</text>
<text x="269.3" y="48">J4</text>
<text x="60.3" y="55.6">K17</text>
<text x="60.4" y="58.2">L18</text>
<text x="174.6" y="55.6">C11</text>
<text x="174.6" y="58.2">B11</text>
<text x="269.2" y="55.6">K3</text>
<text x="269.3" y="58.2">L2</text>
<text x="60.3" y="63.2">K15</text>
<text x="60.4" y="65.8">L15</text>
<text x="60.4" y="60.7">J14</text>
<text x="174.6" y="60.7">B10</text>
<text x="174.6" y="65.8">D11</text>
<text x="174.7" y="63.2">A10</text>
<text x="269.3" y="60.7">L4</text>
<text x="269.3" y="63.2">L3</text>
<text x="269.3" y="65.8">L5</text>
<text x="60.2" y="68.3">M15</text>
<text x="60.2" y="70.9">M16</text>
<text x="174.6" y="68.3">C12</text>
<text x="174.6" y="70.9">B12</text>
<text x="269.1" y="68.3">M5</text>
<text x="269.1" y="70.9">M2</text>
<text x="60.2" y="73.4">M17</text>
<text x="60.2" y="75.9">M14</text>
<text x="174.7" y="73.4">A12</text>
<text x="174.7" y="75.9">A13</text>
<text x="269.1" y="73.4">M1</text>
<text x="269.1" y="75.9">M6</text>
<text x="60.3" y="78.5">N14</text>
<text x="60.3" y="81">N16</text>
<text x="60.3" y="83.6">N17</text>
<text x="174.6" y="81">C14</text>
<text x="174.6" y="83.6">B15</text>
<text x="174.7" y="78.5">A14</text>
<text x="269.1" y="78.5">N6</text>
<text x="269.1" y="81">N1</text>
<text x="269.2" y="83.6">P1</text>
<text x="10.3" y="85.9">B</text>
<text x="60.3" y="86.1">N18</text>
<text x="60.3" y="88.6">P18</text>
<text x="174.6" y="86.1">B14</text>
<text x="174.7" y="88.6">A15</text>
<text x="269.1" y="86.1">M4</text>
<text x="269.1" y="88.6">N4</text>
<text x="285.3" y="85.9">B</text>
<text x="60.3" y="91.2">P15</text>
<text x="60.3" y="93.7">P16</text>
<text x="174.6" y="91.2">D13</text>
<text x="174.6" y="93.7">C13</text>
<text x="269.1" y="91.2">N3</text>
<text x="269.1" y="93.7">N2</text>
<text x="60.3" y="96.3">P14</text>
<text x="60.3" y="98.8">R15</text>
<text x="60.4" y="101.3">T14</text>
<text x="174.6" y="98.8">D14</text>
<text x="174.6" y="96.3">E13</text>
<text x="174.6" y="101.3">E15</text>
<text x="269.2" y="96.3">P4</text>
<text x="269.2" y="98.8">P3</text>
<text x="269.2" y="101.3">R2</text>
<text x="60.3" y="106.4">R16</text>
<text x="60.4" y="103.9">T15</text>
<text x="174.6" y="103.9">D15</text>
<text x="174.6" y="106.4">E16</text>
<text x="269.2" y="103.9">R1</text>
<text x="269.2" y="106.4">R3</text>
<text x="60.3" y="109">R17</text>
<text x="60.3" y="111.5">R18</text>
<text x="174.6" y="109">D16</text>
<text x="174.6" y="111.5">B16</text>
<text x="269.1" y="111.5">U2</text>
<text x="269.3" y="109">T2</text>
<text x="60.3" y="119.1">U17</text>
<text x="60.4" y="114">T18</text>
<text x="60.4" y="116.6">T17</text>
<text x="174.6" y="116.6">C16</text>
<text x="174.6" y="119.1">B17</text>
<text x="174.7" y="114">A17</text>
<text x="269.1" y="114">U1</text>
<text x="269.3" y="116.6">V3</text>
<text x="269.3" y="119.1">V2</text>
<text x="60.3" y="121.7">U15</text>
<text x="60.3" y="124.2">U16</text>
<text x="174.6" y="124.2">D18</text>
<text x="174.6" y="121.7">E17</text>
<text x="269.3" y="121.7">T4</text>
<text x="269.3" y="124.2">T3</text>
<text x="60.3" y="131.8">R13</text>
<text x="60.4" y="126.7">V16</text>
<text x="60.4" y="129.3">V17</text>
<text x="174.6" y="126.7">C17</text>
<text x="174.6" y="129.3">C18</text>
<text x="174.6" y="131.8">G17</text>
<text x="269.1" y="126.7">U4</text>
<text x="269.2" y="131.8">P6</text>
<text x="269.3" y="129.3">V4</text>
<text x="10.3" y="135.9">C</text>
<text x="60.3" y="136.9">U14</text>
<text x="60.4" y="134.4">T13</text>
<text x="174.6" y="136.9">H16</text>
<text x="174.7" y="134.4">F18</text>
<text x="269.1" y="136.9">U6</text>
<text x="269.2" y="134.4">P5</text>
<text x="285.3" y="135.9">C</text>
<text x="60.4" y="139.4">V14</text>
<text x="60.4" y="142">V12</text>
<text x="174.6" y="139.4">G16</text>
<text x="174.6" y="142">G15</text>
<text x="269.1" y="139.4">U5</text>
<text x="269.2" y="142">R5</text>
<text x="60.3" y="149.6">U12</text>
<text x="60.4" y="144.5">V13</text>
<text x="60.4" y="147.1">T12</text>
<text x="174.6" y="147.1">G14</text>
<text x="174.7" y="144.5">F15</text>
<text x="174.7" y="149.6">F14</text>
<text x="269.2" y="147.1">R7</text>
<text x="269.3" y="144.5">T5</text>
<text x="269.3" y="149.6">T7</text>
<text x="60.3" y="152.1">U11</text>
<text x="60.4" y="154.7">V11</text>
<text x="174.6" y="152.1">H17</text>
<text x="174.6" y="154.7">H18</text>
<text x="269.1" y="152.1">U7</text>
<text x="269.3" y="154.7">V6</text>
<text x="60.9" y="157.2">U9</text>
<text x="61" y="159.8">V9</text>
<text x="174.6" y="159.8">E18</text>
<text x="174.7" y="157.2">F17</text>
<text x="269.3" y="157.2">V8</text>
<text x="269.3" y="159.8">V7</text>
<text x="60.3" y="162.3">U10</text>
<text x="174.6" y="162.3">H14</text>
<text x="269.2" y="162.3">R6</text>
<text x="10.3" y="185.9">D</text>
<text x="285.3" y="185.9">D</text>
<text x="35" y="199.9">1</text>
<text x="85" y="199.9">2</text>
<text x="135" y="199.9">3</text>
<text x="185" y="199.9">4</text>
<text x="235" y="199.9">5</text>
<text x="285" y="199.9">6</text>
</g>
<g font-size="1.8" fill="#000084">
<text x="71.1" y="25.1">QSPI_DQ[3..0]</text>
<text x="92.9" y="26.3">QSPI_DQ[3..0]</text>
<text x="209.7" y="36.4">{ADC_LVDS}</text>
<text x="96.5" y="147">ATTEN_[4..1]</text>
<text x="96.5" y="149.5">TERM_[4..1]</text>
<text x="96.5" y="144.4">DC_CPL_[4..1]</text>
<text x="118.3" y="148.2">ATTEN_[4..1]</text>
<text x="118.3" y="145.6">DC_CPL_[4..1]</text>
<text x="96.5" y="152.1">PGA_CSn_[4..1]</text>
<text x="118.3" y="150.7">TERM_[4..1]</text>
<text x="118.3" y="153.3">PGA_CSn_[4..1]</text>
<text x="209.7" y="166">{USRIO}</text>
</g>
<g font-size="1.8" fill="#0000c2">
<text x="17.3" y="31.1">Full</text>
<text x="22.1" y="31.1">TP Coverage</text>
<text x="35.3" y="31.1">on</text>
<text x="38.8" y="31.1">Bank</text>
<text x="44.5" y="31.1">14</text>
<text x="48.1" y="31.1">Signals</text>
<text x="56.3" y="31.1">(except</text>
<text x="64.4" y="31.1">PUDC)</text>
<text x="205.7" y="56.5">D2B</text>
<text x="210.7" y="56.5">Inversion!</text>
<text x="205.7" y="71.7">FCLK</text>
<text x="211.6" y="71.7">Inversion!</text>
<text x="96" y="104.9">NOTE:</text>
<text x="102.9" y="104.9">Connect</text>
<text x="111.9" y="104.9">CLK25</text>
<text x="119.4" y="104.9">to</text>
<text x="122.8" y="104.9">MRCC</text>
<text x="129.5" y="104.9">P</text>
<text x="132.2" y="104.9">pin</text>
</g>
<g font-size="1.8" fill="#008484">
<text x="17.8" y="35.7">U18A</text>
<text x="86.3" y="32.6">+3V3</text>
<text x="137.2" y="35.7">U18B</text>
<text x="236.2" y="35.7">U18C</text>
<text x="34.5" y="41.5">IO_L1P_T0_D00_MOSI_14</text>
<text x="50.2" y="39">IO_0_14</text>
<text x="153.3" y="41.5">IO_L1P_T0_AD0P_15</text>
<text x="164.5" y="39">IO_0_15</text>
<text x="253" y="41.5">IO_L1P_T0_34</text>
<text x="258.5" y="39">IO_0_34</text>
<text x="35.9" y="44">IO_L1N_T0_D01_DIN_14</text>
<text x="40.1" y="46.6">IO_L2P_T0_D02_14</text>
<text x="89.8" y="45.1" transform="rotate(-90 89.8 45.1)">100</text>
<text x="92.3" y="45.7" transform="rotate(-90 92.3 45.7)">R112</text>
<text x="153.1" y="44">IO_L1N_T0_AD0N_15</text>
<text x="153.3" y="46.6">IO_L2P_T0_AD8P_15</text>
<text x="253" y="44">IO_L1N_T0_34</text>
<text x="253" y="46.6">IO_L2P_T0_34</text>
<text x="31.6" y="51.7">IO_L3P_T0_DQS_PUDC_B_14</text>
<text x="40" y="49.1">IO_L2N_T0_D03_14</text>
<text x="148.5" y="51.7">IO_L3P_T0_DQS_AD1P_15</text>
<text x="153.1" y="49.1">IO_L2N_T0_AD8N_15</text>
<text x="248.3" y="51.7">IO_L3P_T0_DQS_34</text>
<text x="253" y="49.1">IO_L2N_T0_34</text>
<text x="31.5" y="54.2">IO_L3N_T0_DQS_EMCCLK_14</text>
<text x="40" y="59.3">IO_L4N_T0_D05_14</text>
<text x="40.1" y="56.7">IO_L4P_T0_D04_14</text>
<text x="148.4" y="54.2">IO_L3N_T0_DQS_AD1N_15</text>
<text x="159" y="59.3">IO_L4N_T0_15</text>
<text x="159.1" y="56.7">IO_L4P_T0_15</text>
<text x="248.2" y="54.2">IO_L3N_T0_DQS_34</text>
<text x="253" y="59.3">IO_L4N_T0_34</text>
<text x="253" y="56.7">IO_L4P_T0_34</text>
<text x="40" y="64.4">IO_L5N_T0_D07_14</text>
<text x="40.1" y="61.8">IO_L5P_T0_D06_14</text>
<text x="86.4" y="61.1">TP82</text>
<text x="153.1" y="64.4">IO_L5N_T0_AD9N_15</text>
<text x="153.3" y="61.8">IO_L5P_T0_AD9P_15</text>
<text x="253" y="64.4">IO_L5N_T0_34</text>
<text x="253" y="61.8">IO_L5P_T0_34</text>
<text x="34.5" y="69.4">IO_L6N_T0_D08_VREF_14</text>
<text x="38" y="66.9">IO_L6P_T0_FCS_B_14</text>
<text x="40.1" y="72">IO_L7P_T1_D09_14</text>
<text x="153.3" y="72">IO_L7P_T1_AD2P_15</text>
<text x="153.4" y="69.4">IO_L6N_T0_VREF_15</text>
<text x="159.1" y="66.9">IO_L6P_T0_15</text>
<text x="247.4" y="69.4">IO_L6N_T0_VREF_34</text>
<text x="253" y="66.9">IO_L6P_T0_34</text>
<text x="253" y="72">IO_L7P_T1_34</text>
<text x="40" y="74.5">IO_L7N_T1_D10_14</text>
<text x="40.1" y="77.1">IO_L8P_T1_D11_14</text>
<text x="96.7" y="72.7">TP25</text>
<text x="152.1" y="77.1">IO_L8P_T1_AD10P_15</text>
<text x="153.1" y="74.5">IO_L7N_T1_AD2N_15</text>
<text x="253" y="74.5">IO_L7N_T1_34</text>
<text x="253" y="77.1">IO_L8P_T1_34</text>
<text x="40" y="82.1">IO_L9P_T1_DQS_14</text>
<text x="40" y="79.6">IO_L8N_T1_D12_14</text>
<text x="148.5" y="82.1">IO_L9P_T1_DQS_AD3P_15</text>
<text x="151.9" y="79.6">IO_L8N_T1_AD10N_15</text>
<text x="248.3" y="82.1">IO_L9P_T1_DQS_34</text>
<text x="253" y="79.6">IO_L8N_T1_34</text>
<text x="35.3" y="84.7">IO_L9N_T1_DQS_D13_14</text>
<text x="38.8" y="89.8">IO_L10N_T1_D15_14</text>
<text x="38.9" y="87.2">IO_L10P_T1_D14_14</text>
<text x="85.2" y="87.2">TP83</text>
<text x="96.7" y="85.4">TP42</text>
<text x="148.4" y="84.7">IO_L9N_T1_DQS_AD3N_15</text>
<text x="150.7" y="89.8">IO_L10N_T1_AD11N_15</text>
<text x="150.8" y="87.2">IO_L10P_T1_AD11P_15</text>
<text x="248.2" y="84.7">IO_L9N_T1_DQS_34</text>
<text x="251.8" y="89.8">IO_L10N_T1_34</text>
<text x="251.8" y="87.2">IO_L10P_T1_34</text>
<text x="37.5" y="94.8">IO_L11N_T1_SRCC_14</text>
<text x="37.6" y="92.3">IO_L11P_T1_SRCC_14</text>
<text x="151.8" y="94.8">IO_L11N_T1_SRCC_15</text>
<text x="151.9" y="92.3">IO_L11P_T1_SRCC_15</text>
<text x="245.8" y="94.8">IO_L11N_T1_SRCC_34</text>
<text x="245.9" y="92.3">IO_L11P_T1_SRCC_34</text>
<text x="37.3" y="99.9">IO_L12N_T1_MRCC_14</text>
<text x="37.3" y="97.4">IO_L12P_T1_MRCC_14</text>
<text x="151.6" y="99.9">IO_L12N_T1_MRCC_15</text>
<text x="151.6" y="97.4">IO_L12P_T1_MRCC_15</text>
<text x="245.5" y="99.9">IO_L12N_T1_MRCC_34</text>
<text x="245.6" y="97.4">IO_L12P_T1_MRCC_34</text>
<text x="37.3" y="105">IO_L13N_T2_MRCC_14</text>
<text x="37.3" y="102.5">IO_L13P_T2_MRCC_14</text>
<text x="37.6" y="107.5">IO_L14P_T2_SRCC_14</text>
<text x="151.6" y="105">IO_L13N_T2_MRCC_15</text>
<text x="151.6" y="102.5">IO_L13P_T2_MRCC_15</text>
<text x="151.9" y="107.5">IO_L14P_T2_SRCC_15</text>
<text x="245.5" y="105">IO_L13N_T2_MRCC_34</text>
<text x="245.6" y="102.5">IO_L13P_T2_MRCC_34</text>
<text x="245.9" y="107.5">IO_L14P_T2_SRCC_34</text>
<text x="30.3" y="112.6">IO_L15P_T2_DQS_RDWR_B_14</text>
<text x="37.5" y="110.1">IO_L14N_T2_SRCC_14</text>
<text x="85.2" y="110.1">TP84</text>
<text x="90.3" y="112.6">TP85</text>
<text x="96.4" y="108.8">+3V3 +3V3</text>
<text x="151.8" y="110.1">IO_L14N_T2_SRCC_15</text>
<text x="153.1" y="112.6">IO_L15P_T2_DQS_15</text>
<text x="245.8" y="110.1">IO_L14N_T2_SRCC_34</text>
<text x="247.1" y="112.6">IO_L15P_T2_DQS_34</text>
<text x="25.8" y="115.2">IO_L15N_T2_DQS_DOUT_CSO_B_14</text>
<text x="37.3" y="117.7">IO_L16P_T2_CSI_B_14</text>
<text x="146.4" y="115.2">IO_L15N_T2_DQS_ADV_B_15</text>
<text x="153.4" y="117.7">IO_L16P_T2_A28_15</text>
<text x="247" y="115.2">IO_L15N_T2_DQS_34</text>
<text x="251.8" y="117.7">IO_L16P_T2_34</text>
<text x="34.4" y="120.2">IO_L16N_T2_A15_D31_14</text>
<text x="34.4" y="125.3">IO_L17N_T2_A13_D29_14</text>
<text x="34.4" y="122.8">IO_L17P_T2_A14_D30_14</text>
<text x="99.9" y="121.3" transform="rotate(-90 99.9 121.3)">10K</text>
<text x="102.5" y="121.3" transform="rotate(-90 102.5 121.3)">R58</text>
<text x="105" y="121.3" transform="rotate(-90 105 121.3)">10K</text>
<text x="107.5" y="121.3" transform="rotate(-90 107.5 121.3)">R59</text>
<text x="153.3" y="120.2">IO_L16N_T2_A27_15</text>
<text x="153.3" y="125.3">IO_L17N_T2_A25_15</text>
<text x="153.4" y="122.8">IO_L17P_T2_A26_15</text>
<text x="251.8" y="120.2">IO_L16N_T2_34</text>
<text x="251.8" y="125.3">IO_L17N_T2_34</text>
<text x="251.8" y="122.8">IO_L17P_T2_34</text>
<text x="34.4" y="130.4">IO_L18N_T2_A11_D27_14</text>
<text x="34.4" y="127.9">IO_L18P_T2_A12_D28_14</text>
<text x="153.3" y="130.4">IO_L18N_T2_A23_15</text>
<text x="153.4" y="127.9">IO_L18P_T2_A24_15</text>
<text x="251.8" y="130.4">IO_L18N_T2_34</text>
<text x="251.8" y="127.9">IO_L18P_T2_34</text>
<text x="28.8" y="135.5">IO_L19N_T3_A09_D25_VREF_14</text>
<text x="34.4" y="132.9">IO_L19P_T3_A10_D26_14</text>
<text x="147.8" y="135.5">IO_L19N_T3_A21_VREF_15</text>
<text x="153.4" y="132.9">IO_L19P_T3_A22_15</text>
<text x="246.2" y="135.5">IO_L19N_T3_VREF_34</text>
<text x="251.8" y="132.9">IO_L19P_T3_34</text>
<text x="34.4" y="140.6">IO_L20N_T3_A07_D23_14</text>
<text x="34.4" y="138">IO_L20P_T3_A08_D24_14</text>
<text x="38.8" y="143.1">IO_L21P_T3_DQS_14</text>
<text x="99.2" y="139.3">TP23 TP24</text>
<text x="153.1" y="143.1">IO_L21P_T3_DQS_15</text>
<text x="153.3" y="140.6">IO_L20N_T3_A19_15</text>
<text x="153.4" y="138">IO_L20P_T3_A20_15</text>
<text x="247.1" y="143.1">IO_L21P_T3_DQS_34</text>
<text x="251.8" y="140.6">IO_L20N_T3_34</text>
<text x="251.8" y="138">IO_L20P_T3_34</text>
<text x="29.6" y="145.6">IO_L21N_T3_DQS_A06_D22_14</text>
<text x="34.4" y="148.2">IO_L22P_T3_A05_D21_14</text>
<text x="148.5" y="145.6">IO_L21N_T3_DQS_A18_15</text>
<text x="153.4" y="148.2">IO_L22P_T3_A17_15</text>
<text x="247" y="145.6">IO_L21N_T3_DQS_34</text>
<text x="251.8" y="148.2">IO_L22P_T3_34</text>
<text x="34.4" y="150.7">IO_L22N_T3_A04_D20_14</text>
<text x="34.4" y="155.8">IO_L23N_T3_A02_D18_14</text>
<text x="34.4" y="153.3">IO_L23P_T3_A03_D19_14</text>
<text x="150.9" y="155.8">IO_L23N_T3_FWE_B_15</text>
<text x="151.1" y="153.3">IO_L23P_T3_FOE_B_15</text>
<text x="153.3" y="150.7">IO_L22N_T3_A16_15</text>
<text x="251.8" y="150.7">IO_L22N_T3_34</text>
<text x="251.8" y="155.8">IO_L23N_T3_34</text>
<text x="251.8" y="153.3">IO_L23P_T3_34</text>
<text x="34.4" y="160.9">IO_L24N_T3_A00_D16_14</text>
<text x="34.4" y="158.3">IO_L24P_T3_A01_D17_14</text>
<text x="153.1" y="160.9">IO_L24N_T3_RS0_15</text>
<text x="153.2" y="158.3">IO_L24P_T3_RS1_15</text>
<text x="251.8" y="160.9">IO_L24N_T3_34</text>
<text x="251.8" y="158.3">IO_L24P_T3_34</text>
<text x="17.8" y="167.8">IC</text>
<text x="20.8" y="167.8">FPGA XC7A50T-2CSG325C</text>
<text x="49" y="163.4">IO_25_14</text>
<text x="137.2" y="167.8">IC</text>
<text x="140.2" y="167.8">FPGA XC7A50T-2CSG325C</text>
<text x="163.3" y="163.4">IO_25_15</text>
<text x="236.2" y="167.8">IC</text>
<text x="239.3" y="167.8">FPGA XC7A50T-2CSG325C</text>
<text x="257.3" y="163.4">IO_25_34</text>
<text x="73.6" y="174.9">+3V3</text>
<text x="101.5" y="174.9">+3V3</text>
<text x="129.4" y="174.9">+3V3</text>
<text x="94.6" y="183.7">R77</text>
<text x="94.6" y="181.2">10K</text>
<text x="66.6" y="188.8">R76</text>
<text x="66.6" y="186.3">10K</text>
<text x="122.5" y="188.8">R80</text>
<text x="122.5" y="186.3">10K</text>
<text x="74.2" y="192.6">GND</text>
<text x="102.1" y="192.6">GND</text>
<text x="130" y="192.6">GND</text>
</g>
<g font-size="1.8">
<text x="71.9" y="40.3">QSPI_DQ0</text>
<text x="71.9" y="42.8">QSPI_DQ1</text>
<text x="71.9" y="45.4">QSPI_DQ2</text>
<text x="71.9" y="47.9">QSPI_DQ3</text>
<text x="73.6" y="53">VARIANT</text>
<text x="75.9" y="50.5">PUDC</text>
<text x="192.1" y="53">D1A_N</text>
<text x="192.1" y="50.5">D1A_P</text>
<text x="73.4" y="58.1">ATTEN_3</text>
<text x="74.1" y="55.5">TERM_3</text>
<text x="191.9" y="55.5">D2B_N</text>
<text x="191.9" y="58.1">D2B_P</text>
<text x="73.2" y="65.7">QSPI_CS</text>
<text x="74.1" y="63.2">TERM_2</text>
<text x="191.9" y="63.2">D1B_N</text>
<text x="191.9" y="60.6">D1B_P</text>
<text x="192.1" y="65.7">D2A_P</text>
<text x="71.8" y="68.2">DC_CPL_2</text>
<text x="73.4" y="70.8">ATTEN_2</text>
<text x="191" y="70.8">FCLK_N</text>
<text x="192.1" y="68.2">D2A_N</text>
<text x="70.7" y="73.3">PGA_CSn_2</text>
<text x="74.1" y="75.9">TERM_1</text>
<text x="191" y="73.3">FCLK_P</text>
<text x="192.1" y="75.9">D3A_P</text>
<text x="71.7" y="78.4">PGA_SCLK</text>
<text x="71.8" y="80.9">DC_CPL_1</text>
<text x="73.4" y="83.5">ATTEN_1</text>
<text x="191.9" y="83.5">D4B_N</text>
<text x="191.9" y="80.9">D4B_P</text>
<text x="192.1" y="78.4">D3A_N</text>
<text x="71.8" y="86">DC_CPL_3</text>
<text x="75.2" y="88.6">HWID2</text>
<text x="191.9" y="88.6">D3B_N</text>
<text x="191.9" y="86">D3B_P</text>
<text x="70.7" y="93.6">PGA_CSn_1</text>
<text x="72.1" y="91.1">PGA_SDIO</text>
<text x="192.1" y="93.6">D4A_N</text>
<text x="192.1" y="91.1">D4A_P</text>
<text x="68.5" y="98.7">PROBE_COMP</text>
<text x="72.2" y="96.2">PLL_RSTn</text>
<text x="75.1" y="101.3">CLK25</text>
<text x="187.8" y="101.3">USRIO_7_P</text>
<text x="191" y="98.7">LCLK_N</text>
<text x="191.1" y="96.2">LCLK_P</text>
<text x="70.9" y="106.3">ADC_SDATA</text>
<text x="75.4" y="103.8">LED_R</text>
<text x="187.7" y="103.8">USRIO_7_N</text>
<text x="187.8" y="106.3">USRIO_8_P</text>
<text x="70.7" y="108.9">PGA_CSn_3</text>
<text x="75.2" y="111.4">HWID1</text>
<text x="75.2" y="114">HWID0</text>
<text x="186.5" y="111.4">USRIO_10_N</text>
<text x="186.5" y="114">USRIO_10_P</text>
<text x="187.7" y="108.9">USRIO_8_N</text>
<text x="72.9" y="119">ADC_CSn</text>
<text x="73.9" y="116.5">ACQ_EN</text>
<text x="187.7" y="119">USRIO_9_N</text>
<text x="187.8" y="116.5">USRIO_9_P</text>
<text x="71.7" y="124.1">ADC_SCLK</text>
<text x="75.4" y="121.6">FE_EN</text>
<text x="186.5" y="121.6">USRIO_12_N</text>
<text x="186.5" y="124.1">USRIO_12_P</text>
<text x="73.9" y="129.2">ACQ_PG</text>
<text x="75.3" y="126.7">FE_PG</text>
<text x="75.4" y="131.7">LED_G</text>
<text x="186.5" y="129.2">USRIO_11_N</text>
<text x="186.5" y="126.7">USRIO_11_P</text>
<text x="187.7" y="131.7">USRIO_2_N</text>
<text x="72.3" y="134.3">TRIM_SCL</text>
<text x="75.4" y="136.8">LED_B</text>
<text x="187.7" y="136.8">USRIO_5_N</text>
<text x="187.8" y="134.3">USRIO_2_P</text>
<text x="71.8" y="141.9">DC_CPL_4</text>
<text x="72.2" y="139.4">TRIM_SDA</text>
<text x="187.8" y="141.9">USRIO_6_P</text>
<text x="187.8" y="139.4">USRIO_5_P</text>
<text x="73.2" y="147">PLL_SDA</text>
<text x="73.3" y="149.5">PLL_SCL</text>
<text x="74.1" y="144.4">TERM_4</text>
<text x="187.7" y="149.5">USRIO_4_N</text>
<text x="187.7" y="144.4">USRIO_6_N</text>
<text x="187.8" y="147">USRIO_4_P</text>
<text x="70.7" y="152.1">PGA_CSn_4</text>
<text x="73.4" y="154.6">ATTEN_4</text>
<text x="187.7" y="154.6">USRIO_3_N</text>
<text x="187.8" y="152.1">USRIO_3_P</text>
<text x="72.7" y="159.7">SYNC_DE</text>
<text x="73.9" y="157.1">PERST#</text>
<text x="187.7" y="157.1">USRIO_1_N</text>
<text x="187.8" y="159.7">USRIO_1_P</text>
<text x="71.6" y="162.2">SYNC_REn</text>
<text x="53.3" y="182.5">HWID0</text>
<text x="81.3" y="182.5">HWID1</text>
<text x="109.2" y="182.5">HWID2</text>
</g>
<g font-size="1.8" fill="#848400">
<text x="184.3" y="40.6">SYNC_IN_P</text>
<text x="184.3" y="43.2">SYNC_IN_N</text>
<text x="184.3" y="45.7">SYNC_OUT_P</text>
<text x="184.3" y="48.3">SYNC_OUT_N</text>
<text x="95.4" y="54.2">VARIANT</text>
<text x="85.3" y="66.9">QSPI_CS</text>
<text x="105.6" y="79.6">PGA_SCLK</text>
<text x="105.6" y="92.3">PGA_SDIO</text>
<text x="85.3" y="99.9">PROBE_COMP</text>
<text x="85.3" y="97.4">PLL_RSTn</text>
<text x="85.3" y="105">LED_R</text>
<text x="85.3" y="107.5">ADC_SDATA</text>
<text x="85.3" y="102.5">CLK25</text>
<text x="85.3" y="117.7">ACQ_EN</text>
<text x="85.3" y="125.3">ADC_SCLK</text>
<text x="85.3" y="120.2">ADC_CSn</text>
<text x="85.3" y="122.8">FE_EN</text>
<text x="115.8" y="127.9">FE_PG</text>
<text x="115.8" y="130.4">ACQ_PG</text>
<text x="85.3" y="132.9">LED_G</text>
<text x="85.3" y="135.5">TRIM_SCL</text>
<text x="85.3" y="140.6">TRIM_SDA</text>
<text x="85.3" y="138">LED_B</text>
<text x="85.3" y="148.2">PLL_SDA</text>
<text x="85.3" y="150.7">PLL_SCL</text>
<text x="85.3" y="158.3">PERST#</text>
<text x="85.3" y="160.9">SYNC_DE</text>
<text x="85.3" y="163.4">SYNC_REn</text>
</g>
<g font-size="1.8" fill="#a1a1a1">
<text x="66.6" y="183.7">R75</text>
<text x="66.6" y="181.2">10K</text>
<text x="122.5" y="183.7">R79</text>
<text x="122.5" y="181.2">10K</text>
<text x="94.6" y="188.8">R78</text>
<text x="94.6" y="186.3">10K</text>
</g>
</g></defs>
<path d="M0 0h297v210h-297z" fill="#fff" stroke="#fff" stroke-width=".18"/>
<g fill="none" stroke="#840000" stroke-width=".18">
<path d="M10 10h277v190h-277zM12 12h273v186h-273zM60 10v2M110 10v2M160 10v2M210 10v2M260 10v2M10 60h2M285 60h2M10 110h2M285 110h2M10 160h2"/>
<path d="M93.5 179.3h6v2h-6zM177 178.5h108v19.5h-108zM233 178.5v3M265.1 179.8l-.4-.1-.3 .3v.4l.1 .2h.6M285 160h2M60 198v2M91.4 180.3h2M99.6 180.3h2M110 198v2M160 198v2M177 194.5h108M177 191.5h108"/>
<path d="M177 187.5h108M177 181.5h108M182.5 186.3v.1M182.5 185.5v.1M184.7 183.6v.1M184.7 182.8v.1M197 191.5v3M199.3 183.7l.5-1.5 .5 1.5M199.5 183.3h.7M209.5 185.4l.1 .1M209.6 186.3l-.1 .1M210 198v2"/>
<path d="M210.2 184.9v1.5M210.2 185.5l.3-.1 .3 .1 .1 .9M213.1 182.1l-1.3 2M260 198v2M261 191.5v6.5M271.7 195.7l.2-.5 .2-.1a.81 .81 0 0 1 .6 .6 .81 .81 0 0 1-.3 .8h-.4l-.3-.5"/>
</g>
<path d="M236.2 35.6h30.5v129.5h-30.5z" fill="#ffffc2"/>
<path d="M236.2 35.6h30.5v129.5h-30.5z" fill="none" stroke="#800000" stroke-width=".18"/>
<g fill="none" stroke="#840000" stroke-width=".18">
<path d="M88.9 38.1v2M266.7 38.1h7.6M87.9 40.2h2.1v6h-2.1zM88.9 46.3v2M88.9 53.3v2.6M266.7 40.6h7.6M266.7 43.2h7.6M266.7 45.7h7.6M266.7 48.3h7.6M266.7 50.8h7.6M266.7 53.3h7.6M266.7 55.9h7.6"/>
<path d="M266.7 58.4h7.6M99.1 76.2v2.5M266.7 61h7.6M266.7 63.5h7.6M266.7 66h7.6M266.7 68.6h7.6M266.7 71.1h7.6M266.7 73.7h7.6M266.7 76.2h7.6M266.7 78.7h7.6M266.7 90.8l-1.3 .6 1.3 .7M266.7 93.3l-1.3 .7 1.3 .6"/>
<path d="M266.7 95.9l-1.3 .6 1.3 .7M266.7 98.4l-1.3 .7 1.3 .6M266.7 81.3h7.6M266.7 83.8h7.6M266.7 86.4h7.6M266.7 88.9h7.6M266.7 91.4h7.6M266.7 94h7.6M266.7 96.5h7.6M266.7 99.1h7.6M83.8 111.8h2.6M88.9 114.3h2.5"/>
<path d="M266.7 101l-1.3 .6 1.3 .6M266.7 103.5l-1.3 .6 1.3 .7M266.7 106l-1.3 .7 1.3 .6M266.7 108.6l-1.3 .6 1.3 .7M266.7 101.6h7.6M266.7 104.1h7.6M266.7 106.7h7.6M266.7 109.2h7.6M266.7 111.8h7.6M266.7 114.3h7.6M266.7 116.8h7.6M266.7 119.4h7.6"/>
<path d="M101.6 132.1v2.5M106.7 132.1v2.5M266.7 121.9h7.6M266.7 124.5h7.6M266.7 127h7.6M266.7 129.5h7.6M266.7 132.1h7.6M266.7 134.6h7.6M266.7 137.2h7.6M266.7 139.7h7.6M266.7 142.2h7.6M266.7 144.8h7.6"/>
<path d="M266.7 147.3h7.6M266.7 149.9h7.6M266.7 152.4h7.6M266.7 154.9h7.6M266.7 157.5h7.6M266.7 160h7.6M266.7 162.6h7.6M63.5 185.4h2M65.6 184.4h6v2h-6zM71.7 185.4h2M76.2 188v1.2h1.3l-1.3 1.3-1.3-1.3h1.3M76.2 188h.1"/>
<path d="M104.1 188v1.2h1.3l-1.3 1.3-1.2-1.3h1.2M104.1 188h.1M119.4 185.4h2M121.5 184.4h6v2h-6zM127.5 185.4h2"/>
</g>
<g fill="none" stroke="#008484" stroke-width=".18">
<path d="M90.4 31.1h.8l-.4 .4M91 31.5l.2 .3v.3l-.2 .2M265.1 38.3h.8M265.1 40.8h.8M265.1 43.3h.8M265.1 45.9h.8M265.1 48.4h.8M265.1 51h.8M265.1 53.5h.8M265.1 56h.8M265.1 58.6h.8M265.7 40.4v.8"/>
<path d="M265.7 42.9v.9M265.7 45.5v.8M265.7 48v.8M265.7 50.5v.9M265.7 53.1v.8M265.7 55.6v.9M265.7 58.2v.8M265.1 61.1h.8M265.1 63.7h.8M265.1 66.2h.8M265.1 68.7h.8M265.1 71.3h.8"/>
<path d="M265.1 73.8h.8M265.1 76.4h.8M265.1 78.9h.8M265.7 60.7v.8M265.7 63.2v.9M265.7 65.8v.8M265.7 70.9v.8M265.7 73.4v.8M265.7 75.9v.9M265.7 78.5v.8M265.1 81.4h.8M265.1 84h.8"/>
<path d="M265.1 96.7h.8M265.1 99.2h.8M265.4 85.6l-.3 .9h.8M265.4 88.1l-.3 1h.8M265.4 90.7l-.3 .9h.8M265.4 93.2l-.3 .9h.8M265.7 81v.9M265.7 83.6v.8M265.7 86.1v.8M265.7 88.6v.9M265.7 91.2v.8M265.7 93.7v.9"/>
<path d="M265.7 96.3v.8M265.7 98.8v.8M265.1 101.8h.8M265.1 104.3h.8M265.1 114.5h.8M265.4 105.9l-.3 .9h.8M265.4 108.5l-.3 .9h.8M265.4 111l-.3 .9h.8M265.4 116.1l-.3 .9h.8M265.4 118.6l-.3 .9h.8M265.7 101.3v.9M265.7 103.9v.8"/>
<path d="M265.7 106.4v.9M265.7 109v.8M265.7 111.5v.8M265.7 114v.9M265.7 116.6v.8M265.7 119.1v.9M265.1 134.8h.8M265.4 121.2l-.3 .9h.8M265.4 123.7l-.3 .9h.8M265.4 126.2l-.3 1h.8M265.4 128.8l-.3 .9h.8M265.4 131.3l-.3 .9h.8"/>
<path d="M265.4 136.4l-.3 .9h.8M265.4 138.9l-.3 1h.8M265.7 121.7v.8M265.7 124.2v.8M265.7 126.7v.9M265.7 129.3v.8M265.7 131.8v.9M265.7 134.4v.8M265.7 136.9v.8M265.7 139.4v.9M265.1 144.9h.8M265.4 141.5l-.3 .9h.8"/>
<path d="M265.4 146.6l-.3 .9h.8M265.4 149.1l-.3 .9h.8M265.4 151.6l-.3 1h.8M265.4 154.2l-.3 .9h.8M265.4 156.7l-.3 .9h.8M265.4 159.3l-.3 .9h.8M265.7 142v.8M265.7 144.5v.9M265.7 147.1v.8M265.7 149.6v.8M265.7 152.1v.9M265.7 154.7v.8"/>
<path d="M265.7 157.2v.9M265.7 159.8v.8M77.7 173.3h.8l-.4 .5M78.3 173.8l.2 .2v.3l-.2 .3M105.7 173.3h.7l-.4 .5M106.2 173.8l.2 .2v.3l-.2 .3M264.2 166.3a.6 .6 0 0 0-.8 .5 .6 .6 0 0 0 .6 .7l.2-.1M265.1 162.7h.8M265.7 162.3v.8"/>
</g>
<path d="M65.6 179.3h6v2h-6zM121.5 179.3h6v2h-6zM63.5 180.3h2M71.7 180.3h2M91.4 185.4h2M93.5 184.4h6v2h-6zM99.6 185.4h2M119.4 180.3h2M127.5 180.3h2" fill="none" stroke="#a1a1a1" stroke-width=".18"/>
<path d="M64.1 178.9l9 2.8M73.1 178.9l-9 2.8M120 178.9l9 2.8M129 178.9l-9 2.8M92 183.9l9 2.9M101 183.9l-9 2.9" fill="none" stroke="#ff2626" stroke-width=".46"/>
<path d="M88.9 33v2.6M76.2 175.3v2.5M104.1 175.3v2.5" fill="none" stroke="#840000" stroke-width=".25"/>
<g fill="none" stroke="#000" stroke-width=".18">
<circle cx="88.9" cy="57.1" r="1.27"/>
<circle cx="99.1" cy="74.9" r="1.27"/>
<circle cx="87.6" cy="111.8" r="1.27"/>
<circle cx="92.7" cy="114.3" r="1.27"/>
<circle cx="101.6" cy="135.9" r="1.27"/>
<circle cx="106.7" cy="135.9" r="1.27"/>
</g>
<path d="M17.8 35.6h40.6v129.5h-40.6z" fill="#ffffc2"/>
<path d="M17.8 35.6h40.6v129.5h-40.6z" fill="none" stroke="#800000" stroke-width=".18"/>
<g fill="none" stroke="#840000" stroke-width=".18">
<path d="M58.4 38.1h7.6M58.4 52.7l-1.3 .6 1.3 .7M58.4 40.6h7.6M58.4 43.2h7.6M58.4 45.7h7.6M58.4 48.3h7.6M58.4 50.8h7.6M58.4 53.3h7.6M58.4 55.9h7.6M58.4 58.4h7.6M58.4 61h7.6M58.4 63.5h7.6"/>
<path d="M58.4 66h7.6M58.4 68.6h7.6M58.4 71.1h7.6M58.4 73.7h7.6M58.4 76.2h7.6M58.4 78.7h7.6M58.4 90.8l-1.3 .6 1.3 .7M58.4 93.3l-1.3 .7 1.3 .6M58.4 95.9l-1.3 .6 1.3 .7M58.4 98.4l-1.3 .7 1.3 .6M58.4 81.3h7.6M58.4 83.8h7.6"/>
<path d="M58.4 86.4h7.6M58.4 88.9h7.6M58.4 91.4h7.6M58.4 94h7.6M58.4 96.5h7.6M58.4 99.1h7.6M99.1 88.9v2.5M58.4 101l-1.3 .6 1.3 .6M58.4 103.5l-1.3 .6 1.3 .7M58.4 106l-1.3 .7 1.3 .6M58.4 108.6l-1.3 .6 1.3 .7M58.4 101.6h7.6"/>
<path d="M58.4 104.1h7.6M58.4 106.7h7.6M58.4 109.2h7.6M58.4 111.8h7.6M58.4 114.3h7.6M58.4 116.8h7.6M58.4 119.4h7.6M98 116.4h2v6h-2zM99.1 114.3v2M103.1 116.4h2v6h-2zM104.1 114.3v2M58.4 121.9h7.6"/>
<path d="M58.4 124.5h7.6M58.4 127h7.6M58.4 129.5h7.6M58.4 132.1h7.6M58.4 134.6h7.6M58.4 137.2h7.6M58.4 139.7h7.6M99.1 122.5v2M104.1 122.5v2M58.4 142.2h7.6M58.4 144.8h7.6M58.4 147.3h7.6"/>
<path d="M58.4 149.9h7.6M58.4 152.4h7.6M58.4 154.9h7.6M58.4 157.5h7.6M63.1 152h.8M58.4 160h7.6M58.4 162.6h7.6M132.1 188v1.2h1.2l-1.2 1.3-1.3-1.3h1.3M132.1 188h.1"/>
</g>
<g fill="none" stroke="#008484" stroke-width=".18">
<path d="M56.8 38.3h.8M57.1 39.9l-.3 .9h.8M56.8 51h.8M56.8 53.5h.8M57.1 42.4l-.3 .9h.8M57.1 45l-.3 .9h.8M57.1 47.5l-.3 .9h.8M57.1 55.1l-.3 .9h.8M57.1 57.7l-.3 .9h.8M57.4 40.4v.8M57.4 42.9v.9M57.4 45.5v.8"/>
<path d="M57.4 48v.8M57.4 50.5v.9M57.4 53.1v.8M57.4 55.6v.9M57.4 58.2v.8M56.8 66.2h.8M57.1 60.2l-.3 .9h.8M57.1 62.7l-.3 1h.8M57.1 67.8l-.3 .9h.8M57.1 70.4l-.3 .9h.8M57.1 72.9l-.3 .9h.8M57.1 75.4l-.3 1h.8"/>
<path d="M57.1 78l-.3 .9h.8M57.4 60.7v.8M57.4 63.2v.9M57.4 65.8v.8M57.4 68.3v.9M57.4 70.9v.8M57.4 73.4v.8M57.4 75.9v.9M57.4 78.5v.8M56.8 81.4h.8M56.8 96.7h.8M56.8 99.2h.8"/>
<path d="M57.1 83.1l-.3 .9h.8M57.1 85.6l-.3 .9h.8M57.1 88.1l-.3 1h.8M57.1 90.7l-.3 .9h.8M57.1 93.2l-.3 .9h.8M57.4 81v.9M57.4 83.6v.8M57.4 86.1v.8M57.4 88.6v.9M57.4 91.2v.8M57.4 93.7v.9M57.4 96.3v.8"/>
<path d="M57.4 98.8v.8M55.6 120h.8M56.8 101.8h.8M56.8 104.3h.8M56.8 111.9h.8M56.8 114.5h.8M57.1 105.9l-.3 .9h.8M57.1 108.5l-.3 .9h.8M57.1 116.1l-.3 .9h.8M57.1 118.6l-.3 .9h.8M57.4 101.3v.9M57.4 103.9v.8"/>
<path d="M57.4 106.4v.9M57.4 109v.8M57.4 111.5v.8M57.4 114v.9M57.4 116.6v.8M57.4 119.1v.9M105.7 107.3h.7l-.4 .4M106.2 107.7l.2 .3v.3l-.2 .2M55.6 122.5h.8M55.6 125h.8M55.6 127.6h.8M55.6 130.1h.8"/>
<path d="M55.6 132.7h.8M55.6 137.7h.8M57.1 121.2l-.3 .9h.8M57.1 123.7l-.3 .9h.8M57.1 126.2l-.3 1h.8M57.1 128.8l-.3 .9h.8M57.1 131.3l-.3 .9h.8M57.1 133.9l-.3 .9h.8M57.1 136.4l-.3 .9h.8M57.1 138.9l-.3 1h.8M57.4 121.7v.8M57.4 124.2v.8"/>
<path d="M57.4 126.7v.9M57.4 129.3v.8M57.4 131.8v.9M57.4 134.4v.8M57.4 136.9v.8M57.4 139.4v.9M55.6 140.3h.8M55.6 147.9h.8M55.6 150.4h.8M55.6 153h.8M55.6 155.5h.8M55.6 158.1h.8"/>
<path d="M57.1 141.5l-.3 .9h.8M57.1 144l-.3 .9h.8M57.1 146.6l-.3 .9h.8M57.1 149.1l-.3 .9h.8M57.1 151.6l-.3 1h.8M57.1 154.2l-.3 .9h.8M57.1 156.7l-.3 .9h.8M57.1 159.3l-.3 .9h.8M57.4 142v.8M57.4 144.5v.9M57.4 147.1v.8M57.4 149.6v.8"/>
<path d="M57.4 152.1v.9M57.4 154.7v.8M57.4 157.2v.9M57.4 159.8v.8M45.8 166.3a.6 .6 0 0 0-.9 .5 .6 .6 0 0 0 .6 .7l.3-.1M55.6 160.6h.8M56.8 162.7h.8M57.4 162.3v.8M133.6 173.3h.8l-.4 .5M134.1 173.8l.3 .2v.3l-.3 .3"/>
</g>
<path d="M99.1 109.2v2.6M104.1 109.2v2.6M132.1 175.3v2.5" fill="none" stroke="#840000" stroke-width=".25"/>
<circle cx="99.1" cy="87.6" r="1.27" fill="none" stroke="#000" stroke-width=".18"/>
<path d="M137.2 35.6h35.5v129.5h-35.5z" fill="#ffffc2"/>
<path d="M137.2 35.6h35.5v129.5h-35.5z" fill="none" stroke="#800000" stroke-width=".18"/>
<g fill="none" stroke="#840000" stroke-width=".18">
<path d="M172.7 38.1h7.6M172.7 40.6h7.6M172.7 43.2h7.6M172.7 45.7h7.6M172.7 48.3h7.6M172.7 50.8h7.6M172.7 53.3h7.6M172.7 55.9h7.6M172.7 58.4h7.6M177.4 55.5h.7M177.4 58h.7M172.7 61h7.6"/>
<path d="M172.7 63.5h7.6M172.7 66h7.6M172.7 68.6h7.6M172.7 71.1h7.6M172.7 73.7h7.6M172.7 76.2h7.6M172.7 78.7h7.6M177.4 65.6h.7M83.8 88.9h2.6M172.7 90.8l-1.3 .6 1.3 .7M172.7 93.3l-1.3 .7 1.3 .6M172.7 95.9l-1.3 .6 1.3 .7"/>
<path d="M172.7 98.4l-1.3 .7 1.3 .6M172.7 81.3h7.6M172.7 83.8h7.6M172.7 86.4h7.6M172.7 88.9h7.6M172.7 91.4h7.6M172.7 94h7.6M172.7 96.5h7.6M172.7 99.1h7.6M83.8 111.8h2.6M88.9 114.3h2.5M172.7 101l-1.3 .6 1.3 .6"/>
<path d="M172.7 103.5l-1.3 .6 1.3 .7M172.7 106l-1.3 .7 1.3 .6M172.7 108.6l-1.3 .6 1.3 .7M172.7 101.6h7.6M172.7 104.1h7.6M172.7 106.7h7.6M172.7 109.2h7.6M172.7 111.8h7.6M172.7 114.3h7.6M172.7 116.8h7.6M172.7 119.4h7.6M172.7 121.9h7.6"/>
<path d="M172.7 124.5h7.6M172.7 127h7.6M172.7 129.5h7.6M172.7 132.1h7.6M172.7 134.6h7.6M172.7 137.2h7.6M172.7 139.7h7.6M172.7 142.2h7.6M172.7 144.8h7.6M172.7 147.3h7.6M172.7 149.9h7.6M172.7 152.4h7.6"/>
<path d="M172.7 154.9h7.6M172.7 157.5h7.6M172.7 160h7.6M172.7 162.6h7.6"/>
</g>
<g fill="none" stroke="#008484" stroke-width=".18">
<path d="M171.2 39.9h.6M171.8 38v.6M171.2 42.5h.6M171.2 45h.6M171.2 47.6h.6M171.2 50.1h.6M171.2 52.6h.6M171.2 55.2h.6M171.2 57.7h.6M171.3 40.4h.3l.3 .3-.2 .5h-.4M171.3 43h.3l.3 .2-.2 .5-.4 .1M171.3 45.5h.3l.3 .3-.2 .4-.4 .1"/>
<path d="M171.3 48.1h.3l.3 .2-.2 .5h-.4M171.3 50.6h.3l.3 .2-.2 .5-.4 .1M171.3 53.1h.3l.3 .3-.2 .5h-.4M171.3 55.7h.3l.3 .2-.2 .5-.4 .1M171.6 58.2l.3 .3v.3l-.3 .2M171.2 78.6l.4-.1 .3 .3-.2 .5h-.5M171.2 60.3h.6M171.2 62.8h.6M171.2 65.3h.6M171.2 67.9h.6M171.2 70.4h.6M171.2 73h.6"/>
<path d="M171.2 78h.6M171.3 60.8h.3l.3 .2-.2 .5h-.4M171.3 63.3h.3l.3 .2-.2 .5-.4 .1M171.3 65.8h.3l.3 .3-.2 .5h-.4M171.3 70.9h.3l.3 .3-.2 .4-.4 .1M171.3 73.5h.3l.3 .2-.2 .5h-.4M171.7 68.4l.2 .2-.2 .5M171.8 75.5h-.6l-.1 .6 .2-.1 .4 .1 .2 .1-.1 .5-.2 .1-.5-.1M171.2 80.6h.6M171.2 83.1h.6M171.2 90.7h.6M171.2 93.3h.6"/>
<path d="M171.2 95.8h.6M171.2 98.4h.6M171.3 81.1h.3l.3 .2-.2 .5-.4 .1M171.3 83.6h.3l.3 .3-.2 .4-.4 .1M171.3 91.2h.3l.3 .3-.2 .5h-.4M171.3 93.8h.3l.3 .2-.2 .5-.4 .1M171.3 96.3h.3l.3 .3-.2 .4-.4 .1M171.3 98.9h.3l.3 .2-.2 .5h-.4M171.8 85.7h-.6l-.1 .6 .2-.1h.4l.2 .2-.1 .4-.2 .1-.5-.1M171.8 88.2h-.6l-.1 .6 .2-.1 .4 .1 .2 .1-.1 .5-.2 .1-.5-.1M105.7 107.3h.7l-.4 .4M106.2 107.7l.2 .3v.3l-.2 .2"/>
<path d="M171.2 100.9h.6M171.2 103.4h.6M171.2 106h.6M171.2 108.5h.6M171.2 111.1h.6M171.2 113.6h.6M171.3 101.4h.3l.3 .2-.2 .5-.4 .1M171.3 103.9h.3l.3 .3-.2 .5h-.4M171.3 106.5h.3l.3 .2-.2 .5-.4 .1M171.3 109h.3l.3 .3-.2 .4-.4 .1M171.3 111.6h.3l.3 .2-.2 .5h-.4M171.3 114.1h.3l.3 .2-.2 .5-.4 .1"/>
<path d="M171.8 116.1h-.6l-.1 .7 .2-.2 .4 .1 .2 .2-.1 .4-.2 .1-.5-.1M171.8 118.7h-.6l-.1 .6 .2-.1h.4l.2 .2-.1 .4-.2 .2-.5-.2M171.2 134.5l.4-.1 .3 .3-.2 .4h-.5M171.2 133.9h.6M171.8 121.2h-.6l-.1 .6 .2-.1 .4 .1 .2 .2-.1 .4-.2 .1-.5-.1M171.8 123.8h-.6l-.1 .6 .2-.1h.4l.2 .2-.1 .4-.2 .1-.5-.1M171.8 126.3h-.6l-.1 .6 .2-.1 .4 .1 .2 .1-.1 .5-.2 .1-.5-.1M171.8 128.8h-.6l-.1 .7 .2-.2 .4 .1 .2 .2-.1 .4-.2 .1-.5-.1M171.8 131.4h-.6l-.1 .6 .2-.1h.4l.2 .2-.1 .4-.2 .2-.5-.2M171.8 136.5h-.6l-.1 .6 .2-.1h.4l.2 .2-.1 .4-.2 .1-.5-.1M171.8 139h-.6l-.1 .6 .2-.1 .4 .1 .2 .1-.1 .5-.2 .1-.5-.1M171.2 141.5h.6"/>
<path d="M171.2 151.7h.6M171.2 154.2h.6M171.3 142h.3l.3 .3-.2 .5h-.4M171.3 152.2h.3l.3 .2-.2 .5-.4 .1M171.3 154.7h.3l.3 .3-.2 .5h-.4M171.8 144.1h-.6l-.1 .6 .2-.1h.4l.2 .2-.1 .4-.2 .2-.5-.2M171.8 146.6h-.6l-.1 .6 .2-.1 .4 .1 .2 .2-.1 .4-.2 .1-.5-.1M171.8 149.2h-.6l-.1 .6 .2-.1h.4l.2 .2-.1 .4-.2 .1-.5-.1M171.8 156.8h-.6l-.1 .6 .2-.1h.4l.2 .2-.1 .4-.2 .2-.5-.2M171.8 159.3h-.6l-.1 .6 .2-.1 .4 .1 .2 .2-.1 .4-.2 .1-.5-.1M165.2 166.3a.6 .6 0 0 0-.9 .5 .6 .6 0 0 0 .6 .7l.3-.1M171.2 161.9h.6"/>
<path d="M171.3 162.4h.3l.3 .2-.2 .5h-.4"/>
</g>
<circle cx="87.6" cy="88.9" r="1.27" fill="none" stroke="#000" stroke-width=".18"/>
<g fill="none" stroke="#848400" stroke-width=".18">
<path d="M91.4 25.4l.7-.6 .6 .6-.6 .6zM208.9 34.9h.6v1.3h-.6l-.6-.6zM94.6 52.7h.6v1.3h-.6l-.6-.7zM182.9 45.1h.6l.6 .6-.6 .7h-.6zM182.9 47.6h.6l.6 .7-.6 .6h-.6zM183.5 40h.6v1.3h-.6l-.6-.7zM183.5 42.5h.6v1.3h-.6l-.6-.6zM83.8 65.4h.7l.6 .6-.6 .7h-.7zM104.1 78.1h.7l.6 .6-.6 .7h-.7zM83.8 98.4h.7l.6 .7-.6 .6h-.7zM83.8 95.9h.7l.6 .6-.6 .7h-.7zM104.1 90.8h.7l.6 .6-.6 .7h-.7z"/>
<path d="M83.8 103.5h.7l.6 .6-.6 .7h-.7zM83.8 106h.7l.6 .7-.6 .6h-.7zM83.8 116.2h.7l.6 .6-.6 .7h-.7zM83.8 118.7h.7l.6 .7-.6 .6h-.7zM84.5 101h.6v1.2h-.6l-.7-.6zM83.8 139.7l.7-.6 .6 .6-.6 .6zM83.8 136.5h.7l.6 .7-.6 .6h-.7zM83.8 131.4h.7l.6 .7-.6 .6h-.7zM83.8 123.8h.7l.6 .7-.6 .6h-.7zM83.8 121.3h.7l.6 .6-.6 .7h-.7zM83.8 134h.7l.6 .6-.6 .7h-.7zM114.9 126.4h.7v1.2h-.7l-.6-.6z"/>
<path d="M114.9 128.9h.7v1.3h-.7l-.6-.7zM83.8 147.3l.7-.6 .6 .6-.6 .7zM83.8 149.2h.7l.6 .7-.6 .6h-.7zM83.8 159.4h.7l.6 .6-.6 .7h-.7zM84.5 156.8h.6v1.3h-.6l-.7-.6zM116.8 149.2h.7l.6 .7-.6 .6h-.7zM116.8 146.7h.7l.6 .6-.6 .7h-.7zM116.8 144.1h.7l.6 .7-.6 .6h-.7zM116.8 151.8h.7l.6 .6-.6 .6h-.7zM83.8 161.9h.7l.6 .7-.6 .6h-.7zM208.9 164.5l.6 .6-.6 .6-.6-.6z"/>
</g>
<g fill="none" stroke="#000084" stroke-width=".18">
<path d="M65.4 37.5l1.2 1.2M66.6 37.5l-1.2 1.2M83.4 23.9v.7M83.9 23.5h.3v1.8h-.3M105.2 25v.7M105.6 24.6h.3v1.8h-.3M179.7 37.5l1.2 1.2M180.9 37.5l-1.2 1.2M273.7 37.5l1.2 1.2M274.9 37.5l-1.2 1.2M273.7 57.8l1.2 1.2M273.7 47.7l1.2 1.2"/>
<path d="M273.7 55.3l1.2 1.2M273.7 50.2l1.2 1.2M273.7 45.1l1.2 1.2M273.7 40l1.2 1.2M273.7 42.6l1.2 1.2M273.7 52.7l1.2 1.2M274.9 57.8l-1.2 1.2M274.9 47.7l-1.2 1.2M274.9 55.3l-1.2 1.2M274.9 50.2l-1.2 1.2M274.9 45.1l-1.2 1.2M274.9 40l-1.2 1.2"/>
<path d="M274.9 42.6l-1.2 1.2M274.9 52.7l-1.2 1.2M65.4 60.4l1.2 1.2M66.6 60.4l-1.2 1.2M273.7 78.1l1.2 1.2M273.7 75.6l1.2 1.2M273.7 68l1.2 1.2M273.7 73.1l1.2 1.2M273.7 65.4l1.2 1.2M273.7 70.5l1.2 1.2M273.7 62.9l1.2 1.2M273.7 60.4l1.2 1.2"/>
<path d="M274.9 78.1l-1.2 1.2M274.9 75.6l-1.2 1.2M274.9 68l-1.2 1.2M274.9 73.1l-1.2 1.2M274.9 65.4l-1.2 1.2M274.9 70.5l-1.2 1.2M274.9 62.9l-1.2 1.2M274.9 60.4l-1.2 1.2M273.7 80.7l1.2 1.2M273.7 85.8l1.2 1.2M273.7 95.9l1.2 1.2M273.7 93.4l1.2 1.2"/>
<path d="M273.7 83.2l1.2 1.2M273.7 98.5l1.2 1.2M273.7 90.8l1.2 1.2M273.7 88.3l1.2 1.2M274.9 80.7l-1.2 1.2M274.9 85.8l-1.2 1.2M274.9 95.9l-1.2 1.2M274.9 93.4l-1.2 1.2M274.9 83.2l-1.2 1.2M274.9 98.5l-1.2 1.2M274.9 90.8l-1.2 1.2M274.9 88.3l-1.2 1.2"/>
<path d="M273.7 108.6l1.2 1.2M273.7 116.2l1.2 1.2M273.7 111.2l1.2 1.2M273.7 118.8l1.2 1.2M273.7 113.7l1.2 1.2M273.7 103.5l1.2 1.2M273.7 101l1.2 1.2M273.7 106.1l1.2 1.2M274.9 108.6l-1.2 1.2M274.9 116.2l-1.2 1.2M274.9 111.2l-1.2 1.2M274.9 118.8l-1.2 1.2"/>
<path d="M274.9 113.7l-1.2 1.2M274.9 103.5l-1.2 1.2M274.9 101l-1.2 1.2M274.9 106.1l-1.2 1.2M273.7 128.9l1.2 1.2M273.7 121.3l1.2 1.2M273.7 139.1l1.2 1.2M273.7 131.5l1.2 1.2M273.7 126.4l1.2 1.2M273.7 136.6l1.2 1.2M273.7 123.9l1.2 1.2M273.7 134l1.2 1.2"/>
<path d="M274.9 128.9l-1.2 1.2M274.9 121.3l-1.2 1.2M274.9 139.1l-1.2 1.2M274.9 131.5l-1.2 1.2M274.9 126.4l-1.2 1.2M274.9 136.6l-1.2 1.2M274.9 123.9l-1.2 1.2M274.9 134l-1.2 1.2M107.1 148h.3v1.8h-.3M107.7 145.4h.4v1.8h-.4M109.3 142.9h.3v1.8h-.3M110.5 150.5h.3v1.8h-.3"/>
<path d="M129.2 149v1.9h-.3M129.8 146.5v1.8h-.3M131.1 144h.3v1.8h-.3M132.2 151.6h.4v1.8h-.4M273.7 154.3l1.2 1.2M273.7 149.3l1.2 1.2M273.7 159.4l1.2 1.2M273.7 151.8l1.2 1.2M273.7 141.6l1.2 1.2M273.7 144.2l1.2 1.2M273.7 146.7l1.2 1.2M273.7 156.9l1.2 1.2"/>
<path d="M274.9 154.3l-1.2 1.2M274.9 149.3l-1.2 1.2M274.9 159.4l-1.2 1.2M274.9 151.8l-1.2 1.2M274.9 141.6l-1.2 1.2M274.9 144.2l-1.2 1.2M274.9 146.7l-1.2 1.2M274.9 156.9l-1.2 1.2M179.7 162l1.2 1.2M180.9 162l-1.2 1.2M273.7 162l1.2 1.2M274.9 162l-1.2 1.2"/>
</g>
<path d="M71.1 25.4h20.3M208.3 35.6h-5.1v60.9M203.2 104.1v61h5.1M96.5 144.8h20.3M96.5 152.4h20.3M96.5 147.3h20.3M96.5 149.9h20.3" fill="none" stroke="#000084" stroke-width=".25"/>
<g fill="none" stroke="#008400" stroke-width=".18">
<path d="M88.9 35.6v2.5M66 53.3h28M66 48.3h15.3M66 45.7h15.3M66 40.6h15.3M66 43.2h15.3M66 58.4h15.3M66 55.9h15.3M88.9 48.3v2.5h-22.9M180.3 48.3h2.6M180.3 45.7h2.6M180.3 40.6h2.6"/>
<path d="M180.3 43.2h2.6M203.2 50.8l-2.5 2.5h-20.4M203.2 48.3l-2.5 2.5h-20.4M203.2 55.9l-2.5 2.5h-20.4M203.2 53.3l-2.5 2.6h-20.4M203.2 58.4l-2.5 2.6h-20.4M66 73.7h15.3M66 68.6h15.3M66 78.7h38.1M66 63.5h15.3M66 66h17.8M66 71.1h15.3"/>
<path d="M66 76.2h15.3M203.2 71.1l-2.5 2.6h-20.4M203.2 66l-2.5 2.6h-20.4M203.2 76.2l-2.5 2.5h-20.4M203.2 61l-2.5 2.5h-20.4M203.2 63.5l-2.5 2.5h-20.4M203.2 68.6l-2.5 2.5h-20.4M203.2 78.7l-2.5 2.6h-20.4M203.2 73.7l-2.5 2.5h-20.4M66 88.9h17.8M66 83.8h15.3M66 86.4h15.3"/>
<path d="M66 91.4h38.1M66 81.3h15.3M66 94h15.3M66 99.1h17.8M66 96.5h17.8M203.2 86.4l-2.5 2.5h-20.4M203.2 81.3l-2.5 2.5h-20.4M203.2 83.8l-2.5 2.6h-20.4M203.2 88.9l-2.5 2.5h-20.4M203.2 91.4l-2.5 2.6h-20.4M203.2 96.5l-2.5 2.6h-20.4M203.2 94l-2.5 2.5h-20.4"/>
<path d="M66 119.4h17.8M66 104.1h17.8M66 109.2h15.3M66 101.6h17.8M66 106.7h17.8M66 111.8h17.8M66 116.8h17.8M66 114.3h22.9M99.1 111.8v2.5M104.1 111.8v2.5M180.3 119.4h20.4l2.5 2.5M180.3 104.1h20.4l2.5 2.6"/>
<path d="M180.3 109.2h20.4l2.5 2.6M180.3 101.6h20.4l2.5 2.5M180.3 106.7h20.4l2.5 2.5M180.3 111.8h20.4l2.5 2.5M180.3 116.8h20.4l2.5 2.6M180.3 114.3h20.4l2.5 2.5M66 129.5h48.3M66 134.6h17.8M66 124.5h17.8M66 127h48.3M66 121.9h17.8M66 139.7h17.8"/>
<path d="M66 137.2h17.8M66 132.1h17.8M99.1 124.5v2.5M101.6 127v5.1M104.1 124.5v5M106.7 129.5v2.6M180.3 129.5h20.4l2.5 2.6M180.3 134.6h20.4l2.5 2.6M180.3 124.5h20.4l2.5 2.5M180.3 127h20.4l2.5 2.5M180.3 121.9h20.4l2.5 2.6M180.3 139.7h20.4l2.5 2.5"/>
<path d="M180.3 137.2h20.4l2.5 2.5M180.3 132.1h20.4l2.5 2.5M66 142.2h15.3M66 154.9h15.3M66 157.5h17.8M66 152.4h15.3M66 149.9h17.8M66 144.8h15.3M66 147.3h17.8M180.3 142.2h20.4l2.5 2.6M180.3 154.9h20.4l2.5 2.6M180.3 157.5h20.4l2.5 2.5"/>
<path d="M180.3 152.4h20.4l2.5 2.5M180.3 149.9h20.4l2.5 2.5M180.3 144.8h20.4l2.5 2.5M180.3 147.3h20.4l2.5 2.6M66 160h17.8M66 162.6h17.8M76.2 177.8v2.5h-2.5M104.1 177.8v2.5h-2.5M132.1 177.8v2.5h-2.6M180.3 160h20.4l2.5 2.6M53.3 182.9h7.7M63.5 180.3h-2.5v5.1h2.5"/>
<path d="M73.7 185.4h2.5v2.6M81.3 182.9h7.6M91.4 180.3h-2.5v5.1h2.5M101.6 185.4h2.5v2.6M109.2 182.9h7.6M119.4 180.3h-2.6v5.1h2.6M129.5 185.4h2.6v2.6"/>
</g>
<path d="M20.7 30.6l.1 .2M43.9 30.8h.7M44.1 29.7l-.2 .2M47.3 30.7l.4 .1M47.8 29.5h-.3l-.2 .3 .1 .3 .3 .1M55.6 29.4a1.46 1.46 0 0 0 0 1.9M63.2 30.2l.6-.1 .2-.1-.1-.3-.7-.2v1.3M219.4 56.1v.1M219.4 54.9v.8M220.3 71.3v.1M220.3 70.2v.8" fill="none" stroke="#0000c2" stroke-width=".18"/>
<path d="M16.9 15.1h-1v1.9M18.6 15.2l-.3-.1h-.7v1.9M20.5 15.2a.69 .69 0 0 0-.9 .1M21.1 17l.6-1.9 .7 1.9M24.5 15.1v1.9M25.4 15.3a.65 .65 0 0 1 1.1 0M28.8 16h.7M29.7 15.2l-.2-.1h-.7v1.9h.8M34.2 15.1v1.9" fill="none" stroke="#0000c2" stroke-width=".38"/>
<path d="M118.3 103.6h.4M118.4 103.2v1.1l.3 .2M121.3 103.2l.4 .9 .4-.9v1.3M131.5 103.6v.9M131.9 103.6l-.4 .1" fill="none" stroke="#0000c2" stroke-width=".25"/>
<g fill="#008400" stroke="#008400" stroke-width=".18">
<circle cx="88.9" cy="53.3" r=".46"/>
<circle cx="88.9" cy="182.9" r=".46"/>
<circle cx="61" cy="182.9" r=".46"/>
<circle cx="99.1" cy="127" r=".46"/>
<circle cx="104.1" cy="129.5" r=".46"/>
<circle cx="99.1" cy="91.4" r=".46"/>
<circle cx="99.1" cy="78.7" r=".46"/>
<circle cx="101.6" cy="127" r=".46"/>
<circle cx="106.7" cy="129.5" r=".46"/>
<circle cx="116.8" cy="182.9" r=".46"/>
</g>
<use href="#words"/>
</svg>
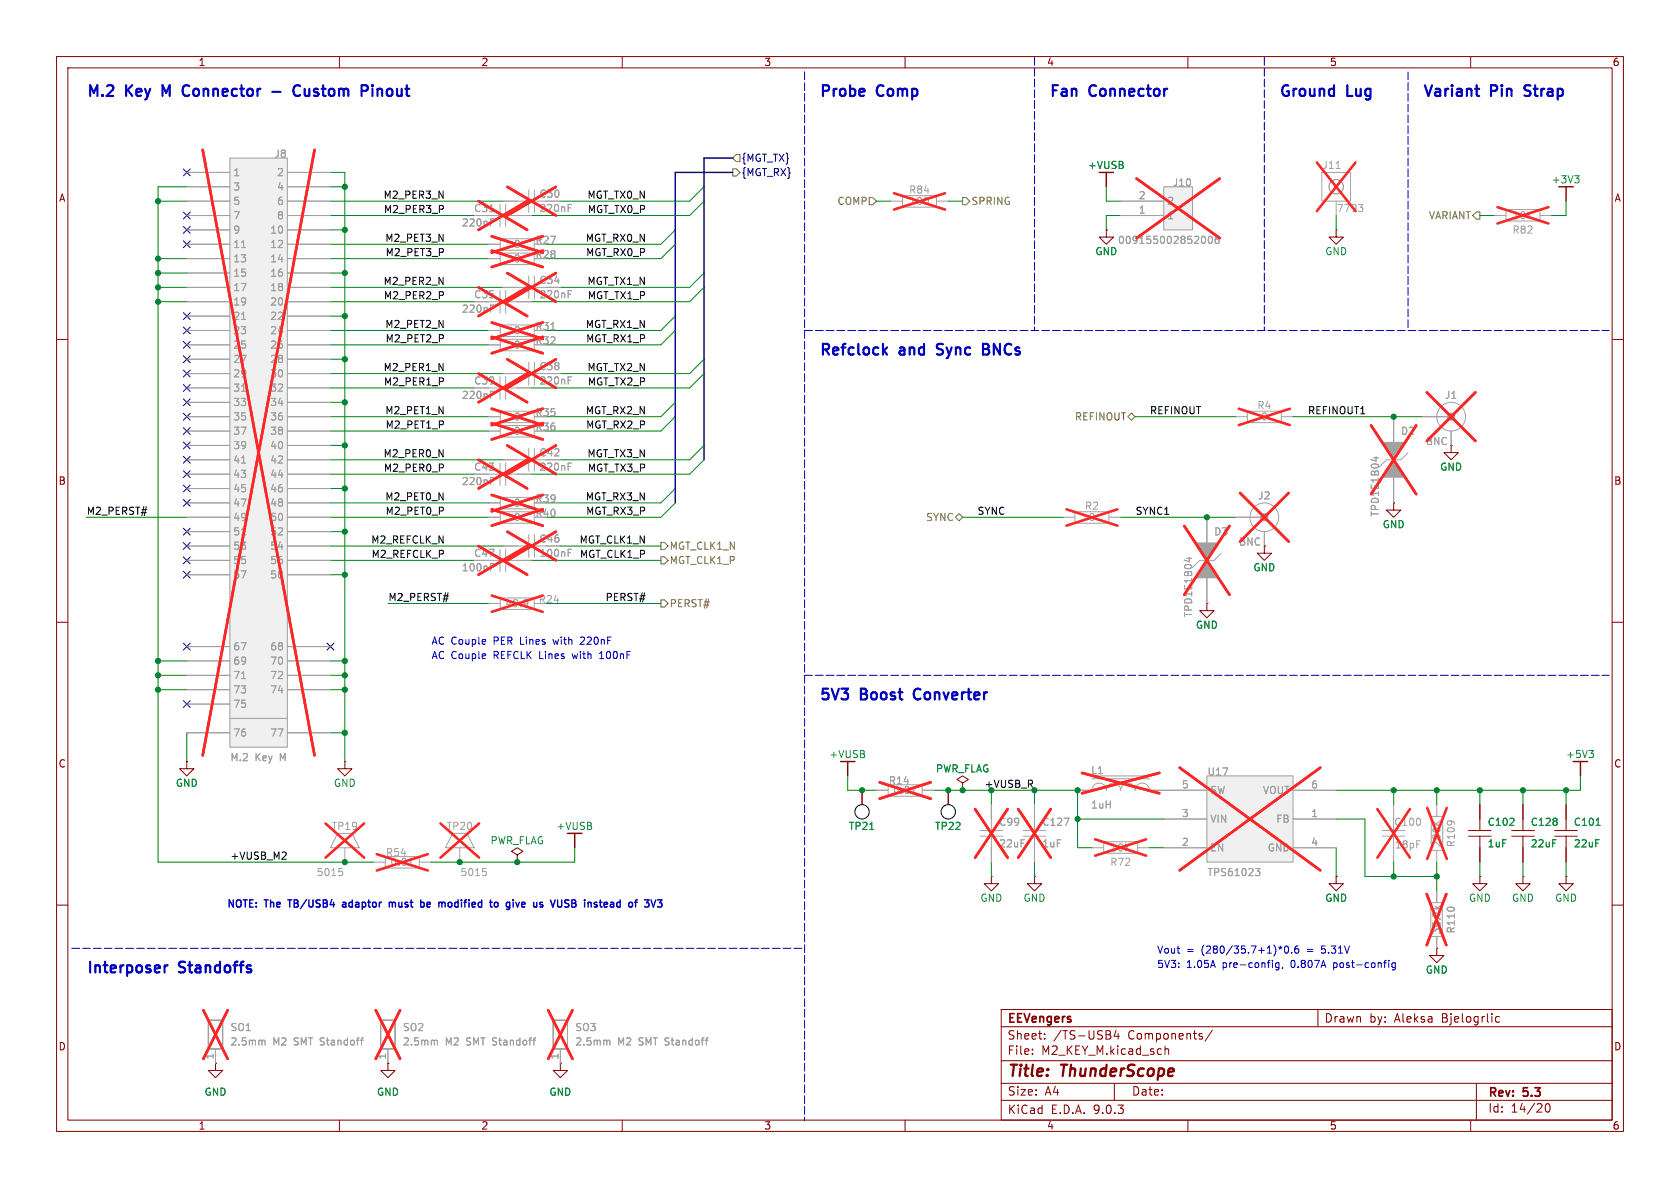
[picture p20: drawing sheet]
<svg xmlns="http://www.w3.org/2000/svg" width="297mm" height="210mm" viewBox="0 0 297 210" stroke-linecap="round" stroke-linejoin="round" font-family="sans-serif">
<defs><g id="words">
<g font-size="2.8" fill="#840000">
<text x="178" y="190.9">Title:</text>
<text x="187.7" y="190.9">ThunderScope</text>
</g>
<g font-size="2.7" fill="#0000c2">
<text x="15.2" y="18">M.2</text>
<text x="22.4" y="18">Key</text>
<text x="29.6" y="18">M</text>
<text x="33.9" y="18">Connector</text>
<text x="55.1" y="18">Custom</text>
<text x="67.8" y="18">Pinout</text>
<text x="144.8" y="18">Probe</text>
<text x="155.2" y="18">Comp</text>
<text x="185.4" y="18">Fan</text>
<text x="192.7" y="18">Connector</text>
<text x="226.1" y="18">Ground</text>
<text x="238.3" y="18">Lug</text>
<text x="251.5" y="18">Variant</text>
<text x="263.7" y="18">Pin</text>
<text x="270.4" y="18">Strap</text>
<text x="144.8" y="63.8">Refclock</text>
<text x="159.1" y="63.8">and</text>
<text x="166.5" y="63.8">Sync</text>
<text x="175.4" y="63.8">BNCs</text>
<text x="144.8" y="124.7">5V3</text>
<text x="152.3" y="124.7">Boost</text>
<text x="162.5" y="124.7">Converter</text>
<text x="15.2" y="173">Interposer</text>
<text x="31.8" y="173">Standoffs</text>
</g>
<g font-size="2.1" fill="#840000">
<text x="178" y="184">Sheet:</text>
<text x="178" y="181.2">EEVengers</text>
<text x="186.2" y="184">/TS-USB4</text>
<text x="199.5" y="184">Components/</text>
<text x="234.1" y="181">Drawn</text>
<text x="242.1" y="181">by:</text>
<text x="246.6" y="181">Aleksa</text>
<text x="255" y="181">Bjelogrlic</text>
<text x="178" y="186.7">File:</text>
<text x="184.1" y="186.7">M2_KEY_M.kicad_sch</text>
<text x="178.1" y="197.1">KiCad</text>
<text x="178.1" y="193.9">Size:</text>
<text x="184.7" y="193.9">A4</text>
<text x="185.8" y="197.1">E.D.A.</text>
<text x="193.4" y="197.1">9.0.3</text>
<text x="200" y="193.9">Date:</text>
<text x="263" y="194.3">Rev:</text>
<text x="263" y="196.9">Id:</text>
<text x="267.1" y="196.9">14/20</text>
<text x="269.4" y="194.3">5.3</text>
</g>
<g font-size="1.8" fill="#840000">
<text x="35" y="11.9">1</text>
<text x="85" y="11.9">2</text>
<text x="135" y="11.9">3</text>
<text x="185" y="11.9">4</text>
<text x="235" y="11.9">5</text>
<text x="285" y="11.9">6</text>
<text x="10.3" y="35.9">A</text>
<text x="285.3" y="35.9">A</text>
<text x="10.3" y="85.9">B</text>
<text x="285.3" y="85.9">B</text>
<text x="10.3" y="135.9">C</text>
<text x="285.3" y="135.9">C</text>
<text x="10.3" y="185.9">D</text>
<text x="285.3" y="185.9">D</text>
<text x="35" y="199.9">1</text>
<text x="85" y="199.9">2</text>
<text x="135" y="199.9">3</text>
<text x="185" y="199.9">4</text>
<text x="235" y="199.9">5</text>
<text x="285" y="199.9">6</text>
</g>
<g font-size="1.8" fill="#a1a1a1">
<text x="48.4" y="28.1">J8</text>
<text x="41.1" y="31.3">1</text>
<text x="41.1" y="33.9">3</text>
<text x="48.9" y="31.3">2</text>
<text x="48.9" y="33.9">4</text>
<text x="95.3" y="35.2">C30</text>
<text x="160.6" y="34.4">R84</text>
<text x="201.2" y="35.3">2</text>
<text x="207.2" y="33.2">J10</text>
<text x="233.7" y="30.1">J11</text>
<text x="41.1" y="36.4">5</text>
<text x="41.1" y="39">7</text>
<text x="41.1" y="41.5">9</text>
<text x="47.7" y="41.5">10</text>
<text x="48.9" y="36.4">6</text>
<text x="48.9" y="39">8</text>
<text x="81.6" y="40.2">220nF</text>
<text x="83.7" y="37.7">C31</text>
<text x="95.3" y="37.7">220nF</text>
<text x="160.6" y="36.4">100</text>
<text x="201.2" y="37.8">1</text>
<text x="206.2" y="36.4">2</text>
<text x="206.2" y="39">1</text>
<text x="236.2" y="37.7">7793</text>
<text x="267.3" y="41.5">R82</text>
<text x="267.3" y="39">10K</text>
<text x="41.1" y="44">11</text>
<text x="41.1" y="46.6">13</text>
<text x="47.7" y="44">12</text>
<text x="47.7" y="46.6">14</text>
<text x="90.7" y="46.6">0</text>
<text x="90.7" y="44">0</text>
<text x="94.6" y="45.9">R28</text>
<text x="94.6" y="43.3">R27</text>
<text x="197.5" y="43.3">009155002852006</text>
<text x="41.1" y="49.1">15</text>
<text x="41.1" y="51.7">17</text>
<text x="47.7" y="49.1">16</text>
<text x="47.7" y="51.7">18</text>
<text x="83.7" y="52.9">C35</text>
<text x="95.3" y="52.9">220nF</text>
<text x="95.3" y="50.4">C34</text>
<text x="41.1" y="54.2">19</text>
<text x="41.1" y="56.7">21</text>
<text x="41.1" y="59.3">23</text>
<text x="47.7" y="54.2">20</text>
<text x="47.7" y="56.7">22</text>
<text x="47.7" y="59.3">24</text>
<text x="81.6" y="55.5">220nF</text>
<text x="90.7" y="59.3">0</text>
<text x="94.6" y="58.6">R31</text>
<text x="41.1" y="61.8">25</text>
<text x="41.1" y="64.4">27</text>
<text x="47.7" y="61.8">26</text>
<text x="47.7" y="64.4">28</text>
<text x="90.7" y="61.8">0</text>
<text x="94.6" y="61.1">R32</text>
<text x="95.3" y="65.6">C38</text>
<text x="41.1" y="66.9">29</text>
<text x="41.1" y="69.4">31</text>
<text x="41.1" y="72">33</text>
<text x="47.7" y="66.9">30</text>
<text x="47.7" y="69.4">32</text>
<text x="47.7" y="72">34</text>
<text x="81.6" y="70.7">220nF</text>
<text x="83.7" y="68.2">C39</text>
<text x="95.3" y="68.2">220nF</text>
<text x="255.3" y="70.7">J1</text>
<text x="41.1" y="74.5">35</text>
<text x="41.1" y="77.1">37</text>
<text x="47.7" y="74.5">36</text>
<text x="47.7" y="77.1">38</text>
<text x="90.7" y="77.1">0</text>
<text x="90.7" y="74.5">0</text>
<text x="94.6" y="76.3">R36</text>
<text x="94.6" y="73.8">R35</text>
<text x="222.2" y="72.5">R4</text>
<text x="222.8" y="74.5">0</text>
<text x="247.6" y="77.1">D2</text>
<text x="41.1" y="79.6">39</text>
<text x="41.1" y="82.1">41</text>
<text x="47.7" y="79.6">40</text>
<text x="47.7" y="82.1">42</text>
<text x="83.7" y="83.4">C43</text>
<text x="95.3" y="83.4">220nF</text>
<text x="95.3" y="80.9">C42</text>
<text x="252" y="78.9">BNC</text>
<text x="41.1" y="84.7">43</text>
<text x="41.1" y="87.2">45</text>
<text x="41.1" y="89.8">47</text>
<text x="47.7" y="84.7">44</text>
<text x="47.7" y="87.2">46</text>
<text x="47.7" y="89.8">48</text>
<text x="81.6" y="86">220nF</text>
<text x="90.7" y="89.8">0</text>
<text x="94.6" y="89">R39</text>
<text x="222.3" y="88.5">J2</text>
<text x="41.1" y="92.3">49</text>
<text x="41.1" y="94.8">51</text>
<text x="47.7" y="92.3">50</text>
<text x="47.7" y="94.8">52</text>
<text x="90.7" y="92.3">0</text>
<text x="94.6" y="91.6">R40</text>
<text x="191.7" y="90.3">R2</text>
<text x="192.3" y="92.3">0</text>
<text x="214.6" y="94.8">D3</text>
<text x="244" y="91.4" transform="rotate(-90 244 91.4)">TPD1E1B04</text>
<text x="41.1" y="97.4">53</text>
<text x="41.1" y="99.9">55</text>
<text x="47.7" y="97.4">54</text>
<text x="47.7" y="99.9">56</text>
<text x="81.6" y="101.2">100nF</text>
<text x="83.7" y="98.7">C47</text>
<text x="95.3" y="98.7">100nF</text>
<text x="95.3" y="96.1">C46</text>
<text x="218.9" y="96.7">BNC</text>
<text x="41.1" y="102.5">57</text>
<text x="47.7" y="102.5">58</text>
<text x="89.2" y="107.5">49.9</text>
<text x="95.2" y="106.8">R24</text>
<text x="211" y="109.2" transform="rotate(-90 211 109.2)">TPD1E1B04</text>
<text x="41.1" y="115.2">67</text>
<text x="41.1" y="117.7">69</text>
<text x="47.7" y="115.2">68</text>
<text x="47.7" y="117.7">70</text>
<text x="41.1" y="120.2">71</text>
<text x="41.1" y="122.8">73</text>
<text x="41.1" y="125.3">75</text>
<text x="47.7" y="120.2">72</text>
<text x="47.7" y="122.8">74</text>
<text x="41.1" y="130.4">76</text>
<text x="47.7" y="130.4">77</text>
<text x="40.6" y="134.8">M.2</text>
<text x="45.1" y="134.8">Key</text>
<text x="49.6" y="134.8">M</text>
<text x="192.8" y="137">L1</text>
<text x="213.4" y="137.3">U17</text>
<text x="157" y="138.9">R14</text>
<text x="157.8" y="140.6">0.01</text>
<text x="192.8" y="143.1">1uH</text>
<text x="208.8" y="139.4">5</text>
<text x="213.9" y="140.6">SW</text>
<text x="223.2" y="140.6">VOUT</text>
<text x="231.7" y="139.4">6</text>
<text x="58.5" y="146.9">TP19</text>
<text x="78.9" y="146.9">TP20</text>
<text x="176.5" y="146.2">C99</text>
<text x="176.5" y="150">22uF</text>
<text x="184.2" y="146.2">C127</text>
<text x="184.2" y="150">1uF</text>
<text x="208.8" y="144.5">3</text>
<text x="208.8" y="149.6">2</text>
<text x="213.9" y="145.6">VIN</text>
<text x="225.5" y="145.6">FB</text>
<text x="231.7" y="144.5">1</text>
<text x="231.7" y="149.6">4</text>
<text x="246.4" y="146.2">C100</text>
<text x="254.9" y="149.9" transform="rotate(-90 254.9 149.9)">280K</text>
<text x="257.4" y="149.9" transform="rotate(-90 257.4 149.9)">R109</text>
<text x="55.9" y="155.1">5015</text>
<text x="68.1" y="151.6">R54</text>
<text x="68.9" y="153.3">0.01</text>
<text x="81.3" y="155.1">5015</text>
<text x="196.2" y="153.3">R72</text>
<text x="196.2" y="150.7">10K</text>
<text x="213.4" y="155.1">TPS61023</text>
<text x="213.9" y="150.7">EN</text>
<text x="224" y="150.7">GND</text>
<text x="246.5" y="150.2">18pF</text>
<text x="254.9" y="165.3" transform="rotate(-90 254.9 165.3)">35.7k</text>
<text x="257.4" y="165.1" transform="rotate(-90 257.4 165.1)">R110</text>
<text x="40.6" y="182.5">SO1</text>
<text x="40.6" y="185">2.5mm</text>
<text x="48.2" y="185">M2</text>
<text x="52.1" y="185">SMT Standoff</text>
<text x="71.1" y="182.5">SO2</text>
<text x="71.1" y="185">2.5mm</text>
<text x="78.7" y="185">M2</text>
<text x="82.5" y="185">SMT Standoff</text>
<text x="101.6" y="182.5">SO3</text>
<text x="101.6" y="185">2.5mm</text>
<text x="109.2" y="185">M2</text>
<text x="113" y="185">SMT Standoff</text>
<text x="37.8" y="187.4" transform="rotate(-90 37.8 187.4)">1</text>
<text x="68.3" y="187.4" transform="rotate(-90 68.3 187.4)">1</text>
<text x="98.8" y="187.4" transform="rotate(-90 98.8 187.4)">1</text>
</g>
<g font-size="1.8" fill="#000084">
<text x="131" y="28.8">{MGT_TX}</text>
<text x="131" y="31.3">{MGT_RX}</text>
</g>
<g font-size="1.8">
<text x="67.7" y="35.2">M2_PER3_N</text>
<text x="103.8" y="35.2">MGT_TX0_N</text>
<text x="67.8" y="37.8">M2_PER3_P</text>
<text x="103.8" y="37.8">MGT_TX0_P</text>
<text x="68" y="42.8">M2_PET3_N</text>
<text x="68.1" y="45.4">M2_PET3_P</text>
<text x="103.5" y="42.8">MGT_RX0_N</text>
<text x="103.5" y="45.4">MGT_RX0_P</text>
<text x="67.7" y="50.5">M2_PER2_N</text>
<text x="67.8" y="53">M2_PER2_P</text>
<text x="103.8" y="50.5">MGT_TX1_N</text>
<text x="103.8" y="53">MGT_TX1_P</text>
<text x="68" y="58.1">M2_PET2_N</text>
<text x="103.5" y="58.1">MGT_RX1_N</text>
<text x="67.7" y="65.7">M2_PER1_N</text>
<text x="68.1" y="60.6">M2_PET2_P</text>
<text x="103.5" y="60.6">MGT_RX1_P</text>
<text x="103.8" y="65.7">MGT_TX2_N</text>
<text x="67.8" y="68.2">M2_PER1_P</text>
<text x="103.8" y="68.2">MGT_TX2_P</text>
<text x="68" y="73.3">M2_PET1_N</text>
<text x="68.1" y="75.9">M2_PET1_P</text>
<text x="103.5" y="73.3">MGT_RX2_N</text>
<text x="103.5" y="75.9">MGT_RX2_P</text>
<text x="203.2" y="73.3">REFINOUT</text>
<text x="231.1" y="73.3">REFINOUT1</text>
<text x="67.7" y="80.9">M2_PER0_N</text>
<text x="67.8" y="83.5">M2_PER0_P</text>
<text x="103.8" y="80.9">MGT_TX3_N</text>
<text x="103.8" y="83.5">MGT_TX3_P</text>
<text x="68" y="88.6">M2_PET0_N</text>
<text x="103.5" y="88.6">MGT_RX3_N</text>
<text x="15.2" y="91.1">M2_PERST#</text>
<text x="68.1" y="91.1">M2_PET0_P</text>
<text x="103.5" y="91.1">MGT_RX3_P</text>
<text x="172.7" y="91.1">SYNC</text>
<text x="200.7" y="91.1">SYNC1</text>
<text x="65.5" y="96.2">M2_REFCLK_N</text>
<text x="65.6" y="98.7">M2_REFCLK_P</text>
<text x="102.4" y="96.2">MGT_CLK1_N</text>
<text x="102.4" y="98.7">MGT_CLK1_P</text>
<text x="68.6" y="106.3">M2_PERST#</text>
<text x="107" y="106.3">PERST#</text>
<text x="40.6" y="152.1">+VUSB_M2</text>
</g>
<g font-size="1.8" fill="#008484">
<text x="192.2" y="30.1">+VUSB</text>
<text x="274.2" y="32.6">+3V3</text>
<text x="193.5" y="45.3">GND</text>
<text x="234.2" y="45.3">GND</text>
<text x="254.5" y="83.4">GND</text>
<text x="244.3" y="93.6">GND</text>
<text x="221.5" y="101.2">GND</text>
<text x="211.3" y="111.4">GND</text>
<text x="146.5" y="134.2">+VUSB</text>
<text x="165.4" y="136.8">PWR_FLAG</text>
<text x="276.8" y="134.2">+5V3</text>
<text x="31" y="139.3">GND</text>
<text x="58.9" y="139.3">GND</text>
<text x="86.6" y="149.5">PWR_FLAG</text>
<text x="98.3" y="146.9">+VUSB</text>
<text x="150" y="146.9">TP21</text>
<text x="165.2" y="146.9">TP22</text>
<text x="262.9" y="146.2">C102</text>
<text x="262.9" y="150">1uF</text>
<text x="270.5" y="146.2">C128</text>
<text x="270.5" y="150">22uF</text>
<text x="278.1" y="146.2">C101</text>
<text x="278.1" y="150">22uF</text>
<text x="173.2" y="159.6">GND</text>
<text x="180.8" y="159.6">GND</text>
<text x="234.2" y="159.6">GND</text>
<text x="259.6" y="159.6">GND</text>
<text x="267.2" y="159.6">GND</text>
<text x="274.8" y="159.6">GND</text>
<text x="252" y="172.3">GND</text>
<text x="36.1" y="193.9">GND</text>
<text x="66.5" y="193.9">GND</text>
<text x="97" y="193.9">GND</text>
</g>
<g font-size="1.8" fill="#848400">
<text x="148" y="36.4">COMP</text>
<text x="171.6" y="36.4">SPRING</text>
<text x="252.5" y="39">VARIANT</text>
<text x="189.9" y="74.5">REFINOUT</text>
<text x="163.6" y="92.3">SYNC</text>
<text x="118.3" y="97.4">MGT_CLK1_N</text>
<text x="118.3" y="99.9">MGT_CLK1_P</text>
<text x="118.3" y="107.5">PERST#</text>
</g>
<g font-size="1.8" fill="#0000c2">
<text x="76.2" y="114.1">AC Couple</text>
<text x="76.2" y="116.6">AC Couple</text>
<text x="87.4" y="114.1">PER Lines</text>
<text x="87.4" y="116.6">REFCLK</text>
<text x="95.6" y="116.6">Lines</text>
<text x="98.3" y="114.1">with</text>
<text x="101.7" y="116.6">with</text>
<text x="103.3" y="114.1">220nF</text>
<text x="106.7" y="116.6">100nF</text>
<text x="40" y="160.8">NOTE:</text>
<text x="46.8" y="160.8">The</text>
<text x="51.5" y="160.8">TB/USB4</text>
<text x="61.6" y="160.8">adaptor</text>
<text x="70.3" y="160.8">must</text>
<text x="76.4" y="160.8">be</text>
<text x="80.1" y="160.8">modified</text>
<text x="89.7" y="160.8">to</text>
<text x="93.1" y="160.8">give</text>
<text x="98.4" y="160.8">us</text>
<text x="102" y="160.8">VUSB</text>
<text x="108.4" y="160.8">instead</text>
<text x="116.8" y="160.8">of</text>
<text x="204.5" y="171.2">5V3:</text>
<text x="204.5" y="168.7">Vout</text>
<text x="209.8" y="168.7">=</text>
<text x="209.8" y="171.2">1.05A</text>
<text x="212.5" y="168.7">(280/35.7+1)*0.6</text>
<text x="216.3" y="171.2">pre-config,</text>
<text x="228.5" y="171.2">0.807A</text>
<text x="231.4" y="168.7">=</text>
<text x="234.1" y="168.7">5.31V</text>
<text x="236.3" y="171.2">post-config</text>
</g>
<text font-size="1.8" fill="#008400" x="174" y="139.4">+VUSB_R</text>
</g></defs>
<path d="M0 0h297v210h-297z" fill="#fff" stroke="#fff" stroke-width=".18"/>
<g fill="none" stroke="#840000" stroke-width=".18">
<path d="M10 10h277v190h-277zM12 12h273v186h-273zM60 10v2M110 10v2M160 10v2M210 10v2M260 10v2M10 60h2M285 60h2M10 110h2M285 110h2M10 160h2"/>
<path d="M177 178.5h108v19.5h-108zM233 178.5v3M265.1 179.8l-.4-.1-.3 .3v.4l.1 .2h.6M285 160h2M60 198v2M110 198v2M160 198v2M177 194.5h108M177 191.5h108M177 187.5h108M177 181.5h108M182.5 186.3v.1"/>
<path d="M182.5 185.5v.1M184.7 183.6v.1M184.7 182.8v.1M196.2 183l.2 .2-.2 .4M196.2 182.3v.5M197 191.5v3M197.3 182.1l-.3 1.1h.9M197.7 182.7v1M206 184.9v1.5M206 185.5l.2-.1 .3 .1 .1 .9M210 198v2M214.3 182.1l-1.3 2"/>
<path d="M260 198v2M261 191.5v6.5M273.3 195.2l.2-.1a.81 .81 0 0 1 .6 .6 .81 .81 0 0 1-.3 .8l-.1 .1a.81 .81 0 0 1-.4-1.4z"/>
</g>
<g fill="none" stroke="#a1a1a1" stroke-width=".18">
<path d="M86.4 53.3h2M86.7 54.5h.5M86.7 53.9h.6M88.4 51.3v4M88.9 50.8h4.6M89.4 51.3v4M89.4 53.3h4.6M93.5 48.8v4M94.5 48.8v4M94.5 50.8h2M100.4 52h.5M100.4 51.4h.6"/>
<path d="M86.4 68.6h2M86.4 76.2h2M86.7 69.8h.5M86.7 69.2h.6M88.4 66.6v4M88.4 75.2h6v2.1h-6zM88.9 66h4.6M89.4 66.6v4M89.4 68.6h4.6M93.5 64v4M94.5 64v4M94.5 66h4.6"/>
<path d="M100.4 67.2h.5M100.4 66.6h.6M251.5 73.7h5M256.5 76.2v2.5"/>
<circle cx="256.5" cy="73.7" r="2.54"/>
</g>
<path d="M84.6 50.8l8.6 5.1M89.7 48.3l8.6 5M93.2 50.8l-8.6 5.1M98.3 48.3l-8.6 5M84.6 66.1l8.6 5M86.9 74.8l9 2.9M89.7 63.5l8.6 5.1M93.2 66.1l-8.6 5M95.9 74.8l-9 2.9M98.3 63.5l-8.6 5.1M252.2 69.4l8.6 8.6M260.8 69.4l-8.6 8.6" fill="none" stroke="#ff2626" stroke-width=".46"/>
<circle cx="256.5" cy="73.7" r=".63" fill="#a1a1a1" stroke="#a1a1a1" stroke-width=".18"/>
<path d="M40.6 27.9h10.2v104.2h-10.2z" fill="#f0f0f0"/>
<path d="M40.6 27.9h10.2v104.2h-10.2z" fill="none" stroke="#9f9f9f" stroke-width=".18"/>
<g fill="none" stroke="#a1a1a1" stroke-width=".18">
<path d="M33 30.5h7.6M33 33h7.6M33 35.6h7.6M33 38.1h7.6M50.8 30.5h7.6M50.8 33h7.6M50.8 35.6h7.6M50.8 38.1h7.6M33 40.6h7.6M33 43.2h7.6M33 45.7h7.6M33 48.3h7.6"/>
<path d="M33 50.8h7.6M33 53.3h7.6M33 55.9h7.6M33 58.4h7.6M42.7 43.8h.7M42.7 56.5h.7M50.8 40.6h7.6M50.8 43.2h7.6M50.8 45.7h7.6M50.8 48.3h7.6M50.8 50.8h7.6M50.8 53.3h7.6"/>
<path d="M50.8 55.9h7.6M50.8 58.4h7.6M86.4 45.7h2M86.4 58.4h2M88.4 60h6v2h-6zM88.4 44.7h6v2.1h-6zM88.4 57.4h6v2.1h-6zM97.4 58.3h.7M33 61h7.6M33 63.5h7.6M33 66h7.6M33 68.6h7.6"/>
<path d="M33 71.1h7.6M33 73.7h7.6M33 76.2h7.6M33 78.7h7.6M42.7 69.2h.7M50.8 61h7.6M50.8 63.5h7.6M50.8 66h7.6M50.8 68.6h7.6M50.8 71.1h7.6M50.8 73.7h7.6M50.8 76.2h7.6"/>
<path d="M50.8 78.7h7.6M86.4 61h2M86.4 73.7h2M88.4 72.7h6v2h-6zM33 81.3h7.6M33 83.8h7.6M33 86.4h7.6M33 88.9h7.6M33 91.4h7.6M33 94h7.6M33 96.5h7.6M33 99.1h7.6"/>
<path d="M42.7 81.9h.7M42.7 94.6h.7M50.8 81.3h7.6M50.8 83.8h7.6M50.8 86.4h7.6M50.8 88.9h7.6M50.8 91.4h7.6M50.8 94h7.6M50.8 96.5h7.6M50.8 99.1h7.6M86.4 99.1h2M86.7 99.6h.6"/>
<path d="M88.4 97.1v4M89.4 99.1h4.6M89.4 97.1v4M33 101.6h7.6M33 114.3h7.6M33 116.8h7.6M33 119.4h7.6M42.7 120h.7M50.8 101.6h7.6M50.8 114.3h7.6M50.8 116.8h7.6M50.8 119.4h7.6"/>
<path d="M86.4 106.7h2M86.7 100.2h.5M88.4 105.7h6v2h-6zM93.2 106.1h.1a1.07 1.07 0 0 1-.2 1M93.3 106.5l-.1 .2M94.5 106.7h2M33 121.9h7.6M33 129.5h7.6M33 124.5h7.6M40.6 127h10.2M50.8 121.9h7.6M50.8 129.5h7.6"/>
</g>
<g fill="none" stroke="#ff2626" stroke-width=".46">
<path d="M35.8 26.5l19.8 107M55.6 26.5l-19.8 107M86.9 59.6l9 2.8M86.9 44.3l9 2.9M86.9 57l9 2.9M95.9 59.6l-9 2.8M95.9 44.3l-9 2.9M95.9 57l-9 2.9M86.9 72.3l9 2.8M95.9 72.3l-9 2.8M84.6 96.5l8.6 5.1M93.2 96.5l-8.6 5.1"/>
<path d="M86.9 105.3l9 2.9M95.9 105.3l-9 2.9"/>
</g>
<path d="M205.7 33h5.1v7.6h-5.1z" fill="#f0f0f0"/>
<path d="M205.7 33h5.1v7.6h-5.1z" fill="none" stroke="#9f9f9f" stroke-width=".18"/>
<g fill="none" stroke="#a1a1a1" stroke-width=".18">
<path d="M86.4 38.1h2M86.6 37.4h.7M86.7 39.3h.5M86.7 38.7h.6M88.4 36.1v4M88.9 35.6h4.6M89.4 38.1h4.6M89.4 36.1v4M93.5 33.6v4M94.5 35.6h4.6M94.5 33.6v4M100.4 36.7h.5"/>
<path d="M100.4 36.1h.6M157.5 35.6h2M159.6 34.6h6v2h-6zM165.6 35.6h2M198.1 35.6h7.6M198.1 38.1h7.6M86.4 43.2h2M88.4 42.2h6v2h-6zM212.8 41.8a.79 .79 0 0 1 0 1.2M213.7 41.9l.2-.1a.68 .68 0 0 1 .5 .6 .68 .68 0 0 1-.5 .6l-.2-.1-.1-.3zM215.4 41.8h-.3a.86 .86 0 0 0 0 1.2l.4-.1v-.4l-.2-.3-.4 .1-.1 .2M93.5 79.3v4"/>
<path d="M94.5 79.3v4M218.4 73.7h2M220.5 72.7h6v2h-6zM226.6 73.7h2M86.4 91.4h2M86.4 88.9h2M86.4 83.8h2M86.7 85h.5M86.7 84.4h.6M88.4 81.8v4M88.4 90.5h6v2h-6zM88.4 87.9h6v2.1h-6z"/>
<path d="M88.9 96.5h4.6M88.9 81.3h4.6M89.4 81.8v4M89.4 83.8h4.6M93.5 94.5v4M94.5 94.5v4M94.5 96.5h4.6M94.5 81.3h4.6M100.4 97.7h.5M100.4 97.1h.6M100.4 82.5h.5M100.4 81.9h.6"/>
<path d="M154.9 139.7h2M157 138.7h6v2.1h-6zM161.4 139.2l.1-.2v1.3M163.1 139.7h2M59.7 147.3h2.5l1.3 2.6h-5.1zM59.9 153.5h.6M60.3 154l.3 .3v.3l-.3 .2M61 149.9v2.5M66 152.4h2M68.1 151.4h6v2.1h-6zM72.3 153h.7M72.5 151.9l.1-.2v1.3"/>
<path d="M74.2 152.4h2M80 147.3h2.5l1.3 2.6h-5.1zM81.3 149.9v2.5M85.3 153.5h.6M85.8 154l.2 .3v.3l-.2 .2M161.2 140.3h.7M244.4 146.8h4M244.4 147.8h4M246.4 142.2v2.6M246.4 147.8v4.6M252.9 159.6h2.1v6h-2.1zM253 144.3h2.1v6h-2.1z"/>
<path d="M253.3 145.1l.7 .7M254 142.2v2M254 150.4v2M254 157.5v2M254.6 145.1l-.7 .6M253.7 160.2l.5 .5M254 165.6v2M254.6 160.2l-.5 .3M67.3 180.3h2.5zM67.3 180.3v5.1zM67.3 185.4h2.5zM68.6 185.4v2.6"/>
<path d="M69.8 180.3v5.1zM77 183.9l.3 .2v.6M94.2 183.9h.5M94.7 183.5h-.2M97.8 180.3h2.5zM97.8 180.3v5.1zM97.8 185.4h2.5zM99.1 185.4v2.6M100.3 180.3v5.1zM107.5 183.9l.3 .2v.6M124.7 183.9h.5M125.2 183.5h-.3"/>
</g>
<g fill="none" stroke="#ff2626" stroke-width=".46">
<path d="M84.6 35.6l8.6 5M89.7 33l8.6 5.1M93.2 35.6l-8.6 5M98.3 33l-8.6 5.1M158.1 34.2l9 2.8M167.1 34.2l-9 2.8M200.9 31.6l14.7 10.5M215.6 31.6l-14.7 10.5M86.9 41.8l9 2.9M95.9 41.8l-9 2.9M89.7 78.8l8.6 5M98.3 78.8l-8.6 5"/>
<path d="M219 72.3l9 2.8M228 72.3l-9 2.8M84.6 81.3l8.6 5M86.9 90l9 2.9M86.9 87.5l9 2.9M89.7 94l8.6 5M93.2 81.3l-8.6 5M95.9 90l-9 2.9M95.9 87.5l-9 2.9M98.3 94l-8.6 5M155.5 138.3l9 2.9M164.5 138.3l-9 2.9"/>
<path d="M57.5 145.6l6.9 6M64.4 145.6l-6.9 6M66.6 151l9 2.9M75.6 151l-9 2.9M77.9 145.6l6.8 6M84.7 145.6l-6.8 6M243.5 143l5.8 8.6M249.3 143l-5.8 8.6M252.2 158.1l3.5 9M252.3 142.8l3.5 9M255.7 158.1l-3.5 9M255.8 142.8l-3.5 9"/>
<path d="M66.4 178.6l4.3 8.6M70.7 178.6l-4.3 8.6M96.9 178.6l4.3 8.6M101.2 178.6l-4.3 8.6"/>
</g>
<g fill="none" stroke="#840000" stroke-width=".18">
<path d="M195.6 40.6v1.3h-1.3l1.3 1.3 1.2-1.3h-1.2M195.6 40.6h.1M33 134.6v1.3h-1.3l1.3 1.3 1.3-1.3h-1.3M33 134.6h.1M61 134.6v1.3h-1.3l1.3 1.3 1.2-1.3h-1.2M61 134.6h.1M152.4 139.7v2.5M167.6 139.7v2.5M170.2 138.4l1-.6-1-.6-1 .6 1 .6v1.3M170.2 139.7h.1M91.4 151.1l1.1-.6-1.1-.6-1 .6 1 .6v1.3M91.4 152.4h.1"/>
<path d="M259.6 146.8h4M259.6 147.8h4M261.6 154.9v1.3h1.3l-1.3 1.3-1.3-1.3h1.3M261.6 154.9h.1M261.6 142.2v4.6M261.6 147.8v4.6M267.2 146.8h4M267.2 147.8h4M269.2 154.9v1.3h1.3l-1.3 1.3-1.2-1.3h1.2M269.2 154.9h.1M269.2 142.2v4.6M269.2 147.8v4.6"/>
<path d="M274.9 146.8h4M274.9 147.8h4M276.9 154.9v1.3h1.2l-1.2 1.3-1.3-1.3h1.3M276.9 154.9h.1M276.9 142.2v4.6M276.9 147.8v4.6M254 167.6v1.3h1.3l-1.3 1.3-1.3-1.3h1.3M254 167.6h.1M38.1 188v1.2h1.3l-1.3 1.3-1.3-1.3h1.3M38.1 188h.1M68.6 188v1.2h1.2l-1.2 1.3-1.3-1.3h1.3M68.6 188h.1"/>
<path d="M99.1 188v1.2h1.2l-1.2 1.3-1.3-1.3h1.3M99.1 188h.1"/>
</g>
<path d="M195.6 30.5v2.5M279.4 134.6v2.6M101.6 147.3v2.6" fill="none" stroke="#840000" stroke-width=".25"/>
<path d="M280.9 132.7h.8l-.4 .4M281.5 133.1l.2 .3v.3l-.2 .2M153.8 146.6h.7M282.2 145.9h.7" fill="none" stroke="#008484" stroke-width=".18"/>
<g fill="none" stroke="#000" stroke-width=".18">
<circle cx="152.4" cy="143.5" r="1.27"/>
<circle cx="167.6" cy="143.5" r="1.27"/>
</g>
<path d="M244.5 78.1h3.8l-1.9 3.2z" fill="#a1a1a1"/>
<path d="M247.6 81.3h-2.5l-1.3 1.3" fill="none" stroke="#a1a1a1" stroke-width=".18"/>
<path d="M246.4 81.3l1.9 3.2h-3.8z" fill="#a1a1a1"/>
<g fill="none" stroke="#a1a1a1" stroke-width=".18">
<path d="M233.7 30.5h5.1v5.1h-5.1zM236.2 29.8h.7M236.2 35.6v2.5M240.1 36.1h.8l-.4 .5M240.7 36.6l.2 .3v.3l-.2 .2M246.4 73.7v4.4M218.4 91.4h5.1M223.5 94v2.5M242.8 80.9h.9M243.3 80.7v.8M246.4 84.5v4.4M248.9 80l-1.3 1.3"/>
<path d="M36.8 180.3h2.6zM36.8 180.3v5.1zM36.8 185.4h2.6zM38.1 185.4v2.6M39.4 180.3v5.1zM46.5 183.9l.4 .2v.6M63.7 183.9h.5M64.2 183.5h-.2"/>
<circle cx="223.5" cy="91.4" r="2.54"/>
</g>
<path d="M232.8 28.7l6.8 8.6M239.6 28.7l-6.8 8.6M242.4 75.2l8 12.2M250.4 75.2l-8 12.2M219.2 87.1l8.6 8.6M227.8 87.1l-8.6 8.6M36 178.6l4.2 8.6M40.2 178.6l-4.2 8.6" fill="none" stroke="#ff2626" stroke-width=".46"/>
<circle cx="223.5" cy="91.4" r=".63" fill="#a1a1a1" stroke="#a1a1a1" stroke-width=".18"/>
<path d="M149.9 134.6v2.6" fill="none" stroke="#840000" stroke-width=".25"/>
<path d="M236.2 40.6v1.3h1.3l-1.3 1.3-1.3-1.3h1.3M236.2 40.6h.1M256.5 78.7v1.3h-1.2l1.2 1.3 1.3-1.3h-1.3M256.5 78.7h.1M223.5 96.5v1.3h-1.3l1.3 1.3 1.3-1.3h-1.3M223.5 96.5h.1M246.4 88.9v1.3h1.2l-1.2 1.2-1.3-1.2h1.3M246.4 88.9h.1M213.4 106.7v1.3h1.2l-1.2 1.2-1.3-1.2h1.3M213.4 106.7h.1" fill="none" stroke="#840000" stroke-width=".18"/>
<circle cx="236.2" cy="33" r="1.27" fill="none" stroke="#808080" stroke-width=".18"/>
<path d="M211.5 95.9h3.8l-1.9 3.2z" fill="#a1a1a1"/>
<path d="M214.6 99.1h-2.5l-1.3 1.2" fill="none" stroke="#a1a1a1" stroke-width=".18"/>
<path d="M213.4 99.1l1.9 3.1h-3.8z" fill="#a1a1a1"/>
<g fill="none" stroke="#a1a1a1" stroke-width=".18">
<path d="M188 91.4h2M190 90.5h6v2h-6zM196.1 91.4h2M209.8 98.7h.9M210.3 98.5v.8M213.4 91.4v4.5M215.9 97.8l-1.3 1.3M213.4 102.2v4.5M190.5 139.7h2.5a1.27 1.27 0 0 1 1.3-1.3 1.27 1.27 0 0 1 1.3 1.3 1.27 1.27 0 0 1 1.2-1.3 1.27 1.27 0 0 1 1.3 1.3 1.27 1.27 0 0 1 1.3-1.3 1.27 1.27 0 0 1 1.3 1.3 1.27 1.27 0 0 1 1.2-1.3 1.27 1.27 0 0 1 1.3 1.3h2.5M193 137.2h10.2M193 137.7h10.2M173.3 146.8h4"/>
<path d="M173.3 147.8h4M175.3 142.2v4.6M175.3 147.8v4.6M180.9 146.8h4M180.9 147.8h4M182.9 142.2v4.6M182.9 147.8v4.6M188.1 144.6h.9l-.6 1.3M193 149.9h2M195.1 148.8h6v2h-6zM201.2 149.9h2"/>
</g>
<path d="M188.5 90l9 2.9M197.5 90l-9 2.9M209.4 93l7.9 12.1M217.3 93l-7.9 12.1M191.3 136.6l13.7 3.6M205 136.6l-13.7 3.6M172.4 143l5.7 8.6M178.1 143l-5.7 8.6M180 143l5.8 8.6M185.8 143l-5.8 8.6M193.6 148.4l9 2.9M202.6 148.4l-9 2.9" fill="none" stroke="#ff2626" stroke-width=".46"/>
<path d="M175.3 154.9v1.3h1.2l-1.2 1.3-1.3-1.3h1.3M175.3 154.9h.1M182.9 154.9v1.3h1.2l-1.2 1.3-1.3-1.3h1.3M182.9 154.9h.1M236.2 154.9v1.3h1.3l-1.3 1.3-1.3-1.3h1.3M236.2 154.9h.1" fill="none" stroke="#840000" stroke-width=".18"/>
<path d="M213.4 137.2h15.2v15.2h-15.2z" fill="#f0f0f0"/>
<path d="M213.4 137.2h15.2v15.2h-15.2z" fill="none" stroke="#9f9f9f" stroke-width=".18"/>
<g fill="none" stroke="#a1a1a1" stroke-width=".18">
<path d="M33 38.1h7.6M33 30.5h7.6M33 33h7.6M33 35.6h7.6M50.8 38.1h7.6M50.8 30.5h7.6M50.8 33h7.6M50.8 35.6h7.6M86.6 37.4h.7M86.7 39.3h.5M86.7 38.7h.6M88.9 35.6h2.5"/>
<path d="M91.4 38.1h2.6M96.5 35.6h2.6M100.4 36.7h.5M100.4 36.1h.6M198.1 38.1h7.6M198.1 35.6h7.6M264.2 38.1h2M266.2 37h6v2.1h-6zM272.3 38.1h2M33 40.6h7.6M33 43.2h7.6M33 45.7h7.6"/>
<path d="M33 48.3h7.6M33 50.8h7.6M33 53.3h7.6M33 55.9h7.6M33 58.4h7.6M42.7 43.8h.7M42.7 56.5h.7M50.8 40.6h7.6M50.8 43.2h7.6M50.8 45.7h7.6M50.8 48.3h7.6M50.8 50.8h7.6"/>
<path d="M50.8 53.3h7.6M50.8 55.9h7.6M50.8 58.4h7.6M86.4 43.2h2M86.4 45.7h2M86.4 58.4h2M86.7 54.5h.5M86.7 53.9h.6M88.9 50.8h2.5M91.4 53.3h2.6M97.4 58.3h.7M100.4 52h.5"/>
<path d="M100.4 51.4h.6M212.8 41.8a.79 .79 0 0 1 0 1.2M213.7 41.9l.2-.1a.68 .68 0 0 1 .5 .6 .68 .68 0 0 1-.5 .6l-.2-.1-.1-.3zM215.4 41.8h-.3a.86 .86 0 0 0 0 1.2l.4-.1v-.4l-.2-.3-.4 .1-.1 .2M33 61h7.6M33 63.5h7.6M33 66h7.6M33 68.6h7.6M33 71.1h7.6M33 73.7h7.6M33 76.2h7.6M33 78.7h7.6"/>
<path d="M42.7 69.2h.7M50.8 61h7.6M50.8 63.5h7.6M50.8 66h7.6M50.8 68.6h7.6M50.8 71.1h7.6M50.8 73.7h7.6M50.8 76.2h7.6M50.8 78.7h7.6M86.4 61h2M86.4 73.7h2M86.4 76.2h2"/>
<path d="M86.7 69.2h.6M86.7 69.8h.5M88.9 66h2.5M91.4 68.6h2.6M96.5 66h2.6M100.4 67.2h.5M100.4 66.6h.6M246.4 73.7v4.4M251.5 73.7h5M256.5 76.2v2.5M33 81.3h7.6M33 83.8h7.6"/>
<path d="M33 86.4h7.6M33 88.9h7.6M33 91.4h7.6M33 94h7.6M33 96.5h7.6M33 99.1h7.6M42.7 81.9h.7M42.7 94.6h.7M50.8 81.3h7.6M50.8 83.8h7.6M50.8 86.4h7.6M50.8 88.9h7.6"/>
<path d="M50.8 91.4h7.6M50.8 94h7.6M50.8 96.5h7.6M50.8 99.1h7.6M86.4 88.9h2M86.4 91.4h2M86.7 99.6h.6M86.7 85h.5M86.7 84.4h.6M88.9 81.3h2.5M88.9 96.5h2.5M91.4 83.8h2.6"/>
<path d="M91.4 99.1h2.6M96.5 81.3h2.6M96.5 96.5h2.6M100.4 81.9h.6M100.4 97.7h.5M100.4 97.1h.6M100.4 82.5h.5M209.8 98.7h.9M210.3 98.5v.8M213.4 91.4v4.5M218.4 91.4h5.1M223.5 94v2.5"/>
<path d="M242.8 80.9h.9M243.3 80.7v.8M246.4 84.5v4.4M33 101.6h7.6M33 114.3h7.6M33 116.8h7.6M33 119.4h7.6M42.7 120h.7M50.8 101.6h7.6M50.8 114.3h7.6M50.8 116.8h7.6M50.8 119.4h7.6"/>
<path d="M86.7 100.2h.5M213.4 102.2v4.5M33 121.9h7.6M33 129.5h7.6M33 124.5h7.6M50.8 121.9h7.6M50.8 129.5h7.6M154.9 139.7h2M161.4 139.2l.1-.2v1.3M163.1 139.7h2M190.5 139.7h2.5M203.2 139.7h10.2"/>
<path d="M228.6 139.7h7.6M161.2 140.3h.7M175.3 142.2v2.6M175.3 149.9v2.5M182.9 142.2v2.6M182.9 149.9v2.5M188.1 144.6h.9l-.6 1.3M205.7 144.8h7.7M205.7 149.9h7.7M221.9 153.5h.8l-.4 .5 .4 .1v.5l-.2 .2h-.4M228.6 144.8h7.6M228.6 149.9h7.6"/>
<path d="M254 157.5v2M253.7 160.2l.5 .5M254 165.6v2M254.6 160.2l-.5 .3M38.1 185.4v2.6M46.5 183.9l.4 .2v.6M63.7 183.9h.5M64.2 183.5h-.2M68.6 185.4v2.6M77 183.9l.3 .2v.6M94.2 183.9h.5M94.7 183.5h-.2"/>
<path d="M99.1 185.4v2.6M107.5 183.9l.3 .2v.6M124.7 183.9h.5M125.2 183.5h-.3"/>
</g>
<g fill="none" stroke="#ff2626" stroke-width=".46">
<path d="M35.8 26.5l19.8 107M55.6 26.5l-19.8 107M84.6 35.6l8.6 5M89.7 33l8.6 5.1M93.2 35.6l-8.6 5M98.3 33l-8.6 5.1M200.9 31.6l14.7 10.5M215.6 31.6l-14.7 10.5M264.7 36.6l9 2.9M273.7 36.6l-9 2.9M84.6 50.8l8.6 5.1M86.9 44.3l9 2.9"/>
<path d="M86.9 41.8l9 2.9M86.9 59.6l9 2.8M86.9 57l9 2.9M89.7 48.3l8.6 5M93.2 50.8l-8.6 5.1M95.9 44.3l-9 2.9M95.9 41.8l-9 2.9M95.9 59.6l-9 2.8M95.9 57l-9 2.9M98.3 48.3l-8.6 5M84.6 66.1l8.6 5M86.9 74.8l9 2.9"/>
<path d="M86.9 72.3l9 2.8M89.7 78.8l8.6 5M89.7 63.5l8.6 5.1M93.2 66.1l-8.6 5M95.9 74.8l-9 2.9M95.9 72.3l-9 2.8M98.3 78.8l-8.6 5M98.3 63.5l-8.6 5.1M242.4 75.2l8 12.2M250.4 75.2l-8 12.2M252.2 69.4l8.6 8.6M260.8 69.4l-8.6 8.6"/>
<path d="M84.6 96.5l8.6 5.1M84.6 81.3l8.6 5M86.9 87.5l9 2.9M86.9 90l9 2.9M89.7 94l8.6 5M93.2 96.5l-8.6 5.1M93.2 81.3l-8.6 5M95.9 87.5l-9 2.9M95.9 90l-9 2.9M98.3 94l-8.6 5M209.4 93l7.9 12.1M217.3 93l-7.9 12.1"/>
<path d="M219.2 87.1l8.6 8.6M227.8 87.1l-8.6 8.6M155.5 138.3l9 2.9M164.5 138.3l-9 2.9M191.3 136.6l13.7 3.6M205 136.6l-13.7 3.6M208.6 135.7l24.8 18.2M233.4 135.7l-24.8 18.2M172.4 143l5.7 8.6M178.1 143l-5.7 8.6M180 143l5.8 8.6M185.8 143l-5.8 8.6"/>
<path d="M252.2 158.1l3.5 9M255.7 158.1l-3.5 9M36 178.6l4.2 8.6M40.2 178.6l-4.2 8.6M66.4 178.6l4.3 8.6M70.7 178.6l-4.3 8.6M96.9 178.6l4.3 8.6M101.2 178.6l-4.3 8.6"/>
</g>
<path d="M276.9 33v2.6" fill="none" stroke="#840000" stroke-width=".25"/>
<path d="M278.4 31.1h.8l-.5 .4M278.9 31.5l.3 .3v.3l-.3 .2M153.8 146.6h.7M282.2 145.9h.7" fill="none" stroke="#008484" stroke-width=".18"/>
<path d="M129.5 29.8h.7l.6 .7-.6 .6h-.7zM130.2 27.3h.6v1.3h-.6l-.7-.7zM153.7 34.9h.6l.6 .7-.6 .6h-.6zM170.2 34.9h.6l.6 .7-.6 .6h-.6zM261 37.5h.6v1.2h-.6l-.7-.6zM199.4 73.7l.6-.7 .7 .7-.7 .6zM116.8 95.9h.7l.6 .6-.6 .7h-.7zM116.8 98.4h.7l.6 .7-.6 .6h-.7zM168.9 91.4l.6-.6 .7 .6-.7 .7zM116.8 106h.7l.6 .7-.6 .6h-.7z" fill="none" stroke="#848400" stroke-width=".18"/>
<path d="M50.4 150.6l.2 .3-.1 .3-.7 .7h.8" fill="none" stroke="#000" stroke-width=".18"/>
<path d="M142.2 12.7v185.4M182.9 10.2v48.2M223.5 10.2v48.2M248.9 12.7v45.7M142.2 58.4h142.3M142.2 119.4h142.3M12.7 167.6h129.5" fill="none" stroke="#0000c2" stroke-width=".18" stroke-dasharray="1.4 .5"/>
<path d="M129.5 27.9h-5v53.4M129.5 30.5h-10.1v58.4" fill="none" stroke="#000084" stroke-width=".25"/>
<g fill="none" stroke="#008400" stroke-width=".18">
<path d="M27.9 35.6h5.1M33 33h-5.1v119.4h38.1M58.4 30.5h2.6v104.1M58.4 38.1h25.4M58.4 35.6h30.5M58.4 33h2.6M124.5 35.6l-2.6 2.5h-27.9M124.5 33l-2.6 2.6h-22.8M154.9 35.6h2.6M167.6 35.6h2.6M195.6 33v2.6h2.5M198.1 38.1h-2.5v2.5"/>
<path d="M236.2 38.1v2.5M261.6 38.1h2.6M276.9 35.6v2.5h-2.6M27.9 48.3h5.1M27.9 53.3h5.1M27.9 50.8h5.1M27.9 45.7h5.1M58.4 40.6h2.6M58.4 48.3h2.6M58.4 53.3h25.4M58.4 50.8h30.5M58.4 58.4h28"/>
<path d="M58.4 43.2h28M58.4 45.7h28M58.4 55.9h2.6M119.4 58.4l-2.6 2.6h-20.3M119.4 55.9l-2.6 2.5h-20.3M119.4 40.6l-2.6 2.6h-20.3M119.4 43.2l-2.6 2.5h-20.3M124.5 50.8l-2.6 2.5h-27.9M124.5 48.3l-2.6 2.5h-22.8M58.4 66h30.5M58.4 68.6h25.4M58.4 73.7h28"/>
<path d="M58.4 76.2h28M58.4 61h28M58.4 71.1h2.6M58.4 78.7h2.6M58.4 63.5h2.6M119.4 71.1l-2.6 2.6h-20.3M119.4 73.7l-2.6 2.5h-20.3M124.5 78.7l-2.6 2.6h-22.8M124.5 63.5l-2.6 2.5h-22.8M124.5 66l-2.6 2.6h-27.9M200.7 73.7h17.7M228.6 73.7h22.9"/>
<path d="M15.2 91.4h17.8M58.4 83.8h25.4M58.4 91.4h28M58.4 88.9h28M58.4 81.3h30.5M58.4 99.1h25.4M58.4 96.5h30.5M58.4 86.4h2.6M58.4 94h2.6M94 99.1h22.8M99.1 96.5h17.7M119.4 88.9l-2.6 2.5h-20.3"/>
<path d="M119.4 86.4l-2.6 2.5h-20.3M124.5 81.3l-2.6 2.5h-27.9M170.2 91.4h17.8M198.1 91.4h20.3M27.9 119.4h5.1M27.9 116.8h5.1M58.4 119.4h2.6M58.4 101.6h2.6M58.4 116.8h2.6M68.6 106.7h17.8M96.5 106.7h20.3M27.9 121.9h5.1"/>
<path d="M33 129.5v5.1M58.4 121.9h2.6M58.4 129.5h2.6M149.9 137.2v2.5h5M165.1 139.7h25.4v10.2h2.5M175.3 139.7v2.5M182.9 139.7v2.5M246.4 139.7v2.5M254 139.7v2.5M261.6 139.7v2.5M269.2 139.7v2.5M276.9 139.7v2.5"/>
<path d="M279.4 137.2v2.5h-43.2M101.6 149.9v2.5h-25.4M175.3 152.4v2.5M182.9 152.4v2.5M190.5 144.8h15.2M203.2 149.9h2.5M236.2 149.9v5M236.2 144.8h5.1v10.1h12.7M246.4 152.4v2.5M254 152.4v5.1M261.6 152.4v2.5M269.2 152.4v2.5"/>
<path d="M276.9 152.4v2.5"/>
</g>
<g fill="none" stroke="#000084" stroke-width=".18">
<path d="M32.4 37.5l1.2 1.2M32.4 29.9l1.2 1.2M33.6 37.5l-1.2 1.2M33.6 29.9l-1.2 1.2M32.4 40l1.2 1.2M32.4 42.6l1.2 1.2M32.4 57.8l1.2 1.2M32.4 55.3l1.2 1.2M33.6 40l-1.2 1.2M33.6 42.6l-1.2 1.2M33.6 57.8l-1.2 1.2M33.6 55.3l-1.2 1.2"/>
<path d="M32.4 62.9l1.2 1.2M32.4 75.6l1.2 1.2M32.4 65.4l1.2 1.2M32.4 78.1l1.2 1.2M32.4 73.1l1.2 1.2M32.4 70.5l1.2 1.2M32.4 68l1.2 1.2M32.4 60.4l1.2 1.2M33.6 62.9l-1.2 1.2M33.6 75.6l-1.2 1.2M33.6 65.4l-1.2 1.2M33.6 78.1l-1.2 1.2"/>
<path d="M33.6 73.1l-1.2 1.2M33.6 70.5l-1.2 1.2M33.6 68l-1.2 1.2M33.6 60.4l-1.2 1.2M32.4 88.3l1.2 1.2M32.4 80.7l1.2 1.2M32.4 93.4l1.2 1.2M32.4 85.8l1.2 1.2M32.4 98.5l1.2 1.2M32.4 95.9l1.2 1.2M32.4 83.2l1.2 1.2M33.6 88.3l-1.2 1.2"/>
<path d="M33.6 80.7l-1.2 1.2M33.6 93.4l-1.2 1.2M33.6 85.8l-1.2 1.2M33.6 98.5l-1.2 1.2M33.6 95.9l-1.2 1.2M33.6 83.2l-1.2 1.2M32.4 113.7l1.2 1.2M32.4 101l1.2 1.2M33.6 113.7l-1.2 1.2M33.6 101l-1.2 1.2M57.8 113.7l1.2 1.2M59 113.7l-1.2 1.2"/>
<path d="M32.4 123.9l1.2 1.2M33.6 123.9l-1.2 1.2"/>
</g>
<g fill="none" stroke="#0000c2" stroke-width=".18">
<path d="M102.8 112.6l-.2 .1M103.3 113.2l-.8 .7h.8M106 116.4h.7M106.2 115.3l-.2 .2M226 167.4l.3 .1M226.1 170.2v1l-.2 .3-.3-.1M226.1 170.3l-.4-.1-.2 .2 .1 .6h.5M226.3 167.2v.3M226.3 167.5l-.1 .3M226.3 167.5l.2 .3M226.6 167.4l-.3 .1M226.8 171l-.2 .2"/>
<path d="M227.2 167.3l.2-.1a.68 .68 0 0 1 .4 .7 .68 .68 0 0 1-.4 .6l-.2-.1-.1-.4zM228.3 168.4v.1M229.5 167.2l-.4 .1a.86 .86 0 0 0 0 1.2l.5-.1v-.4l-.2-.3h-.3l-.2 .3M245.5 169.8v.1M245.5 170.2v.8M246.7 170.2v1l-.3 .3-.3-.1M246.7 170.3l-.4-.1-.2 .2 .1 .6h.5"/>
</g>
<g fill="none" stroke="#0000c2" stroke-width=".38">
<path d="M15.9 17v-1.9l.7 1.3 .6-1.3v1.9M18.9 15.2l.3-.1h.5l.2 .1M22.3 15.1v1.9M23.4 15.1l-1.1 1M28.7 17v-1.9l.7 1.3 .6-1.3v1.9M32.5 16.7a.69 .69 0 0 0 .9 .2M33.5 15.2a.66 .66 0 0 0-1 .1M42.7 15.1v1.6M48.1 16.2h1.5M53 15.2a.77 .77 0 0 0-.9 0 .77 .77 0 0 0-.2 .9 .71 .71 0 0 0 .3 .8 .71 .71 0 0 0 .8-.1M53.9 15.7v1l.1 .2 .4 .1M57.1 15.1v1.6"/>
<path d="M64.9 15.2l-.2-.1h-.8v1.9M65.8 15.1v.1M65.8 15.7v1.3M65.8 15.1l-.1 .1h.1M65.8 15.1l.1 .1h-.1M66.7 15.7v1.3M67.3 15.7l-.6 .2M71.9 15.1v1.6M146.5 15.2l-.3-.1h-.7v1.9M150.3 15.1v1.9M156.2 15.2a.66 .66 0 0 0-1 .1M187 15.1h-.9v1.9"/>
<path d="M193.7 15.2a.66 .66 0 0 0-1 .1M203 15.1v1.6M227.8 15.2a.69 .69 0 0 0-.9 .1M235.8 15.1v1.9M238.2 15.1v1.9M251.9 15.1l.6 1.9 .7-1.9M256.7 15.1l-.1 .1h.1M256.7 15.1l.1 .1h-.1M256.7 15.1v.1M260.8 15.7h.7M261.1 15.1v1.6M261.1 16.9l.4 .1"/>
<path d="M264.6 15.2l-.3-.1h-.7v1.9M265.5 15.1l-.1 .1h.1M265.5 15.1l.1 .1h-.1M265.5 15.1v.1M269.5 16.9l.3 .1M270.6 15.2l-.3-.1-.6 .1a.43 .43 0 0 0-.1 .6M271.4 15.1v1.6M146.5 61l-.3-.2h-.7v1.9M149.5 60.8l-.4 .1-.1 .2M151.7 60.8v1.6M156.1 60.8v1.9M156.3 62l.5 .7"/>
<path d="M156.8 61.4l-.7 .7M163.4 60.8v1.9M165.6 62.6l.3 .1M166.7 60.9l-.3-.1-.6 .1a.43 .43 0 0 0-.1 .6M173.8 61.7h.6M174.4 61.7l.3 .1M174.7 61l-.3-.2h-.6v1.9l.9-.1M174.7 61.5l-.3 .2M176.8 60.8v1.9l-1.1-1.9v1.9M178.8 61a.66 .66 0 0 0-1 .1M146.4 121.7h-.9l-.1 .9M147 121.7l.7 1.9 .6-1.9"/>
<path d="M148.7 121.7h1.2l-.6 .8M153.1 121.9l-.3-.2h-.6v1.9M159.1 121.7v1.7M162.7 121.9a.77 .77 0 0 0-.9 0 .77 .77 0 0 0-.3 .9l.2 .6M171.2 121.7v1.7M15.9 170v1.9M18.6 170v1.6M29.6 170.6l-.3 .1-.2 .3M32.7 170.1l-.7-.1-.3 .2M33.5 170v1.6M38.9 170v1.9M42 170l-.4 .1-.1 .2"/>
<path d="M43.1 170l-.4 .1-.1 .2"/>
</g>
<g fill="none" stroke="#0000c2" stroke-width=".25">
<path d="M50.9 159.1h.7M60.6 159.6h.5M61 159.9h-.3l-.2 .1 .1 .3h.4M68.8 159.6l.4-.1 .2 .2M68.8 159.5v.8M69.4 159.7v.6M69.9 159.6l-.4-.1-.1 .2M75.9 159.5h-.2l-.2 .2v.6h.4M76.1 159.8l-.6 .1M79.6 159.5l-.3 .1-.1 .1 .1 .5 .3 .1M87.9 159.6l.2 .1-.2 .6M92.6 159.5h-.2l-.2 .2 .1 .6h.3"/>
<path d="M92.8 159.8l-.6 .1M97.3 159.1l.4 1.2 .5-1.2M98.6 159.1v1M99.3 159.1v1M100.6 159.1h-.5l-.3 .2M101.1 159.7h.4M101.5 159.1h-.4v1.2h.5M115.1 159.1l.4 1.2 .4-1.2"/>
</g>
<g fill="none" stroke="#840000" stroke-width=".18">
<path d="M195.6 40.6h.1M256.5 78.7h.1M223.5 96.5h.1M246.4 88.9h.1M213.4 106.7h.1M33 134.6h.1M152.4 139.7v2.5M167.6 139.7v2.5M170.2 139.7h.1M236.2 154.9h.1M261.6 142.2v2.6M261.6 149.9v2.5"/>
<path d="M269.2 142.2v2.6M269.2 149.9v2.5M276.9 142.2v2.6M276.9 149.9v2.5M254 167.6h.1M38.1 188h.1M68.6 188h.1M99.1 188h.1"/>
</g>
<g fill="#008400" stroke="#008400" stroke-width=".18">
<circle cx="27.9" cy="48.3" r=".46"/>
<circle cx="27.9" cy="53.3" r=".46"/>
<circle cx="27.9" cy="50.8" r=".46"/>
<circle cx="27.9" cy="35.6" r=".46"/>
<circle cx="61" cy="33" r=".46"/>
<circle cx="61" cy="40.6" r=".46"/>
<circle cx="27.9" cy="45.7" r=".46"/>
<circle cx="61" cy="129.5" r=".46"/>
<circle cx="61" cy="152.4" r=".46"/>
<circle cx="27.9" cy="119.4" r=".46"/>
<circle cx="27.9" cy="116.8" r=".46"/>
<circle cx="27.9" cy="121.9" r=".46"/>
<circle cx="61" cy="116.8" r=".46"/>
<circle cx="61" cy="71.1" r=".46"/>
<circle cx="61" cy="63.5" r=".46"/>
<circle cx="61" cy="86.4" r=".46"/>
<circle cx="61" cy="78.7" r=".46"/>
<circle cx="61" cy="101.6" r=".46"/>
<circle cx="61" cy="94" r=".46"/>
<circle cx="61" cy="119.4" r=".46"/>
<circle cx="61" cy="121.9" r=".46"/>
<circle cx="61" cy="48.3" r=".46"/>
<circle cx="61" cy="55.9" r=".46"/>
<circle cx="81.3" cy="152.4" r=".46"/>
<circle cx="91.4" cy="152.4" r=".46"/>
<circle cx="246.4" cy="73.7" r=".46"/>
<circle cx="276.9" cy="139.7" r=".46"/>
<circle cx="269.2" cy="139.7" r=".46"/>
<circle cx="246.4" cy="139.7" r=".46"/>
<circle cx="246.4" cy="154.9" r=".46"/>
<circle cx="254" cy="139.7" r=".46"/>
<circle cx="254" cy="154.9" r=".46"/>
<circle cx="261.6" cy="139.7" r=".46"/>
<circle cx="152.4" cy="139.7" r=".46"/>
<circle cx="167.6" cy="139.7" r=".46"/>
<circle cx="170.2" cy="139.7" r=".46"/>
<circle cx="213.4" cy="91.4" r=".46"/>
<circle cx="190.5" cy="139.7" r=".46"/>
<circle cx="190.5" cy="144.8" r=".46"/>
<circle cx="182.9" cy="139.7" r=".46"/>
</g>
<use href="#words"/>
</svg>
